VERSION 5.8 ;
BUSBITCHARS "[]" ;
DIVIDERCHAR "/" ;
UNITS
    DATABASE MICRONS 1000 ;
END UNITS

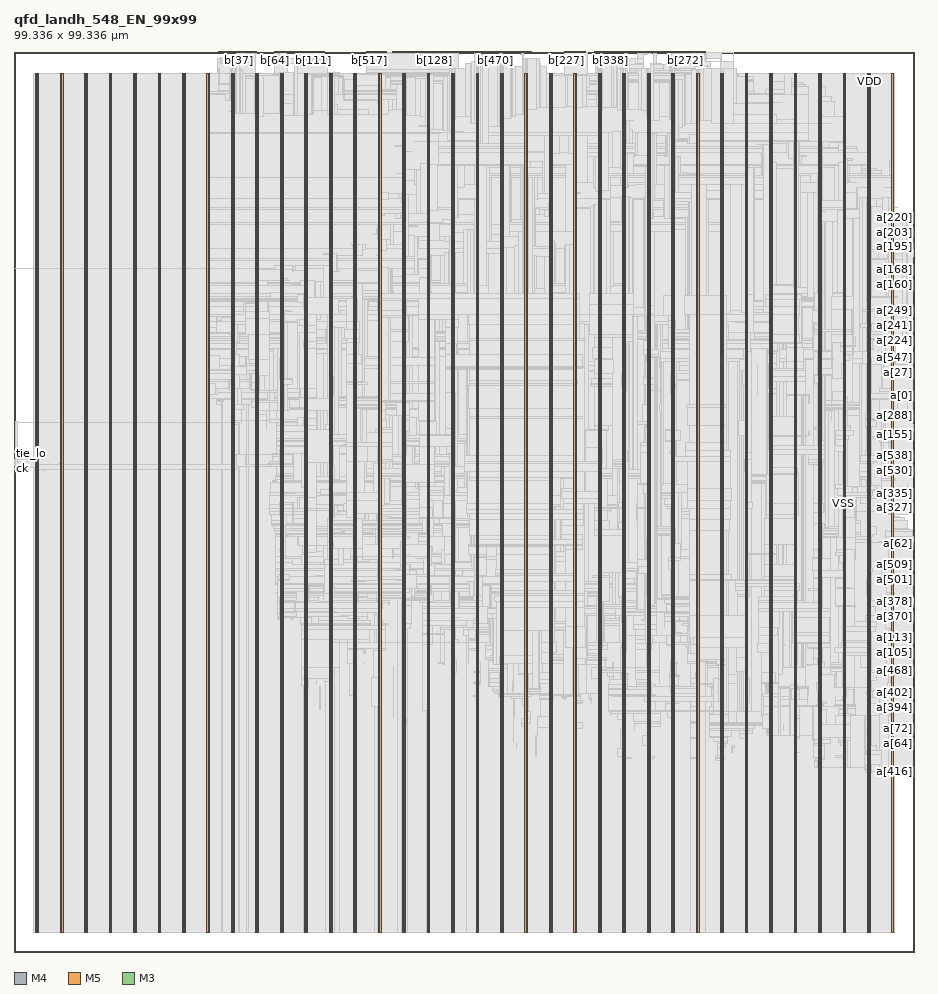
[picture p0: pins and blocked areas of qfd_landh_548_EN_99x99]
MACRO qfd_landh_548_EN_99x99
  FOREIGN qfd_landh_548_EN_99x99 0 0 ;
  CLASS BLOCK ;
  SIZE 99.336 BY 99.336 ;
  PIN a[0]
    DIRECTION INPUT ;
    USE SIGNAL ;
    PORT
      LAYER M4 ;
        RECT  99.252 61.392 99.336 61.416 ;
    END
  END a[0]
  PIN a[100]
    DIRECTION INPUT ;
    USE SIGNAL ;
    PORT
      LAYER M4 ;
        RECT  99.252 32.592 99.336 32.616 ;
    END
  END a[100]
  PIN a[101]
    DIRECTION INPUT ;
    USE SIGNAL ;
    PORT
      LAYER M4 ;
        RECT  99.252 32.688 99.336 32.712 ;
    END
  END a[101]
  PIN a[102]
    DIRECTION INPUT ;
    USE SIGNAL ;
    PORT
      LAYER M4 ;
        RECT  99.252 32.784 99.336 32.808 ;
    END
  END a[102]
  PIN a[103]
    DIRECTION INPUT ;
    USE SIGNAL ;
    PORT
      LAYER M4 ;
        RECT  99.252 32.88 99.336 32.904 ;
    END
  END a[103]
  PIN a[104]
    DIRECTION INPUT ;
    USE SIGNAL ;
    PORT
      LAYER M4 ;
        RECT  99.252 32.976 99.336 33 ;
    END
  END a[104]
  PIN a[105]
    DIRECTION INPUT ;
    USE SIGNAL ;
    PORT
      LAYER M4 ;
        RECT  99.252 33.072 99.336 33.096 ;
    END
  END a[105]
  PIN a[106]
    DIRECTION INPUT ;
    USE SIGNAL ;
    PORT
      LAYER M4 ;
        RECT  99.252 33.168 99.336 33.192 ;
    END
  END a[106]
  PIN a[107]
    DIRECTION INPUT ;
    USE SIGNAL ;
    PORT
      LAYER M4 ;
        RECT  99.252 33.264 99.336 33.288 ;
    END
  END a[107]
  PIN a[108]
    DIRECTION INPUT ;
    USE SIGNAL ;
    PORT
      LAYER M4 ;
        RECT  99.252 33.36 99.336 33.384 ;
    END
  END a[108]
  PIN a[109]
    DIRECTION INPUT ;
    USE SIGNAL ;
    PORT
      LAYER M4 ;
        RECT  99.252 33.456 99.336 33.48 ;
    END
  END a[109]
  PIN a[10]
    DIRECTION INPUT ;
    USE SIGNAL ;
    PORT
      LAYER M4 ;
        RECT  99.252 62.352 99.336 62.376 ;
    END
  END a[10]
  PIN a[110]
    DIRECTION INPUT ;
    USE SIGNAL ;
    PORT
      LAYER M4 ;
        RECT  99.252 33.552 99.336 33.576 ;
    END
  END a[110]
  PIN a[111]
    DIRECTION INPUT ;
    USE SIGNAL ;
    PORT
      LAYER M4 ;
        RECT  99.252 33.648 99.336 33.672 ;
    END
  END a[111]
  PIN a[112]
    DIRECTION INPUT ;
    USE SIGNAL ;
    PORT
      LAYER M4 ;
        RECT  99.252 33.744 99.336 33.768 ;
    END
  END a[112]
  PIN a[113]
    DIRECTION INPUT ;
    USE SIGNAL ;
    PORT
      LAYER M4 ;
        RECT  99.252 33.84 99.336 33.864 ;
    END
  END a[113]
  PIN a[114]
    DIRECTION INPUT ;
    USE SIGNAL ;
    PORT
      LAYER M4 ;
        RECT  99.252 33.936 99.336 33.96 ;
    END
  END a[114]
  PIN a[115]
    DIRECTION INPUT ;
    USE SIGNAL ;
    PORT
      LAYER M4 ;
        RECT  99.252 34.032 99.336 34.056 ;
    END
  END a[115]
  PIN a[116]
    DIRECTION INPUT ;
    USE SIGNAL ;
    PORT
      LAYER M4 ;
        RECT  99.252 34.128 99.336 34.152 ;
    END
  END a[116]
  PIN a[117]
    DIRECTION INPUT ;
    USE SIGNAL ;
    PORT
      LAYER M4 ;
        RECT  99.252 34.224 99.336 34.248 ;
    END
  END a[117]
  PIN a[118]
    DIRECTION INPUT ;
    USE SIGNAL ;
    PORT
      LAYER M4 ;
        RECT  99.252 34.32 99.336 34.344 ;
    END
  END a[118]
  PIN a[119]
    DIRECTION INPUT ;
    USE SIGNAL ;
    PORT
      LAYER M4 ;
        RECT  99.252 34.416 99.336 34.44 ;
    END
  END a[119]
  PIN a[11]
    DIRECTION INPUT ;
    USE SIGNAL ;
    PORT
      LAYER M4 ;
        RECT  99.252 62.448 99.336 62.472 ;
    END
  END a[11]
  PIN a[120]
    DIRECTION INPUT ;
    USE SIGNAL ;
    PORT
      LAYER M4 ;
        RECT  99.252 34.512 99.336 34.536 ;
    END
  END a[120]
  PIN a[121]
    DIRECTION INPUT ;
    USE SIGNAL ;
    PORT
      LAYER M4 ;
        RECT  99.252 34.608 99.336 34.632 ;
    END
  END a[121]
  PIN a[122]
    DIRECTION INPUT ;
    USE SIGNAL ;
    PORT
      LAYER M4 ;
        RECT  99.252 34.704 99.336 34.728 ;
    END
  END a[122]
  PIN a[123]
    DIRECTION INPUT ;
    USE SIGNAL ;
    PORT
      LAYER M4 ;
        RECT  99.252 34.8 99.336 34.824 ;
    END
  END a[123]
  PIN a[124]
    DIRECTION INPUT ;
    USE SIGNAL ;
    PORT
      LAYER M4 ;
        RECT  99.252 34.896 99.336 34.92 ;
    END
  END a[124]
  PIN a[125]
    DIRECTION INPUT ;
    USE SIGNAL ;
    PORT
      LAYER M4 ;
        RECT  99.252 34.992 99.336 35.016 ;
    END
  END a[125]
  PIN a[126]
    DIRECTION INPUT ;
    USE SIGNAL ;
    PORT
      LAYER M4 ;
        RECT  99.252 35.088 99.336 35.112 ;
    END
  END a[126]
  PIN a[127]
    DIRECTION INPUT ;
    USE SIGNAL ;
    PORT
      LAYER M4 ;
        RECT  99.252 35.184 99.336 35.208 ;
    END
  END a[127]
  PIN a[128]
    DIRECTION INPUT ;
    USE SIGNAL ;
    PORT
      LAYER M4 ;
        RECT  99.252 54.48 99.336 54.504 ;
    END
  END a[128]
  PIN a[129]
    DIRECTION INPUT ;
    USE SIGNAL ;
    PORT
      LAYER M4 ;
        RECT  99.252 54.576 99.336 54.6 ;
    END
  END a[129]
  PIN a[12]
    DIRECTION INPUT ;
    USE SIGNAL ;
    PORT
      LAYER M4 ;
        RECT  99.252 62.544 99.336 62.568 ;
    END
  END a[12]
  PIN a[130]
    DIRECTION INPUT ;
    USE SIGNAL ;
    PORT
      LAYER M4 ;
        RECT  99.252 54.672 99.336 54.696 ;
    END
  END a[130]
  PIN a[131]
    DIRECTION INPUT ;
    USE SIGNAL ;
    PORT
      LAYER M4 ;
        RECT  99.252 54.768 99.336 54.792 ;
    END
  END a[131]
  PIN a[132]
    DIRECTION INPUT ;
    USE SIGNAL ;
    PORT
      LAYER M4 ;
        RECT  99.252 54.864 99.336 54.888 ;
    END
  END a[132]
  PIN a[133]
    DIRECTION INPUT ;
    USE SIGNAL ;
    PORT
      LAYER M4 ;
        RECT  99.252 54.96 99.336 54.984 ;
    END
  END a[133]
  PIN a[134]
    DIRECTION INPUT ;
    USE SIGNAL ;
    PORT
      LAYER M4 ;
        RECT  99.252 55.056 99.336 55.08 ;
    END
  END a[134]
  PIN a[135]
    DIRECTION INPUT ;
    USE SIGNAL ;
    PORT
      LAYER M4 ;
        RECT  99.252 55.152 99.336 55.176 ;
    END
  END a[135]
  PIN a[136]
    DIRECTION INPUT ;
    USE SIGNAL ;
    PORT
      LAYER M4 ;
        RECT  99.252 55.248 99.336 55.272 ;
    END
  END a[136]
  PIN a[137]
    DIRECTION INPUT ;
    USE SIGNAL ;
    PORT
      LAYER M4 ;
        RECT  99.252 55.344 99.336 55.368 ;
    END
  END a[137]
  PIN a[138]
    DIRECTION INPUT ;
    USE SIGNAL ;
    PORT
      LAYER M4 ;
        RECT  99.252 55.44 99.336 55.464 ;
    END
  END a[138]
  PIN a[139]
    DIRECTION INPUT ;
    USE SIGNAL ;
    PORT
      LAYER M4 ;
        RECT  99.252 55.536 99.336 55.56 ;
    END
  END a[139]
  PIN a[13]
    DIRECTION INPUT ;
    USE SIGNAL ;
    PORT
      LAYER M4 ;
        RECT  99.252 62.64 99.336 62.664 ;
    END
  END a[13]
  PIN a[140]
    DIRECTION INPUT ;
    USE SIGNAL ;
    PORT
      LAYER M4 ;
        RECT  99.252 55.632 99.336 55.656 ;
    END
  END a[140]
  PIN a[141]
    DIRECTION INPUT ;
    USE SIGNAL ;
    PORT
      LAYER M4 ;
        RECT  99.252 55.728 99.336 55.752 ;
    END
  END a[141]
  PIN a[142]
    DIRECTION INPUT ;
    USE SIGNAL ;
    PORT
      LAYER M4 ;
        RECT  99.252 55.824 99.336 55.848 ;
    END
  END a[142]
  PIN a[143]
    DIRECTION INPUT ;
    USE SIGNAL ;
    PORT
      LAYER M4 ;
        RECT  99.252 55.92 99.336 55.944 ;
    END
  END a[143]
  PIN a[144]
    DIRECTION INPUT ;
    USE SIGNAL ;
    PORT
      LAYER M4 ;
        RECT  99.252 56.016 99.336 56.04 ;
    END
  END a[144]
  PIN a[145]
    DIRECTION INPUT ;
    USE SIGNAL ;
    PORT
      LAYER M4 ;
        RECT  99.252 56.112 99.336 56.136 ;
    END
  END a[145]
  PIN a[146]
    DIRECTION INPUT ;
    USE SIGNAL ;
    PORT
      LAYER M4 ;
        RECT  99.252 56.208 99.336 56.232 ;
    END
  END a[146]
  PIN a[147]
    DIRECTION INPUT ;
    USE SIGNAL ;
    PORT
      LAYER M4 ;
        RECT  99.252 56.304 99.336 56.328 ;
    END
  END a[147]
  PIN a[148]
    DIRECTION INPUT ;
    USE SIGNAL ;
    PORT
      LAYER M4 ;
        RECT  99.252 56.4 99.336 56.424 ;
    END
  END a[148]
  PIN a[149]
    DIRECTION INPUT ;
    USE SIGNAL ;
    PORT
      LAYER M4 ;
        RECT  99.252 56.496 99.336 56.52 ;
    END
  END a[149]
  PIN a[14]
    DIRECTION INPUT ;
    USE SIGNAL ;
    PORT
      LAYER M4 ;
        RECT  99.252 62.736 99.336 62.76 ;
    END
  END a[14]
  PIN a[150]
    DIRECTION INPUT ;
    USE SIGNAL ;
    PORT
      LAYER M4 ;
        RECT  99.252 56.592 99.336 56.616 ;
    END
  END a[150]
  PIN a[151]
    DIRECTION INPUT ;
    USE SIGNAL ;
    PORT
      LAYER M4 ;
        RECT  99.252 56.688 99.336 56.712 ;
    END
  END a[151]
  PIN a[152]
    DIRECTION INPUT ;
    USE SIGNAL ;
    PORT
      LAYER M4 ;
        RECT  99.252 56.784 99.336 56.808 ;
    END
  END a[152]
  PIN a[153]
    DIRECTION INPUT ;
    USE SIGNAL ;
    PORT
      LAYER M4 ;
        RECT  99.252 56.88 99.336 56.904 ;
    END
  END a[153]
  PIN a[154]
    DIRECTION INPUT ;
    USE SIGNAL ;
    PORT
      LAYER M4 ;
        RECT  99.252 56.976 99.336 57 ;
    END
  END a[154]
  PIN a[155]
    DIRECTION INPUT ;
    USE SIGNAL ;
    PORT
      LAYER M4 ;
        RECT  99.252 57.072 99.336 57.096 ;
    END
  END a[155]
  PIN a[156]
    DIRECTION INPUT ;
    USE SIGNAL ;
    PORT
      LAYER M4 ;
        RECT  99.252 57.168 99.336 57.192 ;
    END
  END a[156]
  PIN a[157]
    DIRECTION INPUT ;
    USE SIGNAL ;
    PORT
      LAYER M4 ;
        RECT  99.252 57.264 99.336 57.288 ;
    END
  END a[157]
  PIN a[158]
    DIRECTION INPUT ;
    USE SIGNAL ;
    PORT
      LAYER M4 ;
        RECT  99.252 57.36 99.336 57.384 ;
    END
  END a[158]
  PIN a[159]
    DIRECTION INPUT ;
    USE SIGNAL ;
    PORT
      LAYER M4 ;
        RECT  99.252 57.456 99.336 57.48 ;
    END
  END a[159]
  PIN a[15]
    DIRECTION INPUT ;
    USE SIGNAL ;
    PORT
      LAYER M4 ;
        RECT  99.252 62.832 99.336 62.856 ;
    END
  END a[15]
  PIN a[160]
    DIRECTION INPUT ;
    USE SIGNAL ;
    PORT
      LAYER M4 ;
        RECT  99.252 73.68 99.336 73.704 ;
    END
  END a[160]
  PIN a[161]
    DIRECTION INPUT ;
    USE SIGNAL ;
    PORT
      LAYER M4 ;
        RECT  99.252 73.776 99.336 73.8 ;
    END
  END a[161]
  PIN a[162]
    DIRECTION INPUT ;
    USE SIGNAL ;
    PORT
      LAYER M4 ;
        RECT  99.252 73.872 99.336 73.896 ;
    END
  END a[162]
  PIN a[163]
    DIRECTION INPUT ;
    USE SIGNAL ;
    PORT
      LAYER M4 ;
        RECT  99.252 73.968 99.336 73.992 ;
    END
  END a[163]
  PIN a[164]
    DIRECTION INPUT ;
    USE SIGNAL ;
    PORT
      LAYER M4 ;
        RECT  99.252 74.064 99.336 74.088 ;
    END
  END a[164]
  PIN a[165]
    DIRECTION INPUT ;
    USE SIGNAL ;
    PORT
      LAYER M4 ;
        RECT  99.252 74.16 99.336 74.184 ;
    END
  END a[165]
  PIN a[166]
    DIRECTION INPUT ;
    USE SIGNAL ;
    PORT
      LAYER M4 ;
        RECT  99.252 74.256 99.336 74.28 ;
    END
  END a[166]
  PIN a[167]
    DIRECTION INPUT ;
    USE SIGNAL ;
    PORT
      LAYER M4 ;
        RECT  99.252 74.352 99.336 74.376 ;
    END
  END a[167]
  PIN a[168]
    DIRECTION INPUT ;
    USE SIGNAL ;
    PORT
      LAYER M4 ;
        RECT  99.252 74.448 99.336 74.472 ;
    END
  END a[168]
  PIN a[169]
    DIRECTION INPUT ;
    USE SIGNAL ;
    PORT
      LAYER M4 ;
        RECT  99.252 74.544 99.336 74.568 ;
    END
  END a[169]
  PIN a[16]
    DIRECTION INPUT ;
    USE SIGNAL ;
    PORT
      LAYER M4 ;
        RECT  99.252 62.928 99.336 62.952 ;
    END
  END a[16]
  PIN a[170]
    DIRECTION INPUT ;
    USE SIGNAL ;
    PORT
      LAYER M4 ;
        RECT  99.252 74.64 99.336 74.664 ;
    END
  END a[170]
  PIN a[171]
    DIRECTION INPUT ;
    USE SIGNAL ;
    PORT
      LAYER M4 ;
        RECT  99.252 74.736 99.336 74.76 ;
    END
  END a[171]
  PIN a[172]
    DIRECTION INPUT ;
    USE SIGNAL ;
    PORT
      LAYER M4 ;
        RECT  99.252 74.832 99.336 74.856 ;
    END
  END a[172]
  PIN a[173]
    DIRECTION INPUT ;
    USE SIGNAL ;
    PORT
      LAYER M4 ;
        RECT  99.252 74.928 99.336 74.952 ;
    END
  END a[173]
  PIN a[174]
    DIRECTION INPUT ;
    USE SIGNAL ;
    PORT
      LAYER M4 ;
        RECT  99.252 75.024 99.336 75.048 ;
    END
  END a[174]
  PIN a[175]
    DIRECTION INPUT ;
    USE SIGNAL ;
    PORT
      LAYER M4 ;
        RECT  99.252 75.12 99.336 75.144 ;
    END
  END a[175]
  PIN a[176]
    DIRECTION INPUT ;
    USE SIGNAL ;
    PORT
      LAYER M4 ;
        RECT  99.252 75.216 99.336 75.24 ;
    END
  END a[176]
  PIN a[177]
    DIRECTION INPUT ;
    USE SIGNAL ;
    PORT
      LAYER M4 ;
        RECT  99.252 75.312 99.336 75.336 ;
    END
  END a[177]
  PIN a[178]
    DIRECTION INPUT ;
    USE SIGNAL ;
    PORT
      LAYER M4 ;
        RECT  99.252 75.408 99.336 75.432 ;
    END
  END a[178]
  PIN a[179]
    DIRECTION INPUT ;
    USE SIGNAL ;
    PORT
      LAYER M4 ;
        RECT  99.252 75.504 99.336 75.528 ;
    END
  END a[179]
  PIN a[17]
    DIRECTION INPUT ;
    USE SIGNAL ;
    PORT
      LAYER M4 ;
        RECT  99.252 63.024 99.336 63.048 ;
    END
  END a[17]
  PIN a[180]
    DIRECTION INPUT ;
    USE SIGNAL ;
    PORT
      LAYER M4 ;
        RECT  99.252 75.6 99.336 75.624 ;
    END
  END a[180]
  PIN a[181]
    DIRECTION INPUT ;
    USE SIGNAL ;
    PORT
      LAYER M4 ;
        RECT  99.252 75.696 99.336 75.72 ;
    END
  END a[181]
  PIN a[182]
    DIRECTION INPUT ;
    USE SIGNAL ;
    PORT
      LAYER M4 ;
        RECT  99.252 75.792 99.336 75.816 ;
    END
  END a[182]
  PIN a[183]
    DIRECTION INPUT ;
    USE SIGNAL ;
    PORT
      LAYER M4 ;
        RECT  99.252 75.888 99.336 75.912 ;
    END
  END a[183]
  PIN a[184]
    DIRECTION INPUT ;
    USE SIGNAL ;
    PORT
      LAYER M4 ;
        RECT  99.252 75.984 99.336 76.008 ;
    END
  END a[184]
  PIN a[185]
    DIRECTION INPUT ;
    USE SIGNAL ;
    PORT
      LAYER M4 ;
        RECT  99.252 76.08 99.336 76.104 ;
    END
  END a[185]
  PIN a[186]
    DIRECTION INPUT ;
    USE SIGNAL ;
    PORT
      LAYER M4 ;
        RECT  99.252 76.176 99.336 76.2 ;
    END
  END a[186]
  PIN a[187]
    DIRECTION INPUT ;
    USE SIGNAL ;
    PORT
      LAYER M4 ;
        RECT  99.252 76.272 99.336 76.296 ;
    END
  END a[187]
  PIN a[188]
    DIRECTION INPUT ;
    USE SIGNAL ;
    PORT
      LAYER M4 ;
        RECT  99.252 76.368 99.336 76.392 ;
    END
  END a[188]
  PIN a[189]
    DIRECTION INPUT ;
    USE SIGNAL ;
    PORT
      LAYER M4 ;
        RECT  99.252 76.464 99.336 76.488 ;
    END
  END a[189]
  PIN a[18]
    DIRECTION INPUT ;
    USE SIGNAL ;
    PORT
      LAYER M4 ;
        RECT  99.252 63.12 99.336 63.144 ;
    END
  END a[18]
  PIN a[190]
    DIRECTION INPUT ;
    USE SIGNAL ;
    PORT
      LAYER M4 ;
        RECT  99.252 76.56 99.336 76.584 ;
    END
  END a[190]
  PIN a[191]
    DIRECTION INPUT ;
    USE SIGNAL ;
    PORT
      LAYER M4 ;
        RECT  99.252 76.656 99.336 76.68 ;
    END
  END a[191]
  PIN a[192]
    DIRECTION INPUT ;
    USE SIGNAL ;
    PORT
      LAYER M4 ;
        RECT  99.252 77.52 99.336 77.544 ;
    END
  END a[192]
  PIN a[193]
    DIRECTION INPUT ;
    USE SIGNAL ;
    PORT
      LAYER M4 ;
        RECT  99.252 77.616 99.336 77.64 ;
    END
  END a[193]
  PIN a[194]
    DIRECTION INPUT ;
    USE SIGNAL ;
    PORT
      LAYER M4 ;
        RECT  99.252 77.712 99.336 77.736 ;
    END
  END a[194]
  PIN a[195]
    DIRECTION INPUT ;
    USE SIGNAL ;
    PORT
      LAYER M4 ;
        RECT  99.252 77.808 99.336 77.832 ;
    END
  END a[195]
  PIN a[196]
    DIRECTION INPUT ;
    USE SIGNAL ;
    PORT
      LAYER M4 ;
        RECT  99.252 77.904 99.336 77.928 ;
    END
  END a[196]
  PIN a[197]
    DIRECTION INPUT ;
    USE SIGNAL ;
    PORT
      LAYER M4 ;
        RECT  99.252 78 99.336 78.024 ;
    END
  END a[197]
  PIN a[198]
    DIRECTION INPUT ;
    USE SIGNAL ;
    PORT
      LAYER M4 ;
        RECT  99.252 78.096 99.336 78.12 ;
    END
  END a[198]
  PIN a[199]
    DIRECTION INPUT ;
    USE SIGNAL ;
    PORT
      LAYER M4 ;
        RECT  99.252 78.192 99.336 78.216 ;
    END
  END a[199]
  PIN a[19]
    DIRECTION INPUT ;
    USE SIGNAL ;
    PORT
      LAYER M4 ;
        RECT  99.252 63.216 99.336 63.24 ;
    END
  END a[19]
  PIN a[1]
    DIRECTION INPUT ;
    USE SIGNAL ;
    PORT
      LAYER M4 ;
        RECT  99.252 61.488 99.336 61.512 ;
    END
  END a[1]
  PIN a[200]
    DIRECTION INPUT ;
    USE SIGNAL ;
    PORT
      LAYER M4 ;
        RECT  99.252 78.288 99.336 78.312 ;
    END
  END a[200]
  PIN a[201]
    DIRECTION INPUT ;
    USE SIGNAL ;
    PORT
      LAYER M4 ;
        RECT  99.252 78.384 99.336 78.408 ;
    END
  END a[201]
  PIN a[202]
    DIRECTION INPUT ;
    USE SIGNAL ;
    PORT
      LAYER M4 ;
        RECT  99.252 78.48 99.336 78.504 ;
    END
  END a[202]
  PIN a[203]
    DIRECTION INPUT ;
    USE SIGNAL ;
    PORT
      LAYER M4 ;
        RECT  99.252 78.576 99.336 78.6 ;
    END
  END a[203]
  PIN a[204]
    DIRECTION INPUT ;
    USE SIGNAL ;
    PORT
      LAYER M4 ;
        RECT  99.252 78.672 99.336 78.696 ;
    END
  END a[204]
  PIN a[205]
    DIRECTION INPUT ;
    USE SIGNAL ;
    PORT
      LAYER M4 ;
        RECT  99.252 78.768 99.336 78.792 ;
    END
  END a[205]
  PIN a[206]
    DIRECTION INPUT ;
    USE SIGNAL ;
    PORT
      LAYER M4 ;
        RECT  99.252 78.864 99.336 78.888 ;
    END
  END a[206]
  PIN a[207]
    DIRECTION INPUT ;
    USE SIGNAL ;
    PORT
      LAYER M4 ;
        RECT  99.252 78.96 99.336 78.984 ;
    END
  END a[207]
  PIN a[208]
    DIRECTION INPUT ;
    USE SIGNAL ;
    PORT
      LAYER M4 ;
        RECT  99.252 79.056 99.336 79.08 ;
    END
  END a[208]
  PIN a[209]
    DIRECTION INPUT ;
    USE SIGNAL ;
    PORT
      LAYER M4 ;
        RECT  99.252 79.152 99.336 79.176 ;
    END
  END a[209]
  PIN a[20]
    DIRECTION INPUT ;
    USE SIGNAL ;
    PORT
      LAYER M4 ;
        RECT  99.252 63.312 99.336 63.336 ;
    END
  END a[20]
  PIN a[210]
    DIRECTION INPUT ;
    USE SIGNAL ;
    PORT
      LAYER M4 ;
        RECT  99.252 79.248 99.336 79.272 ;
    END
  END a[210]
  PIN a[211]
    DIRECTION INPUT ;
    USE SIGNAL ;
    PORT
      LAYER M4 ;
        RECT  99.252 79.344 99.336 79.368 ;
    END
  END a[211]
  PIN a[212]
    DIRECTION INPUT ;
    USE SIGNAL ;
    PORT
      LAYER M4 ;
        RECT  99.252 79.44 99.336 79.464 ;
    END
  END a[212]
  PIN a[213]
    DIRECTION INPUT ;
    USE SIGNAL ;
    PORT
      LAYER M4 ;
        RECT  99.252 79.536 99.336 79.56 ;
    END
  END a[213]
  PIN a[214]
    DIRECTION INPUT ;
    USE SIGNAL ;
    PORT
      LAYER M4 ;
        RECT  99.252 79.632 99.336 79.656 ;
    END
  END a[214]
  PIN a[215]
    DIRECTION INPUT ;
    USE SIGNAL ;
    PORT
      LAYER M4 ;
        RECT  99.252 79.728 99.336 79.752 ;
    END
  END a[215]
  PIN a[216]
    DIRECTION INPUT ;
    USE SIGNAL ;
    PORT
      LAYER M4 ;
        RECT  99.252 79.824 99.336 79.848 ;
    END
  END a[216]
  PIN a[217]
    DIRECTION INPUT ;
    USE SIGNAL ;
    PORT
      LAYER M4 ;
        RECT  99.252 79.92 99.336 79.944 ;
    END
  END a[217]
  PIN a[218]
    DIRECTION INPUT ;
    USE SIGNAL ;
    PORT
      LAYER M4 ;
        RECT  99.252 80.016 99.336 80.04 ;
    END
  END a[218]
  PIN a[219]
    DIRECTION INPUT ;
    USE SIGNAL ;
    PORT
      LAYER M4 ;
        RECT  99.252 80.112 99.336 80.136 ;
    END
  END a[219]
  PIN a[21]
    DIRECTION INPUT ;
    USE SIGNAL ;
    PORT
      LAYER M4 ;
        RECT  99.252 63.408 99.336 63.432 ;
    END
  END a[21]
  PIN a[220]
    DIRECTION INPUT ;
    USE SIGNAL ;
    PORT
      LAYER M4 ;
        RECT  99.252 80.208 99.336 80.232 ;
    END
  END a[220]
  PIN a[221]
    DIRECTION INPUT ;
    USE SIGNAL ;
    PORT
      LAYER M4 ;
        RECT  99.252 80.304 99.336 80.328 ;
    END
  END a[221]
  PIN a[222]
    DIRECTION INPUT ;
    USE SIGNAL ;
    PORT
      LAYER M4 ;
        RECT  99.252 80.4 99.336 80.424 ;
    END
  END a[222]
  PIN a[223]
    DIRECTION INPUT ;
    USE SIGNAL ;
    PORT
      LAYER M4 ;
        RECT  99.252 80.496 99.336 80.52 ;
    END
  END a[223]
  PIN a[224]
    DIRECTION INPUT ;
    USE SIGNAL ;
    PORT
      LAYER M4 ;
        RECT  99.252 67.536 99.336 67.56 ;
    END
  END a[224]
  PIN a[225]
    DIRECTION INPUT ;
    USE SIGNAL ;
    PORT
      LAYER M4 ;
        RECT  99.252 67.632 99.336 67.656 ;
    END
  END a[225]
  PIN a[226]
    DIRECTION INPUT ;
    USE SIGNAL ;
    PORT
      LAYER M4 ;
        RECT  99.252 67.728 99.336 67.752 ;
    END
  END a[226]
  PIN a[227]
    DIRECTION INPUT ;
    USE SIGNAL ;
    PORT
      LAYER M4 ;
        RECT  99.252 67.824 99.336 67.848 ;
    END
  END a[227]
  PIN a[228]
    DIRECTION INPUT ;
    USE SIGNAL ;
    PORT
      LAYER M4 ;
        RECT  99.252 67.92 99.336 67.944 ;
    END
  END a[228]
  PIN a[229]
    DIRECTION INPUT ;
    USE SIGNAL ;
    PORT
      LAYER M4 ;
        RECT  99.252 68.016 99.336 68.04 ;
    END
  END a[229]
  PIN a[22]
    DIRECTION INPUT ;
    USE SIGNAL ;
    PORT
      LAYER M4 ;
        RECT  99.252 63.504 99.336 63.528 ;
    END
  END a[22]
  PIN a[230]
    DIRECTION INPUT ;
    USE SIGNAL ;
    PORT
      LAYER M4 ;
        RECT  99.252 68.112 99.336 68.136 ;
    END
  END a[230]
  PIN a[231]
    DIRECTION INPUT ;
    USE SIGNAL ;
    PORT
      LAYER M4 ;
        RECT  99.252 68.208 99.336 68.232 ;
    END
  END a[231]
  PIN a[232]
    DIRECTION INPUT ;
    USE SIGNAL ;
    PORT
      LAYER M4 ;
        RECT  99.252 68.304 99.336 68.328 ;
    END
  END a[232]
  PIN a[233]
    DIRECTION INPUT ;
    USE SIGNAL ;
    PORT
      LAYER M4 ;
        RECT  99.252 68.4 99.336 68.424 ;
    END
  END a[233]
  PIN a[234]
    DIRECTION INPUT ;
    USE SIGNAL ;
    PORT
      LAYER M4 ;
        RECT  99.252 68.496 99.336 68.52 ;
    END
  END a[234]
  PIN a[235]
    DIRECTION INPUT ;
    USE SIGNAL ;
    PORT
      LAYER M4 ;
        RECT  99.252 68.592 99.336 68.616 ;
    END
  END a[235]
  PIN a[236]
    DIRECTION INPUT ;
    USE SIGNAL ;
    PORT
      LAYER M4 ;
        RECT  99.252 68.688 99.336 68.712 ;
    END
  END a[236]
  PIN a[237]
    DIRECTION INPUT ;
    USE SIGNAL ;
    PORT
      LAYER M4 ;
        RECT  99.252 68.784 99.336 68.808 ;
    END
  END a[237]
  PIN a[238]
    DIRECTION INPUT ;
    USE SIGNAL ;
    PORT
      LAYER M4 ;
        RECT  99.252 68.88 99.336 68.904 ;
    END
  END a[238]
  PIN a[239]
    DIRECTION INPUT ;
    USE SIGNAL ;
    PORT
      LAYER M4 ;
        RECT  99.252 68.976 99.336 69 ;
    END
  END a[239]
  PIN a[23]
    DIRECTION INPUT ;
    USE SIGNAL ;
    PORT
      LAYER M4 ;
        RECT  99.252 63.6 99.336 63.624 ;
    END
  END a[23]
  PIN a[240]
    DIRECTION INPUT ;
    USE SIGNAL ;
    PORT
      LAYER M4 ;
        RECT  99.252 69.072 99.336 69.096 ;
    END
  END a[240]
  PIN a[241]
    DIRECTION INPUT ;
    USE SIGNAL ;
    PORT
      LAYER M4 ;
        RECT  99.252 69.168 99.336 69.192 ;
    END
  END a[241]
  PIN a[242]
    DIRECTION INPUT ;
    USE SIGNAL ;
    PORT
      LAYER M4 ;
        RECT  99.252 69.264 99.336 69.288 ;
    END
  END a[242]
  PIN a[243]
    DIRECTION INPUT ;
    USE SIGNAL ;
    PORT
      LAYER M4 ;
        RECT  99.252 69.36 99.336 69.384 ;
    END
  END a[243]
  PIN a[244]
    DIRECTION INPUT ;
    USE SIGNAL ;
    PORT
      LAYER M4 ;
        RECT  99.252 69.456 99.336 69.48 ;
    END
  END a[244]
  PIN a[245]
    DIRECTION INPUT ;
    USE SIGNAL ;
    PORT
      LAYER M4 ;
        RECT  99.252 69.552 99.336 69.576 ;
    END
  END a[245]
  PIN a[246]
    DIRECTION INPUT ;
    USE SIGNAL ;
    PORT
      LAYER M4 ;
        RECT  99.252 69.648 99.336 69.672 ;
    END
  END a[246]
  PIN a[247]
    DIRECTION INPUT ;
    USE SIGNAL ;
    PORT
      LAYER M4 ;
        RECT  99.252 69.744 99.336 69.768 ;
    END
  END a[247]
  PIN a[248]
    DIRECTION INPUT ;
    USE SIGNAL ;
    PORT
      LAYER M4 ;
        RECT  99.252 69.84 99.336 69.864 ;
    END
  END a[248]
  PIN a[249]
    DIRECTION INPUT ;
    USE SIGNAL ;
    PORT
      LAYER M4 ;
        RECT  99.252 69.936 99.336 69.96 ;
    END
  END a[249]
  PIN a[24]
    DIRECTION INPUT ;
    USE SIGNAL ;
    PORT
      LAYER M4 ;
        RECT  99.252 63.696 99.336 63.72 ;
    END
  END a[24]
  PIN a[250]
    DIRECTION INPUT ;
    USE SIGNAL ;
    PORT
      LAYER M4 ;
        RECT  99.252 70.032 99.336 70.056 ;
    END
  END a[250]
  PIN a[251]
    DIRECTION INPUT ;
    USE SIGNAL ;
    PORT
      LAYER M4 ;
        RECT  99.252 70.128 99.336 70.152 ;
    END
  END a[251]
  PIN a[252]
    DIRECTION INPUT ;
    USE SIGNAL ;
    PORT
      LAYER M4 ;
        RECT  99.252 70.224 99.336 70.248 ;
    END
  END a[252]
  PIN a[253]
    DIRECTION INPUT ;
    USE SIGNAL ;
    PORT
      LAYER M4 ;
        RECT  99.252 70.32 99.336 70.344 ;
    END
  END a[253]
  PIN a[254]
    DIRECTION INPUT ;
    USE SIGNAL ;
    PORT
      LAYER M4 ;
        RECT  99.252 70.416 99.336 70.44 ;
    END
  END a[254]
  PIN a[255]
    DIRECTION INPUT ;
    USE SIGNAL ;
    PORT
      LAYER M4 ;
        RECT  99.252 70.512 99.336 70.536 ;
    END
  END a[255]
  PIN a[256]
    DIRECTION INPUT ;
    USE SIGNAL ;
    PORT
      LAYER M4 ;
        RECT  99.252 70.608 99.336 70.632 ;
    END
  END a[256]
  PIN a[257]
    DIRECTION INPUT ;
    USE SIGNAL ;
    PORT
      LAYER M4 ;
        RECT  99.252 70.704 99.336 70.728 ;
    END
  END a[257]
  PIN a[258]
    DIRECTION INPUT ;
    USE SIGNAL ;
    PORT
      LAYER M4 ;
        RECT  99.252 70.8 99.336 70.824 ;
    END
  END a[258]
  PIN a[259]
    DIRECTION INPUT ;
    USE SIGNAL ;
    PORT
      LAYER M4 ;
        RECT  99.252 70.896 99.336 70.92 ;
    END
  END a[259]
  PIN a[25]
    DIRECTION INPUT ;
    USE SIGNAL ;
    PORT
      LAYER M4 ;
        RECT  99.252 63.792 99.336 63.816 ;
    END
  END a[25]
  PIN a[260]
    DIRECTION INPUT ;
    USE SIGNAL ;
    PORT
      LAYER M4 ;
        RECT  99.252 70.992 99.336 71.016 ;
    END
  END a[260]
  PIN a[261]
    DIRECTION INPUT ;
    USE SIGNAL ;
    PORT
      LAYER M4 ;
        RECT  99.252 71.088 99.336 71.112 ;
    END
  END a[261]
  PIN a[262]
    DIRECTION INPUT ;
    USE SIGNAL ;
    PORT
      LAYER M4 ;
        RECT  99.252 71.184 99.336 71.208 ;
    END
  END a[262]
  PIN a[263]
    DIRECTION INPUT ;
    USE SIGNAL ;
    PORT
      LAYER M4 ;
        RECT  99.252 71.28 99.336 71.304 ;
    END
  END a[263]
  PIN a[264]
    DIRECTION INPUT ;
    USE SIGNAL ;
    PORT
      LAYER M4 ;
        RECT  99.252 71.376 99.336 71.4 ;
    END
  END a[264]
  PIN a[265]
    DIRECTION INPUT ;
    USE SIGNAL ;
    PORT
      LAYER M4 ;
        RECT  99.252 71.472 99.336 71.496 ;
    END
  END a[265]
  PIN a[266]
    DIRECTION INPUT ;
    USE SIGNAL ;
    PORT
      LAYER M4 ;
        RECT  99.252 71.568 99.336 71.592 ;
    END
  END a[266]
  PIN a[267]
    DIRECTION INPUT ;
    USE SIGNAL ;
    PORT
      LAYER M4 ;
        RECT  99.252 71.664 99.336 71.688 ;
    END
  END a[267]
  PIN a[268]
    DIRECTION INPUT ;
    USE SIGNAL ;
    PORT
      LAYER M4 ;
        RECT  99.252 71.76 99.336 71.784 ;
    END
  END a[268]
  PIN a[269]
    DIRECTION INPUT ;
    USE SIGNAL ;
    PORT
      LAYER M4 ;
        RECT  99.252 71.856 99.336 71.88 ;
    END
  END a[269]
  PIN a[26]
    DIRECTION INPUT ;
    USE SIGNAL ;
    PORT
      LAYER M4 ;
        RECT  99.252 63.888 99.336 63.912 ;
    END
  END a[26]
  PIN a[270]
    DIRECTION INPUT ;
    USE SIGNAL ;
    PORT
      LAYER M4 ;
        RECT  99.252 71.952 99.336 71.976 ;
    END
  END a[270]
  PIN a[271]
    DIRECTION INPUT ;
    USE SIGNAL ;
    PORT
      LAYER M4 ;
        RECT  99.252 72.048 99.336 72.072 ;
    END
  END a[271]
  PIN a[272]
    DIRECTION INPUT ;
    USE SIGNAL ;
    PORT
      LAYER M4 ;
        RECT  99.252 72.144 99.336 72.168 ;
    END
  END a[272]
  PIN a[273]
    DIRECTION INPUT ;
    USE SIGNAL ;
    PORT
      LAYER M4 ;
        RECT  99.252 72.24 99.336 72.264 ;
    END
  END a[273]
  PIN a[274]
    DIRECTION INPUT ;
    USE SIGNAL ;
    PORT
      LAYER M4 ;
        RECT  99.252 72.336 99.336 72.36 ;
    END
  END a[274]
  PIN a[275]
    DIRECTION INPUT ;
    USE SIGNAL ;
    PORT
      LAYER M4 ;
        RECT  99.252 72.432 99.336 72.456 ;
    END
  END a[275]
  PIN a[276]
    DIRECTION INPUT ;
    USE SIGNAL ;
    PORT
      LAYER M4 ;
        RECT  99.252 72.528 99.336 72.552 ;
    END
  END a[276]
  PIN a[277]
    DIRECTION INPUT ;
    USE SIGNAL ;
    PORT
      LAYER M4 ;
        RECT  99.252 72.624 99.336 72.648 ;
    END
  END a[277]
  PIN a[278]
    DIRECTION INPUT ;
    USE SIGNAL ;
    PORT
      LAYER M4 ;
        RECT  99.252 72.72 99.336 72.744 ;
    END
  END a[278]
  PIN a[279]
    DIRECTION INPUT ;
    USE SIGNAL ;
    PORT
      LAYER M4 ;
        RECT  99.252 72.816 99.336 72.84 ;
    END
  END a[279]
  PIN a[27]
    DIRECTION INPUT ;
    USE SIGNAL ;
    PORT
      LAYER M4 ;
        RECT  99.252 63.984 99.336 64.008 ;
    END
  END a[27]
  PIN a[280]
    DIRECTION INPUT ;
    USE SIGNAL ;
    PORT
      LAYER M4 ;
        RECT  99.252 72.912 99.336 72.936 ;
    END
  END a[280]
  PIN a[281]
    DIRECTION INPUT ;
    USE SIGNAL ;
    PORT
      LAYER M4 ;
        RECT  99.252 73.008 99.336 73.032 ;
    END
  END a[281]
  PIN a[282]
    DIRECTION INPUT ;
    USE SIGNAL ;
    PORT
      LAYER M4 ;
        RECT  99.252 73.104 99.336 73.128 ;
    END
  END a[282]
  PIN a[283]
    DIRECTION INPUT ;
    USE SIGNAL ;
    PORT
      LAYER M4 ;
        RECT  99.252 73.2 99.336 73.224 ;
    END
  END a[283]
  PIN a[284]
    DIRECTION INPUT ;
    USE SIGNAL ;
    PORT
      LAYER M4 ;
        RECT  99.252 73.296 99.336 73.32 ;
    END
  END a[284]
  PIN a[285]
    DIRECTION INPUT ;
    USE SIGNAL ;
    PORT
      LAYER M4 ;
        RECT  99.252 73.392 99.336 73.416 ;
    END
  END a[285]
  PIN a[286]
    DIRECTION INPUT ;
    USE SIGNAL ;
    PORT
      LAYER M4 ;
        RECT  99.252 73.488 99.336 73.512 ;
    END
  END a[286]
  PIN a[287]
    DIRECTION INPUT ;
    USE SIGNAL ;
    PORT
      LAYER M4 ;
        RECT  99.252 73.584 99.336 73.608 ;
    END
  END a[287]
  PIN a[288]
    DIRECTION INPUT ;
    USE SIGNAL ;
    PORT
      LAYER M4 ;
        RECT  99.252 58.32 99.336 58.344 ;
    END
  END a[288]
  PIN a[289]
    DIRECTION INPUT ;
    USE SIGNAL ;
    PORT
      LAYER M4 ;
        RECT  99.252 58.416 99.336 58.44 ;
    END
  END a[289]
  PIN a[28]
    DIRECTION INPUT ;
    USE SIGNAL ;
    PORT
      LAYER M4 ;
        RECT  99.252 64.08 99.336 64.104 ;
    END
  END a[28]
  PIN a[290]
    DIRECTION INPUT ;
    USE SIGNAL ;
    PORT
      LAYER M4 ;
        RECT  99.252 58.512 99.336 58.536 ;
    END
  END a[290]
  PIN a[291]
    DIRECTION INPUT ;
    USE SIGNAL ;
    PORT
      LAYER M4 ;
        RECT  99.252 58.608 99.336 58.632 ;
    END
  END a[291]
  PIN a[292]
    DIRECTION INPUT ;
    USE SIGNAL ;
    PORT
      LAYER M4 ;
        RECT  99.252 58.704 99.336 58.728 ;
    END
  END a[292]
  PIN a[293]
    DIRECTION INPUT ;
    USE SIGNAL ;
    PORT
      LAYER M4 ;
        RECT  99.252 58.8 99.336 58.824 ;
    END
  END a[293]
  PIN a[294]
    DIRECTION INPUT ;
    USE SIGNAL ;
    PORT
      LAYER M4 ;
        RECT  99.252 58.896 99.336 58.92 ;
    END
  END a[294]
  PIN a[295]
    DIRECTION INPUT ;
    USE SIGNAL ;
    PORT
      LAYER M4 ;
        RECT  99.252 58.992 99.336 59.016 ;
    END
  END a[295]
  PIN a[296]
    DIRECTION INPUT ;
    USE SIGNAL ;
    PORT
      LAYER M4 ;
        RECT  99.252 59.088 99.336 59.112 ;
    END
  END a[296]
  PIN a[297]
    DIRECTION INPUT ;
    USE SIGNAL ;
    PORT
      LAYER M4 ;
        RECT  99.252 59.184 99.336 59.208 ;
    END
  END a[297]
  PIN a[298]
    DIRECTION INPUT ;
    USE SIGNAL ;
    PORT
      LAYER M4 ;
        RECT  99.252 59.28 99.336 59.304 ;
    END
  END a[298]
  PIN a[299]
    DIRECTION INPUT ;
    USE SIGNAL ;
    PORT
      LAYER M4 ;
        RECT  99.252 59.376 99.336 59.4 ;
    END
  END a[299]
  PIN a[29]
    DIRECTION INPUT ;
    USE SIGNAL ;
    PORT
      LAYER M4 ;
        RECT  99.252 64.176 99.336 64.2 ;
    END
  END a[29]
  PIN a[2]
    DIRECTION INPUT ;
    USE SIGNAL ;
    PORT
      LAYER M4 ;
        RECT  99.252 61.584 99.336 61.608 ;
    END
  END a[2]
  PIN a[300]
    DIRECTION INPUT ;
    USE SIGNAL ;
    PORT
      LAYER M4 ;
        RECT  99.252 59.472 99.336 59.496 ;
    END
  END a[300]
  PIN a[301]
    DIRECTION INPUT ;
    USE SIGNAL ;
    PORT
      LAYER M4 ;
        RECT  99.252 59.568 99.336 59.592 ;
    END
  END a[301]
  PIN a[302]
    DIRECTION INPUT ;
    USE SIGNAL ;
    PORT
      LAYER M4 ;
        RECT  99.252 59.664 99.336 59.688 ;
    END
  END a[302]
  PIN a[303]
    DIRECTION INPUT ;
    USE SIGNAL ;
    PORT
      LAYER M4 ;
        RECT  99.252 59.76 99.336 59.784 ;
    END
  END a[303]
  PIN a[304]
    DIRECTION INPUT ;
    USE SIGNAL ;
    PORT
      LAYER M4 ;
        RECT  99.252 59.856 99.336 59.88 ;
    END
  END a[304]
  PIN a[305]
    DIRECTION INPUT ;
    USE SIGNAL ;
    PORT
      LAYER M4 ;
        RECT  99.252 59.952 99.336 59.976 ;
    END
  END a[305]
  PIN a[306]
    DIRECTION INPUT ;
    USE SIGNAL ;
    PORT
      LAYER M4 ;
        RECT  99.252 60.048 99.336 60.072 ;
    END
  END a[306]
  PIN a[307]
    DIRECTION INPUT ;
    USE SIGNAL ;
    PORT
      LAYER M4 ;
        RECT  99.252 60.144 99.336 60.168 ;
    END
  END a[307]
  PIN a[308]
    DIRECTION INPUT ;
    USE SIGNAL ;
    PORT
      LAYER M4 ;
        RECT  99.252 60.24 99.336 60.264 ;
    END
  END a[308]
  PIN a[309]
    DIRECTION INPUT ;
    USE SIGNAL ;
    PORT
      LAYER M4 ;
        RECT  99.252 60.336 99.336 60.36 ;
    END
  END a[309]
  PIN a[30]
    DIRECTION INPUT ;
    USE SIGNAL ;
    PORT
      LAYER M4 ;
        RECT  99.252 64.272 99.336 64.296 ;
    END
  END a[30]
  PIN a[310]
    DIRECTION INPUT ;
    USE SIGNAL ;
    PORT
      LAYER M4 ;
        RECT  99.252 60.432 99.336 60.456 ;
    END
  END a[310]
  PIN a[311]
    DIRECTION INPUT ;
    USE SIGNAL ;
    PORT
      LAYER M4 ;
        RECT  99.252 60.528 99.336 60.552 ;
    END
  END a[311]
  PIN a[312]
    DIRECTION INPUT ;
    USE SIGNAL ;
    PORT
      LAYER M4 ;
        RECT  99.252 60.624 99.336 60.648 ;
    END
  END a[312]
  PIN a[313]
    DIRECTION INPUT ;
    USE SIGNAL ;
    PORT
      LAYER M4 ;
        RECT  99.252 60.72 99.336 60.744 ;
    END
  END a[313]
  PIN a[314]
    DIRECTION INPUT ;
    USE SIGNAL ;
    PORT
      LAYER M4 ;
        RECT  99.252 60.816 99.336 60.84 ;
    END
  END a[314]
  PIN a[315]
    DIRECTION INPUT ;
    USE SIGNAL ;
    PORT
      LAYER M4 ;
        RECT  99.252 60.912 99.336 60.936 ;
    END
  END a[315]
  PIN a[316]
    DIRECTION INPUT ;
    USE SIGNAL ;
    PORT
      LAYER M4 ;
        RECT  99.252 61.008 99.336 61.032 ;
    END
  END a[316]
  PIN a[317]
    DIRECTION INPUT ;
    USE SIGNAL ;
    PORT
      LAYER M4 ;
        RECT  99.252 61.104 99.336 61.128 ;
    END
  END a[317]
  PIN a[318]
    DIRECTION INPUT ;
    USE SIGNAL ;
    PORT
      LAYER M4 ;
        RECT  99.252 61.2 99.336 61.224 ;
    END
  END a[318]
  PIN a[319]
    DIRECTION INPUT ;
    USE SIGNAL ;
    PORT
      LAYER M4 ;
        RECT  99.252 61.296 99.336 61.32 ;
    END
  END a[319]
  PIN a[31]
    DIRECTION INPUT ;
    USE SIGNAL ;
    PORT
      LAYER M4 ;
        RECT  99.252 64.368 99.336 64.392 ;
    END
  END a[31]
  PIN a[320]
    DIRECTION INPUT ;
    USE SIGNAL ;
    PORT
      LAYER M4 ;
        RECT  99.252 48.336 99.336 48.36 ;
    END
  END a[320]
  PIN a[321]
    DIRECTION INPUT ;
    USE SIGNAL ;
    PORT
      LAYER M4 ;
        RECT  99.252 48.432 99.336 48.456 ;
    END
  END a[321]
  PIN a[322]
    DIRECTION INPUT ;
    USE SIGNAL ;
    PORT
      LAYER M4 ;
        RECT  99.252 48.528 99.336 48.552 ;
    END
  END a[322]
  PIN a[323]
    DIRECTION INPUT ;
    USE SIGNAL ;
    PORT
      LAYER M4 ;
        RECT  99.252 48.624 99.336 48.648 ;
    END
  END a[323]
  PIN a[324]
    DIRECTION INPUT ;
    USE SIGNAL ;
    PORT
      LAYER M4 ;
        RECT  99.252 48.72 99.336 48.744 ;
    END
  END a[324]
  PIN a[325]
    DIRECTION INPUT ;
    USE SIGNAL ;
    PORT
      LAYER M4 ;
        RECT  99.252 48.816 99.336 48.84 ;
    END
  END a[325]
  PIN a[326]
    DIRECTION INPUT ;
    USE SIGNAL ;
    PORT
      LAYER M4 ;
        RECT  99.252 48.912 99.336 48.936 ;
    END
  END a[326]
  PIN a[327]
    DIRECTION INPUT ;
    USE SIGNAL ;
    PORT
      LAYER M4 ;
        RECT  99.252 49.008 99.336 49.032 ;
    END
  END a[327]
  PIN a[328]
    DIRECTION INPUT ;
    USE SIGNAL ;
    PORT
      LAYER M4 ;
        RECT  99.252 49.104 99.336 49.128 ;
    END
  END a[328]
  PIN a[329]
    DIRECTION INPUT ;
    USE SIGNAL ;
    PORT
      LAYER M4 ;
        RECT  99.252 49.2 99.336 49.224 ;
    END
  END a[329]
  PIN a[32]
    DIRECTION INPUT ;
    USE SIGNAL ;
    PORT
      LAYER M4 ;
        RECT  99.252 42.192 99.336 42.216 ;
    END
  END a[32]
  PIN a[330]
    DIRECTION INPUT ;
    USE SIGNAL ;
    PORT
      LAYER M4 ;
        RECT  99.252 49.296 99.336 49.32 ;
    END
  END a[330]
  PIN a[331]
    DIRECTION INPUT ;
    USE SIGNAL ;
    PORT
      LAYER M4 ;
        RECT  99.252 49.392 99.336 49.416 ;
    END
  END a[331]
  PIN a[332]
    DIRECTION INPUT ;
    USE SIGNAL ;
    PORT
      LAYER M4 ;
        RECT  99.252 49.488 99.336 49.512 ;
    END
  END a[332]
  PIN a[333]
    DIRECTION INPUT ;
    USE SIGNAL ;
    PORT
      LAYER M4 ;
        RECT  99.252 49.584 99.336 49.608 ;
    END
  END a[333]
  PIN a[334]
    DIRECTION INPUT ;
    USE SIGNAL ;
    PORT
      LAYER M4 ;
        RECT  99.252 49.68 99.336 49.704 ;
    END
  END a[334]
  PIN a[335]
    DIRECTION INPUT ;
    USE SIGNAL ;
    PORT
      LAYER M4 ;
        RECT  99.252 49.776 99.336 49.8 ;
    END
  END a[335]
  PIN a[336]
    DIRECTION INPUT ;
    USE SIGNAL ;
    PORT
      LAYER M4 ;
        RECT  99.252 49.872 99.336 49.896 ;
    END
  END a[336]
  PIN a[337]
    DIRECTION INPUT ;
    USE SIGNAL ;
    PORT
      LAYER M4 ;
        RECT  99.252 49.968 99.336 49.992 ;
    END
  END a[337]
  PIN a[338]
    DIRECTION INPUT ;
    USE SIGNAL ;
    PORT
      LAYER M4 ;
        RECT  99.252 50.064 99.336 50.088 ;
    END
  END a[338]
  PIN a[339]
    DIRECTION INPUT ;
    USE SIGNAL ;
    PORT
      LAYER M4 ;
        RECT  99.252 50.16 99.336 50.184 ;
    END
  END a[339]
  PIN a[33]
    DIRECTION INPUT ;
    USE SIGNAL ;
    PORT
      LAYER M4 ;
        RECT  99.252 42.288 99.336 42.312 ;
    END
  END a[33]
  PIN a[340]
    DIRECTION INPUT ;
    USE SIGNAL ;
    PORT
      LAYER M4 ;
        RECT  99.252 50.256 99.336 50.28 ;
    END
  END a[340]
  PIN a[341]
    DIRECTION INPUT ;
    USE SIGNAL ;
    PORT
      LAYER M4 ;
        RECT  99.252 50.352 99.336 50.376 ;
    END
  END a[341]
  PIN a[342]
    DIRECTION INPUT ;
    USE SIGNAL ;
    PORT
      LAYER M4 ;
        RECT  99.252 50.448 99.336 50.472 ;
    END
  END a[342]
  PIN a[343]
    DIRECTION INPUT ;
    USE SIGNAL ;
    PORT
      LAYER M4 ;
        RECT  99.252 50.544 99.336 50.568 ;
    END
  END a[343]
  PIN a[344]
    DIRECTION INPUT ;
    USE SIGNAL ;
    PORT
      LAYER M4 ;
        RECT  99.252 50.64 99.336 50.664 ;
    END
  END a[344]
  PIN a[345]
    DIRECTION INPUT ;
    USE SIGNAL ;
    PORT
      LAYER M4 ;
        RECT  99.252 50.736 99.336 50.76 ;
    END
  END a[345]
  PIN a[346]
    DIRECTION INPUT ;
    USE SIGNAL ;
    PORT
      LAYER M4 ;
        RECT  99.252 50.832 99.336 50.856 ;
    END
  END a[346]
  PIN a[347]
    DIRECTION INPUT ;
    USE SIGNAL ;
    PORT
      LAYER M4 ;
        RECT  99.252 50.928 99.336 50.952 ;
    END
  END a[347]
  PIN a[348]
    DIRECTION INPUT ;
    USE SIGNAL ;
    PORT
      LAYER M4 ;
        RECT  99.252 51.024 99.336 51.048 ;
    END
  END a[348]
  PIN a[349]
    DIRECTION INPUT ;
    USE SIGNAL ;
    PORT
      LAYER M4 ;
        RECT  99.252 51.12 99.336 51.144 ;
    END
  END a[349]
  PIN a[34]
    DIRECTION INPUT ;
    USE SIGNAL ;
    PORT
      LAYER M4 ;
        RECT  99.252 42.384 99.336 42.408 ;
    END
  END a[34]
  PIN a[350]
    DIRECTION INPUT ;
    USE SIGNAL ;
    PORT
      LAYER M4 ;
        RECT  99.252 51.216 99.336 51.24 ;
    END
  END a[350]
  PIN a[351]
    DIRECTION INPUT ;
    USE SIGNAL ;
    PORT
      LAYER M4 ;
        RECT  99.252 51.312 99.336 51.336 ;
    END
  END a[351]
  PIN a[352]
    DIRECTION INPUT ;
    USE SIGNAL ;
    PORT
      LAYER M4 ;
        RECT  99.252 35.28 99.336 35.304 ;
    END
  END a[352]
  PIN a[353]
    DIRECTION INPUT ;
    USE SIGNAL ;
    PORT
      LAYER M4 ;
        RECT  99.252 35.376 99.336 35.4 ;
    END
  END a[353]
  PIN a[354]
    DIRECTION INPUT ;
    USE SIGNAL ;
    PORT
      LAYER M4 ;
        RECT  99.252 35.472 99.336 35.496 ;
    END
  END a[354]
  PIN a[355]
    DIRECTION INPUT ;
    USE SIGNAL ;
    PORT
      LAYER M4 ;
        RECT  99.252 35.568 99.336 35.592 ;
    END
  END a[355]
  PIN a[356]
    DIRECTION INPUT ;
    USE SIGNAL ;
    PORT
      LAYER M4 ;
        RECT  99.252 35.664 99.336 35.688 ;
    END
  END a[356]
  PIN a[357]
    DIRECTION INPUT ;
    USE SIGNAL ;
    PORT
      LAYER M4 ;
        RECT  99.252 35.76 99.336 35.784 ;
    END
  END a[357]
  PIN a[358]
    DIRECTION INPUT ;
    USE SIGNAL ;
    PORT
      LAYER M4 ;
        RECT  99.252 35.856 99.336 35.88 ;
    END
  END a[358]
  PIN a[359]
    DIRECTION INPUT ;
    USE SIGNAL ;
    PORT
      LAYER M4 ;
        RECT  99.252 35.952 99.336 35.976 ;
    END
  END a[359]
  PIN a[35]
    DIRECTION INPUT ;
    USE SIGNAL ;
    PORT
      LAYER M4 ;
        RECT  99.252 42.48 99.336 42.504 ;
    END
  END a[35]
  PIN a[360]
    DIRECTION INPUT ;
    USE SIGNAL ;
    PORT
      LAYER M4 ;
        RECT  99.252 36.048 99.336 36.072 ;
    END
  END a[360]
  PIN a[361]
    DIRECTION INPUT ;
    USE SIGNAL ;
    PORT
      LAYER M4 ;
        RECT  99.252 36.144 99.336 36.168 ;
    END
  END a[361]
  PIN a[362]
    DIRECTION INPUT ;
    USE SIGNAL ;
    PORT
      LAYER M4 ;
        RECT  99.252 36.24 99.336 36.264 ;
    END
  END a[362]
  PIN a[363]
    DIRECTION INPUT ;
    USE SIGNAL ;
    PORT
      LAYER M4 ;
        RECT  99.252 36.336 99.336 36.36 ;
    END
  END a[363]
  PIN a[364]
    DIRECTION INPUT ;
    USE SIGNAL ;
    PORT
      LAYER M4 ;
        RECT  99.252 36.432 99.336 36.456 ;
    END
  END a[364]
  PIN a[365]
    DIRECTION INPUT ;
    USE SIGNAL ;
    PORT
      LAYER M4 ;
        RECT  99.252 36.528 99.336 36.552 ;
    END
  END a[365]
  PIN a[366]
    DIRECTION INPUT ;
    USE SIGNAL ;
    PORT
      LAYER M4 ;
        RECT  99.252 36.624 99.336 36.648 ;
    END
  END a[366]
  PIN a[367]
    DIRECTION INPUT ;
    USE SIGNAL ;
    PORT
      LAYER M4 ;
        RECT  99.252 36.72 99.336 36.744 ;
    END
  END a[367]
  PIN a[368]
    DIRECTION INPUT ;
    USE SIGNAL ;
    PORT
      LAYER M4 ;
        RECT  99.252 36.816 99.336 36.84 ;
    END
  END a[368]
  PIN a[369]
    DIRECTION INPUT ;
    USE SIGNAL ;
    PORT
      LAYER M4 ;
        RECT  99.252 36.912 99.336 36.936 ;
    END
  END a[369]
  PIN a[36]
    DIRECTION INPUT ;
    USE SIGNAL ;
    PORT
      LAYER M4 ;
        RECT  99.252 42.576 99.336 42.6 ;
    END
  END a[36]
  PIN a[370]
    DIRECTION INPUT ;
    USE SIGNAL ;
    PORT
      LAYER M4 ;
        RECT  99.252 37.008 99.336 37.032 ;
    END
  END a[370]
  PIN a[371]
    DIRECTION INPUT ;
    USE SIGNAL ;
    PORT
      LAYER M4 ;
        RECT  99.252 37.104 99.336 37.128 ;
    END
  END a[371]
  PIN a[372]
    DIRECTION INPUT ;
    USE SIGNAL ;
    PORT
      LAYER M4 ;
        RECT  99.252 37.2 99.336 37.224 ;
    END
  END a[372]
  PIN a[373]
    DIRECTION INPUT ;
    USE SIGNAL ;
    PORT
      LAYER M4 ;
        RECT  99.252 37.296 99.336 37.32 ;
    END
  END a[373]
  PIN a[374]
    DIRECTION INPUT ;
    USE SIGNAL ;
    PORT
      LAYER M4 ;
        RECT  99.252 37.392 99.336 37.416 ;
    END
  END a[374]
  PIN a[375]
    DIRECTION INPUT ;
    USE SIGNAL ;
    PORT
      LAYER M4 ;
        RECT  99.252 37.488 99.336 37.512 ;
    END
  END a[375]
  PIN a[376]
    DIRECTION INPUT ;
    USE SIGNAL ;
    PORT
      LAYER M4 ;
        RECT  99.252 37.584 99.336 37.608 ;
    END
  END a[376]
  PIN a[377]
    DIRECTION INPUT ;
    USE SIGNAL ;
    PORT
      LAYER M4 ;
        RECT  99.252 37.68 99.336 37.704 ;
    END
  END a[377]
  PIN a[378]
    DIRECTION INPUT ;
    USE SIGNAL ;
    PORT
      LAYER M4 ;
        RECT  99.252 37.776 99.336 37.8 ;
    END
  END a[378]
  PIN a[379]
    DIRECTION INPUT ;
    USE SIGNAL ;
    PORT
      LAYER M4 ;
        RECT  99.252 37.872 99.336 37.896 ;
    END
  END a[379]
  PIN a[37]
    DIRECTION INPUT ;
    USE SIGNAL ;
    PORT
      LAYER M4 ;
        RECT  99.252 42.672 99.336 42.696 ;
    END
  END a[37]
  PIN a[380]
    DIRECTION INPUT ;
    USE SIGNAL ;
    PORT
      LAYER M4 ;
        RECT  99.252 37.968 99.336 37.992 ;
    END
  END a[380]
  PIN a[381]
    DIRECTION INPUT ;
    USE SIGNAL ;
    PORT
      LAYER M4 ;
        RECT  99.252 38.064 99.336 38.088 ;
    END
  END a[381]
  PIN a[382]
    DIRECTION INPUT ;
    USE SIGNAL ;
    PORT
      LAYER M4 ;
        RECT  99.252 38.16 99.336 38.184 ;
    END
  END a[382]
  PIN a[383]
    DIRECTION INPUT ;
    USE SIGNAL ;
    PORT
      LAYER M4 ;
        RECT  99.252 38.256 99.336 38.28 ;
    END
  END a[383]
  PIN a[384]
    DIRECTION INPUT ;
    USE SIGNAL ;
    PORT
      LAYER M4 ;
        RECT  99.252 26.064 99.336 26.088 ;
    END
  END a[384]
  PIN a[385]
    DIRECTION INPUT ;
    USE SIGNAL ;
    PORT
      LAYER M4 ;
        RECT  99.252 26.16 99.336 26.184 ;
    END
  END a[385]
  PIN a[386]
    DIRECTION INPUT ;
    USE SIGNAL ;
    PORT
      LAYER M4 ;
        RECT  99.252 26.256 99.336 26.28 ;
    END
  END a[386]
  PIN a[387]
    DIRECTION INPUT ;
    USE SIGNAL ;
    PORT
      LAYER M4 ;
        RECT  99.252 26.352 99.336 26.376 ;
    END
  END a[387]
  PIN a[388]
    DIRECTION INPUT ;
    USE SIGNAL ;
    PORT
      LAYER M4 ;
        RECT  99.252 26.448 99.336 26.472 ;
    END
  END a[388]
  PIN a[389]
    DIRECTION INPUT ;
    USE SIGNAL ;
    PORT
      LAYER M4 ;
        RECT  99.252 26.544 99.336 26.568 ;
    END
  END a[389]
  PIN a[38]
    DIRECTION INPUT ;
    USE SIGNAL ;
    PORT
      LAYER M4 ;
        RECT  99.252 42.768 99.336 42.792 ;
    END
  END a[38]
  PIN a[390]
    DIRECTION INPUT ;
    USE SIGNAL ;
    PORT
      LAYER M4 ;
        RECT  99.252 26.64 99.336 26.664 ;
    END
  END a[390]
  PIN a[391]
    DIRECTION INPUT ;
    USE SIGNAL ;
    PORT
      LAYER M4 ;
        RECT  99.252 26.736 99.336 26.76 ;
    END
  END a[391]
  PIN a[392]
    DIRECTION INPUT ;
    USE SIGNAL ;
    PORT
      LAYER M4 ;
        RECT  99.252 26.832 99.336 26.856 ;
    END
  END a[392]
  PIN a[393]
    DIRECTION INPUT ;
    USE SIGNAL ;
    PORT
      LAYER M4 ;
        RECT  99.252 26.928 99.336 26.952 ;
    END
  END a[393]
  PIN a[394]
    DIRECTION INPUT ;
    USE SIGNAL ;
    PORT
      LAYER M4 ;
        RECT  99.252 27.024 99.336 27.048 ;
    END
  END a[394]
  PIN a[395]
    DIRECTION INPUT ;
    USE SIGNAL ;
    PORT
      LAYER M4 ;
        RECT  99.252 27.12 99.336 27.144 ;
    END
  END a[395]
  PIN a[396]
    DIRECTION INPUT ;
    USE SIGNAL ;
    PORT
      LAYER M4 ;
        RECT  99.252 27.216 99.336 27.24 ;
    END
  END a[396]
  PIN a[397]
    DIRECTION INPUT ;
    USE SIGNAL ;
    PORT
      LAYER M4 ;
        RECT  99.252 27.312 99.336 27.336 ;
    END
  END a[397]
  PIN a[398]
    DIRECTION INPUT ;
    USE SIGNAL ;
    PORT
      LAYER M4 ;
        RECT  99.252 27.408 99.336 27.432 ;
    END
  END a[398]
  PIN a[399]
    DIRECTION INPUT ;
    USE SIGNAL ;
    PORT
      LAYER M4 ;
        RECT  99.252 27.504 99.336 27.528 ;
    END
  END a[399]
  PIN a[39]
    DIRECTION INPUT ;
    USE SIGNAL ;
    PORT
      LAYER M4 ;
        RECT  99.252 42.864 99.336 42.888 ;
    END
  END a[39]
  PIN a[3]
    DIRECTION INPUT ;
    USE SIGNAL ;
    PORT
      LAYER M4 ;
        RECT  99.252 61.68 99.336 61.704 ;
    END
  END a[3]
  PIN a[400]
    DIRECTION INPUT ;
    USE SIGNAL ;
    PORT
      LAYER M4 ;
        RECT  99.252 27.6 99.336 27.624 ;
    END
  END a[400]
  PIN a[401]
    DIRECTION INPUT ;
    USE SIGNAL ;
    PORT
      LAYER M4 ;
        RECT  99.252 27.696 99.336 27.72 ;
    END
  END a[401]
  PIN a[402]
    DIRECTION INPUT ;
    USE SIGNAL ;
    PORT
      LAYER M4 ;
        RECT  99.252 27.792 99.336 27.816 ;
    END
  END a[402]
  PIN a[403]
    DIRECTION INPUT ;
    USE SIGNAL ;
    PORT
      LAYER M4 ;
        RECT  99.252 27.888 99.336 27.912 ;
    END
  END a[403]
  PIN a[404]
    DIRECTION INPUT ;
    USE SIGNAL ;
    PORT
      LAYER M4 ;
        RECT  99.252 27.984 99.336 28.008 ;
    END
  END a[404]
  PIN a[405]
    DIRECTION INPUT ;
    USE SIGNAL ;
    PORT
      LAYER M4 ;
        RECT  99.252 28.08 99.336 28.104 ;
    END
  END a[405]
  PIN a[406]
    DIRECTION INPUT ;
    USE SIGNAL ;
    PORT
      LAYER M4 ;
        RECT  99.252 28.176 99.336 28.2 ;
    END
  END a[406]
  PIN a[407]
    DIRECTION INPUT ;
    USE SIGNAL ;
    PORT
      LAYER M4 ;
        RECT  99.252 28.272 99.336 28.296 ;
    END
  END a[407]
  PIN a[408]
    DIRECTION INPUT ;
    USE SIGNAL ;
    PORT
      LAYER M4 ;
        RECT  99.252 28.368 99.336 28.392 ;
    END
  END a[408]
  PIN a[409]
    DIRECTION INPUT ;
    USE SIGNAL ;
    PORT
      LAYER M4 ;
        RECT  99.252 28.464 99.336 28.488 ;
    END
  END a[409]
  PIN a[40]
    DIRECTION INPUT ;
    USE SIGNAL ;
    PORT
      LAYER M4 ;
        RECT  99.252 42.96 99.336 42.984 ;
    END
  END a[40]
  PIN a[410]
    DIRECTION INPUT ;
    USE SIGNAL ;
    PORT
      LAYER M4 ;
        RECT  99.252 28.56 99.336 28.584 ;
    END
  END a[410]
  PIN a[411]
    DIRECTION INPUT ;
    USE SIGNAL ;
    PORT
      LAYER M4 ;
        RECT  99.252 28.656 99.336 28.68 ;
    END
  END a[411]
  PIN a[412]
    DIRECTION INPUT ;
    USE SIGNAL ;
    PORT
      LAYER M4 ;
        RECT  99.252 28.752 99.336 28.776 ;
    END
  END a[412]
  PIN a[413]
    DIRECTION INPUT ;
    USE SIGNAL ;
    PORT
      LAYER M4 ;
        RECT  99.252 28.848 99.336 28.872 ;
    END
  END a[413]
  PIN a[414]
    DIRECTION INPUT ;
    USE SIGNAL ;
    PORT
      LAYER M4 ;
        RECT  99.252 28.944 99.336 28.968 ;
    END
  END a[414]
  PIN a[415]
    DIRECTION INPUT ;
    USE SIGNAL ;
    PORT
      LAYER M4 ;
        RECT  99.252 29.04 99.336 29.064 ;
    END
  END a[415]
  PIN a[416]
    DIRECTION INPUT ;
    USE SIGNAL ;
    PORT
      LAYER M4 ;
        RECT  99.252 19.92 99.336 19.944 ;
    END
  END a[416]
  PIN a[417]
    DIRECTION INPUT ;
    USE SIGNAL ;
    PORT
      LAYER M4 ;
        RECT  99.252 20.016 99.336 20.04 ;
    END
  END a[417]
  PIN a[418]
    DIRECTION INPUT ;
    USE SIGNAL ;
    PORT
      LAYER M4 ;
        RECT  99.252 20.112 99.336 20.136 ;
    END
  END a[418]
  PIN a[419]
    DIRECTION INPUT ;
    USE SIGNAL ;
    PORT
      LAYER M4 ;
        RECT  99.252 20.208 99.336 20.232 ;
    END
  END a[419]
  PIN a[41]
    DIRECTION INPUT ;
    USE SIGNAL ;
    PORT
      LAYER M4 ;
        RECT  99.252 43.056 99.336 43.08 ;
    END
  END a[41]
  PIN a[420]
    DIRECTION INPUT ;
    USE SIGNAL ;
    PORT
      LAYER M4 ;
        RECT  99.252 20.304 99.336 20.328 ;
    END
  END a[420]
  PIN a[421]
    DIRECTION INPUT ;
    USE SIGNAL ;
    PORT
      LAYER M4 ;
        RECT  99.252 20.4 99.336 20.424 ;
    END
  END a[421]
  PIN a[422]
    DIRECTION INPUT ;
    USE SIGNAL ;
    PORT
      LAYER M4 ;
        RECT  99.252 20.496 99.336 20.52 ;
    END
  END a[422]
  PIN a[423]
    DIRECTION INPUT ;
    USE SIGNAL ;
    PORT
      LAYER M4 ;
        RECT  99.252 20.592 99.336 20.616 ;
    END
  END a[423]
  PIN a[424]
    DIRECTION INPUT ;
    USE SIGNAL ;
    PORT
      LAYER M4 ;
        RECT  99.252 20.688 99.336 20.712 ;
    END
  END a[424]
  PIN a[425]
    DIRECTION INPUT ;
    USE SIGNAL ;
    PORT
      LAYER M4 ;
        RECT  99.252 20.784 99.336 20.808 ;
    END
  END a[425]
  PIN a[426]
    DIRECTION INPUT ;
    USE SIGNAL ;
    PORT
      LAYER M4 ;
        RECT  99.252 20.88 99.336 20.904 ;
    END
  END a[426]
  PIN a[427]
    DIRECTION INPUT ;
    USE SIGNAL ;
    PORT
      LAYER M4 ;
        RECT  99.252 20.976 99.336 21 ;
    END
  END a[427]
  PIN a[428]
    DIRECTION INPUT ;
    USE SIGNAL ;
    PORT
      LAYER M4 ;
        RECT  99.252 21.072 99.336 21.096 ;
    END
  END a[428]
  PIN a[429]
    DIRECTION INPUT ;
    USE SIGNAL ;
    PORT
      LAYER M4 ;
        RECT  99.252 21.168 99.336 21.192 ;
    END
  END a[429]
  PIN a[42]
    DIRECTION INPUT ;
    USE SIGNAL ;
    PORT
      LAYER M4 ;
        RECT  99.252 43.152 99.336 43.176 ;
    END
  END a[42]
  PIN a[430]
    DIRECTION INPUT ;
    USE SIGNAL ;
    PORT
      LAYER M4 ;
        RECT  99.252 21.264 99.336 21.288 ;
    END
  END a[430]
  PIN a[431]
    DIRECTION INPUT ;
    USE SIGNAL ;
    PORT
      LAYER M4 ;
        RECT  99.252 21.36 99.336 21.384 ;
    END
  END a[431]
  PIN a[432]
    DIRECTION INPUT ;
    USE SIGNAL ;
    PORT
      LAYER M4 ;
        RECT  99.252 21.456 99.336 21.48 ;
    END
  END a[432]
  PIN a[433]
    DIRECTION INPUT ;
    USE SIGNAL ;
    PORT
      LAYER M4 ;
        RECT  99.252 21.552 99.336 21.576 ;
    END
  END a[433]
  PIN a[434]
    DIRECTION INPUT ;
    USE SIGNAL ;
    PORT
      LAYER M4 ;
        RECT  99.252 21.648 99.336 21.672 ;
    END
  END a[434]
  PIN a[435]
    DIRECTION INPUT ;
    USE SIGNAL ;
    PORT
      LAYER M4 ;
        RECT  99.252 21.744 99.336 21.768 ;
    END
  END a[435]
  PIN a[436]
    DIRECTION INPUT ;
    USE SIGNAL ;
    PORT
      LAYER M4 ;
        RECT  99.252 21.84 99.336 21.864 ;
    END
  END a[436]
  PIN a[437]
    DIRECTION INPUT ;
    USE SIGNAL ;
    PORT
      LAYER M4 ;
        RECT  99.252 21.936 99.336 21.96 ;
    END
  END a[437]
  PIN a[438]
    DIRECTION INPUT ;
    USE SIGNAL ;
    PORT
      LAYER M4 ;
        RECT  99.252 22.032 99.336 22.056 ;
    END
  END a[438]
  PIN a[439]
    DIRECTION INPUT ;
    USE SIGNAL ;
    PORT
      LAYER M4 ;
        RECT  99.252 22.128 99.336 22.152 ;
    END
  END a[439]
  PIN a[43]
    DIRECTION INPUT ;
    USE SIGNAL ;
    PORT
      LAYER M4 ;
        RECT  99.252 43.248 99.336 43.272 ;
    END
  END a[43]
  PIN a[440]
    DIRECTION INPUT ;
    USE SIGNAL ;
    PORT
      LAYER M4 ;
        RECT  99.252 22.224 99.336 22.248 ;
    END
  END a[440]
  PIN a[441]
    DIRECTION INPUT ;
    USE SIGNAL ;
    PORT
      LAYER M4 ;
        RECT  99.252 22.32 99.336 22.344 ;
    END
  END a[441]
  PIN a[442]
    DIRECTION INPUT ;
    USE SIGNAL ;
    PORT
      LAYER M4 ;
        RECT  99.252 22.416 99.336 22.44 ;
    END
  END a[442]
  PIN a[443]
    DIRECTION INPUT ;
    USE SIGNAL ;
    PORT
      LAYER M4 ;
        RECT  99.252 22.512 99.336 22.536 ;
    END
  END a[443]
  PIN a[444]
    DIRECTION INPUT ;
    USE SIGNAL ;
    PORT
      LAYER M4 ;
        RECT  99.252 22.608 99.336 22.632 ;
    END
  END a[444]
  PIN a[445]
    DIRECTION INPUT ;
    USE SIGNAL ;
    PORT
      LAYER M4 ;
        RECT  99.252 22.704 99.336 22.728 ;
    END
  END a[445]
  PIN a[446]
    DIRECTION INPUT ;
    USE SIGNAL ;
    PORT
      LAYER M4 ;
        RECT  99.252 22.8 99.336 22.824 ;
    END
  END a[446]
  PIN a[447]
    DIRECTION INPUT ;
    USE SIGNAL ;
    PORT
      LAYER M4 ;
        RECT  99.252 22.896 99.336 22.92 ;
    END
  END a[447]
  PIN a[448]
    DIRECTION INPUT ;
    USE SIGNAL ;
    PORT
      LAYER M4 ;
        RECT  99.252 29.136 99.336 29.16 ;
    END
  END a[448]
  PIN a[449]
    DIRECTION INPUT ;
    USE SIGNAL ;
    PORT
      LAYER M4 ;
        RECT  99.252 29.232 99.336 29.256 ;
    END
  END a[449]
  PIN a[44]
    DIRECTION INPUT ;
    USE SIGNAL ;
    PORT
      LAYER M4 ;
        RECT  99.252 43.344 99.336 43.368 ;
    END
  END a[44]
  PIN a[450]
    DIRECTION INPUT ;
    USE SIGNAL ;
    PORT
      LAYER M4 ;
        RECT  99.252 29.328 99.336 29.352 ;
    END
  END a[450]
  PIN a[451]
    DIRECTION INPUT ;
    USE SIGNAL ;
    PORT
      LAYER M4 ;
        RECT  99.252 29.424 99.336 29.448 ;
    END
  END a[451]
  PIN a[452]
    DIRECTION INPUT ;
    USE SIGNAL ;
    PORT
      LAYER M4 ;
        RECT  99.252 29.52 99.336 29.544 ;
    END
  END a[452]
  PIN a[453]
    DIRECTION INPUT ;
    USE SIGNAL ;
    PORT
      LAYER M4 ;
        RECT  99.252 29.616 99.336 29.64 ;
    END
  END a[453]
  PIN a[454]
    DIRECTION INPUT ;
    USE SIGNAL ;
    PORT
      LAYER M4 ;
        RECT  99.252 29.712 99.336 29.736 ;
    END
  END a[454]
  PIN a[455]
    DIRECTION INPUT ;
    USE SIGNAL ;
    PORT
      LAYER M4 ;
        RECT  99.252 29.808 99.336 29.832 ;
    END
  END a[455]
  PIN a[456]
    DIRECTION INPUT ;
    USE SIGNAL ;
    PORT
      LAYER M4 ;
        RECT  99.252 29.904 99.336 29.928 ;
    END
  END a[456]
  PIN a[457]
    DIRECTION INPUT ;
    USE SIGNAL ;
    PORT
      LAYER M4 ;
        RECT  99.252 30 99.336 30.024 ;
    END
  END a[457]
  PIN a[458]
    DIRECTION INPUT ;
    USE SIGNAL ;
    PORT
      LAYER M4 ;
        RECT  99.252 30.096 99.336 30.12 ;
    END
  END a[458]
  PIN a[459]
    DIRECTION INPUT ;
    USE SIGNAL ;
    PORT
      LAYER M4 ;
        RECT  99.252 30.192 99.336 30.216 ;
    END
  END a[459]
  PIN a[45]
    DIRECTION INPUT ;
    USE SIGNAL ;
    PORT
      LAYER M4 ;
        RECT  99.252 43.44 99.336 43.464 ;
    END
  END a[45]
  PIN a[460]
    DIRECTION INPUT ;
    USE SIGNAL ;
    PORT
      LAYER M4 ;
        RECT  99.252 30.288 99.336 30.312 ;
    END
  END a[460]
  PIN a[461]
    DIRECTION INPUT ;
    USE SIGNAL ;
    PORT
      LAYER M4 ;
        RECT  99.252 30.384 99.336 30.408 ;
    END
  END a[461]
  PIN a[462]
    DIRECTION INPUT ;
    USE SIGNAL ;
    PORT
      LAYER M4 ;
        RECT  99.252 30.48 99.336 30.504 ;
    END
  END a[462]
  PIN a[463]
    DIRECTION INPUT ;
    USE SIGNAL ;
    PORT
      LAYER M4 ;
        RECT  99.252 30.576 99.336 30.6 ;
    END
  END a[463]
  PIN a[464]
    DIRECTION INPUT ;
    USE SIGNAL ;
    PORT
      LAYER M4 ;
        RECT  99.252 30.672 99.336 30.696 ;
    END
  END a[464]
  PIN a[465]
    DIRECTION INPUT ;
    USE SIGNAL ;
    PORT
      LAYER M4 ;
        RECT  99.252 30.768 99.336 30.792 ;
    END
  END a[465]
  PIN a[466]
    DIRECTION INPUT ;
    USE SIGNAL ;
    PORT
      LAYER M4 ;
        RECT  99.252 30.864 99.336 30.888 ;
    END
  END a[466]
  PIN a[467]
    DIRECTION INPUT ;
    USE SIGNAL ;
    PORT
      LAYER M4 ;
        RECT  99.252 30.96 99.336 30.984 ;
    END
  END a[467]
  PIN a[468]
    DIRECTION INPUT ;
    USE SIGNAL ;
    PORT
      LAYER M4 ;
        RECT  99.252 31.056 99.336 31.08 ;
    END
  END a[468]
  PIN a[469]
    DIRECTION INPUT ;
    USE SIGNAL ;
    PORT
      LAYER M4 ;
        RECT  99.252 31.152 99.336 31.176 ;
    END
  END a[469]
  PIN a[46]
    DIRECTION INPUT ;
    USE SIGNAL ;
    PORT
      LAYER M4 ;
        RECT  99.252 43.536 99.336 43.56 ;
    END
  END a[46]
  PIN a[470]
    DIRECTION INPUT ;
    USE SIGNAL ;
    PORT
      LAYER M4 ;
        RECT  99.252 31.248 99.336 31.272 ;
    END
  END a[470]
  PIN a[471]
    DIRECTION INPUT ;
    USE SIGNAL ;
    PORT
      LAYER M4 ;
        RECT  99.252 31.344 99.336 31.368 ;
    END
  END a[471]
  PIN a[472]
    DIRECTION INPUT ;
    USE SIGNAL ;
    PORT
      LAYER M4 ;
        RECT  99.252 31.44 99.336 31.464 ;
    END
  END a[472]
  PIN a[473]
    DIRECTION INPUT ;
    USE SIGNAL ;
    PORT
      LAYER M4 ;
        RECT  99.252 31.536 99.336 31.56 ;
    END
  END a[473]
  PIN a[474]
    DIRECTION INPUT ;
    USE SIGNAL ;
    PORT
      LAYER M4 ;
        RECT  99.252 31.632 99.336 31.656 ;
    END
  END a[474]
  PIN a[475]
    DIRECTION INPUT ;
    USE SIGNAL ;
    PORT
      LAYER M4 ;
        RECT  99.252 31.728 99.336 31.752 ;
    END
  END a[475]
  PIN a[476]
    DIRECTION INPUT ;
    USE SIGNAL ;
    PORT
      LAYER M4 ;
        RECT  99.252 31.824 99.336 31.848 ;
    END
  END a[476]
  PIN a[477]
    DIRECTION INPUT ;
    USE SIGNAL ;
    PORT
      LAYER M4 ;
        RECT  99.252 31.92 99.336 31.944 ;
    END
  END a[477]
  PIN a[478]
    DIRECTION INPUT ;
    USE SIGNAL ;
    PORT
      LAYER M4 ;
        RECT  99.252 32.016 99.336 32.04 ;
    END
  END a[478]
  PIN a[479]
    DIRECTION INPUT ;
    USE SIGNAL ;
    PORT
      LAYER M4 ;
        RECT  99.252 32.112 99.336 32.136 ;
    END
  END a[479]
  PIN a[47]
    DIRECTION INPUT ;
    USE SIGNAL ;
    PORT
      LAYER M4 ;
        RECT  99.252 43.632 99.336 43.656 ;
    END
  END a[47]
  PIN a[480]
    DIRECTION INPUT ;
    USE SIGNAL ;
    PORT
      LAYER M4 ;
        RECT  99.252 39.12 99.336 39.144 ;
    END
  END a[480]
  PIN a[481]
    DIRECTION INPUT ;
    USE SIGNAL ;
    PORT
      LAYER M4 ;
        RECT  99.252 39.216 99.336 39.24 ;
    END
  END a[481]
  PIN a[482]
    DIRECTION INPUT ;
    USE SIGNAL ;
    PORT
      LAYER M4 ;
        RECT  99.252 39.312 99.336 39.336 ;
    END
  END a[482]
  PIN a[483]
    DIRECTION INPUT ;
    USE SIGNAL ;
    PORT
      LAYER M4 ;
        RECT  99.252 39.408 99.336 39.432 ;
    END
  END a[483]
  PIN a[484]
    DIRECTION INPUT ;
    USE SIGNAL ;
    PORT
      LAYER M4 ;
        RECT  99.252 39.504 99.336 39.528 ;
    END
  END a[484]
  PIN a[485]
    DIRECTION INPUT ;
    USE SIGNAL ;
    PORT
      LAYER M4 ;
        RECT  99.252 39.6 99.336 39.624 ;
    END
  END a[485]
  PIN a[486]
    DIRECTION INPUT ;
    USE SIGNAL ;
    PORT
      LAYER M4 ;
        RECT  99.252 39.696 99.336 39.72 ;
    END
  END a[486]
  PIN a[487]
    DIRECTION INPUT ;
    USE SIGNAL ;
    PORT
      LAYER M4 ;
        RECT  99.252 39.792 99.336 39.816 ;
    END
  END a[487]
  PIN a[488]
    DIRECTION INPUT ;
    USE SIGNAL ;
    PORT
      LAYER M4 ;
        RECT  99.252 39.888 99.336 39.912 ;
    END
  END a[488]
  PIN a[489]
    DIRECTION INPUT ;
    USE SIGNAL ;
    PORT
      LAYER M4 ;
        RECT  99.252 39.984 99.336 40.008 ;
    END
  END a[489]
  PIN a[48]
    DIRECTION INPUT ;
    USE SIGNAL ;
    PORT
      LAYER M4 ;
        RECT  99.252 43.728 99.336 43.752 ;
    END
  END a[48]
  PIN a[490]
    DIRECTION INPUT ;
    USE SIGNAL ;
    PORT
      LAYER M4 ;
        RECT  99.252 40.08 99.336 40.104 ;
    END
  END a[490]
  PIN a[491]
    DIRECTION INPUT ;
    USE SIGNAL ;
    PORT
      LAYER M4 ;
        RECT  99.252 40.176 99.336 40.2 ;
    END
  END a[491]
  PIN a[492]
    DIRECTION INPUT ;
    USE SIGNAL ;
    PORT
      LAYER M4 ;
        RECT  99.252 40.272 99.336 40.296 ;
    END
  END a[492]
  PIN a[493]
    DIRECTION INPUT ;
    USE SIGNAL ;
    PORT
      LAYER M4 ;
        RECT  99.252 40.368 99.336 40.392 ;
    END
  END a[493]
  PIN a[494]
    DIRECTION INPUT ;
    USE SIGNAL ;
    PORT
      LAYER M4 ;
        RECT  99.252 40.464 99.336 40.488 ;
    END
  END a[494]
  PIN a[495]
    DIRECTION INPUT ;
    USE SIGNAL ;
    PORT
      LAYER M4 ;
        RECT  99.252 40.56 99.336 40.584 ;
    END
  END a[495]
  PIN a[496]
    DIRECTION INPUT ;
    USE SIGNAL ;
    PORT
      LAYER M4 ;
        RECT  99.252 40.656 99.336 40.68 ;
    END
  END a[496]
  PIN a[497]
    DIRECTION INPUT ;
    USE SIGNAL ;
    PORT
      LAYER M4 ;
        RECT  99.252 40.752 99.336 40.776 ;
    END
  END a[497]
  PIN a[498]
    DIRECTION INPUT ;
    USE SIGNAL ;
    PORT
      LAYER M4 ;
        RECT  99.252 40.848 99.336 40.872 ;
    END
  END a[498]
  PIN a[499]
    DIRECTION INPUT ;
    USE SIGNAL ;
    PORT
      LAYER M4 ;
        RECT  99.252 40.944 99.336 40.968 ;
    END
  END a[499]
  PIN a[49]
    DIRECTION INPUT ;
    USE SIGNAL ;
    PORT
      LAYER M4 ;
        RECT  99.252 43.824 99.336 43.848 ;
    END
  END a[49]
  PIN a[4]
    DIRECTION INPUT ;
    USE SIGNAL ;
    PORT
      LAYER M4 ;
        RECT  99.252 61.776 99.336 61.8 ;
    END
  END a[4]
  PIN a[500]
    DIRECTION INPUT ;
    USE SIGNAL ;
    PORT
      LAYER M4 ;
        RECT  99.252 41.04 99.336 41.064 ;
    END
  END a[500]
  PIN a[501]
    DIRECTION INPUT ;
    USE SIGNAL ;
    PORT
      LAYER M4 ;
        RECT  99.252 41.136 99.336 41.16 ;
    END
  END a[501]
  PIN a[502]
    DIRECTION INPUT ;
    USE SIGNAL ;
    PORT
      LAYER M4 ;
        RECT  99.252 41.232 99.336 41.256 ;
    END
  END a[502]
  PIN a[503]
    DIRECTION INPUT ;
    USE SIGNAL ;
    PORT
      LAYER M4 ;
        RECT  99.252 41.328 99.336 41.352 ;
    END
  END a[503]
  PIN a[504]
    DIRECTION INPUT ;
    USE SIGNAL ;
    PORT
      LAYER M4 ;
        RECT  99.252 41.424 99.336 41.448 ;
    END
  END a[504]
  PIN a[505]
    DIRECTION INPUT ;
    USE SIGNAL ;
    PORT
      LAYER M4 ;
        RECT  99.252 41.52 99.336 41.544 ;
    END
  END a[505]
  PIN a[506]
    DIRECTION INPUT ;
    USE SIGNAL ;
    PORT
      LAYER M4 ;
        RECT  99.252 41.616 99.336 41.64 ;
    END
  END a[506]
  PIN a[507]
    DIRECTION INPUT ;
    USE SIGNAL ;
    PORT
      LAYER M4 ;
        RECT  99.252 41.712 99.336 41.736 ;
    END
  END a[507]
  PIN a[508]
    DIRECTION INPUT ;
    USE SIGNAL ;
    PORT
      LAYER M4 ;
        RECT  99.252 41.808 99.336 41.832 ;
    END
  END a[508]
  PIN a[509]
    DIRECTION INPUT ;
    USE SIGNAL ;
    PORT
      LAYER M4 ;
        RECT  99.252 41.904 99.336 41.928 ;
    END
  END a[509]
  PIN a[50]
    DIRECTION INPUT ;
    USE SIGNAL ;
    PORT
      LAYER M4 ;
        RECT  99.252 43.92 99.336 43.944 ;
    END
  END a[50]
  PIN a[510]
    DIRECTION INPUT ;
    USE SIGNAL ;
    PORT
      LAYER M4 ;
        RECT  99.252 42 99.336 42.024 ;
    END
  END a[510]
  PIN a[511]
    DIRECTION INPUT ;
    USE SIGNAL ;
    PORT
      LAYER M4 ;
        RECT  99.252 42.096 99.336 42.12 ;
    END
  END a[511]
  PIN a[512]
    DIRECTION INPUT ;
    USE SIGNAL ;
    PORT
      LAYER M4 ;
        RECT  99.252 51.408 99.336 51.432 ;
    END
  END a[512]
  PIN a[513]
    DIRECTION INPUT ;
    USE SIGNAL ;
    PORT
      LAYER M4 ;
        RECT  99.252 51.504 99.336 51.528 ;
    END
  END a[513]
  PIN a[514]
    DIRECTION INPUT ;
    USE SIGNAL ;
    PORT
      LAYER M4 ;
        RECT  99.252 51.6 99.336 51.624 ;
    END
  END a[514]
  PIN a[515]
    DIRECTION INPUT ;
    USE SIGNAL ;
    PORT
      LAYER M4 ;
        RECT  99.252 51.696 99.336 51.72 ;
    END
  END a[515]
  PIN a[516]
    DIRECTION INPUT ;
    USE SIGNAL ;
    PORT
      LAYER M4 ;
        RECT  99.252 51.792 99.336 51.816 ;
    END
  END a[516]
  PIN a[517]
    DIRECTION INPUT ;
    USE SIGNAL ;
    PORT
      LAYER M4 ;
        RECT  99.252 51.888 99.336 51.912 ;
    END
  END a[517]
  PIN a[518]
    DIRECTION INPUT ;
    USE SIGNAL ;
    PORT
      LAYER M4 ;
        RECT  99.252 51.984 99.336 52.008 ;
    END
  END a[518]
  PIN a[519]
    DIRECTION INPUT ;
    USE SIGNAL ;
    PORT
      LAYER M4 ;
        RECT  99.252 52.08 99.336 52.104 ;
    END
  END a[519]
  PIN a[51]
    DIRECTION INPUT ;
    USE SIGNAL ;
    PORT
      LAYER M4 ;
        RECT  99.252 44.016 99.336 44.04 ;
    END
  END a[51]
  PIN a[520]
    DIRECTION INPUT ;
    USE SIGNAL ;
    PORT
      LAYER M4 ;
        RECT  99.252 52.176 99.336 52.2 ;
    END
  END a[520]
  PIN a[521]
    DIRECTION INPUT ;
    USE SIGNAL ;
    PORT
      LAYER M4 ;
        RECT  99.252 52.272 99.336 52.296 ;
    END
  END a[521]
  PIN a[522]
    DIRECTION INPUT ;
    USE SIGNAL ;
    PORT
      LAYER M4 ;
        RECT  99.252 52.368 99.336 52.392 ;
    END
  END a[522]
  PIN a[523]
    DIRECTION INPUT ;
    USE SIGNAL ;
    PORT
      LAYER M4 ;
        RECT  99.252 52.464 99.336 52.488 ;
    END
  END a[523]
  PIN a[524]
    DIRECTION INPUT ;
    USE SIGNAL ;
    PORT
      LAYER M4 ;
        RECT  99.252 52.56 99.336 52.584 ;
    END
  END a[524]
  PIN a[525]
    DIRECTION INPUT ;
    USE SIGNAL ;
    PORT
      LAYER M4 ;
        RECT  99.252 52.656 99.336 52.68 ;
    END
  END a[525]
  PIN a[526]
    DIRECTION INPUT ;
    USE SIGNAL ;
    PORT
      LAYER M4 ;
        RECT  99.252 52.752 99.336 52.776 ;
    END
  END a[526]
  PIN a[527]
    DIRECTION INPUT ;
    USE SIGNAL ;
    PORT
      LAYER M4 ;
        RECT  99.252 52.848 99.336 52.872 ;
    END
  END a[527]
  PIN a[528]
    DIRECTION INPUT ;
    USE SIGNAL ;
    PORT
      LAYER M4 ;
        RECT  99.252 52.944 99.336 52.968 ;
    END
  END a[528]
  PIN a[529]
    DIRECTION INPUT ;
    USE SIGNAL ;
    PORT
      LAYER M4 ;
        RECT  99.252 53.04 99.336 53.064 ;
    END
  END a[529]
  PIN a[52]
    DIRECTION INPUT ;
    USE SIGNAL ;
    PORT
      LAYER M4 ;
        RECT  99.252 44.112 99.336 44.136 ;
    END
  END a[52]
  PIN a[530]
    DIRECTION INPUT ;
    USE SIGNAL ;
    PORT
      LAYER M4 ;
        RECT  99.252 53.136 99.336 53.16 ;
    END
  END a[530]
  PIN a[531]
    DIRECTION INPUT ;
    USE SIGNAL ;
    PORT
      LAYER M4 ;
        RECT  99.252 53.232 99.336 53.256 ;
    END
  END a[531]
  PIN a[532]
    DIRECTION INPUT ;
    USE SIGNAL ;
    PORT
      LAYER M4 ;
        RECT  99.252 53.328 99.336 53.352 ;
    END
  END a[532]
  PIN a[533]
    DIRECTION INPUT ;
    USE SIGNAL ;
    PORT
      LAYER M4 ;
        RECT  99.252 53.424 99.336 53.448 ;
    END
  END a[533]
  PIN a[534]
    DIRECTION INPUT ;
    USE SIGNAL ;
    PORT
      LAYER M4 ;
        RECT  99.252 53.52 99.336 53.544 ;
    END
  END a[534]
  PIN a[535]
    DIRECTION INPUT ;
    USE SIGNAL ;
    PORT
      LAYER M4 ;
        RECT  99.252 53.616 99.336 53.64 ;
    END
  END a[535]
  PIN a[536]
    DIRECTION INPUT ;
    USE SIGNAL ;
    PORT
      LAYER M4 ;
        RECT  99.252 53.712 99.336 53.736 ;
    END
  END a[536]
  PIN a[537]
    DIRECTION INPUT ;
    USE SIGNAL ;
    PORT
      LAYER M4 ;
        RECT  99.252 53.808 99.336 53.832 ;
    END
  END a[537]
  PIN a[538]
    DIRECTION INPUT ;
    USE SIGNAL ;
    PORT
      LAYER M4 ;
        RECT  99.252 53.904 99.336 53.928 ;
    END
  END a[538]
  PIN a[539]
    DIRECTION INPUT ;
    USE SIGNAL ;
    PORT
      LAYER M4 ;
        RECT  99.252 54 99.336 54.024 ;
    END
  END a[539]
  PIN a[53]
    DIRECTION INPUT ;
    USE SIGNAL ;
    PORT
      LAYER M4 ;
        RECT  99.252 44.208 99.336 44.232 ;
    END
  END a[53]
  PIN a[540]
    DIRECTION INPUT ;
    USE SIGNAL ;
    PORT
      LAYER M4 ;
        RECT  99.252 54.096 99.336 54.12 ;
    END
  END a[540]
  PIN a[541]
    DIRECTION INPUT ;
    USE SIGNAL ;
    PORT
      LAYER M4 ;
        RECT  99.252 54.192 99.336 54.216 ;
    END
  END a[541]
  PIN a[542]
    DIRECTION INPUT ;
    USE SIGNAL ;
    PORT
      LAYER M4 ;
        RECT  99.252 54.288 99.336 54.312 ;
    END
  END a[542]
  PIN a[543]
    DIRECTION INPUT ;
    USE SIGNAL ;
    PORT
      LAYER M4 ;
        RECT  99.252 54.384 99.336 54.408 ;
    END
  END a[543]
  PIN a[544]
    DIRECTION INPUT ;
    USE SIGNAL ;
    PORT
      LAYER M4 ;
        RECT  99.252 64.464 99.336 64.488 ;
    END
  END a[544]
  PIN a[545]
    DIRECTION INPUT ;
    USE SIGNAL ;
    PORT
      LAYER M4 ;
        RECT  99.252 64.56 99.336 64.584 ;
    END
  END a[545]
  PIN a[546]
    DIRECTION INPUT ;
    USE SIGNAL ;
    PORT
      LAYER M4 ;
        RECT  99.252 64.656 99.336 64.68 ;
    END
  END a[546]
  PIN a[547]
    DIRECTION INPUT ;
    USE SIGNAL ;
    PORT
      LAYER M4 ;
        RECT  99.252 64.752 99.336 64.776 ;
    END
  END a[547]
  PIN a[54]
    DIRECTION INPUT ;
    USE SIGNAL ;
    PORT
      LAYER M4 ;
        RECT  99.252 44.304 99.336 44.328 ;
    END
  END a[54]
  PIN a[55]
    DIRECTION INPUT ;
    USE SIGNAL ;
    PORT
      LAYER M4 ;
        RECT  99.252 44.4 99.336 44.424 ;
    END
  END a[55]
  PIN a[56]
    DIRECTION INPUT ;
    USE SIGNAL ;
    PORT
      LAYER M4 ;
        RECT  99.252 44.496 99.336 44.52 ;
    END
  END a[56]
  PIN a[57]
    DIRECTION INPUT ;
    USE SIGNAL ;
    PORT
      LAYER M4 ;
        RECT  99.252 44.592 99.336 44.616 ;
    END
  END a[57]
  PIN a[58]
    DIRECTION INPUT ;
    USE SIGNAL ;
    PORT
      LAYER M4 ;
        RECT  99.252 44.688 99.336 44.712 ;
    END
  END a[58]
  PIN a[59]
    DIRECTION INPUT ;
    USE SIGNAL ;
    PORT
      LAYER M4 ;
        RECT  99.252 44.784 99.336 44.808 ;
    END
  END a[59]
  PIN a[5]
    DIRECTION INPUT ;
    USE SIGNAL ;
    PORT
      LAYER M4 ;
        RECT  99.252 61.872 99.336 61.896 ;
    END
  END a[5]
  PIN a[60]
    DIRECTION INPUT ;
    USE SIGNAL ;
    PORT
      LAYER M4 ;
        RECT  99.252 44.88 99.336 44.904 ;
    END
  END a[60]
  PIN a[61]
    DIRECTION INPUT ;
    USE SIGNAL ;
    PORT
      LAYER M4 ;
        RECT  99.252 44.976 99.336 45 ;
    END
  END a[61]
  PIN a[62]
    DIRECTION INPUT ;
    USE SIGNAL ;
    PORT
      LAYER M4 ;
        RECT  99.252 45.072 99.336 45.096 ;
    END
  END a[62]
  PIN a[63]
    DIRECTION INPUT ;
    USE SIGNAL ;
    PORT
      LAYER M4 ;
        RECT  99.252 45.168 99.336 45.192 ;
    END
  END a[63]
  PIN a[64]
    DIRECTION INPUT ;
    USE SIGNAL ;
    PORT
      LAYER M4 ;
        RECT  99.252 22.992 99.336 23.016 ;
    END
  END a[64]
  PIN a[65]
    DIRECTION INPUT ;
    USE SIGNAL ;
    PORT
      LAYER M4 ;
        RECT  99.252 23.088 99.336 23.112 ;
    END
  END a[65]
  PIN a[66]
    DIRECTION INPUT ;
    USE SIGNAL ;
    PORT
      LAYER M4 ;
        RECT  99.252 23.184 99.336 23.208 ;
    END
  END a[66]
  PIN a[67]
    DIRECTION INPUT ;
    USE SIGNAL ;
    PORT
      LAYER M4 ;
        RECT  99.252 23.28 99.336 23.304 ;
    END
  END a[67]
  PIN a[68]
    DIRECTION INPUT ;
    USE SIGNAL ;
    PORT
      LAYER M4 ;
        RECT  99.252 23.376 99.336 23.4 ;
    END
  END a[68]
  PIN a[69]
    DIRECTION INPUT ;
    USE SIGNAL ;
    PORT
      LAYER M4 ;
        RECT  99.252 23.472 99.336 23.496 ;
    END
  END a[69]
  PIN a[6]
    DIRECTION INPUT ;
    USE SIGNAL ;
    PORT
      LAYER M4 ;
        RECT  99.252 61.968 99.336 61.992 ;
    END
  END a[6]
  PIN a[70]
    DIRECTION INPUT ;
    USE SIGNAL ;
    PORT
      LAYER M4 ;
        RECT  99.252 23.568 99.336 23.592 ;
    END
  END a[70]
  PIN a[71]
    DIRECTION INPUT ;
    USE SIGNAL ;
    PORT
      LAYER M4 ;
        RECT  99.252 23.664 99.336 23.688 ;
    END
  END a[71]
  PIN a[72]
    DIRECTION INPUT ;
    USE SIGNAL ;
    PORT
      LAYER M4 ;
        RECT  99.252 23.76 99.336 23.784 ;
    END
  END a[72]
  PIN a[73]
    DIRECTION INPUT ;
    USE SIGNAL ;
    PORT
      LAYER M4 ;
        RECT  99.252 23.856 99.336 23.88 ;
    END
  END a[73]
  PIN a[74]
    DIRECTION INPUT ;
    USE SIGNAL ;
    PORT
      LAYER M4 ;
        RECT  99.252 23.952 99.336 23.976 ;
    END
  END a[74]
  PIN a[75]
    DIRECTION INPUT ;
    USE SIGNAL ;
    PORT
      LAYER M4 ;
        RECT  99.252 24.048 99.336 24.072 ;
    END
  END a[75]
  PIN a[76]
    DIRECTION INPUT ;
    USE SIGNAL ;
    PORT
      LAYER M4 ;
        RECT  99.252 24.144 99.336 24.168 ;
    END
  END a[76]
  PIN a[77]
    DIRECTION INPUT ;
    USE SIGNAL ;
    PORT
      LAYER M4 ;
        RECT  99.252 24.24 99.336 24.264 ;
    END
  END a[77]
  PIN a[78]
    DIRECTION INPUT ;
    USE SIGNAL ;
    PORT
      LAYER M4 ;
        RECT  99.252 24.336 99.336 24.36 ;
    END
  END a[78]
  PIN a[79]
    DIRECTION INPUT ;
    USE SIGNAL ;
    PORT
      LAYER M4 ;
        RECT  99.252 24.432 99.336 24.456 ;
    END
  END a[79]
  PIN a[7]
    DIRECTION INPUT ;
    USE SIGNAL ;
    PORT
      LAYER M4 ;
        RECT  99.252 62.064 99.336 62.088 ;
    END
  END a[7]
  PIN a[80]
    DIRECTION INPUT ;
    USE SIGNAL ;
    PORT
      LAYER M4 ;
        RECT  99.252 24.528 99.336 24.552 ;
    END
  END a[80]
  PIN a[81]
    DIRECTION INPUT ;
    USE SIGNAL ;
    PORT
      LAYER M4 ;
        RECT  99.252 24.624 99.336 24.648 ;
    END
  END a[81]
  PIN a[82]
    DIRECTION INPUT ;
    USE SIGNAL ;
    PORT
      LAYER M4 ;
        RECT  99.252 24.72 99.336 24.744 ;
    END
  END a[82]
  PIN a[83]
    DIRECTION INPUT ;
    USE SIGNAL ;
    PORT
      LAYER M4 ;
        RECT  99.252 24.816 99.336 24.84 ;
    END
  END a[83]
  PIN a[84]
    DIRECTION INPUT ;
    USE SIGNAL ;
    PORT
      LAYER M4 ;
        RECT  99.252 24.912 99.336 24.936 ;
    END
  END a[84]
  PIN a[85]
    DIRECTION INPUT ;
    USE SIGNAL ;
    PORT
      LAYER M4 ;
        RECT  99.252 25.008 99.336 25.032 ;
    END
  END a[85]
  PIN a[86]
    DIRECTION INPUT ;
    USE SIGNAL ;
    PORT
      LAYER M4 ;
        RECT  99.252 25.104 99.336 25.128 ;
    END
  END a[86]
  PIN a[87]
    DIRECTION INPUT ;
    USE SIGNAL ;
    PORT
      LAYER M4 ;
        RECT  99.252 25.2 99.336 25.224 ;
    END
  END a[87]
  PIN a[88]
    DIRECTION INPUT ;
    USE SIGNAL ;
    PORT
      LAYER M4 ;
        RECT  99.252 25.296 99.336 25.32 ;
    END
  END a[88]
  PIN a[89]
    DIRECTION INPUT ;
    USE SIGNAL ;
    PORT
      LAYER M4 ;
        RECT  99.252 25.392 99.336 25.416 ;
    END
  END a[89]
  PIN a[8]
    DIRECTION INPUT ;
    USE SIGNAL ;
    PORT
      LAYER M4 ;
        RECT  99.252 62.16 99.336 62.184 ;
    END
  END a[8]
  PIN a[90]
    DIRECTION INPUT ;
    USE SIGNAL ;
    PORT
      LAYER M4 ;
        RECT  99.252 25.488 99.336 25.512 ;
    END
  END a[90]
  PIN a[91]
    DIRECTION INPUT ;
    USE SIGNAL ;
    PORT
      LAYER M4 ;
        RECT  99.252 25.584 99.336 25.608 ;
    END
  END a[91]
  PIN a[92]
    DIRECTION INPUT ;
    USE SIGNAL ;
    PORT
      LAYER M4 ;
        RECT  99.252 25.68 99.336 25.704 ;
    END
  END a[92]
  PIN a[93]
    DIRECTION INPUT ;
    USE SIGNAL ;
    PORT
      LAYER M4 ;
        RECT  99.252 25.776 99.336 25.8 ;
    END
  END a[93]
  PIN a[94]
    DIRECTION INPUT ;
    USE SIGNAL ;
    PORT
      LAYER M4 ;
        RECT  99.252 25.872 99.336 25.896 ;
    END
  END a[94]
  PIN a[95]
    DIRECTION INPUT ;
    USE SIGNAL ;
    PORT
      LAYER M4 ;
        RECT  99.252 25.968 99.336 25.992 ;
    END
  END a[95]
  PIN a[96]
    DIRECTION INPUT ;
    USE SIGNAL ;
    PORT
      LAYER M4 ;
        RECT  99.252 32.208 99.336 32.232 ;
    END
  END a[96]
  PIN a[97]
    DIRECTION INPUT ;
    USE SIGNAL ;
    PORT
      LAYER M4 ;
        RECT  99.252 32.304 99.336 32.328 ;
    END
  END a[97]
  PIN a[98]
    DIRECTION INPUT ;
    USE SIGNAL ;
    PORT
      LAYER M4 ;
        RECT  99.252 32.4 99.336 32.424 ;
    END
  END a[98]
  PIN a[99]
    DIRECTION INPUT ;
    USE SIGNAL ;
    PORT
      LAYER M4 ;
        RECT  99.252 32.496 99.336 32.52 ;
    END
  END a[99]
  PIN a[9]
    DIRECTION INPUT ;
    USE SIGNAL ;
    PORT
      LAYER M4 ;
        RECT  99.252 62.256 99.336 62.28 ;
    END
  END a[9]
  PIN b[0]
    DIRECTION OUTPUT ;
    USE SIGNAL ;
    PORT
      LAYER M5 ;
        RECT  22.608 99.252 22.632 99.336 ;
    END
  END b[0]
  PIN b[100]
    DIRECTION OUTPUT ;
    USE SIGNAL ;
    PORT
      LAYER M3 ;
        RECT  32.292 99.299 32.31 99.336 ;
    END
  END b[100]
  PIN b[101]
    DIRECTION OUTPUT ;
    USE SIGNAL ;
    PORT
      LAYER M3 ;
        RECT  32.364 99.299 32.382 99.336 ;
    END
  END b[101]
  PIN b[102]
    DIRECTION OUTPUT ;
    USE SIGNAL ;
    PORT
      LAYER M3 ;
        RECT  32.436 99.299 32.454 99.336 ;
    END
  END b[102]
  PIN b[103]
    DIRECTION OUTPUT ;
    USE SIGNAL ;
    PORT
      LAYER M3 ;
        RECT  32.508 99.299 32.526 99.336 ;
    END
  END b[103]
  PIN b[104]
    DIRECTION OUTPUT ;
    USE SIGNAL ;
    PORT
      LAYER M3 ;
        RECT  32.58 99.299 32.598 99.336 ;
    END
  END b[104]
  PIN b[105]
    DIRECTION OUTPUT ;
    USE SIGNAL ;
    PORT
      LAYER M3 ;
        RECT  32.652 99.299 32.67 99.336 ;
    END
  END b[105]
  PIN b[106]
    DIRECTION OUTPUT ;
    USE SIGNAL ;
    PORT
      LAYER M3 ;
        RECT  32.724 99.299 32.742 99.336 ;
    END
  END b[106]
  PIN b[107]
    DIRECTION OUTPUT ;
    USE SIGNAL ;
    PORT
      LAYER M3 ;
        RECT  32.796 99.299 32.814 99.336 ;
    END
  END b[107]
  PIN b[108]
    DIRECTION OUTPUT ;
    USE SIGNAL ;
    PORT
      LAYER M3 ;
        RECT  32.868 99.299 32.886 99.336 ;
    END
  END b[108]
  PIN b[109]
    DIRECTION OUTPUT ;
    USE SIGNAL ;
    PORT
      LAYER M3 ;
        RECT  32.94 99.299 32.958 99.336 ;
    END
  END b[109]
  PIN b[10]
    DIRECTION OUTPUT ;
    USE SIGNAL ;
    PORT
      LAYER M5 ;
        RECT  23.568 99.252 23.592 99.336 ;
    END
  END b[10]
  PIN b[110]
    DIRECTION OUTPUT ;
    USE SIGNAL ;
    PORT
      LAYER M3 ;
        RECT  33.012 99.299 33.03 99.336 ;
    END
  END b[110]
  PIN b[111]
    DIRECTION OUTPUT ;
    USE SIGNAL ;
    PORT
      LAYER M3 ;
        RECT  33.084 99.299 33.102 99.336 ;
    END
  END b[111]
  PIN b[112]
    DIRECTION OUTPUT ;
    USE SIGNAL ;
    PORT
      LAYER M3 ;
        RECT  33.156 99.299 33.174 99.336 ;
    END
  END b[112]
  PIN b[113]
    DIRECTION OUTPUT ;
    USE SIGNAL ;
    PORT
      LAYER M3 ;
        RECT  33.228 99.299 33.246 99.336 ;
    END
  END b[113]
  PIN b[114]
    DIRECTION OUTPUT ;
    USE SIGNAL ;
    PORT
      LAYER M3 ;
        RECT  33.3 99.299 33.318 99.336 ;
    END
  END b[114]
  PIN b[115]
    DIRECTION OUTPUT ;
    USE SIGNAL ;
    PORT
      LAYER M3 ;
        RECT  33.372 99.299 33.39 99.336 ;
    END
  END b[115]
  PIN b[116]
    DIRECTION OUTPUT ;
    USE SIGNAL ;
    PORT
      LAYER M3 ;
        RECT  33.444 99.299 33.462 99.336 ;
    END
  END b[116]
  PIN b[117]
    DIRECTION OUTPUT ;
    USE SIGNAL ;
    PORT
      LAYER M3 ;
        RECT  33.516 99.299 33.534 99.336 ;
    END
  END b[117]
  PIN b[118]
    DIRECTION OUTPUT ;
    USE SIGNAL ;
    PORT
      LAYER M3 ;
        RECT  33.588 99.299 33.606 99.336 ;
    END
  END b[118]
  PIN b[119]
    DIRECTION OUTPUT ;
    USE SIGNAL ;
    PORT
      LAYER M3 ;
        RECT  33.66 99.299 33.678 99.336 ;
    END
  END b[119]
  PIN b[11]
    DIRECTION OUTPUT ;
    USE SIGNAL ;
    PORT
      LAYER M5 ;
        RECT  23.664 99.252 23.688 99.336 ;
    END
  END b[11]
  PIN b[120]
    DIRECTION OUTPUT ;
    USE SIGNAL ;
    PORT
      LAYER M3 ;
        RECT  33.732 99.299 33.75 99.336 ;
    END
  END b[120]
  PIN b[121]
    DIRECTION OUTPUT ;
    USE SIGNAL ;
    PORT
      LAYER M3 ;
        RECT  33.804 99.299 33.822 99.336 ;
    END
  END b[121]
  PIN b[122]
    DIRECTION OUTPUT ;
    USE SIGNAL ;
    PORT
      LAYER M3 ;
        RECT  33.876 99.299 33.894 99.336 ;
    END
  END b[122]
  PIN b[123]
    DIRECTION OUTPUT ;
    USE SIGNAL ;
    PORT
      LAYER M3 ;
        RECT  33.948 99.299 33.966 99.336 ;
    END
  END b[123]
  PIN b[124]
    DIRECTION OUTPUT ;
    USE SIGNAL ;
    PORT
      LAYER M3 ;
        RECT  34.02 99.299 34.038 99.336 ;
    END
  END b[124]
  PIN b[125]
    DIRECTION OUTPUT ;
    USE SIGNAL ;
    PORT
      LAYER M3 ;
        RECT  34.092 99.299 34.11 99.336 ;
    END
  END b[125]
  PIN b[126]
    DIRECTION OUTPUT ;
    USE SIGNAL ;
    PORT
      LAYER M3 ;
        RECT  34.164 99.299 34.182 99.336 ;
    END
  END b[126]
  PIN b[127]
    DIRECTION OUTPUT ;
    USE SIGNAL ;
    PORT
      LAYER M3 ;
        RECT  34.236 99.299 34.254 99.336 ;
    END
  END b[127]
  PIN b[128]
    DIRECTION OUTPUT ;
    USE SIGNAL ;
    PORT
      LAYER M3 ;
        RECT  46.404 99.299 46.422 99.336 ;
    END
  END b[128]
  PIN b[129]
    DIRECTION OUTPUT ;
    USE SIGNAL ;
    PORT
      LAYER M3 ;
        RECT  46.476 99.299 46.494 99.336 ;
    END
  END b[129]
  PIN b[12]
    DIRECTION OUTPUT ;
    USE SIGNAL ;
    PORT
      LAYER M5 ;
        RECT  23.76 99.252 23.784 99.336 ;
    END
  END b[12]
  PIN b[130]
    DIRECTION OUTPUT ;
    USE SIGNAL ;
    PORT
      LAYER M3 ;
        RECT  46.548 99.299 46.566 99.336 ;
    END
  END b[130]
  PIN b[131]
    DIRECTION OUTPUT ;
    USE SIGNAL ;
    PORT
      LAYER M3 ;
        RECT  46.62 99.299 46.638 99.336 ;
    END
  END b[131]
  PIN b[132]
    DIRECTION OUTPUT ;
    USE SIGNAL ;
    PORT
      LAYER M3 ;
        RECT  46.692 99.299 46.71 99.336 ;
    END
  END b[132]
  PIN b[133]
    DIRECTION OUTPUT ;
    USE SIGNAL ;
    PORT
      LAYER M3 ;
        RECT  46.764 99.299 46.782 99.336 ;
    END
  END b[133]
  PIN b[134]
    DIRECTION OUTPUT ;
    USE SIGNAL ;
    PORT
      LAYER M3 ;
        RECT  46.836 99.299 46.854 99.336 ;
    END
  END b[134]
  PIN b[135]
    DIRECTION OUTPUT ;
    USE SIGNAL ;
    PORT
      LAYER M3 ;
        RECT  46.908 99.299 46.926 99.336 ;
    END
  END b[135]
  PIN b[136]
    DIRECTION OUTPUT ;
    USE SIGNAL ;
    PORT
      LAYER M3 ;
        RECT  46.98 99.299 46.998 99.336 ;
    END
  END b[136]
  PIN b[137]
    DIRECTION OUTPUT ;
    USE SIGNAL ;
    PORT
      LAYER M3 ;
        RECT  47.052 99.299 47.07 99.336 ;
    END
  END b[137]
  PIN b[138]
    DIRECTION OUTPUT ;
    USE SIGNAL ;
    PORT
      LAYER M3 ;
        RECT  47.124 99.299 47.142 99.336 ;
    END
  END b[138]
  PIN b[139]
    DIRECTION OUTPUT ;
    USE SIGNAL ;
    PORT
      LAYER M3 ;
        RECT  47.196 99.299 47.214 99.336 ;
    END
  END b[139]
  PIN b[13]
    DIRECTION OUTPUT ;
    USE SIGNAL ;
    PORT
      LAYER M5 ;
        RECT  23.856 99.252 23.88 99.336 ;
    END
  END b[13]
  PIN b[140]
    DIRECTION OUTPUT ;
    USE SIGNAL ;
    PORT
      LAYER M3 ;
        RECT  47.268 99.299 47.286 99.336 ;
    END
  END b[140]
  PIN b[141]
    DIRECTION OUTPUT ;
    USE SIGNAL ;
    PORT
      LAYER M3 ;
        RECT  47.34 99.299 47.358 99.336 ;
    END
  END b[141]
  PIN b[142]
    DIRECTION OUTPUT ;
    USE SIGNAL ;
    PORT
      LAYER M3 ;
        RECT  47.412 99.299 47.43 99.336 ;
    END
  END b[142]
  PIN b[143]
    DIRECTION OUTPUT ;
    USE SIGNAL ;
    PORT
      LAYER M3 ;
        RECT  47.484 99.299 47.502 99.336 ;
    END
  END b[143]
  PIN b[144]
    DIRECTION OUTPUT ;
    USE SIGNAL ;
    PORT
      LAYER M3 ;
        RECT  47.556 99.299 47.574 99.336 ;
    END
  END b[144]
  PIN b[145]
    DIRECTION OUTPUT ;
    USE SIGNAL ;
    PORT
      LAYER M3 ;
        RECT  47.628 99.299 47.646 99.336 ;
    END
  END b[145]
  PIN b[146]
    DIRECTION OUTPUT ;
    USE SIGNAL ;
    PORT
      LAYER M3 ;
        RECT  47.7 99.299 47.718 99.336 ;
    END
  END b[146]
  PIN b[147]
    DIRECTION OUTPUT ;
    USE SIGNAL ;
    PORT
      LAYER M3 ;
        RECT  47.772 99.299 47.79 99.336 ;
    END
  END b[147]
  PIN b[148]
    DIRECTION OUTPUT ;
    USE SIGNAL ;
    PORT
      LAYER M3 ;
        RECT  47.844 99.299 47.862 99.336 ;
    END
  END b[148]
  PIN b[149]
    DIRECTION OUTPUT ;
    USE SIGNAL ;
    PORT
      LAYER M3 ;
        RECT  47.916 99.299 47.934 99.336 ;
    END
  END b[149]
  PIN b[14]
    DIRECTION OUTPUT ;
    USE SIGNAL ;
    PORT
      LAYER M5 ;
        RECT  23.952 99.252 23.976 99.336 ;
    END
  END b[14]
  PIN b[150]
    DIRECTION OUTPUT ;
    USE SIGNAL ;
    PORT
      LAYER M3 ;
        RECT  47.988 99.299 48.006 99.336 ;
    END
  END b[150]
  PIN b[151]
    DIRECTION OUTPUT ;
    USE SIGNAL ;
    PORT
      LAYER M3 ;
        RECT  48.06 99.299 48.078 99.336 ;
    END
  END b[151]
  PIN b[152]
    DIRECTION OUTPUT ;
    USE SIGNAL ;
    PORT
      LAYER M3 ;
        RECT  48.132 99.299 48.15 99.336 ;
    END
  END b[152]
  PIN b[153]
    DIRECTION OUTPUT ;
    USE SIGNAL ;
    PORT
      LAYER M3 ;
        RECT  48.204 99.299 48.222 99.336 ;
    END
  END b[153]
  PIN b[154]
    DIRECTION OUTPUT ;
    USE SIGNAL ;
    PORT
      LAYER M3 ;
        RECT  48.276 99.299 48.294 99.336 ;
    END
  END b[154]
  PIN b[155]
    DIRECTION OUTPUT ;
    USE SIGNAL ;
    PORT
      LAYER M3 ;
        RECT  48.348 99.299 48.366 99.336 ;
    END
  END b[155]
  PIN b[156]
    DIRECTION OUTPUT ;
    USE SIGNAL ;
    PORT
      LAYER M3 ;
        RECT  48.42 99.299 48.438 99.336 ;
    END
  END b[156]
  PIN b[157]
    DIRECTION OUTPUT ;
    USE SIGNAL ;
    PORT
      LAYER M3 ;
        RECT  48.492 99.299 48.51 99.336 ;
    END
  END b[157]
  PIN b[158]
    DIRECTION OUTPUT ;
    USE SIGNAL ;
    PORT
      LAYER M3 ;
        RECT  48.564 99.299 48.582 99.336 ;
    END
  END b[158]
  PIN b[159]
    DIRECTION OUTPUT ;
    USE SIGNAL ;
    PORT
      LAYER M3 ;
        RECT  48.636 99.299 48.654 99.336 ;
    END
  END b[159]
  PIN b[15]
    DIRECTION OUTPUT ;
    USE SIGNAL ;
    PORT
      LAYER M5 ;
        RECT  24.048 99.252 24.072 99.336 ;
    END
  END b[15]
  PIN b[160]
    DIRECTION OUTPUT ;
    USE SIGNAL ;
    PORT
      LAYER M3 ;
        RECT  41.796 99.299 41.814 99.336 ;
    END
  END b[160]
  PIN b[161]
    DIRECTION OUTPUT ;
    USE SIGNAL ;
    PORT
      LAYER M3 ;
        RECT  41.868 99.299 41.886 99.336 ;
    END
  END b[161]
  PIN b[162]
    DIRECTION OUTPUT ;
    USE SIGNAL ;
    PORT
      LAYER M3 ;
        RECT  41.94 99.299 41.958 99.336 ;
    END
  END b[162]
  PIN b[163]
    DIRECTION OUTPUT ;
    USE SIGNAL ;
    PORT
      LAYER M3 ;
        RECT  42.012 99.299 42.03 99.336 ;
    END
  END b[163]
  PIN b[164]
    DIRECTION OUTPUT ;
    USE SIGNAL ;
    PORT
      LAYER M3 ;
        RECT  42.084 99.299 42.102 99.336 ;
    END
  END b[164]
  PIN b[165]
    DIRECTION OUTPUT ;
    USE SIGNAL ;
    PORT
      LAYER M3 ;
        RECT  42.156 99.299 42.174 99.336 ;
    END
  END b[165]
  PIN b[166]
    DIRECTION OUTPUT ;
    USE SIGNAL ;
    PORT
      LAYER M3 ;
        RECT  42.228 99.299 42.246 99.336 ;
    END
  END b[166]
  PIN b[167]
    DIRECTION OUTPUT ;
    USE SIGNAL ;
    PORT
      LAYER M3 ;
        RECT  42.3 99.299 42.318 99.336 ;
    END
  END b[167]
  PIN b[168]
    DIRECTION OUTPUT ;
    USE SIGNAL ;
    PORT
      LAYER M3 ;
        RECT  42.372 99.299 42.39 99.336 ;
    END
  END b[168]
  PIN b[169]
    DIRECTION OUTPUT ;
    USE SIGNAL ;
    PORT
      LAYER M3 ;
        RECT  42.444 99.299 42.462 99.336 ;
    END
  END b[169]
  PIN b[16]
    DIRECTION OUTPUT ;
    USE SIGNAL ;
    PORT
      LAYER M5 ;
        RECT  24.144 99.252 24.168 99.336 ;
    END
  END b[16]
  PIN b[170]
    DIRECTION OUTPUT ;
    USE SIGNAL ;
    PORT
      LAYER M3 ;
        RECT  42.516 99.299 42.534 99.336 ;
    END
  END b[170]
  PIN b[171]
    DIRECTION OUTPUT ;
    USE SIGNAL ;
    PORT
      LAYER M3 ;
        RECT  42.588 99.299 42.606 99.336 ;
    END
  END b[171]
  PIN b[172]
    DIRECTION OUTPUT ;
    USE SIGNAL ;
    PORT
      LAYER M3 ;
        RECT  42.66 99.299 42.678 99.336 ;
    END
  END b[172]
  PIN b[173]
    DIRECTION OUTPUT ;
    USE SIGNAL ;
    PORT
      LAYER M3 ;
        RECT  42.732 99.299 42.75 99.336 ;
    END
  END b[173]
  PIN b[174]
    DIRECTION OUTPUT ;
    USE SIGNAL ;
    PORT
      LAYER M3 ;
        RECT  42.804 99.299 42.822 99.336 ;
    END
  END b[174]
  PIN b[175]
    DIRECTION OUTPUT ;
    USE SIGNAL ;
    PORT
      LAYER M3 ;
        RECT  42.876 99.299 42.894 99.336 ;
    END
  END b[175]
  PIN b[176]
    DIRECTION OUTPUT ;
    USE SIGNAL ;
    PORT
      LAYER M3 ;
        RECT  42.948 99.299 42.966 99.336 ;
    END
  END b[176]
  PIN b[177]
    DIRECTION OUTPUT ;
    USE SIGNAL ;
    PORT
      LAYER M3 ;
        RECT  43.02 99.299 43.038 99.336 ;
    END
  END b[177]
  PIN b[178]
    DIRECTION OUTPUT ;
    USE SIGNAL ;
    PORT
      LAYER M3 ;
        RECT  43.092 99.299 43.11 99.336 ;
    END
  END b[178]
  PIN b[179]
    DIRECTION OUTPUT ;
    USE SIGNAL ;
    PORT
      LAYER M3 ;
        RECT  43.164 99.299 43.182 99.336 ;
    END
  END b[179]
  PIN b[17]
    DIRECTION OUTPUT ;
    USE SIGNAL ;
    PORT
      LAYER M5 ;
        RECT  24.24 99.252 24.264 99.336 ;
    END
  END b[17]
  PIN b[180]
    DIRECTION OUTPUT ;
    USE SIGNAL ;
    PORT
      LAYER M3 ;
        RECT  43.236 99.299 43.254 99.336 ;
    END
  END b[180]
  PIN b[181]
    DIRECTION OUTPUT ;
    USE SIGNAL ;
    PORT
      LAYER M3 ;
        RECT  43.308 99.299 43.326 99.336 ;
    END
  END b[181]
  PIN b[182]
    DIRECTION OUTPUT ;
    USE SIGNAL ;
    PORT
      LAYER M3 ;
        RECT  43.38 99.299 43.398 99.336 ;
    END
  END b[182]
  PIN b[183]
    DIRECTION OUTPUT ;
    USE SIGNAL ;
    PORT
      LAYER M3 ;
        RECT  43.452 99.299 43.47 99.336 ;
    END
  END b[183]
  PIN b[184]
    DIRECTION OUTPUT ;
    USE SIGNAL ;
    PORT
      LAYER M3 ;
        RECT  43.524 99.299 43.542 99.336 ;
    END
  END b[184]
  PIN b[185]
    DIRECTION OUTPUT ;
    USE SIGNAL ;
    PORT
      LAYER M3 ;
        RECT  43.596 99.299 43.614 99.336 ;
    END
  END b[185]
  PIN b[186]
    DIRECTION OUTPUT ;
    USE SIGNAL ;
    PORT
      LAYER M3 ;
        RECT  43.668 99.299 43.686 99.336 ;
    END
  END b[186]
  PIN b[187]
    DIRECTION OUTPUT ;
    USE SIGNAL ;
    PORT
      LAYER M3 ;
        RECT  43.74 99.299 43.758 99.336 ;
    END
  END b[187]
  PIN b[188]
    DIRECTION OUTPUT ;
    USE SIGNAL ;
    PORT
      LAYER M3 ;
        RECT  43.812 99.299 43.83 99.336 ;
    END
  END b[188]
  PIN b[189]
    DIRECTION OUTPUT ;
    USE SIGNAL ;
    PORT
      LAYER M3 ;
        RECT  43.884 99.299 43.902 99.336 ;
    END
  END b[189]
  PIN b[18]
    DIRECTION OUTPUT ;
    USE SIGNAL ;
    PORT
      LAYER M5 ;
        RECT  24.336 99.252 24.36 99.336 ;
    END
  END b[18]
  PIN b[190]
    DIRECTION OUTPUT ;
    USE SIGNAL ;
    PORT
      LAYER M3 ;
        RECT  43.956 99.299 43.974 99.336 ;
    END
  END b[190]
  PIN b[191]
    DIRECTION OUTPUT ;
    USE SIGNAL ;
    PORT
      LAYER M3 ;
        RECT  44.028 99.299 44.046 99.336 ;
    END
  END b[191]
  PIN b[192]
    DIRECTION OUTPUT ;
    USE SIGNAL ;
    PORT
      LAYER M5 ;
        RECT  47.952 99.252 47.976 99.336 ;
    END
  END b[192]
  PIN b[193]
    DIRECTION OUTPUT ;
    USE SIGNAL ;
    PORT
      LAYER M5 ;
        RECT  48.048 99.252 48.072 99.336 ;
    END
  END b[193]
  PIN b[194]
    DIRECTION OUTPUT ;
    USE SIGNAL ;
    PORT
      LAYER M5 ;
        RECT  48.144 99.252 48.168 99.336 ;
    END
  END b[194]
  PIN b[195]
    DIRECTION OUTPUT ;
    USE SIGNAL ;
    PORT
      LAYER M5 ;
        RECT  48.24 99.252 48.264 99.336 ;
    END
  END b[195]
  PIN b[196]
    DIRECTION OUTPUT ;
    USE SIGNAL ;
    PORT
      LAYER M5 ;
        RECT  48.336 99.252 48.36 99.336 ;
    END
  END b[196]
  PIN b[197]
    DIRECTION OUTPUT ;
    USE SIGNAL ;
    PORT
      LAYER M5 ;
        RECT  48.432 99.252 48.456 99.336 ;
    END
  END b[197]
  PIN b[198]
    DIRECTION OUTPUT ;
    USE SIGNAL ;
    PORT
      LAYER M5 ;
        RECT  48.528 99.252 48.552 99.336 ;
    END
  END b[198]
  PIN b[199]
    DIRECTION OUTPUT ;
    USE SIGNAL ;
    PORT
      LAYER M5 ;
        RECT  48.624 99.252 48.648 99.336 ;
    END
  END b[199]
  PIN b[19]
    DIRECTION OUTPUT ;
    USE SIGNAL ;
    PORT
      LAYER M5 ;
        RECT  24.432 99.252 24.456 99.336 ;
    END
  END b[19]
  PIN b[1]
    DIRECTION OUTPUT ;
    USE SIGNAL ;
    PORT
      LAYER M5 ;
        RECT  22.704 99.252 22.728 99.336 ;
    END
  END b[1]
  PIN b[200]
    DIRECTION OUTPUT ;
    USE SIGNAL ;
    PORT
      LAYER M5 ;
        RECT  48.72 99.252 48.744 99.336 ;
    END
  END b[200]
  PIN b[201]
    DIRECTION OUTPUT ;
    USE SIGNAL ;
    PORT
      LAYER M5 ;
        RECT  48.816 99.252 48.84 99.336 ;
    END
  END b[201]
  PIN b[202]
    DIRECTION OUTPUT ;
    USE SIGNAL ;
    PORT
      LAYER M5 ;
        RECT  48.912 99.252 48.936 99.336 ;
    END
  END b[202]
  PIN b[203]
    DIRECTION OUTPUT ;
    USE SIGNAL ;
    PORT
      LAYER M5 ;
        RECT  49.008 99.252 49.032 99.336 ;
    END
  END b[203]
  PIN b[204]
    DIRECTION OUTPUT ;
    USE SIGNAL ;
    PORT
      LAYER M5 ;
        RECT  49.104 99.252 49.128 99.336 ;
    END
  END b[204]
  PIN b[205]
    DIRECTION OUTPUT ;
    USE SIGNAL ;
    PORT
      LAYER M5 ;
        RECT  49.2 99.252 49.224 99.336 ;
    END
  END b[205]
  PIN b[206]
    DIRECTION OUTPUT ;
    USE SIGNAL ;
    PORT
      LAYER M5 ;
        RECT  49.296 99.252 49.32 99.336 ;
    END
  END b[206]
  PIN b[207]
    DIRECTION OUTPUT ;
    USE SIGNAL ;
    PORT
      LAYER M5 ;
        RECT  49.392 99.252 49.416 99.336 ;
    END
  END b[207]
  PIN b[208]
    DIRECTION OUTPUT ;
    USE SIGNAL ;
    PORT
      LAYER M5 ;
        RECT  49.488 99.252 49.512 99.336 ;
    END
  END b[208]
  PIN b[209]
    DIRECTION OUTPUT ;
    USE SIGNAL ;
    PORT
      LAYER M5 ;
        RECT  49.584 99.252 49.608 99.336 ;
    END
  END b[209]
  PIN b[20]
    DIRECTION OUTPUT ;
    USE SIGNAL ;
    PORT
      LAYER M5 ;
        RECT  24.528 99.252 24.552 99.336 ;
    END
  END b[20]
  PIN b[210]
    DIRECTION OUTPUT ;
    USE SIGNAL ;
    PORT
      LAYER M5 ;
        RECT  49.68 99.252 49.704 99.336 ;
    END
  END b[210]
  PIN b[211]
    DIRECTION OUTPUT ;
    USE SIGNAL ;
    PORT
      LAYER M5 ;
        RECT  49.776 99.252 49.8 99.336 ;
    END
  END b[211]
  PIN b[212]
    DIRECTION OUTPUT ;
    USE SIGNAL ;
    PORT
      LAYER M5 ;
        RECT  49.872 99.252 49.896 99.336 ;
    END
  END b[212]
  PIN b[213]
    DIRECTION OUTPUT ;
    USE SIGNAL ;
    PORT
      LAYER M5 ;
        RECT  49.968 99.252 49.992 99.336 ;
    END
  END b[213]
  PIN b[214]
    DIRECTION OUTPUT ;
    USE SIGNAL ;
    PORT
      LAYER M5 ;
        RECT  50.064 99.252 50.088 99.336 ;
    END
  END b[214]
  PIN b[215]
    DIRECTION OUTPUT ;
    USE SIGNAL ;
    PORT
      LAYER M5 ;
        RECT  50.16 99.252 50.184 99.336 ;
    END
  END b[215]
  PIN b[216]
    DIRECTION OUTPUT ;
    USE SIGNAL ;
    PORT
      LAYER M5 ;
        RECT  50.256 99.252 50.28 99.336 ;
    END
  END b[216]
  PIN b[217]
    DIRECTION OUTPUT ;
    USE SIGNAL ;
    PORT
      LAYER M5 ;
        RECT  50.352 99.252 50.376 99.336 ;
    END
  END b[217]
  PIN b[218]
    DIRECTION OUTPUT ;
    USE SIGNAL ;
    PORT
      LAYER M5 ;
        RECT  50.448 99.252 50.472 99.336 ;
    END
  END b[218]
  PIN b[219]
    DIRECTION OUTPUT ;
    USE SIGNAL ;
    PORT
      LAYER M5 ;
        RECT  50.544 99.252 50.568 99.336 ;
    END
  END b[219]
  PIN b[21]
    DIRECTION OUTPUT ;
    USE SIGNAL ;
    PORT
      LAYER M5 ;
        RECT  24.624 99.252 24.648 99.336 ;
    END
  END b[21]
  PIN b[220]
    DIRECTION OUTPUT ;
    USE SIGNAL ;
    PORT
      LAYER M5 ;
        RECT  50.64 99.252 50.664 99.336 ;
    END
  END b[220]
  PIN b[221]
    DIRECTION OUTPUT ;
    USE SIGNAL ;
    PORT
      LAYER M5 ;
        RECT  50.736 99.252 50.76 99.336 ;
    END
  END b[221]
  PIN b[222]
    DIRECTION OUTPUT ;
    USE SIGNAL ;
    PORT
      LAYER M5 ;
        RECT  50.832 99.252 50.856 99.336 ;
    END
  END b[222]
  PIN b[223]
    DIRECTION OUTPUT ;
    USE SIGNAL ;
    PORT
      LAYER M5 ;
        RECT  50.928 99.252 50.952 99.336 ;
    END
  END b[223]
  PIN b[224]
    DIRECTION OUTPUT ;
    USE SIGNAL ;
    PORT
      LAYER M3 ;
        RECT  60.804 99.299 60.822 99.336 ;
    END
  END b[224]
  PIN b[225]
    DIRECTION OUTPUT ;
    USE SIGNAL ;
    PORT
      LAYER M3 ;
        RECT  60.876 99.299 60.894 99.336 ;
    END
  END b[225]
  PIN b[226]
    DIRECTION OUTPUT ;
    USE SIGNAL ;
    PORT
      LAYER M3 ;
        RECT  60.948 99.299 60.966 99.336 ;
    END
  END b[226]
  PIN b[227]
    DIRECTION OUTPUT ;
    USE SIGNAL ;
    PORT
      LAYER M3 ;
        RECT  61.02 99.299 61.038 99.336 ;
    END
  END b[227]
  PIN b[228]
    DIRECTION OUTPUT ;
    USE SIGNAL ;
    PORT
      LAYER M3 ;
        RECT  61.092 99.299 61.11 99.336 ;
    END
  END b[228]
  PIN b[229]
    DIRECTION OUTPUT ;
    USE SIGNAL ;
    PORT
      LAYER M3 ;
        RECT  61.164 99.299 61.182 99.336 ;
    END
  END b[229]
  PIN b[22]
    DIRECTION OUTPUT ;
    USE SIGNAL ;
    PORT
      LAYER M5 ;
        RECT  24.72 99.252 24.744 99.336 ;
    END
  END b[22]
  PIN b[230]
    DIRECTION OUTPUT ;
    USE SIGNAL ;
    PORT
      LAYER M3 ;
        RECT  61.236 99.299 61.254 99.336 ;
    END
  END b[230]
  PIN b[231]
    DIRECTION OUTPUT ;
    USE SIGNAL ;
    PORT
      LAYER M3 ;
        RECT  61.308 99.299 61.326 99.336 ;
    END
  END b[231]
  PIN b[232]
    DIRECTION OUTPUT ;
    USE SIGNAL ;
    PORT
      LAYER M3 ;
        RECT  61.38 99.299 61.398 99.336 ;
    END
  END b[232]
  PIN b[233]
    DIRECTION OUTPUT ;
    USE SIGNAL ;
    PORT
      LAYER M3 ;
        RECT  61.452 99.299 61.47 99.336 ;
    END
  END b[233]
  PIN b[234]
    DIRECTION OUTPUT ;
    USE SIGNAL ;
    PORT
      LAYER M3 ;
        RECT  61.524 99.299 61.542 99.336 ;
    END
  END b[234]
  PIN b[235]
    DIRECTION OUTPUT ;
    USE SIGNAL ;
    PORT
      LAYER M3 ;
        RECT  61.596 99.299 61.614 99.336 ;
    END
  END b[235]
  PIN b[236]
    DIRECTION OUTPUT ;
    USE SIGNAL ;
    PORT
      LAYER M3 ;
        RECT  61.668 99.299 61.686 99.336 ;
    END
  END b[236]
  PIN b[237]
    DIRECTION OUTPUT ;
    USE SIGNAL ;
    PORT
      LAYER M3 ;
        RECT  61.74 99.299 61.758 99.336 ;
    END
  END b[237]
  PIN b[238]
    DIRECTION OUTPUT ;
    USE SIGNAL ;
    PORT
      LAYER M3 ;
        RECT  61.812 99.299 61.83 99.336 ;
    END
  END b[238]
  PIN b[239]
    DIRECTION OUTPUT ;
    USE SIGNAL ;
    PORT
      LAYER M3 ;
        RECT  61.884 99.299 61.902 99.336 ;
    END
  END b[239]
  PIN b[23]
    DIRECTION OUTPUT ;
    USE SIGNAL ;
    PORT
      LAYER M5 ;
        RECT  24.816 99.252 24.84 99.336 ;
    END
  END b[23]
  PIN b[240]
    DIRECTION OUTPUT ;
    USE SIGNAL ;
    PORT
      LAYER M3 ;
        RECT  61.956 99.299 61.974 99.336 ;
    END
  END b[240]
  PIN b[241]
    DIRECTION OUTPUT ;
    USE SIGNAL ;
    PORT
      LAYER M3 ;
        RECT  62.028 99.299 62.046 99.336 ;
    END
  END b[241]
  PIN b[242]
    DIRECTION OUTPUT ;
    USE SIGNAL ;
    PORT
      LAYER M3 ;
        RECT  62.1 99.299 62.118 99.336 ;
    END
  END b[242]
  PIN b[243]
    DIRECTION OUTPUT ;
    USE SIGNAL ;
    PORT
      LAYER M3 ;
        RECT  62.172 99.299 62.19 99.336 ;
    END
  END b[243]
  PIN b[244]
    DIRECTION OUTPUT ;
    USE SIGNAL ;
    PORT
      LAYER M3 ;
        RECT  62.244 99.299 62.262 99.336 ;
    END
  END b[244]
  PIN b[245]
    DIRECTION OUTPUT ;
    USE SIGNAL ;
    PORT
      LAYER M3 ;
        RECT  62.316 99.299 62.334 99.336 ;
    END
  END b[245]
  PIN b[246]
    DIRECTION OUTPUT ;
    USE SIGNAL ;
    PORT
      LAYER M3 ;
        RECT  62.388 99.299 62.406 99.336 ;
    END
  END b[246]
  PIN b[247]
    DIRECTION OUTPUT ;
    USE SIGNAL ;
    PORT
      LAYER M3 ;
        RECT  62.46 99.299 62.478 99.336 ;
    END
  END b[247]
  PIN b[248]
    DIRECTION OUTPUT ;
    USE SIGNAL ;
    PORT
      LAYER M3 ;
        RECT  62.532 99.299 62.55 99.336 ;
    END
  END b[248]
  PIN b[249]
    DIRECTION OUTPUT ;
    USE SIGNAL ;
    PORT
      LAYER M3 ;
        RECT  62.604 99.299 62.622 99.336 ;
    END
  END b[249]
  PIN b[24]
    DIRECTION OUTPUT ;
    USE SIGNAL ;
    PORT
      LAYER M5 ;
        RECT  24.912 99.252 24.936 99.336 ;
    END
  END b[24]
  PIN b[250]
    DIRECTION OUTPUT ;
    USE SIGNAL ;
    PORT
      LAYER M3 ;
        RECT  62.676 99.299 62.694 99.336 ;
    END
  END b[250]
  PIN b[251]
    DIRECTION OUTPUT ;
    USE SIGNAL ;
    PORT
      LAYER M3 ;
        RECT  62.748 99.299 62.766 99.336 ;
    END
  END b[251]
  PIN b[252]
    DIRECTION OUTPUT ;
    USE SIGNAL ;
    PORT
      LAYER M3 ;
        RECT  62.82 99.299 62.838 99.336 ;
    END
  END b[252]
  PIN b[253]
    DIRECTION OUTPUT ;
    USE SIGNAL ;
    PORT
      LAYER M3 ;
        RECT  62.892 99.299 62.91 99.336 ;
    END
  END b[253]
  PIN b[254]
    DIRECTION OUTPUT ;
    USE SIGNAL ;
    PORT
      LAYER M3 ;
        RECT  62.964 99.299 62.982 99.336 ;
    END
  END b[254]
  PIN b[255]
    DIRECTION OUTPUT ;
    USE SIGNAL ;
    PORT
      LAYER M3 ;
        RECT  63.036 99.299 63.054 99.336 ;
    END
  END b[255]
  PIN b[256]
    DIRECTION OUTPUT ;
    USE SIGNAL ;
    PORT
      LAYER M3 ;
        RECT  72.9 99.299 72.918 99.336 ;
    END
  END b[256]
  PIN b[257]
    DIRECTION OUTPUT ;
    USE SIGNAL ;
    PORT
      LAYER M3 ;
        RECT  72.972 99.299 72.99 99.336 ;
    END
  END b[257]
  PIN b[258]
    DIRECTION OUTPUT ;
    USE SIGNAL ;
    PORT
      LAYER M3 ;
        RECT  73.044 99.299 73.062 99.336 ;
    END
  END b[258]
  PIN b[259]
    DIRECTION OUTPUT ;
    USE SIGNAL ;
    PORT
      LAYER M3 ;
        RECT  73.116 99.299 73.134 99.336 ;
    END
  END b[259]
  PIN b[25]
    DIRECTION OUTPUT ;
    USE SIGNAL ;
    PORT
      LAYER M5 ;
        RECT  25.008 99.252 25.032 99.336 ;
    END
  END b[25]
  PIN b[260]
    DIRECTION OUTPUT ;
    USE SIGNAL ;
    PORT
      LAYER M3 ;
        RECT  73.188 99.299 73.206 99.336 ;
    END
  END b[260]
  PIN b[261]
    DIRECTION OUTPUT ;
    USE SIGNAL ;
    PORT
      LAYER M3 ;
        RECT  73.26 99.299 73.278 99.336 ;
    END
  END b[261]
  PIN b[262]
    DIRECTION OUTPUT ;
    USE SIGNAL ;
    PORT
      LAYER M3 ;
        RECT  73.332 99.299 73.35 99.336 ;
    END
  END b[262]
  PIN b[263]
    DIRECTION OUTPUT ;
    USE SIGNAL ;
    PORT
      LAYER M3 ;
        RECT  73.404 99.299 73.422 99.336 ;
    END
  END b[263]
  PIN b[264]
    DIRECTION OUTPUT ;
    USE SIGNAL ;
    PORT
      LAYER M3 ;
        RECT  73.476 99.299 73.494 99.336 ;
    END
  END b[264]
  PIN b[265]
    DIRECTION OUTPUT ;
    USE SIGNAL ;
    PORT
      LAYER M3 ;
        RECT  73.548 99.299 73.566 99.336 ;
    END
  END b[265]
  PIN b[266]
    DIRECTION OUTPUT ;
    USE SIGNAL ;
    PORT
      LAYER M3 ;
        RECT  73.62 99.299 73.638 99.336 ;
    END
  END b[266]
  PIN b[267]
    DIRECTION OUTPUT ;
    USE SIGNAL ;
    PORT
      LAYER M3 ;
        RECT  73.692 99.299 73.71 99.336 ;
    END
  END b[267]
  PIN b[268]
    DIRECTION OUTPUT ;
    USE SIGNAL ;
    PORT
      LAYER M3 ;
        RECT  73.764 99.299 73.782 99.336 ;
    END
  END b[268]
  PIN b[269]
    DIRECTION OUTPUT ;
    USE SIGNAL ;
    PORT
      LAYER M3 ;
        RECT  73.836 99.299 73.854 99.336 ;
    END
  END b[269]
  PIN b[26]
    DIRECTION OUTPUT ;
    USE SIGNAL ;
    PORT
      LAYER M5 ;
        RECT  25.104 99.252 25.128 99.336 ;
    END
  END b[26]
  PIN b[270]
    DIRECTION OUTPUT ;
    USE SIGNAL ;
    PORT
      LAYER M3 ;
        RECT  73.908 99.299 73.926 99.336 ;
    END
  END b[270]
  PIN b[271]
    DIRECTION OUTPUT ;
    USE SIGNAL ;
    PORT
      LAYER M3 ;
        RECT  73.98 99.299 73.998 99.336 ;
    END
  END b[271]
  PIN b[272]
    DIRECTION OUTPUT ;
    USE SIGNAL ;
    PORT
      LAYER M3 ;
        RECT  74.052 99.299 74.07 99.336 ;
    END
  END b[272]
  PIN b[273]
    DIRECTION OUTPUT ;
    USE SIGNAL ;
    PORT
      LAYER M3 ;
        RECT  74.124 99.299 74.142 99.336 ;
    END
  END b[273]
  PIN b[274]
    DIRECTION OUTPUT ;
    USE SIGNAL ;
    PORT
      LAYER M3 ;
        RECT  74.196 99.299 74.214 99.336 ;
    END
  END b[274]
  PIN b[275]
    DIRECTION OUTPUT ;
    USE SIGNAL ;
    PORT
      LAYER M3 ;
        RECT  74.268 99.299 74.286 99.336 ;
    END
  END b[275]
  PIN b[276]
    DIRECTION OUTPUT ;
    USE SIGNAL ;
    PORT
      LAYER M3 ;
        RECT  74.34 99.299 74.358 99.336 ;
    END
  END b[276]
  PIN b[277]
    DIRECTION OUTPUT ;
    USE SIGNAL ;
    PORT
      LAYER M3 ;
        RECT  74.412 99.299 74.43 99.336 ;
    END
  END b[277]
  PIN b[278]
    DIRECTION OUTPUT ;
    USE SIGNAL ;
    PORT
      LAYER M3 ;
        RECT  74.484 99.299 74.502 99.336 ;
    END
  END b[278]
  PIN b[279]
    DIRECTION OUTPUT ;
    USE SIGNAL ;
    PORT
      LAYER M3 ;
        RECT  74.556 99.299 74.574 99.336 ;
    END
  END b[279]
  PIN b[27]
    DIRECTION OUTPUT ;
    USE SIGNAL ;
    PORT
      LAYER M5 ;
        RECT  25.2 99.252 25.224 99.336 ;
    END
  END b[27]
  PIN b[280]
    DIRECTION OUTPUT ;
    USE SIGNAL ;
    PORT
      LAYER M3 ;
        RECT  74.628 99.299 74.646 99.336 ;
    END
  END b[280]
  PIN b[281]
    DIRECTION OUTPUT ;
    USE SIGNAL ;
    PORT
      LAYER M3 ;
        RECT  74.7 99.299 74.718 99.336 ;
    END
  END b[281]
  PIN b[282]
    DIRECTION OUTPUT ;
    USE SIGNAL ;
    PORT
      LAYER M3 ;
        RECT  74.772 99.299 74.79 99.336 ;
    END
  END b[282]
  PIN b[283]
    DIRECTION OUTPUT ;
    USE SIGNAL ;
    PORT
      LAYER M3 ;
        RECT  74.844 99.299 74.862 99.336 ;
    END
  END b[283]
  PIN b[284]
    DIRECTION OUTPUT ;
    USE SIGNAL ;
    PORT
      LAYER M3 ;
        RECT  74.916 99.299 74.934 99.336 ;
    END
  END b[284]
  PIN b[285]
    DIRECTION OUTPUT ;
    USE SIGNAL ;
    PORT
      LAYER M3 ;
        RECT  74.988 99.299 75.006 99.336 ;
    END
  END b[285]
  PIN b[286]
    DIRECTION OUTPUT ;
    USE SIGNAL ;
    PORT
      LAYER M3 ;
        RECT  75.06 99.299 75.078 99.336 ;
    END
  END b[286]
  PIN b[287]
    DIRECTION OUTPUT ;
    USE SIGNAL ;
    PORT
      LAYER M3 ;
        RECT  75.132 99.299 75.15 99.336 ;
    END
  END b[287]
  PIN b[288]
    DIRECTION OUTPUT ;
    USE SIGNAL ;
    PORT
      LAYER M5 ;
        RECT  70.224 99.252 70.248 99.336 ;
    END
  END b[288]
  PIN b[289]
    DIRECTION OUTPUT ;
    USE SIGNAL ;
    PORT
      LAYER M5 ;
        RECT  70.32 99.252 70.344 99.336 ;
    END
  END b[289]
  PIN b[28]
    DIRECTION OUTPUT ;
    USE SIGNAL ;
    PORT
      LAYER M5 ;
        RECT  25.296 99.252 25.32 99.336 ;
    END
  END b[28]
  PIN b[290]
    DIRECTION OUTPUT ;
    USE SIGNAL ;
    PORT
      LAYER M5 ;
        RECT  70.416 99.252 70.44 99.336 ;
    END
  END b[290]
  PIN b[291]
    DIRECTION OUTPUT ;
    USE SIGNAL ;
    PORT
      LAYER M5 ;
        RECT  70.512 99.252 70.536 99.336 ;
    END
  END b[291]
  PIN b[292]
    DIRECTION OUTPUT ;
    USE SIGNAL ;
    PORT
      LAYER M5 ;
        RECT  70.608 99.252 70.632 99.336 ;
    END
  END b[292]
  PIN b[293]
    DIRECTION OUTPUT ;
    USE SIGNAL ;
    PORT
      LAYER M5 ;
        RECT  70.704 99.252 70.728 99.336 ;
    END
  END b[293]
  PIN b[294]
    DIRECTION OUTPUT ;
    USE SIGNAL ;
    PORT
      LAYER M5 ;
        RECT  70.8 99.252 70.824 99.336 ;
    END
  END b[294]
  PIN b[295]
    DIRECTION OUTPUT ;
    USE SIGNAL ;
    PORT
      LAYER M5 ;
        RECT  70.896 99.252 70.92 99.336 ;
    END
  END b[295]
  PIN b[296]
    DIRECTION OUTPUT ;
    USE SIGNAL ;
    PORT
      LAYER M5 ;
        RECT  70.992 99.252 71.016 99.336 ;
    END
  END b[296]
  PIN b[297]
    DIRECTION OUTPUT ;
    USE SIGNAL ;
    PORT
      LAYER M5 ;
        RECT  71.088 99.252 71.112 99.336 ;
    END
  END b[297]
  PIN b[298]
    DIRECTION OUTPUT ;
    USE SIGNAL ;
    PORT
      LAYER M5 ;
        RECT  71.184 99.252 71.208 99.336 ;
    END
  END b[298]
  PIN b[299]
    DIRECTION OUTPUT ;
    USE SIGNAL ;
    PORT
      LAYER M5 ;
        RECT  71.28 99.252 71.304 99.336 ;
    END
  END b[299]
  PIN b[29]
    DIRECTION OUTPUT ;
    USE SIGNAL ;
    PORT
      LAYER M5 ;
        RECT  25.392 99.252 25.416 99.336 ;
    END
  END b[29]
  PIN b[2]
    DIRECTION OUTPUT ;
    USE SIGNAL ;
    PORT
      LAYER M5 ;
        RECT  22.8 99.252 22.824 99.336 ;
    END
  END b[2]
  PIN b[300]
    DIRECTION OUTPUT ;
    USE SIGNAL ;
    PORT
      LAYER M5 ;
        RECT  71.376 99.252 71.4 99.336 ;
    END
  END b[300]
  PIN b[301]
    DIRECTION OUTPUT ;
    USE SIGNAL ;
    PORT
      LAYER M5 ;
        RECT  71.472 99.252 71.496 99.336 ;
    END
  END b[301]
  PIN b[302]
    DIRECTION OUTPUT ;
    USE SIGNAL ;
    PORT
      LAYER M5 ;
        RECT  71.568 99.252 71.592 99.336 ;
    END
  END b[302]
  PIN b[303]
    DIRECTION OUTPUT ;
    USE SIGNAL ;
    PORT
      LAYER M5 ;
        RECT  71.664 99.252 71.688 99.336 ;
    END
  END b[303]
  PIN b[304]
    DIRECTION OUTPUT ;
    USE SIGNAL ;
    PORT
      LAYER M5 ;
        RECT  71.76 99.252 71.784 99.336 ;
    END
  END b[304]
  PIN b[305]
    DIRECTION OUTPUT ;
    USE SIGNAL ;
    PORT
      LAYER M5 ;
        RECT  71.856 99.252 71.88 99.336 ;
    END
  END b[305]
  PIN b[306]
    DIRECTION OUTPUT ;
    USE SIGNAL ;
    PORT
      LAYER M5 ;
        RECT  71.952 99.252 71.976 99.336 ;
    END
  END b[306]
  PIN b[307]
    DIRECTION OUTPUT ;
    USE SIGNAL ;
    PORT
      LAYER M5 ;
        RECT  72.048 99.252 72.072 99.336 ;
    END
  END b[307]
  PIN b[308]
    DIRECTION OUTPUT ;
    USE SIGNAL ;
    PORT
      LAYER M5 ;
        RECT  72.144 99.252 72.168 99.336 ;
    END
  END b[308]
  PIN b[309]
    DIRECTION OUTPUT ;
    USE SIGNAL ;
    PORT
      LAYER M5 ;
        RECT  72.24 99.252 72.264 99.336 ;
    END
  END b[309]
  PIN b[30]
    DIRECTION OUTPUT ;
    USE SIGNAL ;
    PORT
      LAYER M5 ;
        RECT  25.488 99.252 25.512 99.336 ;
    END
  END b[30]
  PIN b[310]
    DIRECTION OUTPUT ;
    USE SIGNAL ;
    PORT
      LAYER M5 ;
        RECT  72.336 99.252 72.36 99.336 ;
    END
  END b[310]
  PIN b[311]
    DIRECTION OUTPUT ;
    USE SIGNAL ;
    PORT
      LAYER M5 ;
        RECT  72.432 99.252 72.456 99.336 ;
    END
  END b[311]
  PIN b[312]
    DIRECTION OUTPUT ;
    USE SIGNAL ;
    PORT
      LAYER M5 ;
        RECT  72.528 99.252 72.552 99.336 ;
    END
  END b[312]
  PIN b[313]
    DIRECTION OUTPUT ;
    USE SIGNAL ;
    PORT
      LAYER M5 ;
        RECT  72.624 99.252 72.648 99.336 ;
    END
  END b[313]
  PIN b[314]
    DIRECTION OUTPUT ;
    USE SIGNAL ;
    PORT
      LAYER M5 ;
        RECT  72.72 99.252 72.744 99.336 ;
    END
  END b[314]
  PIN b[315]
    DIRECTION OUTPUT ;
    USE SIGNAL ;
    PORT
      LAYER M5 ;
        RECT  72.816 99.252 72.84 99.336 ;
    END
  END b[315]
  PIN b[316]
    DIRECTION OUTPUT ;
    USE SIGNAL ;
    PORT
      LAYER M5 ;
        RECT  72.912 99.252 72.936 99.336 ;
    END
  END b[316]
  PIN b[317]
    DIRECTION OUTPUT ;
    USE SIGNAL ;
    PORT
      LAYER M5 ;
        RECT  73.008 99.252 73.032 99.336 ;
    END
  END b[317]
  PIN b[318]
    DIRECTION OUTPUT ;
    USE SIGNAL ;
    PORT
      LAYER M5 ;
        RECT  73.104 99.252 73.128 99.336 ;
    END
  END b[318]
  PIN b[319]
    DIRECTION OUTPUT ;
    USE SIGNAL ;
    PORT
      LAYER M5 ;
        RECT  73.2 99.252 73.224 99.336 ;
    END
  END b[319]
  PIN b[31]
    DIRECTION OUTPUT ;
    USE SIGNAL ;
    PORT
      LAYER M5 ;
        RECT  25.584 99.252 25.608 99.336 ;
    END
  END b[31]
  PIN b[320]
    DIRECTION OUTPUT ;
    USE SIGNAL ;
    PORT
      LAYER M5 ;
        RECT  64.08 99.252 64.104 99.336 ;
    END
  END b[320]
  PIN b[321]
    DIRECTION OUTPUT ;
    USE SIGNAL ;
    PORT
      LAYER M5 ;
        RECT  64.176 99.252 64.2 99.336 ;
    END
  END b[321]
  PIN b[322]
    DIRECTION OUTPUT ;
    USE SIGNAL ;
    PORT
      LAYER M5 ;
        RECT  64.272 99.252 64.296 99.336 ;
    END
  END b[322]
  PIN b[323]
    DIRECTION OUTPUT ;
    USE SIGNAL ;
    PORT
      LAYER M5 ;
        RECT  64.368 99.252 64.392 99.336 ;
    END
  END b[323]
  PIN b[324]
    DIRECTION OUTPUT ;
    USE SIGNAL ;
    PORT
      LAYER M5 ;
        RECT  64.464 99.252 64.488 99.336 ;
    END
  END b[324]
  PIN b[325]
    DIRECTION OUTPUT ;
    USE SIGNAL ;
    PORT
      LAYER M5 ;
        RECT  64.56 99.252 64.584 99.336 ;
    END
  END b[325]
  PIN b[326]
    DIRECTION OUTPUT ;
    USE SIGNAL ;
    PORT
      LAYER M5 ;
        RECT  64.656 99.252 64.68 99.336 ;
    END
  END b[326]
  PIN b[327]
    DIRECTION OUTPUT ;
    USE SIGNAL ;
    PORT
      LAYER M5 ;
        RECT  64.752 99.252 64.776 99.336 ;
    END
  END b[327]
  PIN b[328]
    DIRECTION OUTPUT ;
    USE SIGNAL ;
    PORT
      LAYER M5 ;
        RECT  64.848 99.252 64.872 99.336 ;
    END
  END b[328]
  PIN b[329]
    DIRECTION OUTPUT ;
    USE SIGNAL ;
    PORT
      LAYER M5 ;
        RECT  64.944 99.252 64.968 99.336 ;
    END
  END b[329]
  PIN b[32]
    DIRECTION OUTPUT ;
    USE SIGNAL ;
    PORT
      LAYER M3 ;
        RECT  24.516 99.299 24.534 99.336 ;
    END
  END b[32]
  PIN b[330]
    DIRECTION OUTPUT ;
    USE SIGNAL ;
    PORT
      LAYER M5 ;
        RECT  65.04 99.252 65.064 99.336 ;
    END
  END b[330]
  PIN b[331]
    DIRECTION OUTPUT ;
    USE SIGNAL ;
    PORT
      LAYER M5 ;
        RECT  65.136 99.252 65.16 99.336 ;
    END
  END b[331]
  PIN b[332]
    DIRECTION OUTPUT ;
    USE SIGNAL ;
    PORT
      LAYER M5 ;
        RECT  65.232 99.252 65.256 99.336 ;
    END
  END b[332]
  PIN b[333]
    DIRECTION OUTPUT ;
    USE SIGNAL ;
    PORT
      LAYER M5 ;
        RECT  65.328 99.252 65.352 99.336 ;
    END
  END b[333]
  PIN b[334]
    DIRECTION OUTPUT ;
    USE SIGNAL ;
    PORT
      LAYER M5 ;
        RECT  65.424 99.252 65.448 99.336 ;
    END
  END b[334]
  PIN b[335]
    DIRECTION OUTPUT ;
    USE SIGNAL ;
    PORT
      LAYER M5 ;
        RECT  65.52 99.252 65.544 99.336 ;
    END
  END b[335]
  PIN b[336]
    DIRECTION OUTPUT ;
    USE SIGNAL ;
    PORT
      LAYER M5 ;
        RECT  65.616 99.252 65.64 99.336 ;
    END
  END b[336]
  PIN b[337]
    DIRECTION OUTPUT ;
    USE SIGNAL ;
    PORT
      LAYER M5 ;
        RECT  65.712 99.252 65.736 99.336 ;
    END
  END b[337]
  PIN b[338]
    DIRECTION OUTPUT ;
    USE SIGNAL ;
    PORT
      LAYER M5 ;
        RECT  65.808 99.252 65.832 99.336 ;
    END
  END b[338]
  PIN b[339]
    DIRECTION OUTPUT ;
    USE SIGNAL ;
    PORT
      LAYER M5 ;
        RECT  65.904 99.252 65.928 99.336 ;
    END
  END b[339]
  PIN b[33]
    DIRECTION OUTPUT ;
    USE SIGNAL ;
    PORT
      LAYER M3 ;
        RECT  24.588 99.299 24.606 99.336 ;
    END
  END b[33]
  PIN b[340]
    DIRECTION OUTPUT ;
    USE SIGNAL ;
    PORT
      LAYER M5 ;
        RECT  66 99.252 66.024 99.336 ;
    END
  END b[340]
  PIN b[341]
    DIRECTION OUTPUT ;
    USE SIGNAL ;
    PORT
      LAYER M5 ;
        RECT  66.096 99.252 66.12 99.336 ;
    END
  END b[341]
  PIN b[342]
    DIRECTION OUTPUT ;
    USE SIGNAL ;
    PORT
      LAYER M5 ;
        RECT  66.192 99.252 66.216 99.336 ;
    END
  END b[342]
  PIN b[343]
    DIRECTION OUTPUT ;
    USE SIGNAL ;
    PORT
      LAYER M5 ;
        RECT  66.288 99.252 66.312 99.336 ;
    END
  END b[343]
  PIN b[344]
    DIRECTION OUTPUT ;
    USE SIGNAL ;
    PORT
      LAYER M5 ;
        RECT  66.384 99.252 66.408 99.336 ;
    END
  END b[344]
  PIN b[345]
    DIRECTION OUTPUT ;
    USE SIGNAL ;
    PORT
      LAYER M5 ;
        RECT  66.48 99.252 66.504 99.336 ;
    END
  END b[345]
  PIN b[346]
    DIRECTION OUTPUT ;
    USE SIGNAL ;
    PORT
      LAYER M5 ;
        RECT  66.576 99.252 66.6 99.336 ;
    END
  END b[346]
  PIN b[347]
    DIRECTION OUTPUT ;
    USE SIGNAL ;
    PORT
      LAYER M5 ;
        RECT  66.672 99.252 66.696 99.336 ;
    END
  END b[347]
  PIN b[348]
    DIRECTION OUTPUT ;
    USE SIGNAL ;
    PORT
      LAYER M5 ;
        RECT  66.768 99.252 66.792 99.336 ;
    END
  END b[348]
  PIN b[349]
    DIRECTION OUTPUT ;
    USE SIGNAL ;
    PORT
      LAYER M5 ;
        RECT  66.864 99.252 66.888 99.336 ;
    END
  END b[349]
  PIN b[34]
    DIRECTION OUTPUT ;
    USE SIGNAL ;
    PORT
      LAYER M3 ;
        RECT  24.66 99.299 24.678 99.336 ;
    END
  END b[34]
  PIN b[350]
    DIRECTION OUTPUT ;
    USE SIGNAL ;
    PORT
      LAYER M5 ;
        RECT  66.96 99.252 66.984 99.336 ;
    END
  END b[350]
  PIN b[351]
    DIRECTION OUTPUT ;
    USE SIGNAL ;
    PORT
      LAYER M5 ;
        RECT  67.056 99.252 67.08 99.336 ;
    END
  END b[351]
  PIN b[352]
    DIRECTION OUTPUT ;
    USE SIGNAL ;
    PORT
      LAYER M5 ;
        RECT  67.152 99.252 67.176 99.336 ;
    END
  END b[352]
  PIN b[353]
    DIRECTION OUTPUT ;
    USE SIGNAL ;
    PORT
      LAYER M5 ;
        RECT  67.248 99.252 67.272 99.336 ;
    END
  END b[353]
  PIN b[354]
    DIRECTION OUTPUT ;
    USE SIGNAL ;
    PORT
      LAYER M5 ;
        RECT  67.344 99.252 67.368 99.336 ;
    END
  END b[354]
  PIN b[355]
    DIRECTION OUTPUT ;
    USE SIGNAL ;
    PORT
      LAYER M5 ;
        RECT  67.44 99.252 67.464 99.336 ;
    END
  END b[355]
  PIN b[356]
    DIRECTION OUTPUT ;
    USE SIGNAL ;
    PORT
      LAYER M5 ;
        RECT  67.536 99.252 67.56 99.336 ;
    END
  END b[356]
  PIN b[357]
    DIRECTION OUTPUT ;
    USE SIGNAL ;
    PORT
      LAYER M5 ;
        RECT  67.632 99.252 67.656 99.336 ;
    END
  END b[357]
  PIN b[358]
    DIRECTION OUTPUT ;
    USE SIGNAL ;
    PORT
      LAYER M5 ;
        RECT  67.728 99.252 67.752 99.336 ;
    END
  END b[358]
  PIN b[359]
    DIRECTION OUTPUT ;
    USE SIGNAL ;
    PORT
      LAYER M5 ;
        RECT  67.824 99.252 67.848 99.336 ;
    END
  END b[359]
  PIN b[35]
    DIRECTION OUTPUT ;
    USE SIGNAL ;
    PORT
      LAYER M3 ;
        RECT  24.732 99.299 24.75 99.336 ;
    END
  END b[35]
  PIN b[360]
    DIRECTION OUTPUT ;
    USE SIGNAL ;
    PORT
      LAYER M5 ;
        RECT  67.92 99.252 67.944 99.336 ;
    END
  END b[360]
  PIN b[361]
    DIRECTION OUTPUT ;
    USE SIGNAL ;
    PORT
      LAYER M5 ;
        RECT  68.016 99.252 68.04 99.336 ;
    END
  END b[361]
  PIN b[362]
    DIRECTION OUTPUT ;
    USE SIGNAL ;
    PORT
      LAYER M5 ;
        RECT  68.112 99.252 68.136 99.336 ;
    END
  END b[362]
  PIN b[363]
    DIRECTION OUTPUT ;
    USE SIGNAL ;
    PORT
      LAYER M5 ;
        RECT  68.208 99.252 68.232 99.336 ;
    END
  END b[363]
  PIN b[364]
    DIRECTION OUTPUT ;
    USE SIGNAL ;
    PORT
      LAYER M5 ;
        RECT  68.304 99.252 68.328 99.336 ;
    END
  END b[364]
  PIN b[365]
    DIRECTION OUTPUT ;
    USE SIGNAL ;
    PORT
      LAYER M5 ;
        RECT  68.4 99.252 68.424 99.336 ;
    END
  END b[365]
  PIN b[366]
    DIRECTION OUTPUT ;
    USE SIGNAL ;
    PORT
      LAYER M5 ;
        RECT  68.496 99.252 68.52 99.336 ;
    END
  END b[366]
  PIN b[367]
    DIRECTION OUTPUT ;
    USE SIGNAL ;
    PORT
      LAYER M5 ;
        RECT  68.592 99.252 68.616 99.336 ;
    END
  END b[367]
  PIN b[368]
    DIRECTION OUTPUT ;
    USE SIGNAL ;
    PORT
      LAYER M5 ;
        RECT  68.688 99.252 68.712 99.336 ;
    END
  END b[368]
  PIN b[369]
    DIRECTION OUTPUT ;
    USE SIGNAL ;
    PORT
      LAYER M5 ;
        RECT  68.784 99.252 68.808 99.336 ;
    END
  END b[369]
  PIN b[36]
    DIRECTION OUTPUT ;
    USE SIGNAL ;
    PORT
      LAYER M3 ;
        RECT  24.804 99.299 24.822 99.336 ;
    END
  END b[36]
  PIN b[370]
    DIRECTION OUTPUT ;
    USE SIGNAL ;
    PORT
      LAYER M5 ;
        RECT  68.88 99.252 68.904 99.336 ;
    END
  END b[370]
  PIN b[371]
    DIRECTION OUTPUT ;
    USE SIGNAL ;
    PORT
      LAYER M5 ;
        RECT  68.976 99.252 69 99.336 ;
    END
  END b[371]
  PIN b[372]
    DIRECTION OUTPUT ;
    USE SIGNAL ;
    PORT
      LAYER M5 ;
        RECT  69.072 99.252 69.096 99.336 ;
    END
  END b[372]
  PIN b[373]
    DIRECTION OUTPUT ;
    USE SIGNAL ;
    PORT
      LAYER M5 ;
        RECT  69.168 99.252 69.192 99.336 ;
    END
  END b[373]
  PIN b[374]
    DIRECTION OUTPUT ;
    USE SIGNAL ;
    PORT
      LAYER M5 ;
        RECT  69.264 99.252 69.288 99.336 ;
    END
  END b[374]
  PIN b[375]
    DIRECTION OUTPUT ;
    USE SIGNAL ;
    PORT
      LAYER M5 ;
        RECT  69.36 99.252 69.384 99.336 ;
    END
  END b[375]
  PIN b[376]
    DIRECTION OUTPUT ;
    USE SIGNAL ;
    PORT
      LAYER M5 ;
        RECT  69.456 99.252 69.48 99.336 ;
    END
  END b[376]
  PIN b[377]
    DIRECTION OUTPUT ;
    USE SIGNAL ;
    PORT
      LAYER M5 ;
        RECT  69.552 99.252 69.576 99.336 ;
    END
  END b[377]
  PIN b[378]
    DIRECTION OUTPUT ;
    USE SIGNAL ;
    PORT
      LAYER M5 ;
        RECT  69.648 99.252 69.672 99.336 ;
    END
  END b[378]
  PIN b[379]
    DIRECTION OUTPUT ;
    USE SIGNAL ;
    PORT
      LAYER M5 ;
        RECT  69.744 99.252 69.768 99.336 ;
    END
  END b[379]
  PIN b[37]
    DIRECTION OUTPUT ;
    USE SIGNAL ;
    PORT
      LAYER M3 ;
        RECT  24.876 99.299 24.894 99.336 ;
    END
  END b[37]
  PIN b[380]
    DIRECTION OUTPUT ;
    USE SIGNAL ;
    PORT
      LAYER M5 ;
        RECT  69.84 99.252 69.864 99.336 ;
    END
  END b[380]
  PIN b[381]
    DIRECTION OUTPUT ;
    USE SIGNAL ;
    PORT
      LAYER M5 ;
        RECT  69.936 99.252 69.96 99.336 ;
    END
  END b[381]
  PIN b[382]
    DIRECTION OUTPUT ;
    USE SIGNAL ;
    PORT
      LAYER M5 ;
        RECT  70.032 99.252 70.056 99.336 ;
    END
  END b[382]
  PIN b[383]
    DIRECTION OUTPUT ;
    USE SIGNAL ;
    PORT
      LAYER M5 ;
        RECT  70.128 99.252 70.152 99.336 ;
    END
  END b[383]
  PIN b[384]
    DIRECTION OUTPUT ;
    USE SIGNAL ;
    PORT
      LAYER M5 ;
        RECT  73.296 99.252 73.32 99.336 ;
    END
  END b[384]
  PIN b[385]
    DIRECTION OUTPUT ;
    USE SIGNAL ;
    PORT
      LAYER M5 ;
        RECT  73.392 99.252 73.416 99.336 ;
    END
  END b[385]
  PIN b[386]
    DIRECTION OUTPUT ;
    USE SIGNAL ;
    PORT
      LAYER M5 ;
        RECT  73.488 99.252 73.512 99.336 ;
    END
  END b[386]
  PIN b[387]
    DIRECTION OUTPUT ;
    USE SIGNAL ;
    PORT
      LAYER M5 ;
        RECT  73.584 99.252 73.608 99.336 ;
    END
  END b[387]
  PIN b[388]
    DIRECTION OUTPUT ;
    USE SIGNAL ;
    PORT
      LAYER M5 ;
        RECT  73.68 99.252 73.704 99.336 ;
    END
  END b[388]
  PIN b[389]
    DIRECTION OUTPUT ;
    USE SIGNAL ;
    PORT
      LAYER M5 ;
        RECT  73.776 99.252 73.8 99.336 ;
    END
  END b[389]
  PIN b[38]
    DIRECTION OUTPUT ;
    USE SIGNAL ;
    PORT
      LAYER M3 ;
        RECT  24.948 99.299 24.966 99.336 ;
    END
  END b[38]
  PIN b[390]
    DIRECTION OUTPUT ;
    USE SIGNAL ;
    PORT
      LAYER M5 ;
        RECT  73.872 99.252 73.896 99.336 ;
    END
  END b[390]
  PIN b[391]
    DIRECTION OUTPUT ;
    USE SIGNAL ;
    PORT
      LAYER M5 ;
        RECT  73.968 99.252 73.992 99.336 ;
    END
  END b[391]
  PIN b[392]
    DIRECTION OUTPUT ;
    USE SIGNAL ;
    PORT
      LAYER M5 ;
        RECT  74.064 99.252 74.088 99.336 ;
    END
  END b[392]
  PIN b[393]
    DIRECTION OUTPUT ;
    USE SIGNAL ;
    PORT
      LAYER M5 ;
        RECT  74.16 99.252 74.184 99.336 ;
    END
  END b[393]
  PIN b[394]
    DIRECTION OUTPUT ;
    USE SIGNAL ;
    PORT
      LAYER M5 ;
        RECT  74.256 99.252 74.28 99.336 ;
    END
  END b[394]
  PIN b[395]
    DIRECTION OUTPUT ;
    USE SIGNAL ;
    PORT
      LAYER M5 ;
        RECT  74.352 99.252 74.376 99.336 ;
    END
  END b[395]
  PIN b[396]
    DIRECTION OUTPUT ;
    USE SIGNAL ;
    PORT
      LAYER M5 ;
        RECT  74.448 99.252 74.472 99.336 ;
    END
  END b[396]
  PIN b[397]
    DIRECTION OUTPUT ;
    USE SIGNAL ;
    PORT
      LAYER M5 ;
        RECT  74.544 99.252 74.568 99.336 ;
    END
  END b[397]
  PIN b[398]
    DIRECTION OUTPUT ;
    USE SIGNAL ;
    PORT
      LAYER M5 ;
        RECT  74.64 99.252 74.664 99.336 ;
    END
  END b[398]
  PIN b[399]
    DIRECTION OUTPUT ;
    USE SIGNAL ;
    PORT
      LAYER M5 ;
        RECT  74.736 99.252 74.76 99.336 ;
    END
  END b[399]
  PIN b[39]
    DIRECTION OUTPUT ;
    USE SIGNAL ;
    PORT
      LAYER M3 ;
        RECT  25.02 99.299 25.038 99.336 ;
    END
  END b[39]
  PIN b[3]
    DIRECTION OUTPUT ;
    USE SIGNAL ;
    PORT
      LAYER M5 ;
        RECT  22.896 99.252 22.92 99.336 ;
    END
  END b[3]
  PIN b[400]
    DIRECTION OUTPUT ;
    USE SIGNAL ;
    PORT
      LAYER M5 ;
        RECT  74.832 99.252 74.856 99.336 ;
    END
  END b[400]
  PIN b[401]
    DIRECTION OUTPUT ;
    USE SIGNAL ;
    PORT
      LAYER M5 ;
        RECT  74.928 99.252 74.952 99.336 ;
    END
  END b[401]
  PIN b[402]
    DIRECTION OUTPUT ;
    USE SIGNAL ;
    PORT
      LAYER M5 ;
        RECT  75.024 99.252 75.048 99.336 ;
    END
  END b[402]
  PIN b[403]
    DIRECTION OUTPUT ;
    USE SIGNAL ;
    PORT
      LAYER M5 ;
        RECT  75.12 99.252 75.144 99.336 ;
    END
  END b[403]
  PIN b[404]
    DIRECTION OUTPUT ;
    USE SIGNAL ;
    PORT
      LAYER M5 ;
        RECT  75.216 99.252 75.24 99.336 ;
    END
  END b[404]
  PIN b[405]
    DIRECTION OUTPUT ;
    USE SIGNAL ;
    PORT
      LAYER M5 ;
        RECT  75.312 99.252 75.336 99.336 ;
    END
  END b[405]
  PIN b[406]
    DIRECTION OUTPUT ;
    USE SIGNAL ;
    PORT
      LAYER M5 ;
        RECT  75.408 99.252 75.432 99.336 ;
    END
  END b[406]
  PIN b[407]
    DIRECTION OUTPUT ;
    USE SIGNAL ;
    PORT
      LAYER M5 ;
        RECT  75.504 99.252 75.528 99.336 ;
    END
  END b[407]
  PIN b[408]
    DIRECTION OUTPUT ;
    USE SIGNAL ;
    PORT
      LAYER M5 ;
        RECT  75.6 99.252 75.624 99.336 ;
    END
  END b[408]
  PIN b[409]
    DIRECTION OUTPUT ;
    USE SIGNAL ;
    PORT
      LAYER M5 ;
        RECT  75.696 99.252 75.72 99.336 ;
    END
  END b[409]
  PIN b[40]
    DIRECTION OUTPUT ;
    USE SIGNAL ;
    PORT
      LAYER M3 ;
        RECT  25.092 99.299 25.11 99.336 ;
    END
  END b[40]
  PIN b[410]
    DIRECTION OUTPUT ;
    USE SIGNAL ;
    PORT
      LAYER M5 ;
        RECT  75.792 99.252 75.816 99.336 ;
    END
  END b[410]
  PIN b[411]
    DIRECTION OUTPUT ;
    USE SIGNAL ;
    PORT
      LAYER M5 ;
        RECT  75.888 99.252 75.912 99.336 ;
    END
  END b[411]
  PIN b[412]
    DIRECTION OUTPUT ;
    USE SIGNAL ;
    PORT
      LAYER M5 ;
        RECT  75.984 99.252 76.008 99.336 ;
    END
  END b[412]
  PIN b[413]
    DIRECTION OUTPUT ;
    USE SIGNAL ;
    PORT
      LAYER M5 ;
        RECT  76.08 99.252 76.104 99.336 ;
    END
  END b[413]
  PIN b[414]
    DIRECTION OUTPUT ;
    USE SIGNAL ;
    PORT
      LAYER M5 ;
        RECT  76.176 99.252 76.2 99.336 ;
    END
  END b[414]
  PIN b[415]
    DIRECTION OUTPUT ;
    USE SIGNAL ;
    PORT
      LAYER M5 ;
        RECT  76.272 99.252 76.296 99.336 ;
    END
  END b[415]
  PIN b[416]
    DIRECTION OUTPUT ;
    USE SIGNAL ;
    PORT
      LAYER M5 ;
        RECT  54.096 99.252 54.12 99.336 ;
    END
  END b[416]
  PIN b[417]
    DIRECTION OUTPUT ;
    USE SIGNAL ;
    PORT
      LAYER M5 ;
        RECT  54.192 99.252 54.216 99.336 ;
    END
  END b[417]
  PIN b[418]
    DIRECTION OUTPUT ;
    USE SIGNAL ;
    PORT
      LAYER M5 ;
        RECT  54.288 99.252 54.312 99.336 ;
    END
  END b[418]
  PIN b[419]
    DIRECTION OUTPUT ;
    USE SIGNAL ;
    PORT
      LAYER M5 ;
        RECT  54.384 99.252 54.408 99.336 ;
    END
  END b[419]
  PIN b[41]
    DIRECTION OUTPUT ;
    USE SIGNAL ;
    PORT
      LAYER M3 ;
        RECT  25.164 99.299 25.182 99.336 ;
    END
  END b[41]
  PIN b[420]
    DIRECTION OUTPUT ;
    USE SIGNAL ;
    PORT
      LAYER M5 ;
        RECT  54.48 99.252 54.504 99.336 ;
    END
  END b[420]
  PIN b[421]
    DIRECTION OUTPUT ;
    USE SIGNAL ;
    PORT
      LAYER M5 ;
        RECT  54.576 99.252 54.6 99.336 ;
    END
  END b[421]
  PIN b[422]
    DIRECTION OUTPUT ;
    USE SIGNAL ;
    PORT
      LAYER M5 ;
        RECT  54.672 99.252 54.696 99.336 ;
    END
  END b[422]
  PIN b[423]
    DIRECTION OUTPUT ;
    USE SIGNAL ;
    PORT
      LAYER M5 ;
        RECT  54.768 99.252 54.792 99.336 ;
    END
  END b[423]
  PIN b[424]
    DIRECTION OUTPUT ;
    USE SIGNAL ;
    PORT
      LAYER M5 ;
        RECT  54.864 99.252 54.888 99.336 ;
    END
  END b[424]
  PIN b[425]
    DIRECTION OUTPUT ;
    USE SIGNAL ;
    PORT
      LAYER M5 ;
        RECT  54.96 99.252 54.984 99.336 ;
    END
  END b[425]
  PIN b[426]
    DIRECTION OUTPUT ;
    USE SIGNAL ;
    PORT
      LAYER M5 ;
        RECT  55.056 99.252 55.08 99.336 ;
    END
  END b[426]
  PIN b[427]
    DIRECTION OUTPUT ;
    USE SIGNAL ;
    PORT
      LAYER M5 ;
        RECT  55.152 99.252 55.176 99.336 ;
    END
  END b[427]
  PIN b[428]
    DIRECTION OUTPUT ;
    USE SIGNAL ;
    PORT
      LAYER M5 ;
        RECT  55.248 99.252 55.272 99.336 ;
    END
  END b[428]
  PIN b[429]
    DIRECTION OUTPUT ;
    USE SIGNAL ;
    PORT
      LAYER M5 ;
        RECT  55.344 99.252 55.368 99.336 ;
    END
  END b[429]
  PIN b[42]
    DIRECTION OUTPUT ;
    USE SIGNAL ;
    PORT
      LAYER M3 ;
        RECT  25.236 99.299 25.254 99.336 ;
    END
  END b[42]
  PIN b[430]
    DIRECTION OUTPUT ;
    USE SIGNAL ;
    PORT
      LAYER M5 ;
        RECT  55.44 99.252 55.464 99.336 ;
    END
  END b[430]
  PIN b[431]
    DIRECTION OUTPUT ;
    USE SIGNAL ;
    PORT
      LAYER M5 ;
        RECT  55.536 99.252 55.56 99.336 ;
    END
  END b[431]
  PIN b[432]
    DIRECTION OUTPUT ;
    USE SIGNAL ;
    PORT
      LAYER M5 ;
        RECT  55.632 99.252 55.656 99.336 ;
    END
  END b[432]
  PIN b[433]
    DIRECTION OUTPUT ;
    USE SIGNAL ;
    PORT
      LAYER M5 ;
        RECT  55.728 99.252 55.752 99.336 ;
    END
  END b[433]
  PIN b[434]
    DIRECTION OUTPUT ;
    USE SIGNAL ;
    PORT
      LAYER M5 ;
        RECT  55.824 99.252 55.848 99.336 ;
    END
  END b[434]
  PIN b[435]
    DIRECTION OUTPUT ;
    USE SIGNAL ;
    PORT
      LAYER M5 ;
        RECT  55.92 99.252 55.944 99.336 ;
    END
  END b[435]
  PIN b[436]
    DIRECTION OUTPUT ;
    USE SIGNAL ;
    PORT
      LAYER M5 ;
        RECT  56.016 99.252 56.04 99.336 ;
    END
  END b[436]
  PIN b[437]
    DIRECTION OUTPUT ;
    USE SIGNAL ;
    PORT
      LAYER M5 ;
        RECT  56.112 99.252 56.136 99.336 ;
    END
  END b[437]
  PIN b[438]
    DIRECTION OUTPUT ;
    USE SIGNAL ;
    PORT
      LAYER M5 ;
        RECT  56.208 99.252 56.232 99.336 ;
    END
  END b[438]
  PIN b[439]
    DIRECTION OUTPUT ;
    USE SIGNAL ;
    PORT
      LAYER M5 ;
        RECT  56.304 99.252 56.328 99.336 ;
    END
  END b[439]
  PIN b[43]
    DIRECTION OUTPUT ;
    USE SIGNAL ;
    PORT
      LAYER M3 ;
        RECT  25.308 99.299 25.326 99.336 ;
    END
  END b[43]
  PIN b[440]
    DIRECTION OUTPUT ;
    USE SIGNAL ;
    PORT
      LAYER M5 ;
        RECT  56.4 99.252 56.424 99.336 ;
    END
  END b[440]
  PIN b[441]
    DIRECTION OUTPUT ;
    USE SIGNAL ;
    PORT
      LAYER M5 ;
        RECT  56.496 99.252 56.52 99.336 ;
    END
  END b[441]
  PIN b[442]
    DIRECTION OUTPUT ;
    USE SIGNAL ;
    PORT
      LAYER M5 ;
        RECT  56.592 99.252 56.616 99.336 ;
    END
  END b[442]
  PIN b[443]
    DIRECTION OUTPUT ;
    USE SIGNAL ;
    PORT
      LAYER M5 ;
        RECT  56.688 99.252 56.712 99.336 ;
    END
  END b[443]
  PIN b[444]
    DIRECTION OUTPUT ;
    USE SIGNAL ;
    PORT
      LAYER M5 ;
        RECT  56.784 99.252 56.808 99.336 ;
    END
  END b[444]
  PIN b[445]
    DIRECTION OUTPUT ;
    USE SIGNAL ;
    PORT
      LAYER M5 ;
        RECT  56.88 99.252 56.904 99.336 ;
    END
  END b[445]
  PIN b[446]
    DIRECTION OUTPUT ;
    USE SIGNAL ;
    PORT
      LAYER M5 ;
        RECT  56.976 99.252 57 99.336 ;
    END
  END b[446]
  PIN b[447]
    DIRECTION OUTPUT ;
    USE SIGNAL ;
    PORT
      LAYER M5 ;
        RECT  57.072 99.252 57.096 99.336 ;
    END
  END b[447]
  PIN b[448]
    DIRECTION OUTPUT ;
    USE SIGNAL ;
    PORT
      LAYER M5 ;
        RECT  51.024 99.252 51.048 99.336 ;
    END
  END b[448]
  PIN b[449]
    DIRECTION OUTPUT ;
    USE SIGNAL ;
    PORT
      LAYER M5 ;
        RECT  51.12 99.252 51.144 99.336 ;
    END
  END b[449]
  PIN b[44]
    DIRECTION OUTPUT ;
    USE SIGNAL ;
    PORT
      LAYER M3 ;
        RECT  25.38 99.299 25.398 99.336 ;
    END
  END b[44]
  PIN b[450]
    DIRECTION OUTPUT ;
    USE SIGNAL ;
    PORT
      LAYER M5 ;
        RECT  51.216 99.252 51.24 99.336 ;
    END
  END b[450]
  PIN b[451]
    DIRECTION OUTPUT ;
    USE SIGNAL ;
    PORT
      LAYER M5 ;
        RECT  51.312 99.252 51.336 99.336 ;
    END
  END b[451]
  PIN b[452]
    DIRECTION OUTPUT ;
    USE SIGNAL ;
    PORT
      LAYER M5 ;
        RECT  51.408 99.252 51.432 99.336 ;
    END
  END b[452]
  PIN b[453]
    DIRECTION OUTPUT ;
    USE SIGNAL ;
    PORT
      LAYER M5 ;
        RECT  51.504 99.252 51.528 99.336 ;
    END
  END b[453]
  PIN b[454]
    DIRECTION OUTPUT ;
    USE SIGNAL ;
    PORT
      LAYER M5 ;
        RECT  51.6 99.252 51.624 99.336 ;
    END
  END b[454]
  PIN b[455]
    DIRECTION OUTPUT ;
    USE SIGNAL ;
    PORT
      LAYER M5 ;
        RECT  51.696 99.252 51.72 99.336 ;
    END
  END b[455]
  PIN b[456]
    DIRECTION OUTPUT ;
    USE SIGNAL ;
    PORT
      LAYER M5 ;
        RECT  51.792 99.252 51.816 99.336 ;
    END
  END b[456]
  PIN b[457]
    DIRECTION OUTPUT ;
    USE SIGNAL ;
    PORT
      LAYER M5 ;
        RECT  51.888 99.252 51.912 99.336 ;
    END
  END b[457]
  PIN b[458]
    DIRECTION OUTPUT ;
    USE SIGNAL ;
    PORT
      LAYER M5 ;
        RECT  51.984 99.252 52.008 99.336 ;
    END
  END b[458]
  PIN b[459]
    DIRECTION OUTPUT ;
    USE SIGNAL ;
    PORT
      LAYER M5 ;
        RECT  52.08 99.252 52.104 99.336 ;
    END
  END b[459]
  PIN b[45]
    DIRECTION OUTPUT ;
    USE SIGNAL ;
    PORT
      LAYER M3 ;
        RECT  25.452 99.299 25.47 99.336 ;
    END
  END b[45]
  PIN b[460]
    DIRECTION OUTPUT ;
    USE SIGNAL ;
    PORT
      LAYER M5 ;
        RECT  52.176 99.252 52.2 99.336 ;
    END
  END b[460]
  PIN b[461]
    DIRECTION OUTPUT ;
    USE SIGNAL ;
    PORT
      LAYER M5 ;
        RECT  52.272 99.252 52.296 99.336 ;
    END
  END b[461]
  PIN b[462]
    DIRECTION OUTPUT ;
    USE SIGNAL ;
    PORT
      LAYER M5 ;
        RECT  52.368 99.252 52.392 99.336 ;
    END
  END b[462]
  PIN b[463]
    DIRECTION OUTPUT ;
    USE SIGNAL ;
    PORT
      LAYER M5 ;
        RECT  52.464 99.252 52.488 99.336 ;
    END
  END b[463]
  PIN b[464]
    DIRECTION OUTPUT ;
    USE SIGNAL ;
    PORT
      LAYER M5 ;
        RECT  52.56 99.252 52.584 99.336 ;
    END
  END b[464]
  PIN b[465]
    DIRECTION OUTPUT ;
    USE SIGNAL ;
    PORT
      LAYER M5 ;
        RECT  52.656 99.252 52.68 99.336 ;
    END
  END b[465]
  PIN b[466]
    DIRECTION OUTPUT ;
    USE SIGNAL ;
    PORT
      LAYER M5 ;
        RECT  52.752 99.252 52.776 99.336 ;
    END
  END b[466]
  PIN b[467]
    DIRECTION OUTPUT ;
    USE SIGNAL ;
    PORT
      LAYER M5 ;
        RECT  52.848 99.252 52.872 99.336 ;
    END
  END b[467]
  PIN b[468]
    DIRECTION OUTPUT ;
    USE SIGNAL ;
    PORT
      LAYER M5 ;
        RECT  52.944 99.252 52.968 99.336 ;
    END
  END b[468]
  PIN b[469]
    DIRECTION OUTPUT ;
    USE SIGNAL ;
    PORT
      LAYER M5 ;
        RECT  53.04 99.252 53.064 99.336 ;
    END
  END b[469]
  PIN b[46]
    DIRECTION OUTPUT ;
    USE SIGNAL ;
    PORT
      LAYER M3 ;
        RECT  25.524 99.299 25.542 99.336 ;
    END
  END b[46]
  PIN b[470]
    DIRECTION OUTPUT ;
    USE SIGNAL ;
    PORT
      LAYER M5 ;
        RECT  53.136 99.252 53.16 99.336 ;
    END
  END b[470]
  PIN b[471]
    DIRECTION OUTPUT ;
    USE SIGNAL ;
    PORT
      LAYER M5 ;
        RECT  53.232 99.252 53.256 99.336 ;
    END
  END b[471]
  PIN b[472]
    DIRECTION OUTPUT ;
    USE SIGNAL ;
    PORT
      LAYER M5 ;
        RECT  53.328 99.252 53.352 99.336 ;
    END
  END b[472]
  PIN b[473]
    DIRECTION OUTPUT ;
    USE SIGNAL ;
    PORT
      LAYER M5 ;
        RECT  53.424 99.252 53.448 99.336 ;
    END
  END b[473]
  PIN b[474]
    DIRECTION OUTPUT ;
    USE SIGNAL ;
    PORT
      LAYER M5 ;
        RECT  53.52 99.252 53.544 99.336 ;
    END
  END b[474]
  PIN b[475]
    DIRECTION OUTPUT ;
    USE SIGNAL ;
    PORT
      LAYER M5 ;
        RECT  53.616 99.252 53.64 99.336 ;
    END
  END b[475]
  PIN b[476]
    DIRECTION OUTPUT ;
    USE SIGNAL ;
    PORT
      LAYER M5 ;
        RECT  53.712 99.252 53.736 99.336 ;
    END
  END b[476]
  PIN b[477]
    DIRECTION OUTPUT ;
    USE SIGNAL ;
    PORT
      LAYER M5 ;
        RECT  53.808 99.252 53.832 99.336 ;
    END
  END b[477]
  PIN b[478]
    DIRECTION OUTPUT ;
    USE SIGNAL ;
    PORT
      LAYER M5 ;
        RECT  53.904 99.252 53.928 99.336 ;
    END
  END b[478]
  PIN b[479]
    DIRECTION OUTPUT ;
    USE SIGNAL ;
    PORT
      LAYER M5 ;
        RECT  54 99.252 54.024 99.336 ;
    END
  END b[479]
  PIN b[47]
    DIRECTION OUTPUT ;
    USE SIGNAL ;
    PORT
      LAYER M3 ;
        RECT  25.596 99.299 25.614 99.336 ;
    END
  END b[47]
  PIN b[480]
    DIRECTION OUTPUT ;
    USE SIGNAL ;
    PORT
      LAYER M3 ;
        RECT  44.1 99.299 44.118 99.336 ;
    END
  END b[480]
  PIN b[481]
    DIRECTION OUTPUT ;
    USE SIGNAL ;
    PORT
      LAYER M3 ;
        RECT  44.172 99.299 44.19 99.336 ;
    END
  END b[481]
  PIN b[482]
    DIRECTION OUTPUT ;
    USE SIGNAL ;
    PORT
      LAYER M3 ;
        RECT  44.244 99.299 44.262 99.336 ;
    END
  END b[482]
  PIN b[483]
    DIRECTION OUTPUT ;
    USE SIGNAL ;
    PORT
      LAYER M3 ;
        RECT  44.316 99.299 44.334 99.336 ;
    END
  END b[483]
  PIN b[484]
    DIRECTION OUTPUT ;
    USE SIGNAL ;
    PORT
      LAYER M3 ;
        RECT  44.388 99.299 44.406 99.336 ;
    END
  END b[484]
  PIN b[485]
    DIRECTION OUTPUT ;
    USE SIGNAL ;
    PORT
      LAYER M3 ;
        RECT  44.46 99.299 44.478 99.336 ;
    END
  END b[485]
  PIN b[486]
    DIRECTION OUTPUT ;
    USE SIGNAL ;
    PORT
      LAYER M3 ;
        RECT  44.532 99.299 44.55 99.336 ;
    END
  END b[486]
  PIN b[487]
    DIRECTION OUTPUT ;
    USE SIGNAL ;
    PORT
      LAYER M3 ;
        RECT  44.604 99.299 44.622 99.336 ;
    END
  END b[487]
  PIN b[488]
    DIRECTION OUTPUT ;
    USE SIGNAL ;
    PORT
      LAYER M3 ;
        RECT  44.676 99.299 44.694 99.336 ;
    END
  END b[488]
  PIN b[489]
    DIRECTION OUTPUT ;
    USE SIGNAL ;
    PORT
      LAYER M3 ;
        RECT  44.748 99.299 44.766 99.336 ;
    END
  END b[489]
  PIN b[48]
    DIRECTION OUTPUT ;
    USE SIGNAL ;
    PORT
      LAYER M3 ;
        RECT  25.668 99.299 25.686 99.336 ;
    END
  END b[48]
  PIN b[490]
    DIRECTION OUTPUT ;
    USE SIGNAL ;
    PORT
      LAYER M3 ;
        RECT  44.82 99.299 44.838 99.336 ;
    END
  END b[490]
  PIN b[491]
    DIRECTION OUTPUT ;
    USE SIGNAL ;
    PORT
      LAYER M3 ;
        RECT  44.892 99.299 44.91 99.336 ;
    END
  END b[491]
  PIN b[492]
    DIRECTION OUTPUT ;
    USE SIGNAL ;
    PORT
      LAYER M3 ;
        RECT  44.964 99.299 44.982 99.336 ;
    END
  END b[492]
  PIN b[493]
    DIRECTION OUTPUT ;
    USE SIGNAL ;
    PORT
      LAYER M3 ;
        RECT  45.036 99.299 45.054 99.336 ;
    END
  END b[493]
  PIN b[494]
    DIRECTION OUTPUT ;
    USE SIGNAL ;
    PORT
      LAYER M3 ;
        RECT  45.108 99.299 45.126 99.336 ;
    END
  END b[494]
  PIN b[495]
    DIRECTION OUTPUT ;
    USE SIGNAL ;
    PORT
      LAYER M3 ;
        RECT  45.18 99.299 45.198 99.336 ;
    END
  END b[495]
  PIN b[496]
    DIRECTION OUTPUT ;
    USE SIGNAL ;
    PORT
      LAYER M3 ;
        RECT  45.252 99.299 45.27 99.336 ;
    END
  END b[496]
  PIN b[497]
    DIRECTION OUTPUT ;
    USE SIGNAL ;
    PORT
      LAYER M3 ;
        RECT  45.324 99.299 45.342 99.336 ;
    END
  END b[497]
  PIN b[498]
    DIRECTION OUTPUT ;
    USE SIGNAL ;
    PORT
      LAYER M3 ;
        RECT  45.396 99.299 45.414 99.336 ;
    END
  END b[498]
  PIN b[499]
    DIRECTION OUTPUT ;
    USE SIGNAL ;
    PORT
      LAYER M3 ;
        RECT  45.468 99.299 45.486 99.336 ;
    END
  END b[499]
  PIN b[49]
    DIRECTION OUTPUT ;
    USE SIGNAL ;
    PORT
      LAYER M3 ;
        RECT  25.74 99.299 25.758 99.336 ;
    END
  END b[49]
  PIN b[4]
    DIRECTION OUTPUT ;
    USE SIGNAL ;
    PORT
      LAYER M5 ;
        RECT  22.992 99.252 23.016 99.336 ;
    END
  END b[4]
  PIN b[500]
    DIRECTION OUTPUT ;
    USE SIGNAL ;
    PORT
      LAYER M3 ;
        RECT  45.54 99.299 45.558 99.336 ;
    END
  END b[500]
  PIN b[501]
    DIRECTION OUTPUT ;
    USE SIGNAL ;
    PORT
      LAYER M3 ;
        RECT  45.612 99.299 45.63 99.336 ;
    END
  END b[501]
  PIN b[502]
    DIRECTION OUTPUT ;
    USE SIGNAL ;
    PORT
      LAYER M3 ;
        RECT  45.684 99.299 45.702 99.336 ;
    END
  END b[502]
  PIN b[503]
    DIRECTION OUTPUT ;
    USE SIGNAL ;
    PORT
      LAYER M3 ;
        RECT  45.756 99.299 45.774 99.336 ;
    END
  END b[503]
  PIN b[504]
    DIRECTION OUTPUT ;
    USE SIGNAL ;
    PORT
      LAYER M3 ;
        RECT  45.828 99.299 45.846 99.336 ;
    END
  END b[504]
  PIN b[505]
    DIRECTION OUTPUT ;
    USE SIGNAL ;
    PORT
      LAYER M3 ;
        RECT  45.9 99.299 45.918 99.336 ;
    END
  END b[505]
  PIN b[506]
    DIRECTION OUTPUT ;
    USE SIGNAL ;
    PORT
      LAYER M3 ;
        RECT  45.972 99.299 45.99 99.336 ;
    END
  END b[506]
  PIN b[507]
    DIRECTION OUTPUT ;
    USE SIGNAL ;
    PORT
      LAYER M3 ;
        RECT  46.044 99.299 46.062 99.336 ;
    END
  END b[507]
  PIN b[508]
    DIRECTION OUTPUT ;
    USE SIGNAL ;
    PORT
      LAYER M3 ;
        RECT  46.116 99.299 46.134 99.336 ;
    END
  END b[508]
  PIN b[509]
    DIRECTION OUTPUT ;
    USE SIGNAL ;
    PORT
      LAYER M3 ;
        RECT  46.188 99.299 46.206 99.336 ;
    END
  END b[509]
  PIN b[50]
    DIRECTION OUTPUT ;
    USE SIGNAL ;
    PORT
      LAYER M3 ;
        RECT  25.812 99.299 25.83 99.336 ;
    END
  END b[50]
  PIN b[510]
    DIRECTION OUTPUT ;
    USE SIGNAL ;
    PORT
      LAYER M3 ;
        RECT  46.26 99.299 46.278 99.336 ;
    END
  END b[510]
  PIN b[511]
    DIRECTION OUTPUT ;
    USE SIGNAL ;
    PORT
      LAYER M3 ;
        RECT  46.332 99.299 46.35 99.336 ;
    END
  END b[511]
  PIN b[512]
    DIRECTION OUTPUT ;
    USE SIGNAL ;
    PORT
      LAYER M3 ;
        RECT  38.916 99.299 38.934 99.336 ;
    END
  END b[512]
  PIN b[513]
    DIRECTION OUTPUT ;
    USE SIGNAL ;
    PORT
      LAYER M3 ;
        RECT  38.988 99.299 39.006 99.336 ;
    END
  END b[513]
  PIN b[514]
    DIRECTION OUTPUT ;
    USE SIGNAL ;
    PORT
      LAYER M3 ;
        RECT  39.06 99.299 39.078 99.336 ;
    END
  END b[514]
  PIN b[515]
    DIRECTION OUTPUT ;
    USE SIGNAL ;
    PORT
      LAYER M3 ;
        RECT  39.132 99.299 39.15 99.336 ;
    END
  END b[515]
  PIN b[516]
    DIRECTION OUTPUT ;
    USE SIGNAL ;
    PORT
      LAYER M3 ;
        RECT  39.204 99.299 39.222 99.336 ;
    END
  END b[516]
  PIN b[517]
    DIRECTION OUTPUT ;
    USE SIGNAL ;
    PORT
      LAYER M3 ;
        RECT  39.276 99.299 39.294 99.336 ;
    END
  END b[517]
  PIN b[518]
    DIRECTION OUTPUT ;
    USE SIGNAL ;
    PORT
      LAYER M3 ;
        RECT  39.348 99.299 39.366 99.336 ;
    END
  END b[518]
  PIN b[519]
    DIRECTION OUTPUT ;
    USE SIGNAL ;
    PORT
      LAYER M3 ;
        RECT  39.42 99.299 39.438 99.336 ;
    END
  END b[519]
  PIN b[51]
    DIRECTION OUTPUT ;
    USE SIGNAL ;
    PORT
      LAYER M3 ;
        RECT  25.884 99.299 25.902 99.336 ;
    END
  END b[51]
  PIN b[520]
    DIRECTION OUTPUT ;
    USE SIGNAL ;
    PORT
      LAYER M3 ;
        RECT  39.492 99.299 39.51 99.336 ;
    END
  END b[520]
  PIN b[521]
    DIRECTION OUTPUT ;
    USE SIGNAL ;
    PORT
      LAYER M3 ;
        RECT  39.564 99.299 39.582 99.336 ;
    END
  END b[521]
  PIN b[522]
    DIRECTION OUTPUT ;
    USE SIGNAL ;
    PORT
      LAYER M3 ;
        RECT  39.636 99.299 39.654 99.336 ;
    END
  END b[522]
  PIN b[523]
    DIRECTION OUTPUT ;
    USE SIGNAL ;
    PORT
      LAYER M3 ;
        RECT  39.708 99.299 39.726 99.336 ;
    END
  END b[523]
  PIN b[524]
    DIRECTION OUTPUT ;
    USE SIGNAL ;
    PORT
      LAYER M3 ;
        RECT  39.78 99.299 39.798 99.336 ;
    END
  END b[524]
  PIN b[525]
    DIRECTION OUTPUT ;
    USE SIGNAL ;
    PORT
      LAYER M3 ;
        RECT  39.852 99.299 39.87 99.336 ;
    END
  END b[525]
  PIN b[526]
    DIRECTION OUTPUT ;
    USE SIGNAL ;
    PORT
      LAYER M3 ;
        RECT  39.924 99.299 39.942 99.336 ;
    END
  END b[526]
  PIN b[527]
    DIRECTION OUTPUT ;
    USE SIGNAL ;
    PORT
      LAYER M3 ;
        RECT  39.996 99.299 40.014 99.336 ;
    END
  END b[527]
  PIN b[528]
    DIRECTION OUTPUT ;
    USE SIGNAL ;
    PORT
      LAYER M3 ;
        RECT  40.068 99.299 40.086 99.336 ;
    END
  END b[528]
  PIN b[529]
    DIRECTION OUTPUT ;
    USE SIGNAL ;
    PORT
      LAYER M3 ;
        RECT  40.14 99.299 40.158 99.336 ;
    END
  END b[529]
  PIN b[52]
    DIRECTION OUTPUT ;
    USE SIGNAL ;
    PORT
      LAYER M3 ;
        RECT  25.956 99.299 25.974 99.336 ;
    END
  END b[52]
  PIN b[530]
    DIRECTION OUTPUT ;
    USE SIGNAL ;
    PORT
      LAYER M3 ;
        RECT  40.212 99.299 40.23 99.336 ;
    END
  END b[530]
  PIN b[531]
    DIRECTION OUTPUT ;
    USE SIGNAL ;
    PORT
      LAYER M3 ;
        RECT  40.284 99.299 40.302 99.336 ;
    END
  END b[531]
  PIN b[532]
    DIRECTION OUTPUT ;
    USE SIGNAL ;
    PORT
      LAYER M3 ;
        RECT  40.356 99.299 40.374 99.336 ;
    END
  END b[532]
  PIN b[533]
    DIRECTION OUTPUT ;
    USE SIGNAL ;
    PORT
      LAYER M3 ;
        RECT  40.428 99.299 40.446 99.336 ;
    END
  END b[533]
  PIN b[534]
    DIRECTION OUTPUT ;
    USE SIGNAL ;
    PORT
      LAYER M3 ;
        RECT  40.5 99.299 40.518 99.336 ;
    END
  END b[534]
  PIN b[535]
    DIRECTION OUTPUT ;
    USE SIGNAL ;
    PORT
      LAYER M3 ;
        RECT  40.572 99.299 40.59 99.336 ;
    END
  END b[535]
  PIN b[536]
    DIRECTION OUTPUT ;
    USE SIGNAL ;
    PORT
      LAYER M3 ;
        RECT  40.644 99.299 40.662 99.336 ;
    END
  END b[536]
  PIN b[537]
    DIRECTION OUTPUT ;
    USE SIGNAL ;
    PORT
      LAYER M3 ;
        RECT  40.716 99.299 40.734 99.336 ;
    END
  END b[537]
  PIN b[538]
    DIRECTION OUTPUT ;
    USE SIGNAL ;
    PORT
      LAYER M3 ;
        RECT  40.788 99.299 40.806 99.336 ;
    END
  END b[538]
  PIN b[539]
    DIRECTION OUTPUT ;
    USE SIGNAL ;
    PORT
      LAYER M3 ;
        RECT  40.86 99.299 40.878 99.336 ;
    END
  END b[539]
  PIN b[53]
    DIRECTION OUTPUT ;
    USE SIGNAL ;
    PORT
      LAYER M3 ;
        RECT  26.028 99.299 26.046 99.336 ;
    END
  END b[53]
  PIN b[540]
    DIRECTION OUTPUT ;
    USE SIGNAL ;
    PORT
      LAYER M3 ;
        RECT  40.932 99.299 40.95 99.336 ;
    END
  END b[540]
  PIN b[541]
    DIRECTION OUTPUT ;
    USE SIGNAL ;
    PORT
      LAYER M3 ;
        RECT  41.004 99.299 41.022 99.336 ;
    END
  END b[541]
  PIN b[542]
    DIRECTION OUTPUT ;
    USE SIGNAL ;
    PORT
      LAYER M3 ;
        RECT  41.076 99.299 41.094 99.336 ;
    END
  END b[542]
  PIN b[543]
    DIRECTION OUTPUT ;
    USE SIGNAL ;
    PORT
      LAYER M3 ;
        RECT  41.148 99.299 41.166 99.336 ;
    END
  END b[543]
  PIN b[544]
    DIRECTION OUTPUT ;
    USE SIGNAL ;
    PORT
      LAYER M3 ;
        RECT  31.716 99.299 31.734 99.336 ;
    END
  END b[544]
  PIN b[545]
    DIRECTION OUTPUT ;
    USE SIGNAL ;
    PORT
      LAYER M3 ;
        RECT  31.788 99.299 31.806 99.336 ;
    END
  END b[545]
  PIN b[546]
    DIRECTION OUTPUT ;
    USE SIGNAL ;
    PORT
      LAYER M3 ;
        RECT  31.86 99.299 31.878 99.336 ;
    END
  END b[546]
  PIN b[547]
    DIRECTION OUTPUT ;
    USE SIGNAL ;
    PORT
      LAYER M3 ;
        RECT  31.932 99.299 31.95 99.336 ;
    END
  END b[547]
  PIN b[54]
    DIRECTION OUTPUT ;
    USE SIGNAL ;
    PORT
      LAYER M3 ;
        RECT  26.1 99.299 26.118 99.336 ;
    END
  END b[54]
  PIN b[55]
    DIRECTION OUTPUT ;
    USE SIGNAL ;
    PORT
      LAYER M3 ;
        RECT  26.172 99.299 26.19 99.336 ;
    END
  END b[55]
  PIN b[56]
    DIRECTION OUTPUT ;
    USE SIGNAL ;
    PORT
      LAYER M3 ;
        RECT  26.244 99.299 26.262 99.336 ;
    END
  END b[56]
  PIN b[57]
    DIRECTION OUTPUT ;
    USE SIGNAL ;
    PORT
      LAYER M3 ;
        RECT  26.316 99.299 26.334 99.336 ;
    END
  END b[57]
  PIN b[58]
    DIRECTION OUTPUT ;
    USE SIGNAL ;
    PORT
      LAYER M3 ;
        RECT  26.388 99.299 26.406 99.336 ;
    END
  END b[58]
  PIN b[59]
    DIRECTION OUTPUT ;
    USE SIGNAL ;
    PORT
      LAYER M3 ;
        RECT  26.46 99.299 26.478 99.336 ;
    END
  END b[59]
  PIN b[5]
    DIRECTION OUTPUT ;
    USE SIGNAL ;
    PORT
      LAYER M5 ;
        RECT  23.088 99.252 23.112 99.336 ;
    END
  END b[5]
  PIN b[60]
    DIRECTION OUTPUT ;
    USE SIGNAL ;
    PORT
      LAYER M3 ;
        RECT  26.532 99.299 26.55 99.336 ;
    END
  END b[60]
  PIN b[61]
    DIRECTION OUTPUT ;
    USE SIGNAL ;
    PORT
      LAYER M3 ;
        RECT  26.604 99.299 26.622 99.336 ;
    END
  END b[61]
  PIN b[62]
    DIRECTION OUTPUT ;
    USE SIGNAL ;
    PORT
      LAYER M3 ;
        RECT  26.676 99.299 26.694 99.336 ;
    END
  END b[62]
  PIN b[63]
    DIRECTION OUTPUT ;
    USE SIGNAL ;
    PORT
      LAYER M3 ;
        RECT  26.748 99.299 26.766 99.336 ;
    END
  END b[63]
  PIN b[64]
    DIRECTION OUTPUT ;
    USE SIGNAL ;
    PORT
      LAYER M5 ;
        RECT  28.752 99.252 28.776 99.336 ;
    END
  END b[64]
  PIN b[65]
    DIRECTION OUTPUT ;
    USE SIGNAL ;
    PORT
      LAYER M5 ;
        RECT  28.848 99.252 28.872 99.336 ;
    END
  END b[65]
  PIN b[66]
    DIRECTION OUTPUT ;
    USE SIGNAL ;
    PORT
      LAYER M5 ;
        RECT  28.944 99.252 28.968 99.336 ;
    END
  END b[66]
  PIN b[67]
    DIRECTION OUTPUT ;
    USE SIGNAL ;
    PORT
      LAYER M5 ;
        RECT  29.04 99.252 29.064 99.336 ;
    END
  END b[67]
  PIN b[68]
    DIRECTION OUTPUT ;
    USE SIGNAL ;
    PORT
      LAYER M5 ;
        RECT  29.136 99.252 29.16 99.336 ;
    END
  END b[68]
  PIN b[69]
    DIRECTION OUTPUT ;
    USE SIGNAL ;
    PORT
      LAYER M5 ;
        RECT  29.232 99.252 29.256 99.336 ;
    END
  END b[69]
  PIN b[6]
    DIRECTION OUTPUT ;
    USE SIGNAL ;
    PORT
      LAYER M5 ;
        RECT  23.184 99.252 23.208 99.336 ;
    END
  END b[6]
  PIN b[70]
    DIRECTION OUTPUT ;
    USE SIGNAL ;
    PORT
      LAYER M5 ;
        RECT  29.328 99.252 29.352 99.336 ;
    END
  END b[70]
  PIN b[71]
    DIRECTION OUTPUT ;
    USE SIGNAL ;
    PORT
      LAYER M5 ;
        RECT  29.424 99.252 29.448 99.336 ;
    END
  END b[71]
  PIN b[72]
    DIRECTION OUTPUT ;
    USE SIGNAL ;
    PORT
      LAYER M5 ;
        RECT  29.52 99.252 29.544 99.336 ;
    END
  END b[72]
  PIN b[73]
    DIRECTION OUTPUT ;
    USE SIGNAL ;
    PORT
      LAYER M5 ;
        RECT  29.616 99.252 29.64 99.336 ;
    END
  END b[73]
  PIN b[74]
    DIRECTION OUTPUT ;
    USE SIGNAL ;
    PORT
      LAYER M5 ;
        RECT  29.712 99.252 29.736 99.336 ;
    END
  END b[74]
  PIN b[75]
    DIRECTION OUTPUT ;
    USE SIGNAL ;
    PORT
      LAYER M5 ;
        RECT  29.808 99.252 29.832 99.336 ;
    END
  END b[75]
  PIN b[76]
    DIRECTION OUTPUT ;
    USE SIGNAL ;
    PORT
      LAYER M5 ;
        RECT  29.904 99.252 29.928 99.336 ;
    END
  END b[76]
  PIN b[77]
    DIRECTION OUTPUT ;
    USE SIGNAL ;
    PORT
      LAYER M5 ;
        RECT  30 99.252 30.024 99.336 ;
    END
  END b[77]
  PIN b[78]
    DIRECTION OUTPUT ;
    USE SIGNAL ;
    PORT
      LAYER M5 ;
        RECT  30.096 99.252 30.12 99.336 ;
    END
  END b[78]
  PIN b[79]
    DIRECTION OUTPUT ;
    USE SIGNAL ;
    PORT
      LAYER M5 ;
        RECT  30.192 99.252 30.216 99.336 ;
    END
  END b[79]
  PIN b[7]
    DIRECTION OUTPUT ;
    USE SIGNAL ;
    PORT
      LAYER M5 ;
        RECT  23.28 99.252 23.304 99.336 ;
    END
  END b[7]
  PIN b[80]
    DIRECTION OUTPUT ;
    USE SIGNAL ;
    PORT
      LAYER M5 ;
        RECT  30.288 99.252 30.312 99.336 ;
    END
  END b[80]
  PIN b[81]
    DIRECTION OUTPUT ;
    USE SIGNAL ;
    PORT
      LAYER M5 ;
        RECT  30.384 99.252 30.408 99.336 ;
    END
  END b[81]
  PIN b[82]
    DIRECTION OUTPUT ;
    USE SIGNAL ;
    PORT
      LAYER M5 ;
        RECT  30.48 99.252 30.504 99.336 ;
    END
  END b[82]
  PIN b[83]
    DIRECTION OUTPUT ;
    USE SIGNAL ;
    PORT
      LAYER M5 ;
        RECT  30.576 99.252 30.6 99.336 ;
    END
  END b[83]
  PIN b[84]
    DIRECTION OUTPUT ;
    USE SIGNAL ;
    PORT
      LAYER M5 ;
        RECT  30.672 99.252 30.696 99.336 ;
    END
  END b[84]
  PIN b[85]
    DIRECTION OUTPUT ;
    USE SIGNAL ;
    PORT
      LAYER M5 ;
        RECT  30.768 99.252 30.792 99.336 ;
    END
  END b[85]
  PIN b[86]
    DIRECTION OUTPUT ;
    USE SIGNAL ;
    PORT
      LAYER M5 ;
        RECT  30.864 99.252 30.888 99.336 ;
    END
  END b[86]
  PIN b[87]
    DIRECTION OUTPUT ;
    USE SIGNAL ;
    PORT
      LAYER M5 ;
        RECT  30.96 99.252 30.984 99.336 ;
    END
  END b[87]
  PIN b[88]
    DIRECTION OUTPUT ;
    USE SIGNAL ;
    PORT
      LAYER M5 ;
        RECT  31.056 99.252 31.08 99.336 ;
    END
  END b[88]
  PIN b[89]
    DIRECTION OUTPUT ;
    USE SIGNAL ;
    PORT
      LAYER M5 ;
        RECT  31.152 99.252 31.176 99.336 ;
    END
  END b[89]
  PIN b[8]
    DIRECTION OUTPUT ;
    USE SIGNAL ;
    PORT
      LAYER M5 ;
        RECT  23.376 99.252 23.4 99.336 ;
    END
  END b[8]
  PIN b[90]
    DIRECTION OUTPUT ;
    USE SIGNAL ;
    PORT
      LAYER M5 ;
        RECT  31.248 99.252 31.272 99.336 ;
    END
  END b[90]
  PIN b[91]
    DIRECTION OUTPUT ;
    USE SIGNAL ;
    PORT
      LAYER M5 ;
        RECT  31.344 99.252 31.368 99.336 ;
    END
  END b[91]
  PIN b[92]
    DIRECTION OUTPUT ;
    USE SIGNAL ;
    PORT
      LAYER M5 ;
        RECT  31.44 99.252 31.464 99.336 ;
    END
  END b[92]
  PIN b[93]
    DIRECTION OUTPUT ;
    USE SIGNAL ;
    PORT
      LAYER M5 ;
        RECT  31.536 99.252 31.56 99.336 ;
    END
  END b[93]
  PIN b[94]
    DIRECTION OUTPUT ;
    USE SIGNAL ;
    PORT
      LAYER M5 ;
        RECT  31.632 99.252 31.656 99.336 ;
    END
  END b[94]
  PIN b[95]
    DIRECTION OUTPUT ;
    USE SIGNAL ;
    PORT
      LAYER M5 ;
        RECT  31.728 99.252 31.752 99.336 ;
    END
  END b[95]
  PIN b[96]
    DIRECTION OUTPUT ;
    USE SIGNAL ;
    PORT
      LAYER M3 ;
        RECT  32.004 99.299 32.022 99.336 ;
    END
  END b[96]
  PIN b[97]
    DIRECTION OUTPUT ;
    USE SIGNAL ;
    PORT
      LAYER M3 ;
        RECT  32.076 99.299 32.094 99.336 ;
    END
  END b[97]
  PIN b[98]
    DIRECTION OUTPUT ;
    USE SIGNAL ;
    PORT
      LAYER M3 ;
        RECT  32.148 99.299 32.166 99.336 ;
    END
  END b[98]
  PIN b[99]
    DIRECTION OUTPUT ;
    USE SIGNAL ;
    PORT
      LAYER M3 ;
        RECT  32.22 99.299 32.238 99.336 ;
    END
  END b[99]
  PIN b[9]
    DIRECTION OUTPUT ;
    USE SIGNAL ;
    PORT
      LAYER M5 ;
        RECT  23.472 99.252 23.496 99.336 ;
    END
  END b[9]
  PIN ck
    DIRECTION INPUT ;
    USE SIGNAL ;
    PORT
      LAYER M4 ;
        RECT  0 53.328 0.084 53.352 ;
    END
  END ck
  PIN ckf
    DIRECTION INPUT ;
    USE SIGNAL ;
    PORT
      LAYER M4 ;
        RECT  0 53.424 0.084 53.448 ;
    END
  END ckf
  PIN ea
    DIRECTION INPUT ;
    USE SIGNAL ;
    PORT
      LAYER M4 ;
        RECT  99.252 64.848 99.336 64.872 ;
    END
  END ea
  PIN fault
    DIRECTION OUTPUT ;
    USE SIGNAL ;
    PORT
      LAYER M4 ;
        RECT  0 53.52 0.084 53.544 ;
    END
  END fault
  PIN k0
    DIRECTION INPUT ;
    USE SIGNAL ;
    PORT
      LAYER M4 ;
        RECT  0 53.616 0.084 53.64 ;
    END
  END k0
  PIN k1
    DIRECTION INPUT ;
    USE SIGNAL ;
    PORT
      LAYER M4 ;
        RECT  0 53.712 0.084 53.736 ;
    END
  END k1
  PIN k2
    DIRECTION INPUT ;
    USE SIGNAL ;
    PORT
      LAYER M4 ;
        RECT  0 53.808 0.084 53.832 ;
    END
  END k2
  PIN rs
    DIRECTION INPUT ;
    USE SIGNAL ;
    PORT
      LAYER M4 ;
        RECT  0 53.904 0.084 53.928 ;
    END
  END rs
  PIN tie_hi
    DIRECTION OUTPUT ;
    USE SIGNAL ;
    PORT
      LAYER M4 ;
        RECT  0 54 0.084 54.024 ;
    END
  END tie_hi
  PIN tie_lo
    DIRECTION OUTPUT ;
    USE SIGNAL ;
    PORT
      LAYER M4 ;
        RECT  0 54.096 0.084 54.12 ;
    END
  END tie_lo
  PIN VDD
    DIRECTION INOUT ;
    USE POWER ;
    PORT
      LAYER M5 ;
        RECT  94.392 2.151 94.512 96.953 ;
        RECT  91.692 2.151 91.812 96.953 ;
        RECT  88.992 2.151 89.112 96.953 ;
        RECT  86.292 2.151 86.412 96.953 ;
        RECT  83.592 2.151 83.712 96.953 ;
        RECT  80.892 2.151 81.012 96.953 ;
        RECT  78.192 2.151 78.312 96.953 ;
        RECT  75.492 2.151 75.612 96.953 ;
        RECT  72.792 2.151 72.912 96.953 ;
        RECT  70.092 2.151 70.212 96.953 ;
        RECT  67.392 2.151 67.512 96.953 ;
        RECT  64.692 2.151 64.812 96.953 ;
        RECT  61.992 2.151 62.112 96.953 ;
        RECT  59.292 2.151 59.412 96.953 ;
        RECT  56.592 2.151 56.712 96.953 ;
        RECT  53.892 2.151 54.012 96.953 ;
        RECT  51.192 2.151 51.312 96.953 ;
        RECT  48.492 2.151 48.612 96.953 ;
        RECT  45.792 2.151 45.912 96.953 ;
        RECT  43.092 2.151 43.212 96.953 ;
        RECT  40.392 2.151 40.512 96.953 ;
        RECT  37.692 2.151 37.812 96.953 ;
        RECT  34.992 2.151 35.112 96.953 ;
        RECT  32.292 2.151 32.412 96.953 ;
        RECT  29.592 2.151 29.712 96.953 ;
        RECT  26.892 2.151 27.012 96.953 ;
        RECT  24.192 2.151 24.312 96.953 ;
        RECT  21.492 2.151 21.612 96.953 ;
        RECT  18.792 2.151 18.912 96.953 ;
        RECT  16.092 2.151 16.212 96.953 ;
        RECT  13.392 2.151 13.512 96.953 ;
        RECT  10.692 2.151 10.812 96.953 ;
        RECT  7.992 2.151 8.112 96.953 ;
        RECT  5.292 2.151 5.412 96.953 ;
        RECT  2.592 2.151 2.712 96.953 ;
    END
  END VDD
  PIN VSS
    DIRECTION INOUT ;
    USE GROUND ;
    PORT
      LAYER M5 ;
        RECT  96.9 2.137 97.02 96.939 ;
        RECT  94.2 2.137 94.32 96.939 ;
        RECT  91.5 2.137 91.62 96.939 ;
        RECT  88.8 2.137 88.92 96.939 ;
        RECT  86.1 2.137 86.22 96.939 ;
        RECT  83.4 2.137 83.52 96.939 ;
        RECT  80.7 2.137 80.82 96.939 ;
        RECT  78 2.137 78.12 96.939 ;
        RECT  75.3 2.137 75.42 96.939 ;
        RECT  72.6 2.137 72.72 96.939 ;
        RECT  69.9 2.137 70.02 96.939 ;
        RECT  67.2 2.137 67.32 96.939 ;
        RECT  64.5 2.137 64.62 96.939 ;
        RECT  61.8 2.137 61.92 96.939 ;
        RECT  59.1 2.137 59.22 96.939 ;
        RECT  56.4 2.137 56.52 96.939 ;
        RECT  53.7 2.137 53.82 96.939 ;
        RECT  51 2.137 51.12 96.939 ;
        RECT  48.3 2.137 48.42 96.939 ;
        RECT  45.6 2.137 45.72 96.939 ;
        RECT  42.9 2.137 43.02 96.939 ;
        RECT  40.2 2.137 40.32 96.939 ;
        RECT  37.5 2.137 37.62 96.939 ;
        RECT  34.8 2.137 34.92 96.939 ;
        RECT  32.1 2.137 32.22 96.939 ;
        RECT  29.4 2.137 29.52 96.939 ;
        RECT  26.7 2.137 26.82 96.939 ;
        RECT  24 2.137 24.12 96.939 ;
        RECT  21.3 2.137 21.42 96.939 ;
        RECT  18.6 2.137 18.72 96.939 ;
        RECT  15.9 2.137 16.02 96.939 ;
        RECT  13.2 2.137 13.32 96.939 ;
        RECT  10.5 2.137 10.62 96.939 ;
        RECT  7.8 2.137 7.92 96.939 ;
        RECT  5.1 2.137 5.22 96.939 ;
        RECT  2.4 2.137 2.52 96.939 ;
    END
  END VSS
  OBS
    LAYER RVTN ;
     RECT  2.16 2.16 97.146 2.295 ;
     RECT  2.16 2.565 97.146 2.835 ;
     RECT  2.16 3.105 97.146 3.375 ;
     RECT  2.16 3.645 97.146 3.915 ;
     RECT  2.16 4.185 97.146 4.455 ;
     RECT  2.16 4.725 97.146 4.995 ;
     RECT  2.16 5.265 97.146 5.535 ;
     RECT  2.16 5.805 97.146 6.075 ;
     RECT  2.16 6.345 97.146 6.615 ;
     RECT  2.16 6.885 97.146 7.155 ;
     RECT  2.16 7.425 97.146 7.695 ;
     RECT  2.16 7.965 97.146 8.235 ;
     RECT  2.16 8.505 97.146 8.775 ;
     RECT  2.16 9.045 97.146 9.315 ;
     RECT  2.16 9.585 97.146 9.855 ;
     RECT  2.16 10.125 97.146 10.395 ;
     RECT  2.16 10.665 97.146 10.935 ;
     RECT  2.16 11.205 97.146 11.475 ;
     RECT  2.16 11.745 97.146 12.015 ;
     RECT  2.16 12.285 97.146 12.555 ;
     RECT  2.16 12.825 97.146 13.095 ;
     RECT  2.16 13.365 97.146 13.635 ;
     RECT  2.16 13.905 97.146 14.175 ;
     RECT  2.16 14.445 97.146 14.715 ;
     RECT  2.16 14.985 97.146 15.255 ;
     RECT  2.16 15.525 97.146 15.795 ;
     RECT  2.16 16.065 97.146 16.335 ;
     RECT  2.16 16.605 97.146 16.875 ;
     RECT  2.16 17.145 97.146 17.415 ;
     RECT  2.16 17.685 97.146 17.955 ;
     RECT  2.16 18.225 97.146 18.495 ;
     RECT  2.16 18.765 97.146 19.035 ;
     RECT  2.16 19.305 97.146 19.575 ;
     RECT  2.16 19.845 97.146 20.115 ;
     RECT  2.16 20.385 97.146 20.655 ;
     RECT  2.16 20.925 97.146 21.195 ;
     RECT  2.16 21.465 97.146 21.735 ;
     RECT  2.16 22.005 97.146 22.275 ;
     RECT  2.16 22.545 97.146 22.815 ;
     RECT  2.16 23.085 97.146 23.355 ;
     RECT  2.16 23.625 97.146 23.895 ;
     RECT  2.16 24.165 97.146 24.435 ;
     RECT  2.16 24.705 97.146 24.975 ;
     RECT  2.16 25.245 97.146 25.515 ;
     RECT  2.16 25.785 97.146 26.055 ;
     RECT  2.16 26.325 97.146 26.595 ;
     RECT  2.16 26.865 97.146 27.135 ;
     RECT  2.16 27.405 97.146 27.675 ;
     RECT  2.16 27.945 97.146 28.215 ;
     RECT  2.16 28.485 97.146 28.755 ;
     RECT  2.16 29.025 97.146 29.295 ;
     RECT  2.16 29.565 97.146 29.835 ;
     RECT  2.16 30.105 97.146 30.375 ;
     RECT  2.16 30.645 97.146 30.915 ;
     RECT  2.16 31.185 97.146 31.455 ;
     RECT  2.16 31.725 97.146 31.995 ;
     RECT  2.16 32.265 97.146 32.535 ;
     RECT  2.16 32.805 97.146 33.075 ;
     RECT  2.16 33.345 97.146 33.615 ;
     RECT  2.16 33.885 97.146 34.155 ;
     RECT  2.16 34.425 97.146 34.695 ;
     RECT  2.16 34.965 97.146 35.235 ;
     RECT  2.16 35.505 97.146 35.775 ;
     RECT  2.16 36.045 97.146 36.315 ;
     RECT  2.16 36.585 97.146 36.855 ;
     RECT  2.16 37.125 97.146 37.395 ;
     RECT  2.16 37.665 97.146 37.935 ;
     RECT  2.16 38.205 97.146 38.475 ;
     RECT  2.16 38.745 97.146 39.015 ;
     RECT  2.16 39.285 97.146 39.555 ;
     RECT  2.16 39.825 97.146 40.095 ;
     RECT  2.16 40.365 97.146 40.635 ;
     RECT  2.16 40.905 97.146 41.175 ;
     RECT  2.16 41.445 97.146 41.715 ;
     RECT  2.16 41.985 97.146 42.255 ;
     RECT  2.16 42.525 97.146 42.795 ;
     RECT  2.16 43.065 97.146 43.335 ;
     RECT  2.16 43.605 97.146 43.875 ;
     RECT  2.16 44.145 97.146 44.415 ;
     RECT  2.16 44.685 97.146 44.955 ;
     RECT  2.16 45.225 97.146 45.495 ;
     RECT  2.16 45.765 97.146 46.035 ;
     RECT  2.16 46.305 97.146 46.575 ;
     RECT  2.16 46.845 97.146 47.115 ;
     RECT  2.16 47.385 97.146 47.655 ;
     RECT  2.16 47.925 97.146 48.195 ;
     RECT  2.16 48.465 97.146 48.735 ;
     RECT  2.16 49.005 97.146 49.275 ;
     RECT  2.16 49.545 97.146 49.815 ;
     RECT  2.16 50.085 97.146 50.355 ;
     RECT  2.16 50.625 97.146 50.895 ;
     RECT  2.16 51.165 97.146 51.435 ;
     RECT  2.16 51.705 97.146 51.975 ;
     RECT  2.16 52.245 97.146 52.515 ;
     RECT  2.16 52.785 97.146 53.055 ;
     RECT  2.16 53.325 97.146 53.595 ;
     RECT  2.16 53.865 97.146 54.135 ;
     RECT  2.16 54.405 97.146 54.675 ;
     RECT  2.16 54.945 97.146 55.215 ;
     RECT  2.16 55.485 97.146 55.755 ;
     RECT  2.16 56.025 97.146 56.295 ;
     RECT  2.16 56.565 97.146 56.835 ;
     RECT  2.16 57.105 97.146 57.375 ;
     RECT  2.16 57.645 97.146 57.915 ;
     RECT  2.16 58.185 97.146 58.455 ;
     RECT  2.16 58.725 97.146 58.995 ;
     RECT  2.16 59.265 97.146 59.535 ;
     RECT  2.16 59.805 97.146 60.075 ;
     RECT  2.16 60.345 97.146 60.615 ;
     RECT  2.16 60.885 97.146 61.155 ;
     RECT  2.16 61.425 97.146 61.695 ;
     RECT  2.16 61.965 97.146 62.235 ;
     RECT  2.16 62.505 97.146 62.775 ;
     RECT  2.16 63.045 97.146 63.315 ;
     RECT  2.16 63.585 97.146 63.855 ;
     RECT  2.16 64.125 97.146 64.395 ;
     RECT  2.16 64.665 97.146 64.935 ;
     RECT  2.16 65.205 97.146 65.475 ;
     RECT  2.16 65.745 97.146 66.015 ;
     RECT  2.16 66.285 97.146 66.555 ;
     RECT  2.16 66.825 97.146 67.095 ;
     RECT  2.16 67.365 97.146 67.635 ;
     RECT  2.16 67.905 97.146 68.175 ;
     RECT  2.16 68.445 97.146 68.715 ;
     RECT  2.16 68.985 97.146 69.255 ;
     RECT  2.16 69.525 97.146 69.795 ;
     RECT  2.16 70.065 97.146 70.335 ;
     RECT  2.16 70.605 97.146 70.875 ;
     RECT  2.16 71.145 97.146 71.415 ;
     RECT  2.16 71.685 97.146 71.955 ;
     RECT  2.16 72.225 97.146 72.495 ;
     RECT  2.16 72.765 97.146 73.035 ;
     RECT  2.16 73.305 97.146 73.575 ;
     RECT  2.16 73.845 97.146 74.115 ;
     RECT  2.16 74.385 97.146 74.655 ;
     RECT  2.16 74.925 97.146 75.195 ;
     RECT  2.16 75.465 97.146 75.735 ;
     RECT  2.16 76.005 97.146 76.275 ;
     RECT  2.16 76.545 97.146 76.815 ;
     RECT  2.16 77.085 97.146 77.355 ;
     RECT  2.16 77.625 97.146 77.895 ;
     RECT  2.16 78.165 97.146 78.435 ;
     RECT  2.16 78.705 97.146 78.975 ;
     RECT  2.16 79.245 97.146 79.515 ;
     RECT  2.16 79.785 97.146 80.055 ;
     RECT  2.16 80.325 97.146 80.595 ;
     RECT  2.16 80.865 97.146 81.135 ;
     RECT  2.16 81.405 97.146 81.675 ;
     RECT  2.16 81.945 97.146 82.215 ;
     RECT  2.16 82.485 97.146 82.755 ;
     RECT  2.16 83.025 97.146 83.295 ;
     RECT  2.16 83.565 97.146 83.835 ;
     RECT  2.16 84.105 97.146 84.375 ;
     RECT  2.16 84.645 97.146 84.915 ;
     RECT  2.16 85.185 97.146 85.455 ;
     RECT  2.16 85.725 97.146 85.995 ;
     RECT  2.16 86.265 97.146 86.535 ;
     RECT  2.16 86.805 97.146 87.075 ;
     RECT  2.16 87.345 97.146 87.615 ;
     RECT  2.16 87.885 97.146 88.155 ;
     RECT  2.16 88.425 97.146 88.695 ;
     RECT  2.16 88.965 97.146 89.235 ;
     RECT  2.16 89.505 97.146 89.775 ;
     RECT  2.16 90.045 97.146 90.315 ;
     RECT  2.16 90.585 97.146 90.855 ;
     RECT  2.16 91.125 97.146 91.395 ;
     RECT  2.16 91.665 97.146 91.935 ;
     RECT  2.16 92.205 97.146 92.475 ;
     RECT  2.16 92.745 97.146 93.015 ;
     RECT  2.16 93.285 97.146 93.555 ;
     RECT  2.16 93.825 97.146 94.095 ;
     RECT  2.16 94.365 97.146 94.635 ;
     RECT  2.16 94.905 97.146 95.175 ;
     RECT  2.16 95.445 97.146 95.715 ;
     RECT  2.16 95.985 97.146 96.255 ;
     RECT  2.16 96.525 97.146 96.795 ;
    LAYER RVTP ;
     RECT  2.16 2.295 97.146 2.565 ;
     RECT  2.16 2.835 97.146 3.105 ;
     RECT  2.16 3.375 97.146 3.645 ;
     RECT  2.16 3.915 97.146 4.185 ;
     RECT  2.16 4.455 97.146 4.725 ;
     RECT  2.16 4.995 97.146 5.265 ;
     RECT  2.16 5.535 97.146 5.805 ;
     RECT  2.16 6.075 97.146 6.345 ;
     RECT  2.16 6.615 97.146 6.885 ;
     RECT  2.16 7.155 97.146 7.425 ;
     RECT  2.16 7.695 97.146 7.965 ;
     RECT  2.16 8.235 97.146 8.505 ;
     RECT  2.16 8.775 97.146 9.045 ;
     RECT  2.16 9.315 97.146 9.585 ;
     RECT  2.16 9.855 97.146 10.125 ;
     RECT  2.16 10.395 97.146 10.665 ;
     RECT  2.16 10.935 97.146 11.205 ;
     RECT  2.16 11.475 97.146 11.745 ;
     RECT  2.16 12.015 97.146 12.285 ;
     RECT  2.16 12.555 97.146 12.825 ;
     RECT  2.16 13.095 97.146 13.365 ;
     RECT  2.16 13.635 97.146 13.905 ;
     RECT  2.16 14.175 97.146 14.445 ;
     RECT  2.16 14.715 97.146 14.985 ;
     RECT  2.16 15.255 97.146 15.525 ;
     RECT  2.16 15.795 97.146 16.065 ;
     RECT  2.16 16.335 97.146 16.605 ;
     RECT  2.16 16.875 97.146 17.145 ;
     RECT  2.16 17.415 97.146 17.685 ;
     RECT  2.16 17.955 97.146 18.225 ;
     RECT  2.16 18.495 97.146 18.765 ;
     RECT  2.16 19.035 97.146 19.305 ;
     RECT  2.16 19.575 97.146 19.845 ;
     RECT  2.16 20.115 97.146 20.385 ;
     RECT  2.16 20.655 97.146 20.925 ;
     RECT  2.16 21.195 97.146 21.465 ;
     RECT  2.16 21.735 97.146 22.005 ;
     RECT  2.16 22.275 97.146 22.545 ;
     RECT  2.16 22.815 97.146 23.085 ;
     RECT  2.16 23.355 97.146 23.625 ;
     RECT  2.16 23.895 97.146 24.165 ;
     RECT  2.16 24.435 97.146 24.705 ;
     RECT  2.16 24.975 97.146 25.245 ;
     RECT  2.16 25.515 97.146 25.785 ;
     RECT  2.16 26.055 97.146 26.325 ;
     RECT  2.16 26.595 97.146 26.865 ;
     RECT  2.16 27.135 97.146 27.405 ;
     RECT  2.16 27.675 97.146 27.945 ;
     RECT  2.16 28.215 97.146 28.485 ;
     RECT  2.16 28.755 97.146 29.025 ;
     RECT  2.16 29.295 97.146 29.565 ;
     RECT  2.16 29.835 97.146 30.105 ;
     RECT  2.16 30.375 97.146 30.645 ;
     RECT  2.16 30.915 97.146 31.185 ;
     RECT  2.16 31.455 97.146 31.725 ;
     RECT  2.16 31.995 97.146 32.265 ;
     RECT  2.16 32.535 97.146 32.805 ;
     RECT  2.16 33.075 97.146 33.345 ;
     RECT  2.16 33.615 97.146 33.885 ;
     RECT  2.16 34.155 97.146 34.425 ;
     RECT  2.16 34.695 97.146 34.965 ;
     RECT  2.16 35.235 97.146 35.505 ;
     RECT  2.16 35.775 97.146 36.045 ;
     RECT  2.16 36.315 97.146 36.585 ;
     RECT  2.16 36.855 97.146 37.125 ;
     RECT  2.16 37.395 97.146 37.665 ;
     RECT  2.16 37.935 97.146 38.205 ;
     RECT  2.16 38.475 97.146 38.745 ;
     RECT  2.16 39.015 97.146 39.285 ;
     RECT  2.16 39.555 97.146 39.825 ;
     RECT  2.16 40.095 97.146 40.365 ;
     RECT  2.16 40.635 97.146 40.905 ;
     RECT  2.16 41.175 97.146 41.445 ;
     RECT  2.16 41.715 97.146 41.985 ;
     RECT  2.16 42.255 97.146 42.525 ;
     RECT  2.16 42.795 97.146 43.065 ;
     RECT  2.16 43.335 97.146 43.605 ;
     RECT  2.16 43.875 97.146 44.145 ;
     RECT  2.16 44.415 97.146 44.685 ;
     RECT  2.16 44.955 97.146 45.225 ;
     RECT  2.16 45.495 97.146 45.765 ;
     RECT  2.16 46.035 97.146 46.305 ;
     RECT  2.16 46.575 97.146 46.845 ;
     RECT  2.16 47.115 97.146 47.385 ;
     RECT  2.16 47.655 97.146 47.925 ;
     RECT  2.16 48.195 97.146 48.465 ;
     RECT  2.16 48.735 97.146 49.005 ;
     RECT  2.16 49.275 97.146 49.545 ;
     RECT  2.16 49.815 97.146 50.085 ;
     RECT  2.16 50.355 97.146 50.625 ;
     RECT  2.16 50.895 97.146 51.165 ;
     RECT  2.16 51.435 97.146 51.705 ;
     RECT  2.16 51.975 97.146 52.245 ;
     RECT  2.16 52.515 97.146 52.785 ;
     RECT  2.16 53.055 97.146 53.325 ;
     RECT  2.16 53.595 97.146 53.865 ;
     RECT  2.16 54.135 97.146 54.405 ;
     RECT  2.16 54.675 97.146 54.945 ;
     RECT  2.16 55.215 97.146 55.485 ;
     RECT  2.16 55.755 97.146 56.025 ;
     RECT  2.16 56.295 97.146 56.565 ;
     RECT  2.16 56.835 97.146 57.105 ;
     RECT  2.16 57.375 97.146 57.645 ;
     RECT  2.16 57.915 97.146 58.185 ;
     RECT  2.16 58.455 97.146 58.725 ;
     RECT  2.16 58.995 97.146 59.265 ;
     RECT  2.16 59.535 97.146 59.805 ;
     RECT  2.16 60.075 97.146 60.345 ;
     RECT  2.16 60.615 97.146 60.885 ;
     RECT  2.16 61.155 97.146 61.425 ;
     RECT  2.16 61.695 97.146 61.965 ;
     RECT  2.16 62.235 97.146 62.505 ;
     RECT  2.16 62.775 97.146 63.045 ;
     RECT  2.16 63.315 97.146 63.585 ;
     RECT  2.16 63.855 97.146 64.125 ;
     RECT  2.16 64.395 97.146 64.665 ;
     RECT  2.16 64.935 97.146 65.205 ;
     RECT  2.16 65.475 97.146 65.745 ;
     RECT  2.16 66.015 97.146 66.285 ;
     RECT  2.16 66.555 97.146 66.825 ;
     RECT  2.16 67.095 97.146 67.365 ;
     RECT  2.16 67.635 97.146 67.905 ;
     RECT  2.16 68.175 97.146 68.445 ;
     RECT  2.16 68.715 97.146 68.985 ;
     RECT  2.16 69.255 97.146 69.525 ;
     RECT  2.16 69.795 97.146 70.065 ;
     RECT  2.16 70.335 97.146 70.605 ;
     RECT  2.16 70.875 97.146 71.145 ;
     RECT  2.16 71.415 97.146 71.685 ;
     RECT  2.16 71.955 97.146 72.225 ;
     RECT  2.16 72.495 97.146 72.765 ;
     RECT  2.16 73.035 97.146 73.305 ;
     RECT  2.16 73.575 97.146 73.845 ;
     RECT  2.16 74.115 97.146 74.385 ;
     RECT  2.16 74.655 97.146 74.925 ;
     RECT  2.16 75.195 97.146 75.465 ;
     RECT  2.16 75.735 97.146 76.005 ;
     RECT  2.16 76.275 97.146 76.545 ;
     RECT  2.16 76.815 97.146 77.085 ;
     RECT  2.16 77.355 97.146 77.625 ;
     RECT  2.16 77.895 97.146 78.165 ;
     RECT  2.16 78.435 97.146 78.705 ;
     RECT  2.16 78.975 97.146 79.245 ;
     RECT  2.16 79.515 97.146 79.785 ;
     RECT  2.16 80.055 97.146 80.325 ;
     RECT  2.16 80.595 97.146 80.865 ;
     RECT  2.16 81.135 97.146 81.405 ;
     RECT  2.16 81.675 97.146 81.945 ;
     RECT  2.16 82.215 97.146 82.485 ;
     RECT  2.16 82.755 97.146 83.025 ;
     RECT  2.16 83.295 97.146 83.565 ;
     RECT  2.16 83.835 97.146 84.105 ;
     RECT  2.16 84.375 97.146 84.645 ;
     RECT  2.16 84.915 97.146 85.185 ;
     RECT  2.16 85.455 97.146 85.725 ;
     RECT  2.16 85.995 97.146 86.265 ;
     RECT  2.16 86.535 97.146 86.805 ;
     RECT  2.16 87.075 97.146 87.345 ;
     RECT  2.16 87.615 97.146 87.885 ;
     RECT  2.16 88.155 97.146 88.425 ;
     RECT  2.16 88.695 97.146 88.965 ;
     RECT  2.16 89.235 97.146 89.505 ;
     RECT  2.16 89.775 97.146 90.045 ;
     RECT  2.16 90.315 97.146 90.585 ;
     RECT  2.16 90.855 97.146 91.125 ;
     RECT  2.16 91.395 97.146 91.665 ;
     RECT  2.16 91.935 97.146 92.205 ;
     RECT  2.16 92.475 97.146 92.745 ;
     RECT  2.16 93.015 97.146 93.285 ;
     RECT  2.16 93.555 97.146 93.825 ;
     RECT  2.16 94.095 97.146 94.365 ;
     RECT  2.16 94.635 97.146 94.905 ;
     RECT  2.16 95.175 97.146 95.445 ;
     RECT  2.16 95.715 97.146 95.985 ;
     RECT  2.16 96.255 97.146 96.525 ;
     RECT  2.16 96.795 97.146 96.93 ;
    LAYER M1 ;
     RECT  2.16 2.151 97.146 96.939 ;
    LAYER M2 ;
     RECT  0.103 54.306 2.16 54.324 ;
     RECT  2.16 2.151 22.855 96.939 ;
     RECT  22.855 2.151 22.991 96.984 ;
     RECT  22.991 2.151 24.115 96.939 ;
     RECT  24.511 98.154 24.611 98.172 ;
     RECT  24.583 99.081 24.691 99.099 ;
     RECT  24.115 2.151 24.763 96.984 ;
     RECT  24.763 2.151 24.899 97.596 ;
     RECT  24.691 99.081 24.907 99.216 ;
     RECT  24.907 99.081 24.943 99.288 ;
     RECT  24.943 98.586 25.447 99.288 ;
     RECT  25.447 98.424 25.547 99.288 ;
     RECT  24.899 2.151 25.699 97.02 ;
     RECT  25.699 2.151 25.871 97.128 ;
     RECT  25.547 98.46 26.563 99.288 ;
     RECT  26.563 98.424 26.663 99.288 ;
     RECT  26.663 98.424 26.699 99.216 ;
     RECT  26.699 99.126 26.771 99.144 ;
     RECT  31.531 98.496 31.567 98.514 ;
     RECT  31.567 98.424 31.639 99.216 ;
     RECT  31.639 98.424 31.739 99.288 ;
     RECT  31.739 98.424 31.883 99.216 ;
     RECT  25.871 2.151 31.963 96.939 ;
     RECT  31.963 2.151 32.359 96.984 ;
     RECT  31.883 98.496 32.575 99.216 ;
     RECT  32.575 98.496 32.675 99.288 ;
     RECT  32.675 98.541 33.871 99.288 ;
     RECT  33.871 98.496 34.043 99.288 ;
     RECT  34.043 98.496 34.079 99.18 ;
     RECT  32.359 2.151 34.403 97.479 ;
     RECT  34.079 98.586 34.619 98.604 ;
     RECT  34.403 2.151 35.375 97.128 ;
     RECT  35.375 2.151 35.879 97.056 ;
     RECT  38.947 99.27 39.343 99.288 ;
     RECT  39.343 99.126 39.703 99.288 ;
     RECT  35.879 2.151 39.739 96.939 ;
     RECT  39.703 99.081 39.775 99.288 ;
     RECT  39.739 2.151 40.127 96.984 ;
     RECT  39.775 98.586 40.171 99.288 ;
     RECT  40.171 98.496 40.379 99.288 ;
     RECT  40.379 98.541 41.495 99.288 ;
     RECT  41.495 98.586 41.531 99.288 ;
     RECT  40.127 2.151 42.367 96.939 ;
     RECT  41.531 99.081 42.511 99.288 ;
     RECT  42.511 98.586 42.719 99.288 ;
     RECT  42.367 2.151 42.799 97.434 ;
     RECT  42.799 2.151 43.439 97.479 ;
     RECT  42.719 99.081 43.483 99.288 ;
     RECT  43.483 98.496 43.619 99.288 ;
     RECT  43.619 98.541 44.411 99.288 ;
     RECT  44.411 98.586 44.771 99.288 ;
     RECT  44.771 98.964 45.499 99.288 ;
     RECT  43.439 2.151 45.571 96.939 ;
     RECT  45.499 98.586 45.635 99.288 ;
     RECT  45.635 99.081 47.083 99.288 ;
     RECT  47.083 99.036 47.371 99.288 ;
     RECT  47.371 98.964 47.723 99.288 ;
     RECT  47.723 98.964 48.227 99.252 ;
     RECT  48.227 99.036 48.443 99.252 ;
     RECT  48.443 99.198 48.487 99.252 ;
     RECT  48.487 99.198 48.911 99.288 ;
     RECT  48.911 99.198 49.019 99.216 ;
     RECT  45.571 2.151 49.991 96.984 ;
     RECT  60.835 99.27 60.979 99.288 ;
     RECT  60.979 98.541 61.439 99.288 ;
     RECT  49.991 2.151 61.699 96.939 ;
     RECT  61.699 2.151 61.835 96.984 ;
     RECT  61.439 99.081 62.275 99.288 ;
     RECT  62.275 99 62.411 99.288 ;
     RECT  62.411 99.126 62.483 99.288 ;
     RECT  62.483 99.27 63.275 99.288 ;
     RECT  72.535 99.27 73.039 99.288 ;
     RECT  73.039 99.126 73.399 99.288 ;
     RECT  73.399 99.036 73.499 99.288 ;
     RECT  73.499 99.081 73.895 99.288 ;
     RECT  73.895 99.081 74.039 99.216 ;
     RECT  74.191 97.776 74.407 97.794 ;
     RECT  74.407 97.731 74.479 97.794 ;
     RECT  74.335 98.586 74.479 98.604 ;
     RECT  61.835 2.151 74.623 96.939 ;
     RECT  74.479 97.731 74.767 98.604 ;
     RECT  74.767 97.731 75.119 99.288 ;
     RECT  75.119 97.731 75.191 98.604 ;
     RECT  75.191 97.731 75.227 98.559 ;
     RECT  74.623 2.151 76.271 96.984 ;
     RECT  75.227 97.731 76.919 98.334 ;
     RECT  76.919 98.316 78.791 98.334 ;
     RECT  76.271 2.151 97.146 96.939 ;
     RECT  97.146 34.506 97.151 41.13 ;
     RECT  97.146 41.994 97.151 44.406 ;
     RECT  97.146 72.846 97.151 73.944 ;
     RECT  97.146 74.97 97.151 77.994 ;
     RECT  97.146 79.758 97.151 80.28 ;
     RECT  97.146 23.526 97.187 23.994 ;
     RECT  97.146 24.786 97.187 28.314 ;
     RECT  97.146 33.516 97.187 33.534 ;
     RECT  97.151 39.366 97.187 40.968 ;
     RECT  97.146 57.996 97.187 61.182 ;
     RECT  97.146 62.55 97.187 66.924 ;
     RECT  97.146 67.914 97.187 71.442 ;
     RECT  97.151 74.97 97.187 77.724 ;
     RECT  97.151 79.992 97.187 80.28 ;
     RECT  97.187 24.786 97.223 24.804 ;
     RECT  97.151 34.506 97.223 38.502 ;
     RECT  97.187 40.446 97.223 40.968 ;
     RECT  97.187 64.71 97.223 66.924 ;
     RECT  97.187 80.136 97.223 80.28 ;
     RECT  97.223 34.506 97.259 35.064 ;
     RECT  97.223 64.71 97.259 66.114 ;
     RECT  97.187 67.914 97.259 70.632 ;
     RECT  97.259 34.506 97.295 34.758 ;
     RECT  97.187 71.424 97.403 71.442 ;
     RECT  97.223 35.82 97.475 38.502 ;
     RECT  97.223 40.446 97.475 40.698 ;
     RECT  97.146 52.56 97.475 52.578 ;
     RECT  97.146 55.494 97.475 57.024 ;
     RECT  97.151 73.044 97.475 73.098 ;
     RECT  97.187 23.526 97.511 23.58 ;
     RECT  97.146 29.106 97.511 30.438 ;
     RECT  97.146 49.32 97.511 50.922 ;
     RECT  97.187 59.814 97.511 61.182 ;
     RECT  97.511 60.39 97.583 61.182 ;
     RECT  97.511 29.106 97.763 30.132 ;
     RECT  97.295 34.74 97.763 34.758 ;
     RECT  97.475 35.82 97.763 37.764 ;
     RECT  97.475 40.68 97.763 40.698 ;
     RECT  97.146 45.306 97.763 48.024 ;
     RECT  97.475 73.044 97.799 73.062 ;
     RECT  97.259 68.49 98.015 70.632 ;
     RECT  97.187 25.83 98.051 28.314 ;
     RECT  97.763 35.82 98.051 36.144 ;
     RECT  97.763 37.368 98.051 37.764 ;
     RECT  97.151 41.994 98.051 43.128 ;
     RECT  97.187 58.5 98.051 58.716 ;
     RECT  98.015 69.876 98.051 70.632 ;
     RECT  98.051 25.83 98.087 28.278 ;
     RECT  97.763 45.306 98.087 47.988 ;
     RECT  98.051 70.614 98.087 70.632 ;
     RECT  97.146 78.75 98.087 78.804 ;
     RECT  97.146 31.194 98.123 32.634 ;
     RECT  98.087 78.75 98.159 78.768 ;
     RECT  98.123 31.536 98.339 32.634 ;
     RECT  98.087 47.628 98.339 47.988 ;
     RECT  97.583 60.39 98.339 60.678 ;
     RECT  97.151 73.926 98.339 73.944 ;
     RECT  98.339 31.536 98.411 32.562 ;
     RECT  97.511 50.364 98.519 50.922 ;
     RECT  98.519 50.4 98.555 50.922 ;
     RECT  98.555 50.436 98.563 50.922 ;
     RECT  98.087 25.83 98.591 28.044 ;
     RECT  97.511 49.32 98.591 49.374 ;
     RECT  97.146 53.406 98.591 53.928 ;
     RECT  97.259 64.71 98.591 65.844 ;
     RECT  97.187 76.05 98.591 77.148 ;
     RECT  97.223 80.136 98.591 80.154 ;
     RECT  97.511 23.562 98.627 23.58 ;
     RECT  98.591 26.676 98.627 28.044 ;
     RECT  97.763 29.106 98.627 29.394 ;
     RECT  98.411 31.536 98.627 32.094 ;
     RECT  98.051 37.746 98.627 37.764 ;
     RECT  97.187 39.366 98.627 39.384 ;
     RECT  98.051 42.534 98.627 43.128 ;
     RECT  98.087 45.306 98.627 46.719 ;
     RECT  98.339 47.628 98.627 47.646 ;
     RECT  98.563 50.436 98.627 50.958 ;
     RECT  98.591 53.91 98.627 53.928 ;
     RECT  97.475 55.494 98.627 56.862 ;
     RECT  98.051 58.5 98.627 58.518 ;
     RECT  97.187 62.55 98.627 63.954 ;
     RECT  98.591 65.484 98.627 65.844 ;
     RECT  98.015 68.49 98.627 69.084 ;
     RECT  97.187 74.97 98.627 74.988 ;
     RECT  98.591 76.05 98.627 76.068 ;
     RECT  98.591 76.86 98.627 77.148 ;
     RECT  98.627 28.026 98.663 28.044 ;
     RECT  98.627 29.106 98.663 29.124 ;
     RECT  98.627 32.004 98.663 32.022 ;
     RECT  98.627 43.11 98.663 43.128 ;
     RECT  98.591 49.356 98.663 49.374 ;
     RECT  98.627 50.796 98.663 50.814 ;
     RECT  98.627 55.494 98.663 55.512 ;
     RECT  98.627 65.484 98.663 65.538 ;
     RECT  98.627 77.13 98.663 77.148 ;
     RECT  98.627 45.54 98.699 46.719 ;
     RECT  98.627 62.55 98.699 63.108 ;
     RECT  98.699 45.846 98.735 46.719 ;
     RECT  98.663 65.52 98.735 65.538 ;
     RECT  98.699 62.631 98.771 62.802 ;
     RECT  98.051 36.126 99.167 36.144 ;
     RECT  98.591 25.83 99.203 25.848 ;
     RECT  98.735 45.846 99.203 46.602 ;
     RECT  98.627 26.676 99.239 27.198 ;
     RECT  99.139 36.936 99.239 36.954 ;
     RECT  99.203 45.846 99.239 45.864 ;
     RECT  98.627 56.304 99.239 56.322 ;
     RECT  98.339 60.426 99.239 60.678 ;
     RECT  98.591 64.71 99.239 64.728 ;
     RECT  99.175 42.3 99.275 42.318 ;
     RECT  97.151 44.388 99.275 44.406 ;
     RECT  99.211 20.826 99.311 20.844 ;
     RECT  99.239 26.676 99.311 26.856 ;
     RECT  99.211 30.042 99.311 30.06 ;
     RECT  99.175 34.434 99.311 34.452 ;
     RECT  99.211 41.346 99.311 41.364 ;
     RECT  99.211 53.1 99.311 53.118 ;
     RECT  99.175 54.756 99.311 54.774 ;
     RECT  99.239 60.426 99.311 60.444 ;
     RECT  99.211 61.434 99.311 61.452 ;
    LAYER M3 ;
     RECT  2.415 2.143 2.505 2.413 ;
     RECT  5.115 2.143 5.205 2.413 ;
     RECT  7.815 2.143 7.905 2.413 ;
     RECT  10.515 2.143 10.605 2.413 ;
     RECT  13.215 2.143 13.305 2.413 ;
     RECT  15.915 2.143 16.005 2.413 ;
     RECT  18.615 2.143 18.705 2.413 ;
     RECT  21.315 2.143 21.405 2.413 ;
     RECT  24.015 2.143 24.105 2.413 ;
     RECT  26.715 2.143 26.805 2.413 ;
     RECT  29.415 2.143 29.505 2.413 ;
     RECT  32.115 2.143 32.205 2.413 ;
     RECT  34.815 2.143 34.905 2.413 ;
     RECT  37.515 2.143 37.605 2.413 ;
     RECT  40.215 2.143 40.305 2.413 ;
     RECT  42.915 2.143 43.005 2.413 ;
     RECT  45.615 2.143 45.705 2.413 ;
     RECT  48.315 2.143 48.405 2.413 ;
     RECT  51.015 2.143 51.105 2.413 ;
     RECT  53.715 2.143 53.805 2.413 ;
     RECT  56.415 2.143 56.505 2.413 ;
     RECT  59.115 2.143 59.205 2.413 ;
     RECT  61.815 2.143 61.905 2.413 ;
     RECT  64.515 2.143 64.605 2.413 ;
     RECT  67.215 2.143 67.305 2.413 ;
     RECT  69.915 2.143 70.005 2.413 ;
     RECT  72.615 2.143 72.705 2.413 ;
     RECT  75.315 2.143 75.405 2.413 ;
     RECT  78.015 2.143 78.105 2.413 ;
     RECT  80.715 2.143 80.805 2.413 ;
     RECT  83.415 2.143 83.505 2.413 ;
     RECT  86.115 2.143 86.205 2.413 ;
     RECT  88.815 2.143 88.905 2.413 ;
     RECT  91.515 2.143 91.605 2.413 ;
     RECT  94.215 2.143 94.305 2.413 ;
     RECT  94.215 2.413 94.497 19.819 ;
     RECT  96.915 2.143 97.005 19.912 ;
     RECT  96.804 19.912 97.005 19.915 ;
     RECT  96.804 19.915 97.11 19.949 ;
     RECT  96.915 19.949 97.11 20.107 ;
     RECT  94.215 19.819 94.626 20.203 ;
     RECT  96.915 20.107 97.218 20.285 ;
     RECT  88.815 2.413 89.097 20.347 ;
     RECT  94.215 20.203 94.734 20.381 ;
     RECT  98.568 20.347 98.586 20.525 ;
     RECT  99.216 20.779 99.234 20.821 ;
     RECT  99.216 20.821 99.306 20.849 ;
     RECT  99.288 20.849 99.306 20.861 ;
     RECT  88.38 20.347 89.097 20.971 ;
     RECT  78.015 2.413 78.297 21.091 ;
     RECT  94.215 20.381 94.662 21.115 ;
     RECT  88.38 20.971 89.478 21.155 ;
     RECT  90.648 20.635 90.666 21.163 ;
     RECT  90.36 21.163 90.666 21.259 ;
     RECT  88.488 21.155 89.478 21.355 ;
     RECT  90.324 21.259 90.666 21.355 ;
     RECT  67.215 2.413 67.497 21.361 ;
     RECT  77.4 21.091 78.297 21.361 ;
     RECT  69.915 2.413 70.197 21.397 ;
     RECT  75.315 2.413 75.597 21.397 ;
     RECT  93.816 21.115 94.662 21.451 ;
     RECT  67.215 21.361 68.202 21.461 ;
     RECT  77.4 21.361 78.39 21.461 ;
     RECT  74.664 21.397 75.597 21.497 ;
     RECT  69.915 21.397 70.722 21.533 ;
     RECT  96.915 20.285 97.11 21.547 ;
     RECT  90.324 21.355 90.738 21.595 ;
     RECT  91.515 2.413 91.797 21.595 ;
     RECT  67.215 21.461 67.497 21.631 ;
     RECT  93.816 21.451 94.698 21.631 ;
     RECT  93.492 21.631 94.698 21.677 ;
     RECT  90.324 21.595 91.797 21.691 ;
     RECT  77.4 21.461 78.297 21.695 ;
     RECT  93.672 21.677 94.698 21.739 ;
     RECT  88.488 21.355 89.586 21.931 ;
     RECT  90.324 21.691 91.89 21.931 ;
     RECT  88.488 21.931 91.89 21.965 ;
     RECT  93.672 21.739 94.734 21.965 ;
     RECT  86.115 2.413 86.397 21.973 ;
     RECT  86.115 21.973 86.67 22.073 ;
     RECT  96.915 21.547 97.506 22.171 ;
     RECT  96.804 22.171 97.506 22.208 ;
     RECT  94.215 21.965 94.734 22.219 ;
     RECT  94.215 22.219 95.85 22.315 ;
     RECT  88.632 21.965 91.89 22.349 ;
     RECT  98.604 21.739 98.622 22.411 ;
     RECT  66.564 21.631 67.497 22.505 ;
     RECT  91.44 22.349 91.89 22.555 ;
     RECT  98.604 22.411 99.198 22.603 ;
     RECT  77.616 21.695 78.297 22.621 ;
     RECT  79.236 21.973 79.254 22.621 ;
     RECT  79.236 22.621 79.542 22.739 ;
     RECT  79.236 22.739 79.254 22.775 ;
     RECT  94.215 22.315 96.03 22.781 ;
     RECT  69.915 21.533 70.197 22.783 ;
     RECT  88.632 22.349 90.558 22.795 ;
     RECT  98.316 22.603 99.198 22.795 ;
     RECT  77.616 22.621 78.498 22.981 ;
     RECT  55.476 22.441 55.494 23.045 ;
     RECT  94.215 22.781 94.77 23.069 ;
     RECT  94.215 23.069 94.626 23.165 ;
     RECT  77.616 22.981 78.714 23.251 ;
     RECT  88.272 22.795 90.558 23.323 ;
     RECT  88.2 23.323 90.558 23.371 ;
     RECT  96.915 22.208 97.506 23.549 ;
     RECT  75.315 21.497 75.597 23.557 ;
     RECT  88.092 23.371 90.558 23.585 ;
     RECT  80.715 2.413 80.997 23.593 ;
     RECT  86.115 22.073 86.397 23.593 ;
     RECT  77.184 23.251 78.714 23.629 ;
     RECT  74.664 23.557 75.597 23.729 ;
     RECT  76.752 23.629 78.714 23.791 ;
     RECT  96.915 23.549 97.218 23.791 ;
     RECT  57.6 21.541 57.618 23.855 ;
     RECT  69.372 22.783 70.197 23.855 ;
     RECT  83.415 2.413 83.697 23.899 ;
     RECT  91.44 22.555 92.214 23.947 ;
     RECT  88.815 23.585 90.558 23.971 ;
     RECT  91.332 23.947 92.214 23.971 ;
     RECT  94.215 23.165 94.554 24.043 ;
     RECT  88.815 23.971 92.214 24.091 ;
     RECT  83.196 23.899 83.697 24.133 ;
     RECT  80.1 23.593 80.997 24.169 ;
     RECT  96.012 22.781 96.03 24.269 ;
     RECT  96.804 23.791 97.218 24.368 ;
     RECT  76.752 23.791 79.218 24.403 ;
     RECT  80.1 24.169 81.486 24.403 ;
     RECT  88.815 24.091 92.322 24.439 ;
     RECT  86.115 23.593 86.706 24.619 ;
     RECT  66.924 22.505 67.497 24.665 ;
     RECT  61.815 2.413 62.097 24.673 ;
     RECT  76.752 24.403 81.486 24.673 ;
     RECT  94.215 24.043 94.662 24.701 ;
     RECT  88.344 24.439 92.322 24.715 ;
     RECT  86.115 24.619 86.85 24.737 ;
     RECT  83.088 24.133 83.697 24.745 ;
     RECT  86.115 24.737 86.814 24.749 ;
     RECT  57.744 23.899 57.762 24.781 ;
     RECT  59.115 2.413 59.397 24.781 ;
     RECT  96.915 24.368 97.218 24.809 ;
     RECT  56.415 2.413 56.697 24.871 ;
     RECT  88.344 24.715 92.466 24.899 ;
     RECT  69.915 23.855 70.197 24.907 ;
     RECT  71.136 24.871 71.154 24.907 ;
     RECT  88.344 24.899 92.322 24.935 ;
     RECT  69.915 24.907 71.154 24.943 ;
     RECT  85.248 24.907 85.266 24.944 ;
     RECT  76.752 24.673 81.702 24.979 ;
     RECT  82.728 24.745 83.697 24.979 ;
     RECT  84.492 24.619 84.51 25.003 ;
     RECT  88.344 24.935 92.214 25.079 ;
     RECT  88.344 25.079 89.19 25.085 ;
     RECT  89.928 25.079 92.214 25.085 ;
     RECT  42.915 2.413 43.197 25.141 ;
     RECT  76.752 24.979 83.697 25.141 ;
     RECT  84.492 25.003 84.906 25.141 ;
     RECT  96.915 24.809 97.182 25.169 ;
     RECT  86.115 24.749 86.778 25.195 ;
     RECT  76.752 25.141 84.906 25.205 ;
     RECT  55.98 24.871 56.697 25.213 ;
     RECT  75.315 23.729 75.597 25.213 ;
     RECT  68.508 24.601 68.526 25.249 ;
     RECT  69.915 24.943 71.37 25.249 ;
     RECT  74.736 25.213 75.597 25.285 ;
     RECT  61.815 24.673 62.73 25.349 ;
     RECT  76.752 25.205 84.618 25.349 ;
     RECT  74.664 25.285 75.597 25.439 ;
     RECT  68.508 25.249 71.37 25.447 ;
     RECT  89.928 25.085 90.198 25.475 ;
     RECT  67.215 24.665 67.497 25.519 ;
     RECT  85.716 25.195 86.778 25.579 ;
     RECT  94.215 24.701 94.626 25.675 ;
     RECT  67.14 25.519 67.497 25.681 ;
     RECT  42.915 25.141 43.326 25.745 ;
     RECT  55.98 25.213 57.006 25.745 ;
     RECT  93.78 25.675 94.698 25.745 ;
     RECT  90.972 25.085 92.214 25.825 ;
     RECT  55.08 23.161 55.098 25.861 ;
     RECT  72.615 2.413 72.897 25.861 ;
     RECT  96.915 25.169 97.11 25.861 ;
     RECT  93.888 25.745 94.698 25.889 ;
     RECT  88.344 25.085 89.097 25.915 ;
     RECT  90.972 25.825 92.538 25.963 ;
     RECT  57.744 24.781 59.397 26.015 ;
     RECT  98.316 22.795 99.234 26.051 ;
     RECT  88.344 25.915 89.514 26.059 ;
     RECT  96.804 25.861 97.11 26.059 ;
     RECT  88.2 26.059 89.514 26.093 ;
     RECT  90.648 25.963 92.538 26.131 ;
     RECT  94.215 25.889 94.698 26.141 ;
     RECT  76.752 25.349 78.894 26.159 ;
     RECT  90.648 26.131 92.826 26.159 ;
     RECT  34.815 2.413 35.097 26.221 ;
     RECT  96.804 26.059 97.758 26.251 ;
     RECT  76.752 26.159 77.202 26.285 ;
     RECT  66.564 25.681 67.497 26.293 ;
     RECT  68.364 25.447 71.37 26.293 ;
     RECT  65.808 26.095 65.826 26.329 ;
     RECT  66.564 26.293 71.37 26.329 ;
     RECT  96.66 26.251 97.758 26.347 ;
     RECT  65.808 26.329 71.37 26.491 ;
     RECT  72.108 25.861 72.897 26.491 ;
     RECT  56.415 25.745 57.006 26.555 ;
     RECT  45.615 2.413 45.897 26.671 ;
     RECT  79.74 25.349 84.618 26.671 ;
     RECT  85.716 25.579 86.994 26.671 ;
     RECT  98.568 26.051 99.234 26.671 ;
     RECT  65.628 26.491 72.954 26.699 ;
     RECT  95.616 26.761 95.634 26.779 ;
     RECT  96.552 26.347 97.758 26.797 ;
     RECT  98.568 26.671 99.306 26.861 ;
     RECT  90.684 26.159 92.826 26.905 ;
     RECT  88.2 26.093 89.097 26.941 ;
     RECT  95.508 26.779 95.634 26.941 ;
     RECT  96.372 26.797 97.758 26.941 ;
     RECT  90.684 26.905 92.898 27.059 ;
     RECT  79.74 26.671 86.994 27.067 ;
     RECT  76.752 26.285 77.166 27.095 ;
     RECT  75.315 25.439 75.597 27.103 ;
     RECT  87.984 26.941 89.097 27.103 ;
     RECT  40.215 2.413 40.497 27.139 ;
     RECT  79.74 27.067 87.102 27.139 ;
     RECT  78.015 26.159 78.894 27.175 ;
     RECT  79.704 27.139 87.102 27.175 ;
     RECT  87.912 27.103 89.334 27.175 ;
     RECT  98.568 26.861 99.234 27.203 ;
     RECT  56.415 26.555 56.79 27.211 ;
     RECT  78.015 27.175 87.102 27.211 ;
     RECT  87.912 27.175 89.37 27.211 ;
     RECT  90.684 27.059 92.826 27.211 ;
     RECT  78.015 27.211 89.37 27.239 ;
     RECT  95.508 26.941 97.758 27.239 ;
     RECT  90.576 27.211 92.826 27.341 ;
     RECT  88.524 27.239 89.37 27.365 ;
     RECT  90.576 27.341 92.718 27.365 ;
     RECT  96.516 27.239 97.758 27.403 ;
     RECT  98.568 27.203 98.622 27.403 ;
     RECT  61.815 25.349 62.097 27.409 ;
     RECT  71.928 26.699 72.897 27.445 ;
     RECT  88.668 27.365 89.37 27.481 ;
     RECT  94.215 26.141 94.497 27.481 ;
     RECT  95.508 27.239 95.526 27.481 ;
     RECT  61.815 27.409 62.694 27.571 ;
     RECT  88.668 27.481 89.694 27.599 ;
     RECT  74.664 27.103 75.597 27.643 ;
     RECT  61.815 27.571 62.766 27.707 ;
     RECT  90.648 27.365 91.797 27.707 ;
     RECT  63.72 27.481 63.738 27.751 ;
     RECT  71.928 27.445 73.386 27.779 ;
     RECT  90.648 27.707 90.702 27.779 ;
     RECT  78.015 27.239 87.57 27.905 ;
     RECT  58.068 26.015 59.397 27.913 ;
     RECT  72.576 27.779 73.386 27.913 ;
     RECT  74.664 27.643 75.654 27.913 ;
     RECT  63.648 27.751 63.738 27.941 ;
     RECT  72.576 27.913 75.654 27.941 ;
     RECT  96.516 27.403 98.622 27.979 ;
     RECT  76.968 27.095 77.166 27.985 ;
     RECT  55.08 25.861 55.278 28.021 ;
     RECT  56.088 27.211 56.79 28.021 ;
     RECT  57.996 27.913 59.397 28.021 ;
     RECT  60.732 27.751 60.75 28.021 ;
     RECT  63.648 27.941 63.666 28.021 ;
     RECT  94.215 27.481 95.526 28.049 ;
     RECT  60.516 28.021 60.966 28.111 ;
     RECT  91.44 27.707 91.797 28.111 ;
     RECT  95.508 28.049 95.526 28.111 ;
     RECT  51.015 2.413 51.297 28.147 ;
     RECT  53.715 2.413 53.997 28.147 ;
     RECT  54.9 28.021 56.79 28.147 ;
     RECT  60.444 28.111 60.966 28.147 ;
     RECT  61.815 27.707 62.514 28.147 ;
     RECT  91.44 28.111 91.926 28.175 ;
     RECT  53.715 28.147 56.898 28.219 ;
     RECT  87.552 27.905 87.57 28.219 ;
     RECT  53.715 28.219 57.078 28.255 ;
     RECT  90.684 27.779 90.702 28.283 ;
     RECT  37.515 2.413 37.797 28.291 ;
     RECT  57.996 28.021 59.598 28.291 ;
     RECT  60.444 28.147 62.514 28.291 ;
     RECT  65.628 26.699 70.758 28.291 ;
     RECT  50.724 28.147 51.297 28.319 ;
     RECT  53.496 28.255 57.078 28.381 ;
     RECT  57.996 28.291 62.514 28.381 ;
     RECT  87.552 28.219 87.606 28.381 ;
     RECT  94.215 28.049 94.77 28.381 ;
     RECT  76.968 27.985 77.274 28.417 ;
     RECT  78.015 27.905 86.742 28.417 ;
     RECT  34.815 26.221 35.154 28.445 ;
     RECT  65.628 28.291 70.794 28.445 ;
     RECT  53.496 28.381 62.514 28.489 ;
     RECT  63.36 28.021 63.666 28.489 ;
     RECT  53.496 28.489 63.666 28.525 ;
     RECT  72.576 27.941 75.597 28.561 ;
     RECT  95.508 28.111 95.634 28.561 ;
     RECT  96.516 27.979 98.658 28.561 ;
     RECT  94.068 28.381 94.77 28.715 ;
     RECT  64.515 2.413 64.797 28.723 ;
     RECT  95.508 28.561 98.658 28.747 ;
     RECT  88.668 27.599 89.097 28.75 ;
     RECT  53.064 28.525 63.666 28.759 ;
     RECT  88.632 28.75 89.097 28.831 ;
     RECT  94.215 28.715 94.77 28.891 ;
     RECT  95.508 28.747 98.766 28.891 ;
     RECT  91.515 28.175 91.926 28.921 ;
     RECT  92.7 27.365 92.718 28.921 ;
     RECT  94.215 28.891 98.766 28.925 ;
     RECT  65.628 28.445 70.326 28.985 ;
     RECT  52.848 28.759 63.666 28.993 ;
     RECT  64.44 28.723 64.797 28.993 ;
     RECT  32.115 2.413 32.397 29.029 ;
     RECT  72.432 28.561 75.597 29.029 ;
     RECT  76.968 28.417 86.742 29.029 ;
     RECT  87.552 28.381 87.714 29.029 ;
     RECT  65.628 28.985 67.77 29.057 ;
     RECT  94.215 28.925 98.658 29.129 ;
     RECT  76.968 29.029 87.714 29.191 ;
     RECT  33.768 26.761 33.786 29.255 ;
     RECT  72.432 29.029 75.654 29.255 ;
     RECT  76.86 29.191 87.714 29.255 ;
     RECT  76.86 29.255 87.318 29.263 ;
     RECT  68.76 28.985 70.326 29.299 ;
     RECT  52.848 28.993 64.797 29.335 ;
     RECT  32.115 29.029 32.49 29.371 ;
     RECT  72.432 29.255 73.386 29.371 ;
     RECT  91.515 28.921 92.718 29.461 ;
     RECT  68.76 29.299 70.794 29.489 ;
     RECT  65.628 29.057 67.662 29.525 ;
     RECT  90.576 29.227 90.594 29.563 ;
     RECT  51.015 28.319 51.297 29.569 ;
     RECT  94.215 29.129 98.622 29.569 ;
     RECT  94.176 29.569 98.622 29.597 ;
     RECT  90.576 29.563 90.774 29.611 ;
     RECT  91.515 29.461 92.934 29.611 ;
     RECT  51.015 29.569 51.498 29.641 ;
     RECT  50.724 29.641 51.498 29.759 ;
     RECT  68.76 29.489 70.326 29.795 ;
     RECT  88.56 28.831 89.097 29.795 ;
     RECT  96.3 29.597 98.622 29.795 ;
     RECT  34.815 28.445 35.097 29.875 ;
     RECT  50.796 29.759 51.498 29.903 ;
     RECT  96.48 29.795 98.622 29.995 ;
     RECT  96.48 29.995 99.234 30.037 ;
     RECT  65.7 29.525 67.662 30.065 ;
     RECT  96.48 30.037 99.306 30.077 ;
     RECT  52.416 29.335 64.797 30.091 ;
     RECT  90.576 29.611 92.934 30.091 ;
     RECT  68.76 29.795 70.197 30.109 ;
     RECT  74.664 29.255 75.654 30.137 ;
     RECT  31.68 29.371 32.49 30.145 ;
     RECT  33.336 29.641 33.354 30.145 ;
     RECT  31.68 30.145 33.354 30.181 ;
     RECT  34.272 29.875 35.097 30.181 ;
     RECT  39.492 27.139 40.497 30.335 ;
     RECT  66.96 30.065 67.662 30.379 ;
     RECT  72.396 29.371 73.386 30.415 ;
     RECT  65.7 30.065 66.15 30.451 ;
     RECT  94.176 29.597 95.022 30.451 ;
     RECT  72.396 30.415 73.494 30.569 ;
     RECT  72.396 30.569 73.386 30.605 ;
     RECT  94.176 30.451 95.346 30.605 ;
     RECT  66.96 30.379 67.734 30.613 ;
     RECT  90.576 30.091 93.33 30.649 ;
     RECT  94.176 30.605 95.202 30.649 ;
     RECT  90.576 30.649 95.202 30.677 ;
     RECT  66.96 30.613 67.806 30.713 ;
     RECT  51.015 29.903 51.498 30.811 ;
     RECT  52.38 30.091 64.797 30.811 ;
     RECT  65.52 30.451 66.15 30.811 ;
     RECT  68.544 30.109 70.197 30.811 ;
     RECT  71.208 29.605 71.226 30.811 ;
     RECT  96.48 30.077 98.622 30.811 ;
     RECT  75.204 30.137 75.654 30.875 ;
     RECT  48.315 2.413 48.597 30.883 ;
     RECT  52.38 30.811 66.15 30.883 ;
     RECT  66.96 30.713 67.497 30.883 ;
     RECT  50.724 30.811 51.498 30.911 ;
     RECT  96.444 30.811 98.622 30.955 ;
     RECT  72.396 30.605 73.17 30.983 ;
     RECT  90.576 30.677 95.13 30.991 ;
     RECT  96.408 30.955 98.622 30.991 ;
     RECT  52.38 30.883 67.497 31.019 ;
     RECT  68.544 30.811 71.226 31.019 ;
     RECT  52.38 31.019 66.222 31.253 ;
     RECT  52.38 31.253 65.322 31.289 ;
     RECT  88.815 29.795 89.097 31.339 ;
     RECT  90.072 30.991 95.13 31.339 ;
     RECT  31.68 30.181 35.097 31.351 ;
     RECT  35.928 28.795 35.946 31.351 ;
     RECT  76.5 29.263 87.318 31.381 ;
     RECT  66.96 31.019 67.497 31.415 ;
     RECT  88.815 31.339 95.13 31.435 ;
     RECT  41.868 25.861 41.886 31.523 ;
     RECT  88.815 31.435 95.166 31.531 ;
     RECT  76.5 31.381 87.354 31.621 ;
     RECT  49.968 30.721 49.986 31.685 ;
     RECT  88.815 31.531 95.202 31.721 ;
     RECT  37.008 28.291 37.797 31.801 ;
     RECT  47.448 31.729 47.466 31.801 ;
     RECT  72.432 30.983 73.17 31.801 ;
     RECT  75.315 30.875 75.654 31.801 ;
     RECT  96.156 30.991 98.622 31.819 ;
     RECT  76.5 31.621 87.858 31.891 ;
     RECT  38.664 31.801 38.682 31.919 ;
     RECT  46.8 31.801 47.466 31.919 ;
     RECT  66.06 31.253 66.222 31.919 ;
     RECT  72.432 31.801 73.278 31.919 ;
     RECT  51.015 30.911 51.498 31.955 ;
     RECT  66.06 31.919 66.078 31.955 ;
     RECT  72.432 31.919 73.17 31.955 ;
     RECT  76.392 31.891 87.858 31.999 ;
     RECT  88.815 31.721 93.474 31.999 ;
     RECT  96.156 31.819 98.658 32.027 ;
     RECT  74.376 31.801 75.654 32.035 ;
     RECT  76.392 31.999 93.474 32.035 ;
     RECT  94.215 31.721 95.202 32.071 ;
     RECT  74.376 32.035 93.474 32.099 ;
     RECT  96.156 32.027 98.622 32.099 ;
     RECT  52.38 31.289 65.25 32.161 ;
     RECT  94.215 32.071 95.31 32.161 ;
     RECT  48.315 30.883 48.798 32.225 ;
     RECT  72.432 31.955 72.897 32.225 ;
     RECT  52.38 32.161 65.43 32.269 ;
     RECT  52.092 32.269 65.43 32.459 ;
     RECT  94.215 32.161 95.418 32.491 ;
     RECT  96.156 32.099 98.406 32.491 ;
     RECT  94.215 32.491 98.406 32.567 ;
     RECT  76.5 32.099 93.474 32.765 ;
     RECT  94.215 32.567 98.37 32.765 ;
     RECT  76.788 32.765 93.474 32.779 ;
     RECT  94.215 32.765 95.418 32.779 ;
     RECT  74.376 32.099 75.762 32.909 ;
     RECT  66.996 31.415 67.497 32.971 ;
     RECT  38.736 32.971 38.754 33.007 ;
     RECT  76.788 32.779 95.418 33.053 ;
     RECT  99.216 32.971 99.234 33.067 ;
     RECT  39.708 30.335 40.497 33.241 ;
     RECT  50.184 31.801 50.202 33.277 ;
     RECT  51.015 31.955 51.297 33.277 ;
     RECT  68.544 31.019 70.197 33.385 ;
     RECT  36.828 31.801 37.797 33.421 ;
     RECT  38.628 33.007 38.754 33.421 ;
     RECT  52.092 32.459 64.797 33.421 ;
     RECT  36.828 33.421 38.754 33.511 ;
     RECT  39.708 33.241 41.022 33.511 ;
     RECT  75.315 32.909 75.762 33.511 ;
     RECT  76.788 33.053 80.997 33.511 ;
     RECT  81.792 33.053 95.418 33.511 ;
     RECT  96.156 32.765 98.37 33.511 ;
     RECT  50.184 33.277 51.297 33.539 ;
     RECT  66.996 32.971 67.554 33.575 ;
     RECT  74.376 32.909 74.394 33.691 ;
     RECT  52.092 33.421 65.538 33.881 ;
     RECT  72.576 32.225 72.897 33.883 ;
     RECT  45.108 26.671 45.897 33.961 ;
     RECT  72 33.883 72.897 33.961 ;
     RECT  74.16 33.691 74.394 33.961 ;
     RECT  75.315 33.511 80.997 33.961 ;
     RECT  81.792 33.511 98.37 33.961 ;
     RECT  68.544 33.385 70.362 34.051 ;
     RECT  67.068 33.575 67.554 34.115 ;
     RECT  72 33.961 80.997 34.115 ;
     RECT  36.828 33.511 41.022 34.151 ;
     RECT  48.315 32.225 48.597 34.195 ;
     RECT  72 34.115 73.53 34.205 ;
     RECT  58.5 33.881 65.538 34.231 ;
     RECT  74.376 34.115 80.997 34.231 ;
     RECT  81.72 33.961 98.37 34.231 ;
     RECT  71.208 31.019 71.226 34.393 ;
     RECT  50.184 33.539 50.202 34.429 ;
     RECT  51.015 33.539 51.297 34.429 ;
     RECT  99.108 33.067 99.234 34.429 ;
     RECT  48.315 34.195 49.086 34.457 ;
     RECT  99.108 34.429 99.306 34.493 ;
     RECT  31.68 31.351 35.946 34.501 ;
     RECT  36.828 34.151 39.258 34.501 ;
     RECT  50.184 34.429 51.297 34.501 ;
     RECT  52.092 33.881 57.726 34.501 ;
     RECT  68.544 34.051 70.47 34.501 ;
     RECT  71.208 34.393 71.298 34.501 ;
     RECT  58.5 34.231 65.646 34.529 ;
     RECT  68.544 34.501 71.298 34.529 ;
     RECT  50.184 34.501 57.726 34.619 ;
     RECT  74.376 34.231 98.37 34.763 ;
     RECT  50.976 34.619 57.726 34.861 ;
     RECT  58.5 34.529 65.322 34.861 ;
     RECT  67.215 34.115 67.554 34.861 ;
     RECT  66.744 34.861 67.554 34.933 ;
     RECT  50.184 34.619 50.202 34.969 ;
     RECT  66.672 34.933 67.554 34.969 ;
     RECT  45.108 33.961 46.17 35.041 ;
     RECT  47.052 31.919 47.466 35.041 ;
     RECT  45.108 35.041 47.466 35.159 ;
     RECT  72.576 34.205 73.53 35.167 ;
     RECT  74.376 34.763 97.29 35.195 ;
     RECT  72.576 35.167 73.638 35.213 ;
     RECT  50.976 34.861 65.322 35.275 ;
     RECT  72.576 35.213 73.098 35.339 ;
     RECT  50.976 35.275 65.538 35.419 ;
     RECT  74.376 35.195 95.238 35.473 ;
     RECT  49.608 34.969 50.202 35.545 ;
     RECT  50.976 35.419 65.754 35.545 ;
     RECT  74.34 35.473 95.238 35.573 ;
     RECT  31.68 34.501 39.258 35.581 ;
     RECT  39.996 34.151 41.022 35.581 ;
     RECT  47.052 35.159 47.466 35.581 ;
     RECT  48.315 34.457 48.762 35.581 ;
     RECT  49.608 35.545 65.754 35.581 ;
     RECT  66.6 34.969 67.554 35.581 ;
     RECT  68.544 34.529 70.938 35.581 ;
     RECT  72.576 35.339 73.026 35.609 ;
     RECT  98.028 34.763 98.37 35.659 ;
     RECT  99.108 34.493 99.234 35.659 ;
     RECT  42.915 25.745 43.197 35.671 ;
     RECT  74.34 35.573 74.466 35.735 ;
     RECT  49.608 35.581 67.554 35.807 ;
     RECT  75.315 35.573 95.238 35.837 ;
     RECT  98.028 35.659 99.234 35.837 ;
     RECT  47.052 35.581 48.762 35.851 ;
     RECT  49.608 35.807 49.95 35.851 ;
     RECT  96.084 35.195 97.29 35.947 ;
     RECT  98.028 35.837 98.37 35.947 ;
     RECT  31.68 35.581 41.022 36.005 ;
     RECT  74.34 35.735 74.394 36.013 ;
     RECT  45.108 35.159 46.17 36.085 ;
     RECT  47.052 35.851 49.95 36.085 ;
     RECT  31.68 36.005 39.366 36.121 ;
     RECT  40.104 36.005 41.022 36.121 ;
     RECT  68.4 35.581 70.938 36.121 ;
     RECT  42.915 35.671 43.794 36.211 ;
     RECT  73.836 36.013 74.394 36.239 ;
     RECT  31.608 36.121 39.366 36.275 ;
     RECT  40.104 36.121 41.31 36.275 ;
     RECT  50.688 35.807 67.554 36.275 ;
     RECT  95.328 36.121 95.346 36.355 ;
     RECT  96.084 35.947 98.37 36.355 ;
     RECT  71.82 35.851 71.838 36.391 ;
     RECT  71.784 36.391 71.838 36.481 ;
     RECT  72.576 35.609 72.99 36.481 ;
     RECT  71.784 36.481 72.99 36.523 ;
     RECT  45.108 36.085 49.95 36.553 ;
     RECT  50.688 36.275 52.11 36.553 ;
     RECT  52.848 36.275 67.554 36.553 ;
     RECT  75.315 35.837 94.59 36.571 ;
     RECT  95.328 36.355 98.37 36.571 ;
     RECT  33.624 36.275 39.366 36.581 ;
     RECT  40.104 36.275 40.626 36.581 ;
     RECT  74.376 36.239 74.394 36.625 ;
     RECT  75.315 36.571 98.37 36.625 ;
     RECT  29.415 2.413 29.697 36.661 ;
     RECT  74.376 36.625 98.37 36.667 ;
     RECT  99.108 35.837 99.234 36.667 ;
     RECT  30.6 36.625 30.618 36.751 ;
     RECT  52.848 36.553 67.59 36.815 ;
     RECT  29.124 36.661 29.697 36.823 ;
     RECT  30.6 36.751 30.798 36.895 ;
     RECT  31.608 36.275 32.886 36.895 ;
     RECT  29.124 36.823 29.754 36.931 ;
     RECT  30.6 36.895 32.886 36.931 ;
     RECT  74.376 36.667 99.234 36.959 ;
     RECT  74.376 36.959 99.162 36.989 ;
     RECT  29.124 36.931 32.886 37.021 ;
     RECT  33.624 36.581 39.006 37.021 ;
     RECT  71.784 36.523 73.494 37.021 ;
     RECT  74.376 36.989 98.766 37.021 ;
     RECT  67.176 36.815 67.59 37.129 ;
     RECT  68.364 36.121 70.938 37.129 ;
     RECT  40.104 36.581 40.497 37.201 ;
     RECT  45.108 36.553 52.11 37.363 ;
     RECT  52.848 36.815 66.438 37.363 ;
     RECT  71.784 37.021 98.766 37.391 ;
     RECT  29.124 37.021 39.006 37.471 ;
     RECT  39.744 37.201 40.497 37.471 ;
     RECT  67.176 37.129 70.938 37.471 ;
     RECT  71.784 37.391 97.758 37.471 ;
     RECT  67.176 37.471 97.758 37.625 ;
     RECT  98.604 37.391 98.766 37.769 ;
     RECT  98.64 37.769 98.766 37.901 ;
     RECT  29.124 37.471 40.497 37.903 ;
     RECT  45.108 37.363 66.438 37.903 ;
     RECT  67.176 37.625 70.938 37.903 ;
     RECT  98.748 37.901 98.766 37.963 ;
     RECT  98.748 37.963 98.874 37.997 ;
     RECT  98.856 37.997 98.874 38.141 ;
     RECT  45.108 37.903 70.938 38.165 ;
     RECT  42.915 36.211 43.83 38.281 ;
     RECT  72.072 37.625 97.758 38.399 ;
     RECT  41.364 38.371 41.382 38.407 ;
     RECT  72.072 38.399 79.758 38.515 ;
     RECT  29.124 37.903 40.626 38.551 ;
     RECT  41.364 38.407 41.418 38.551 ;
     RECT  45.108 38.165 70.866 38.551 ;
     RECT  29.124 38.551 41.418 38.821 ;
     RECT  42.732 38.281 43.83 38.821 ;
     RECT  44.712 38.551 70.866 38.821 ;
     RECT  42.732 38.821 70.866 38.947 ;
     RECT  71.784 38.515 79.758 38.947 ;
     RECT  42.732 38.947 79.758 39.019 ;
     RECT  29.088 38.821 41.418 39.091 ;
     RECT  42.696 39.019 79.758 39.091 ;
     RECT  29.088 39.091 79.758 39.325 ;
     RECT  80.496 38.399 97.758 39.325 ;
     RECT  29.088 39.325 97.758 39.595 ;
     RECT  98.604 39.211 98.622 39.595 ;
     RECT  29.088 39.595 98.622 39.631 ;
     RECT  28.836 39.631 98.622 39.677 ;
     RECT  29.088 39.677 98.622 39.785 ;
     RECT  29.304 39.785 98.622 40.163 ;
     RECT  29.304 40.163 92.034 40.603 ;
     RECT  92.844 40.163 98.622 40.651 ;
     RECT  28.908 40.603 92.034 40.703 ;
     RECT  92.844 40.651 99.198 40.703 ;
     RECT  92.844 40.703 95.022 40.739 ;
     RECT  92.844 40.739 93.294 40.865 ;
     RECT  96.048 40.703 97.218 40.973 ;
     RECT  96.048 40.973 97.146 41.135 ;
     RECT  94.032 40.739 94.77 41.207 ;
     RECT  98.028 40.703 99.198 41.323 ;
     RECT  98.028 41.323 99.234 41.341 ;
     RECT  92.916 40.865 93.294 41.405 ;
     RECT  98.028 41.341 99.306 41.405 ;
     RECT  28.908 40.703 67.497 41.485 ;
     RECT  68.436 40.703 92.034 41.485 ;
     RECT  94.068 41.207 94.77 41.521 ;
     RECT  94.068 41.521 95.274 41.791 ;
     RECT  96.048 41.135 97.11 41.791 ;
     RECT  98.028 41.405 99.198 42.017 ;
     RECT  28.908 41.485 92.034 42.061 ;
     RECT  92.916 41.405 93.186 42.061 ;
     RECT  98.316 42.017 99.198 42.187 ;
     RECT  98.316 42.187 99.234 42.295 ;
     RECT  28.908 42.061 93.186 42.331 ;
     RECT  94.068 41.791 97.11 42.331 ;
     RECT  28.908 42.331 97.11 43.025 ;
     RECT  92.592 43.025 97.11 43.051 ;
     RECT  98.316 42.295 99.27 43.051 ;
     RECT  28.908 43.025 91.854 43.637 ;
     RECT  92.592 43.051 99.27 44.411 ;
     RECT  92.592 44.411 99.234 44.447 ;
     RECT  93.708 44.447 99.234 44.753 ;
     RECT  92.592 44.447 92.898 45.019 ;
     RECT  95.472 44.753 99.234 45.293 ;
     RECT  96.084 45.293 99.234 45.491 ;
     RECT  92.52 45.019 92.898 45.499 ;
     RECT  94.176 44.753 94.662 45.499 ;
     RECT  28.908 43.637 91.797 45.805 ;
     RECT  92.52 45.499 94.662 45.805 ;
     RECT  28.908 45.805 94.662 45.833 ;
     RECT  94.215 45.833 94.662 45.841 ;
     RECT  96.156 45.491 99.234 45.869 ;
     RECT  28.908 45.833 93.474 46.103 ;
     RECT  94.215 45.841 94.734 46.111 ;
     RECT  28.908 46.103 91.854 46.139 ;
     RECT  92.664 46.103 93.474 46.265 ;
     RECT  96.156 45.869 99.198 46.373 ;
     RECT  28.908 46.139 91.797 46.471 ;
     RECT  96.156 46.373 96.174 46.535 ;
     RECT  96.915 46.373 99.198 46.607 ;
     RECT  96.915 46.607 98.73 46.724 ;
     RECT  28.764 46.471 91.797 46.741 ;
     RECT  94.215 46.111 95.202 46.913 ;
     RECT  28.692 46.741 91.797 47.047 ;
     RECT  28.512 47.047 91.797 47.119 ;
     RECT  28.44 47.119 91.797 47.191 ;
     RECT  28.44 47.191 91.926 47.323 ;
     RECT  92.772 46.265 93.474 47.323 ;
     RECT  28.44 47.323 93.474 47.587 ;
     RECT  28.404 47.587 93.474 47.615 ;
     RECT  96.915 46.724 98.622 47.651 ;
     RECT  96.915 47.651 98.334 47.993 ;
     RECT  96.915 47.993 97.758 48.029 ;
     RECT  96.915 48.029 97.074 48.155 ;
     RECT  28.404 47.615 93.006 48.235 ;
     RECT  96.915 48.155 97.005 48.271 ;
     RECT  96.876 48.271 97.005 48.331 ;
     RECT  98.604 48.523 98.622 48.619 ;
     RECT  28.224 48.235 93.006 48.667 ;
     RECT  94.215 46.913 94.497 48.667 ;
     RECT  96.48 48.331 97.005 48.667 ;
     RECT  98.604 48.619 98.694 48.715 ;
     RECT  96.048 48.667 97.005 48.811 ;
     RECT  98.604 48.715 98.802 48.893 ;
     RECT  28.224 48.667 94.497 48.901 ;
     RECT  28.08 48.901 94.497 48.941 ;
     RECT  98.604 48.893 98.73 49.003 ;
     RECT  95.868 48.811 97.005 49.171 ;
     RECT  95.868 49.171 97.11 49.277 ;
     RECT  28.224 48.941 94.497 49.339 ;
     RECT  98.568 49.003 98.73 49.867 ;
     RECT  98.532 49.867 98.73 49.963 ;
     RECT  95.868 49.277 97.005 50.045 ;
     RECT  96.804 50.045 97.005 50.089 ;
     RECT  96.804 50.089 97.506 50.141 ;
     RECT  98.496 49.963 98.73 50.141 ;
     RECT  95.616 50.053 95.634 50.153 ;
     RECT  28.224 49.339 94.662 50.431 ;
     RECT  28.224 50.431 94.77 50.693 ;
     RECT  28.296 50.693 94.77 50.729 ;
     RECT  98.496 50.141 98.658 50.791 ;
     RECT  98.46 50.791 98.658 50.819 ;
     RECT  96.804 50.141 97.434 50.923 ;
     RECT  98.46 50.819 98.622 50.927 ;
     RECT  98.496 50.927 98.622 50.963 ;
     RECT  94.068 50.729 94.77 50.971 ;
     RECT  94.068 50.971 95.202 50.999 ;
     RECT  92.592 50.729 93.114 51.233 ;
     RECT  96.804 50.923 97.47 51.241 ;
     RECT  98.496 50.963 98.586 51.437 ;
     RECT  92.592 51.233 92.898 51.539 ;
     RECT  96.444 51.241 97.47 51.665 ;
     RECT  28.296 50.729 91.797 51.869 ;
     RECT  92.592 51.539 92.682 51.899 ;
     RECT  28.584 51.869 91.797 51.979 ;
     RECT  92.592 51.899 92.61 51.979 ;
     RECT  28.584 51.979 92.61 52.043 ;
     RECT  94.215 50.999 95.202 52.249 ;
     RECT  94.215 52.249 95.274 52.411 ;
     RECT  96.516 51.665 97.47 52.411 ;
     RECT  94.176 52.411 95.274 52.447 ;
     RECT  96.336 52.411 97.47 52.447 ;
     RECT  28.872 52.043 92.61 52.475 ;
     RECT  28.872 52.475 90.054 52.511 ;
     RECT  28.872 52.511 89.802 52.583 ;
     RECT  91.116 52.475 92.61 52.583 ;
     RECT  94.176 52.447 97.47 52.583 ;
     RECT  91.515 52.583 92.61 52.709 ;
     RECT  28.944 52.583 89.802 52.817 ;
     RECT  94.176 52.583 97.11 53.035 ;
     RECT  98.532 51.437 98.586 53.083 ;
     RECT  98.532 53.083 99.306 53.123 ;
     RECT  98.532 53.123 99.234 53.165 ;
     RECT  2.415 2.413 2.697 53.257 ;
     RECT  3.42 53.131 3.438 53.257 ;
     RECT  2.415 53.257 4.086 53.309 ;
     RECT  93.24 53.035 97.11 53.323 ;
     RECT  5.115 2.413 5.397 53.329 ;
     RECT  4.968 53.329 5.397 53.365 ;
     RECT  3.888 53.309 4.086 53.401 ;
     RECT  4.896 53.365 5.397 53.401 ;
     RECT  98.532 53.165 98.622 53.429 ;
     RECT  2.415 53.309 2.826 53.549 ;
     RECT  21.315 2.413 21.597 53.563 ;
     RECT  28.944 52.817 89.097 53.563 ;
     RECT  3.888 53.401 5.397 53.591 ;
     RECT  4.788 53.591 5.397 53.659 ;
     RECT  3.888 53.591 4.014 53.663 ;
     RECT  14.832 53.563 14.85 53.693 ;
     RECT  21.315 53.563 21.69 53.693 ;
     RECT  22.824 53.563 22.842 53.693 ;
     RECT  2.415 53.549 2.79 53.699 ;
     RECT  4.788 53.659 5.49 53.699 ;
     RECT  28.26 53.563 89.154 53.761 ;
     RECT  28.188 53.761 89.154 53.797 ;
     RECT  4.788 53.699 5.397 53.825 ;
     RECT  98.568 53.429 98.622 53.825 ;
     RECT  28.008 53.797 89.154 53.833 ;
     RECT  27.936 53.833 89.154 53.869 ;
     RECT  93.24 53.323 97.218 53.869 ;
     RECT  2.415 53.699 2.718 53.896 ;
     RECT  27.936 53.869 90.09 53.933 ;
     RECT  98.604 53.825 98.622 53.933 ;
     RECT  25.164 53.869 25.182 53.941 ;
     RECT  3.888 53.663 3.906 53.969 ;
     RECT  4.86 53.825 5.397 53.969 ;
     RECT  25.092 53.941 25.182 54.059 ;
     RECT  2.304 53.896 2.718 54.095 ;
     RECT  93.132 53.869 97.218 54.095 ;
     RECT  2.415 54.095 2.718 54.125 ;
     RECT  96.516 54.095 97.218 54.125 ;
     RECT  28.188 53.933 90.09 54.131 ;
     RECT  0.108 53.611 0.126 54.329 ;
     RECT  91.515 52.709 92.322 54.437 ;
     RECT  93.24 54.095 95.742 54.509 ;
     RECT  28.548 54.131 90.09 54.679 ;
     RECT  91.515 54.437 91.962 54.679 ;
     RECT  28.548 54.679 91.962 54.707 ;
     RECT  99.216 54.571 99.234 54.715 ;
     RECT  99.216 54.715 99.306 54.751 ;
     RECT  99.18 54.751 99.306 54.779 ;
     RECT  24.015 2.413 24.297 54.841 ;
     RECT  28.548 54.707 91.89 54.877 ;
     RECT  24.012 54.841 24.297 54.893 ;
     RECT  25.56 54.571 25.578 54.941 ;
     RECT  28.008 54.877 91.89 54.941 ;
     RECT  28.584 54.941 91.89 55.049 ;
     RECT  96.516 54.125 97.11 55.085 ;
     RECT  99.18 54.779 99.234 55.147 ;
     RECT  96.516 55.085 97.005 55.175 ;
     RECT  93.24 54.509 95.706 55.181 ;
     RECT  93.996 55.181 95.706 55.255 ;
     RECT  93.996 55.255 95.778 55.319 ;
     RECT  92.88 55.381 92.898 55.481 ;
     RECT  95.688 55.319 95.778 55.589 ;
     RECT  28.944 55.049 91.89 55.759 ;
     RECT  28.944 55.759 92.106 55.921 ;
     RECT  96.915 55.175 97.005 56.011 ;
     RECT  93.996 55.319 94.842 56.065 ;
     RECT  98.532 55.147 99.234 56.203 ;
     RECT  93.564 56.065 94.842 56.263 ;
     RECT  28.944 55.921 92.358 56.299 ;
     RECT  98.316 56.203 99.234 56.327 ;
     RECT  93.384 56.263 94.842 56.335 ;
     RECT  28.944 56.299 92.394 56.347 ;
     RECT  93.276 56.335 94.842 56.347 ;
     RECT  28.944 56.347 94.842 56.443 ;
     RECT  96.3 56.011 97.005 56.587 ;
     RECT  28.944 56.443 95.562 56.641 ;
     RECT  96.3 56.587 97.074 56.641 ;
     RECT  28.944 56.641 97.074 56.683 ;
     RECT  98.316 56.327 98.622 57.163 ;
     RECT  28.944 56.683 97.47 57.499 ;
     RECT  98.316 57.163 99.234 57.547 ;
     RECT  24.015 54.893 24.297 58.225 ;
     RECT  24.015 58.225 24.75 58.459 ;
     RECT  28.944 57.499 97.506 58.507 ;
     RECT  98.316 57.547 99.306 58.507 ;
     RECT  28.944 58.507 99.306 58.523 ;
     RECT  24.015 58.459 25.11 58.685 ;
     RECT  28.944 58.523 98.334 58.721 ;
     RECT  26.715 2.413 26.997 59.341 ;
     RECT  27.864 57.721 27.882 59.341 ;
     RECT  98.316 58.721 98.334 59.467 ;
     RECT  99.216 58.523 99.306 59.467 ;
     RECT  26.715 59.341 27.882 59.755 ;
     RECT  28.944 58.721 97.506 59.837 ;
     RECT  24.015 58.685 25.074 59.881 ;
     RECT  28.944 59.837 97.182 59.909 ;
     RECT  28.944 59.909 97.146 60.007 ;
     RECT  28.908 60.007 97.146 60.151 ;
     RECT  26.715 59.755 27.99 60.277 ;
     RECT  28.728 60.151 97.146 60.277 ;
     RECT  24.015 59.881 25.326 60.379 ;
     RECT  26.715 60.277 97.146 60.379 ;
     RECT  98.316 59.467 99.306 60.413 ;
     RECT  98.424 60.413 99.306 60.449 ;
     RECT  22.356 60.421 22.914 60.781 ;
     RECT  22.356 60.781 23.094 60.853 ;
     RECT  24.015 60.379 97.146 60.881 ;
     RECT  98.424 60.449 99.234 60.941 ;
     RECT  22.356 60.853 23.166 60.961 ;
     RECT  24.015 60.881 27.99 60.961 ;
     RECT  21.315 53.693 21.597 61.051 ;
     RECT  22.356 60.961 27.99 61.051 ;
     RECT  28.728 60.881 97.146 61.099 ;
     RECT  98.604 60.941 99.234 61.181 ;
     RECT  28.728 61.099 97.578 61.187 ;
     RECT  98.64 61.181 99.234 61.429 ;
     RECT  98.64 61.429 99.306 61.469 ;
     RECT  21.315 61.051 27.99 61.735 ;
     RECT  28.728 61.187 97.11 61.735 ;
     RECT  98.64 61.469 98.766 62.251 ;
     RECT  98.604 62.251 98.766 62.635 ;
     RECT  21.315 61.735 97.11 62.941 ;
     RECT  21.315 62.941 97.146 63.211 ;
     RECT  98.604 62.635 99.234 63.307 ;
     RECT  98.064 63.307 99.234 63.787 ;
     RECT  21.315 63.211 97.218 63.815 ;
     RECT  21.315 63.815 95.094 63.821 ;
     RECT  21.315 63.821 94.878 64.157 ;
     RECT  95.94 63.815 97.218 64.157 ;
     RECT  21.315 64.157 94.626 64.165 ;
     RECT  95.976 64.157 97.218 64.355 ;
     RECT  21.204 64.165 94.626 64.733 ;
     RECT  98.028 63.787 99.234 64.733 ;
     RECT  96.048 64.355 97.218 64.895 ;
     RECT  98.028 64.733 98.73 65.165 ;
     RECT  21.315 64.733 94.626 65.543 ;
     RECT  98.064 65.165 98.73 65.543 ;
     RECT  98.064 65.543 98.622 65.813 ;
     RECT  98.604 65.813 98.622 65.849 ;
     RECT  96.192 64.895 97.218 66.091 ;
     RECT  95.724 66.091 97.254 66.317 ;
     RECT  95.364 66.361 95.382 66.515 ;
     RECT  21.315 65.543 94.497 66.523 ;
     RECT  21.315 66.523 94.878 66.659 ;
     RECT  21.315 66.659 94.734 67.147 ;
     RECT  21.276 67.147 94.734 67.441 ;
     RECT  21.276 67.441 95.238 67.675 ;
     RECT  96.192 66.317 97.254 67.675 ;
     RECT  98.568 67.531 98.586 67.709 ;
     RECT  21.276 67.675 97.254 67.937 ;
     RECT  21.276 67.937 97.218 68.279 ;
     RECT  98.496 68.011 98.514 68.395 ;
     RECT  21.276 68.279 97.182 68.405 ;
     RECT  98.028 68.395 98.514 68.443 ;
     RECT  98.028 68.443 98.55 68.485 ;
     RECT  98.028 68.485 98.622 68.683 ;
     RECT  97.992 68.683 98.622 69.355 ;
     RECT  97.992 69.355 98.73 69.533 ;
     RECT  21.315 68.405 97.182 69.547 ;
     RECT  97.992 69.533 98.082 69.547 ;
     RECT  21.315 69.547 98.082 70.411 ;
     RECT  21.315 70.411 98.334 71.275 ;
     RECT  21.315 71.275 98.514 71.851 ;
     RECT  21.315 71.851 98.622 71.947 ;
     RECT  21.315 71.947 98.73 72.043 ;
     RECT  21.315 72.043 98.838 72.139 ;
     RECT  21.315 72.139 98.946 72.317 ;
     RECT  21.315 72.317 98.73 72.653 ;
     RECT  21.315 72.653 98.694 73.517 ;
     RECT  21.315 73.517 98.622 73.757 ;
     RECT  21.315 73.757 98.334 73.949 ;
     RECT  98.604 74.731 98.622 74.993 ;
     RECT  98.496 75.691 98.514 75.821 ;
     RECT  21.315 73.949 97.758 76.343 ;
     RECT  21.315 76.343 97.218 76.505 ;
     RECT  96.408 76.505 97.218 76.541 ;
     RECT  98.568 75.883 98.622 76.555 ;
     RECT  98.028 76.555 98.622 76.651 ;
     RECT  98.028 76.651 98.658 76.919 ;
     RECT  98.64 76.919 98.658 77.153 ;
     RECT  96.444 76.541 97.218 77.431 ;
     RECT  21.315 76.505 95.418 77.611 ;
     RECT  96.372 77.431 97.218 77.611 ;
     RECT  98.568 77.803 98.586 78.571 ;
     RECT  98.064 78.571 98.586 78.763 ;
     RECT  98.064 78.763 98.622 78.809 ;
     RECT  98.136 78.809 98.622 78.811 ;
     RECT  98.136 78.811 98.802 78.845 ;
     RECT  98.496 78.845 98.802 78.989 ;
     RECT  98.496 78.989 98.514 79.469 ;
     RECT  98.568 79.915 98.586 80.159 ;
     RECT  21.315 77.611 97.218 80.285 ;
     RECT  21.315 80.285 97.11 80.525 ;
     RECT  98.604 80.395 98.622 80.573 ;
     RECT  21.315 80.525 97.005 81.905 ;
     RECT  21.315 81.905 95.274 82.211 ;
     RECT  96.264 81.905 97.005 82.831 ;
     RECT  21.315 82.211 95.166 83.191 ;
     RECT  96.228 82.831 97.005 83.191 ;
     RECT  21.315 83.191 97.005 85.517 ;
     RECT  46.872 85.517 97.005 85.757 ;
     RECT  46.872 85.757 95.706 85.955 ;
     RECT  93.492 85.955 95.706 86.225 ;
     RECT  93.492 86.225 95.202 86.495 ;
     RECT  46.872 85.955 92.25 86.773 ;
     RECT  46.872 86.773 92.718 86.779 ;
     RECT  46.764 86.779 92.718 86.809 ;
     RECT  93.492 86.495 94.497 86.809 ;
     RECT  46.764 86.809 94.497 86.909 ;
     RECT  96.588 85.757 97.005 87.341 ;
     RECT  46.872 86.909 94.497 88.223 ;
     RECT  46.872 88.223 93.15 88.727 ;
     RECT  46.872 88.727 92.97 88.889 ;
     RECT  92.736 88.889 92.97 88.925 ;
     RECT  46.872 88.889 91.797 89.465 ;
     RECT  46.872 89.465 87.894 89.501 ;
     RECT  47.808 89.501 87.75 89.537 ;
     RECT  46.872 89.501 46.89 90.355 ;
     RECT  21.315 85.517 45.897 90.391 ;
     RECT  46.62 90.355 47.07 90.391 ;
     RECT  21.315 90.391 47.07 90.481 ;
     RECT  47.808 89.537 87.714 90.481 ;
     RECT  88.815 89.465 91.797 92.237 ;
     RECT  88.815 92.237 90.522 93.857 ;
     RECT  88.815 93.857 90.234 94.397 ;
     RECT  21.315 90.481 87.714 94.631 ;
     RECT  21.315 94.631 85.014 94.703 ;
     RECT  21.315 94.703 82.134 94.739 ;
     RECT  21.315 94.739 81.738 94.937 ;
     RECT  21.315 94.937 81.666 95.009 ;
     RECT  21.315 95.009 79.794 95.099 ;
     RECT  21.315 95.099 21.654 95.135 ;
     RECT  82.908 94.703 85.014 95.171 ;
     RECT  85.824 94.631 87.714 95.477 ;
     RECT  88.815 94.397 89.586 95.513 ;
     RECT  85.824 95.477 87.39 95.711 ;
     RECT  22.428 95.099 79.794 95.791 ;
     RECT  21.315 95.135 21.597 95.881 ;
     RECT  22.428 95.791 79.974 95.881 ;
     RECT  85.824 95.711 86.994 96.017 ;
     RECT  21.315 95.881 79.974 96.053 ;
     RECT  83.415 95.171 85.014 96.053 ;
     RECT  37.515 96.053 79.974 96.061 ;
     RECT  80.715 95.009 81.666 96.061 ;
     RECT  37.515 96.061 81.666 96.179 ;
     RECT  60.3 96.179 81.666 96.215 ;
     RECT  21.315 96.053 36.666 96.251 ;
     RECT  60.408 96.215 81.666 96.323 ;
     RECT  85.824 96.017 86.397 96.359 ;
     RECT  21.315 96.251 36.486 96.449 ;
     RECT  37.515 96.179 59.397 96.593 ;
     RECT  80.715 96.323 81.666 96.629 ;
     RECT  2.415 54.125 2.697 96.677 ;
     RECT  5.115 53.969 5.397 96.677 ;
     RECT  7.815 2.413 8.097 96.677 ;
     RECT  10.515 2.413 10.797 96.677 ;
     RECT  13.215 2.413 13.497 96.677 ;
     RECT  15.915 2.413 16.197 96.677 ;
     RECT  18.615 2.413 18.897 96.677 ;
     RECT  21.315 96.449 36.342 96.677 ;
     RECT  37.515 96.593 37.797 96.677 ;
     RECT  80.715 96.629 80.997 96.677 ;
     RECT  83.415 96.053 83.697 96.677 ;
     RECT  86.115 96.359 86.397 96.677 ;
     RECT  88.815 95.513 89.097 96.677 ;
     RECT  91.515 92.237 91.797 96.677 ;
     RECT  94.215 88.223 94.497 96.677 ;
     RECT  96.915 87.341 97.005 96.677 ;
     RECT  21.507 96.677 36.342 96.719 ;
     RECT  60.444 96.323 79.938 96.719 ;
     RECT  21.507 96.719 27.342 96.749 ;
     RECT  21.507 96.749 26.997 96.755 ;
     RECT  28.368 96.719 35.874 96.755 ;
     RECT  38.556 96.593 59.397 96.755 ;
     RECT  60.444 96.719 63.27 96.791 ;
     RECT  64.008 96.719 76.914 96.791 ;
     RECT  84.996 96.053 85.014 96.791 ;
     RECT  38.736 96.755 59.397 96.863 ;
     RECT  38.736 96.863 55.854 96.893 ;
     RECT  28.656 96.755 35.874 96.899 ;
     RECT  60.696 96.791 63.27 96.899 ;
     RECT  77.688 96.719 79.938 96.899 ;
     RECT  22.356 96.755 26.997 96.941 ;
     RECT  28.728 96.899 35.874 96.941 ;
     RECT  38.916 96.893 55.854 96.941 ;
     RECT  2.607 96.677 2.697 96.947 ;
     RECT  5.307 96.677 5.397 96.947 ;
     RECT  8.007 96.677 8.097 96.947 ;
     RECT  10.707 96.677 10.797 96.947 ;
     RECT  13.407 96.677 13.497 96.947 ;
     RECT  16.107 96.677 16.197 96.947 ;
     RECT  18.807 96.677 18.897 96.947 ;
     RECT  21.507 96.755 21.597 96.947 ;
     RECT  22.5 96.941 26.997 96.947 ;
     RECT  37.707 96.677 37.797 96.947 ;
     RECT  56.607 96.863 59.397 96.947 ;
     RECT  80.907 96.677 80.997 96.947 ;
     RECT  83.607 96.677 83.697 96.947 ;
     RECT  86.307 96.677 86.397 96.947 ;
     RECT  89.007 96.677 89.097 96.947 ;
     RECT  91.707 96.677 91.797 96.947 ;
     RECT  94.407 96.677 94.497 96.947 ;
     RECT  28.728 96.941 30.222 96.989 ;
     RECT  31.032 96.941 35.874 96.989 ;
     RECT  64.188 96.791 76.914 96.989 ;
     RECT  35.352 96.989 35.874 97.061 ;
     RECT  38.916 96.941 55.566 97.085 ;
     RECT  64.188 96.989 75.726 97.085 ;
     RECT  35.352 97.061 35.37 97.133 ;
     RECT  77.976 96.899 79.758 97.181 ;
     RECT  67.968 97.085 75.726 97.277 ;
     RECT  38.916 97.085 53.19 97.373 ;
     RECT  56.844 96.947 58.806 97.373 ;
     RECT  49.86 97.373 53.19 97.421 ;
     RECT  54.288 97.085 55.566 97.421 ;
     RECT  56.988 97.373 58.806 97.421 ;
     RECT  50.148 97.421 53.19 97.469 ;
     RECT  57.528 97.421 58.806 97.469 ;
     RECT  64.188 97.085 67.194 97.469 ;
     RECT  67.968 97.277 75.222 97.469 ;
     RECT  77.976 97.181 79.686 97.469 ;
     RECT  51.696 97.469 52.794 97.517 ;
     RECT  64.188 97.469 67.158 97.517 ;
     RECT  76.5 96.989 76.914 97.754 ;
     RECT  57.924 97.469 58.806 97.757 ;
     RECT  76.5 97.754 76.518 97.799 ;
     RECT  67.968 97.469 69.426 97.949 ;
     RECT  65.772 97.517 67.158 97.997 ;
     RECT  70.272 97.469 75.222 97.997 ;
     RECT  50.148 97.469 50.166 98.045 ;
     RECT  51.696 97.517 52.758 98.045 ;
     RECT  64.188 97.517 64.926 98.045 ;
     RECT  65.88 97.997 67.158 98.045 ;
     RECT  68.004 97.949 69.426 98.045 ;
     RECT  70.272 97.997 71.406 98.045 ;
     RECT  28.728 96.989 30.186 98.093 ;
     RECT  31.032 96.989 34.614 98.093 ;
     RECT  54.288 97.421 55.026 98.093 ;
     RECT  57.924 97.757 58.086 98.093 ;
     RECT  64.332 98.045 64.854 98.093 ;
     RECT  72.432 97.997 75.222 98.093 ;
     RECT  22.5 96.947 26.658 98.141 ;
     RECT  51.696 98.045 52.398 98.333 ;
     RECT  77.976 97.469 79.398 98.339 ;
     RECT  24.48 98.141 26.658 98.419 ;
     RECT  31.176 98.093 34.614 98.525 ;
     RECT  68.004 98.045 68.094 98.573 ;
     RECT  31.536 98.525 34.614 98.609 ;
     RECT  24.48 98.419 26.694 98.621 ;
     RECT  55.008 98.093 55.026 98.621 ;
     RECT  57.924 98.093 57.942 98.621 ;
     RECT  64.332 98.093 64.35 98.621 ;
     RECT  66.096 98.045 66.114 98.621 ;
     RECT  67.14 98.045 67.158 98.621 ;
     RECT  68.004 98.573 68.022 98.621 ;
     RECT  68.832 98.045 69.426 98.621 ;
     RECT  77.976 98.339 78.066 98.621 ;
     RECT  22.5 98.141 23.166 98.669 ;
     RECT  22.86 98.669 22.878 98.717 ;
     RECT  64.872 98.875 64.89 99.053 ;
     RECT  51.696 98.333 51.714 99.101 ;
     RECT  24.516 98.621 26.694 99.121 ;
     RECT  72.54 98.093 75.222 99.163 ;
     RECT  38.916 97.373 49.014 99.221 ;
     RECT  28.764 98.093 30.078 99.245 ;
     RECT  31.536 98.609 34.254 99.245 ;
     RECT  38.916 99.221 48.978 99.245 ;
     RECT  68.832 98.621 68.85 99.245 ;
     RECT  70.632 98.045 70.938 99.245 ;
     RECT  77.976 98.621 77.994 99.245 ;
     RECT  31.644 99.245 34.254 99.293 ;
     RECT  38.916 99.245 48.906 99.293 ;
     RECT  60.804 96.899 63.27 99.293 ;
     RECT  72.54 99.163 75.33 99.293 ;
     RECT  79.38 98.339 79.398 99.293 ;
     RECT  24.516 99.121 26.766 99.324 ;
     RECT  31.716 99.293 34.254 99.324 ;
     RECT  38.916 99.293 48.654 99.324 ;
     RECT  60.804 99.293 63.054 99.324 ;
     RECT  72.9 99.293 75.15 99.324 ;
    LAYER M4 ;
     RECT  0.06 53.328 0.227 54.12 ;
     RECT  0.227 53.424 0.371 54.12 ;
     RECT  0.371 53.52 2.408 54.12 ;
     RECT  0.325 58.464 2.408 58.488 ;
     RECT  0.181 75.456 2.408 75.48 ;
     RECT  2.408 2.148 2.512 96.672 ;
     RECT  2.512 2.418 2.6 96.672 ;
     RECT  2.6 2.418 2.704 96.942 ;
     RECT  2.704 53.28 2.729 54.12 ;
     RECT  2.729 53.28 5.108 53.832 ;
     RECT  2.704 58.464 5.108 58.488 ;
     RECT  2.704 75.456 5.108 75.48 ;
     RECT  5.108 2.148 5.212 96.672 ;
     RECT  5.212 2.418 5.3 96.672 ;
     RECT  5.3 2.418 5.404 96.942 ;
     RECT  5.404 53.28 7.808 53.832 ;
     RECT  5.404 58.464 7.808 58.488 ;
     RECT  5.404 75.456 7.808 75.48 ;
     RECT  7.808 2.148 7.912 96.672 ;
     RECT  7.912 2.418 8 96.672 ;
     RECT  8 2.418 8.104 96.942 ;
     RECT  8.104 53.28 10.508 53.832 ;
     RECT  8.104 58.464 10.508 58.488 ;
     RECT  8.104 75.456 10.508 75.48 ;
     RECT  10.508 2.148 10.612 96.672 ;
     RECT  10.612 2.418 10.7 96.672 ;
     RECT  10.7 2.418 10.804 96.942 ;
     RECT  10.804 53.28 13.208 53.832 ;
     RECT  10.804 58.464 13.208 58.488 ;
     RECT  10.804 75.456 13.208 75.48 ;
     RECT  13.208 2.148 13.312 96.672 ;
     RECT  13.312 2.418 13.4 96.672 ;
     RECT  13.4 2.418 13.504 96.942 ;
     RECT  13.504 53.28 15.908 53.832 ;
     RECT  13.504 58.464 15.908 58.488 ;
     RECT  13.504 75.456 15.908 75.48 ;
     RECT  15.908 2.148 16.012 96.672 ;
     RECT  16.012 2.418 16.1 96.672 ;
     RECT  16.1 2.418 16.204 96.942 ;
     RECT  16.204 53.28 18.608 53.832 ;
     RECT  16.204 58.464 18.608 58.488 ;
     RECT  16.204 75.456 18.608 75.48 ;
     RECT  18.608 2.148 18.712 96.672 ;
     RECT  18.712 2.418 18.8 96.672 ;
     RECT  18.8 2.418 18.904 96.942 ;
     RECT  18.904 53.28 21.308 53.832 ;
     RECT  18.904 58.464 21.308 58.488 ;
     RECT  21.265 67.152 21.308 67.176 ;
     RECT  18.904 75.456 21.308 75.48 ;
     RECT  21.308 2.148 21.412 96.672 ;
     RECT  21.412 2.418 21.5 96.672 ;
     RECT  21.5 2.418 21.604 96.942 ;
     RECT  21.604 61.536 22.277 62.712 ;
     RECT  21.604 67.152 22.313 67.176 ;
     RECT  21.604 68.352 22.348 70.104 ;
     RECT  22.348 69.504 22.421 70.104 ;
     RECT  22.277 61.536 22.493 62.184 ;
     RECT  21.604 94.992 22.565 96.936 ;
     RECT  22.565 95.856 22.597 96.936 ;
     RECT  21.604 64.32 22.673 65.832 ;
     RECT  22.597 95.856 22.681 97.464 ;
     RECT  22.673 64.32 22.709 65.064 ;
     RECT  22.489 98.64 22.741 98.664 ;
     RECT  22.741 98.016 22.834 98.664 ;
     RECT  22.421 69.744 22.925 70.104 ;
     RECT  22.834 98.016 22.931 98.712 ;
     RECT  22.931 98.016 23.219 98.664 ;
     RECT  22.669 94.608 23.317 94.728 ;
     RECT  22.493 62.16 23.641 62.184 ;
     RECT  22.348 68.352 23.785 68.376 ;
     RECT  23.317 94.032 23.785 94.728 ;
     RECT  22.681 95.856 23.785 96.984 ;
     RECT  23.641 62.16 23.821 63.096 ;
     RECT  23.785 94.032 23.893 96.984 ;
     RECT  23.219 98.016 23.893 98.136 ;
     RECT  22.709 64.32 23.929 64.344 ;
     RECT  21.604 53.28 24.008 53.832 ;
     RECT  24.001 54.864 24.008 54.888 ;
     RECT  21.604 58.464 24.008 58.488 ;
     RECT  23.821 62.016 24.008 63.096 ;
     RECT  23.929 64.32 24.008 64.728 ;
     RECT  23.929 65.952 24.008 65.976 ;
     RECT  23.785 68.208 24.008 68.376 ;
     RECT  22.925 70.08 24.008 70.104 ;
     RECT  21.604 75.456 24.008 75.48 ;
     RECT  23.749 92.784 24.008 92.808 ;
     RECT  23.893 94.032 24.008 98.136 ;
     RECT  24.008 2.148 24.112 98.136 ;
     RECT  24.112 2.418 24.304 98.136 ;
     RECT  24.304 92.496 24.421 98.136 ;
     RECT  24.421 92.496 24.541 98.616 ;
     RECT  24.304 53.28 24.563 54.888 ;
     RECT  24.304 67.248 24.617 69.24 ;
     RECT  24.304 60.384 24.689 63.096 ;
     RECT  24.304 64.704 24.851 65.976 ;
     RECT  24.541 92.496 24.877 99.288 ;
     RECT  24.617 67.248 24.905 68.232 ;
     RECT  24.877 92.496 24.947 97.512 ;
     RECT  24.947 92.496 25.049 97.464 ;
     RECT  24.304 58.464 25.121 58.68 ;
     RECT  24.689 60.384 25.121 62.184 ;
     RECT  25.049 92.496 25.265 97.416 ;
     RECT  24.304 70.704 25.369 70.728 ;
     RECT  25.265 92.496 25.517 96.936 ;
     RECT  24.617 69.216 25.525 69.24 ;
     RECT  25.369 70.704 25.525 71.64 ;
     RECT  24.563 53.568 25.549 54.888 ;
     RECT  24.877 98.592 25.553 99.288 ;
     RECT  25.525 69.216 25.571 71.64 ;
     RECT  24.851 64.704 25.58 65.688 ;
     RECT  25.549 53.568 25.589 54.936 ;
     RECT  25.585 63.216 25.621 63.24 ;
     RECT  25.58 64.56 25.621 65.688 ;
     RECT  25.571 69.216 25.625 70.008 ;
     RECT  24.905 68.208 25.657 68.232 ;
     RECT  25.625 69.216 25.657 69.432 ;
     RECT  25.657 68.208 25.66 69.432 ;
     RECT  25.553 98.592 25.661 99.192 ;
     RECT  25.621 63.216 25.667 65.688 ;
     RECT  25.66 68.208 25.697 69.24 ;
     RECT  25.801 67.008 25.837 67.032 ;
     RECT  25.837 66.672 25.873 67.032 ;
     RECT  25.121 62.16 25.981 62.184 ;
     RECT  25.667 63.216 25.981 63.816 ;
     RECT  25.667 64.944 26.017 65.688 ;
     RECT  25.873 66.672 26.017 67.848 ;
     RECT  25.981 62.16 26.156 63.816 ;
     RECT  25.121 60.384 26.197 60.936 ;
     RECT  26.156 62.064 26.197 63.816 ;
     RECT  25.661 98.592 26.525 98.616 ;
     RECT  25.517 92.496 26.593 96.456 ;
     RECT  25.589 53.568 26.708 53.832 ;
     RECT  25.589 54.864 26.708 54.936 ;
     RECT  25.121 58.656 26.708 58.68 ;
     RECT  26.197 60.096 26.708 60.936 ;
     RECT  26.197 61.968 26.708 63.816 ;
     RECT  26.017 64.944 26.708 67.848 ;
     RECT  25.697 68.928 26.708 69.24 ;
     RECT  25.571 71.616 26.708 71.64 ;
     RECT  24.304 75.456 26.708 75.48 ;
     RECT  26.593 92.496 26.708 96.6 ;
     RECT  26.708 2.148 26.812 96.672 ;
     RECT  26.812 2.418 26.9 96.672 ;
     RECT  26.9 2.418 27.004 96.942 ;
     RECT  27.004 61.968 27.101 67.848 ;
     RECT  27.004 92.256 27.587 96.744 ;
     RECT  27.101 61.968 27.605 66.744 ;
     RECT  27.004 73.584 28.001 74.136 ;
     RECT  27.101 67.776 28.028 67.848 ;
     RECT  27.004 68.928 28.028 71.832 ;
     RECT  27.004 53.568 28.037 53.832 ;
     RECT  28.028 67.776 28.145 71.832 ;
     RECT  27.004 58.656 28.165 58.68 ;
     RECT  28.145 67.776 28.181 70.776 ;
     RECT  28.145 71.808 28.217 71.832 ;
     RECT  28.037 53.568 28.289 53.592 ;
     RECT  28.177 72.816 28.357 72.84 ;
     RECT  27.004 54.864 28.537 54.936 ;
     RECT  27.605 61.968 28.609 66.312 ;
     RECT  27.004 75.36 28.753 75.48 ;
     RECT  28.285 51.84 28.969 51.864 ;
     RECT  28.165 58.464 28.997 58.68 ;
     RECT  28.997 58.464 29.029 58.776 ;
     RECT  27.004 59.76 29.041 60.6 ;
     RECT  28.609 61.968 29.041 66.6 ;
     RECT  28.825 39.648 29.077 39.672 ;
     RECT  28.717 98.064 29.125 98.088 ;
     RECT  28.709 99.216 29.173 99.24 ;
     RECT  29.077 41.04 29.185 41.064 ;
     RECT  29.125 98.016 29.225 98.088 ;
     RECT  29.077 39.12 29.269 39.672 ;
     RECT  28.069 48.912 29.269 48.936 ;
     RECT  28.537 54.672 29.269 54.936 ;
     RECT  29.225 98.064 29.269 98.088 ;
     RECT  29.173 99.072 29.269 99.24 ;
     RECT  27.587 92.544 29.293 96.744 ;
     RECT  29.249 37.2 29.408 37.224 ;
     RECT  29.269 38.688 29.408 39.672 ;
     RECT  29.185 41.04 29.408 41.688 ;
     RECT  29.329 44.352 29.408 44.376 ;
     RECT  28.825 47.04 29.408 47.064 ;
     RECT  29.269 48.24 29.408 49.608 ;
     RECT  28.969 51.84 29.408 52.2 ;
     RECT  29.269 53.568 29.408 53.592 ;
     RECT  29.269 54.672 29.408 55.416 ;
     RECT  29.029 58.128 29.408 58.776 ;
     RECT  29.041 59.76 29.408 66.6 ;
     RECT  28.181 67.776 29.408 68.184 ;
     RECT  28.181 69.84 29.408 69.864 ;
     RECT  28.357 72.144 29.408 72.84 ;
     RECT  28.001 74.064 29.408 74.136 ;
     RECT  28.753 75.36 29.408 75.72 ;
     RECT  29.293 92.544 29.408 97.08 ;
     RECT  29.408 2.148 29.512 97.08 ;
     RECT  29.512 2.418 29.596 97.08 ;
     RECT  29.596 2.418 29.704 97.032 ;
     RECT  29.704 59.76 29.843 70.824 ;
     RECT  29.704 43.392 29.987 44.376 ;
     RECT  29.704 47.04 30.028 48.264 ;
     RECT  29.269 98.064 30.089 99.24 ;
     RECT  29.843 59.76 30.233 69.528 ;
     RECT  29.704 74.064 30.233 74.328 ;
     RECT  29.704 45.936 30.305 45.96 ;
     RECT  29.704 40.992 30.412 41.688 ;
     RECT  29.843 70.704 30.413 70.824 ;
     RECT  30.233 74.064 30.413 74.088 ;
     RECT  30.412 41.664 30.432 41.688 ;
     RECT  30.233 59.76 30.449 60.984 ;
     RECT  30.413 70.704 30.701 70.728 ;
     RECT  30.028 47.328 30.705 48.264 ;
     RECT  29.704 49.44 30.705 49.56 ;
     RECT  29.987 43.392 30.769 43.416 ;
     RECT  29.704 53.952 30.769 54.888 ;
     RECT  29.704 75.36 30.769 75.768 ;
     RECT  30.705 47.328 30.803 49.56 ;
     RECT  29.704 52.032 30.805 52.248 ;
     RECT  30.769 53.952 30.805 54.984 ;
     RECT  30.769 75.12 30.853 75.768 ;
     RECT  29.704 92.304 30.877 93.624 ;
     RECT  29.704 94.608 30.877 97.032 ;
     RECT  30.877 92.304 30.949 97.032 ;
     RECT  30.089 98.064 30.949 98.616 ;
     RECT  29.704 50.592 30.953 50.616 ;
     RECT  29.704 37.584 31.004 37.608 ;
     RECT  29.704 38.688 31.004 38.712 ;
     RECT  31.004 37.584 31.045 38.712 ;
     RECT  31.045 37.584 31.091 38.808 ;
     RECT  30.853 75.168 31.097 75.768 ;
     RECT  31.091 37.584 31.189 37.608 ;
     RECT  29.704 72.144 31.189 72.168 ;
     RECT  31.091 38.688 31.201 38.808 ;
     RECT  31.189 72.144 31.237 72.312 ;
     RECT  30.985 45.888 31.273 45.912 ;
     RECT  30.233 62.16 31.273 69.528 ;
     RECT  31.237 71.808 31.273 72.312 ;
     RECT  30.949 92.304 31.277 98.616 ;
     RECT  30.803 48.912 31.309 49.56 ;
     RECT  29.704 58.128 31.309 58.488 ;
     RECT  31.277 98.016 31.333 98.616 ;
     RECT  31.273 71.808 31.345 72.552 ;
     RECT  31.273 45.024 31.453 45.912 ;
     RECT  30.449 60.048 31.532 60.984 ;
     RECT  31.273 62.16 31.532 69.864 ;
     RECT  30.769 73.536 31.597 73.656 ;
     RECT  30.805 52.032 31.741 54.984 ;
     RECT  30.769 42.768 31.772 43.416 ;
     RECT  31.333 98.016 31.925 99.24 ;
     RECT  31.345 71.712 31.993 72.552 ;
     RECT  30.803 47.328 32.029 47.88 ;
     RECT  31.309 48.912 32.029 50.184 ;
     RECT  31.532 60.048 32.029 69.864 ;
     RECT  31.993 70.896 32.029 72.552 ;
     RECT  32.029 47.328 32.101 50.184 ;
     RECT  31.741 51.216 32.101 54.984 ;
     RECT  31.189 36.912 32.108 37.608 ;
     RECT  31.201 38.688 32.108 39.768 ;
     RECT  31.772 42.768 32.108 43.896 ;
     RECT  31.453 44.88 32.108 45.912 ;
     RECT  32.101 47.328 32.108 54.984 ;
     RECT  31.309 58.128 32.108 58.968 ;
     RECT  32.029 60.048 32.108 72.552 ;
     RECT  31.597 73.536 32.108 74.088 ;
     RECT  31.097 75.168 32.108 75.72 ;
     RECT  31.277 92.304 32.108 96.936 ;
     RECT  31.925 98.592 32.209 99.24 ;
     RECT  32.108 2.148 32.212 96.936 ;
     RECT  32.212 2.418 32.3 96.936 ;
     RECT  32.3 2.418 32.404 96.942 ;
     RECT  32.404 38.688 32.501 40.44 ;
     RECT  32.404 46.56 32.501 48.504 ;
     RECT  32.209 98.592 32.501 99.288 ;
     RECT  32.501 39.36 32.573 40.44 ;
     RECT  32.404 50.304 32.573 50.856 ;
     RECT  32.404 52.464 32.573 58.968 ;
     RECT  32.404 60.048 32.681 60.888 ;
     RECT  32.501 98.592 32.753 98.616 ;
     RECT  32.573 52.464 32.819 56.52 ;
     RECT  32.404 92.4 32.825 96.888 ;
     RECT  32.825 92.4 32.933 96.744 ;
     RECT  32.933 92.4 33.041 96.552 ;
     RECT  32.404 62.016 33.149 74.088 ;
     RECT  33.149 67.776 33.257 74.04 ;
     RECT  32.501 46.944 33.397 48.504 ;
     RECT  33.149 62.016 33.397 66.072 ;
     RECT  32.573 57.648 33.505 58.968 ;
     RECT  32.681 60.048 33.505 60.072 ;
     RECT  32.573 39.36 33.589 39.384 ;
     RECT  32.573 50.304 33.617 50.328 ;
     RECT  32.404 42.72 33.685 42.744 ;
     RECT  33.685 42.72 33.829 42.792 ;
     RECT  32.819 52.464 33.829 55.848 ;
     RECT  33.257 69.84 33.833 74.04 ;
     RECT  33.829 52.464 33.865 56.664 ;
     RECT  33.505 57.648 33.865 60.072 ;
     RECT  33.041 92.88 33.901 96.552 ;
     RECT  33.793 98.592 34.085 98.616 ;
     RECT  33.865 52.464 34.165 60.072 ;
     RECT  33.397 61.056 34.165 66.072 ;
     RECT  33.833 70.368 34.172 74.04 ;
     RECT  32.404 75.456 34.172 75.72 ;
     RECT  33.829 42.72 34.175 43.032 ;
     RECT  32.404 44.16 34.175 44.904 ;
     RECT  33.589 38.688 34.189 39.384 ;
     RECT  32.573 40.368 34.189 40.44 ;
     RECT  33.257 67.776 34.333 68.76 ;
     RECT  34.333 67.2 34.477 68.76 ;
     RECT  34.165 52.464 34.549 66.072 ;
     RECT  34.477 67.2 34.549 69 ;
     RECT  33.901 92.88 34.657 96.6 ;
     RECT  32.404 37.584 34.808 37.608 ;
     RECT  34.189 38.688 34.808 40.44 ;
     RECT  33.397 41.568 34.808 41.592 ;
     RECT  34.175 42.72 34.808 44.904 ;
     RECT  33.397 46.944 34.808 48.744 ;
     RECT  33.865 50.544 34.808 51 ;
     RECT  34.549 52.464 34.808 69 ;
     RECT  34.172 70.368 34.808 75.72 ;
     RECT  34.213 77.04 34.808 77.064 ;
     RECT  34.657 92.4 34.808 96.6 ;
     RECT  34.808 2.148 34.912 96.672 ;
     RECT  34.912 2.418 35 96.672 ;
     RECT  35 2.418 35.104 96.942 ;
     RECT  35.104 42.768 35.219 45.288 ;
     RECT  35.104 51.744 35.309 55.896 ;
     RECT  35.104 47.952 35.315 50.664 ;
     RECT  35.104 39.312 35.345 40.392 ;
     RECT  35.104 57.12 35.381 69 ;
     RECT  35.315 47.952 35.417 49.32 ;
     RECT  35.315 50.352 35.417 50.664 ;
     RECT  35.104 92.4 35.417 96.6 ;
     RECT  35.417 50.544 35.561 50.664 ;
     RECT  35.104 37.584 35.597 37.608 ;
     RECT  35.104 75.12 35.633 77.064 ;
     RECT  35.633 75.12 35.651 76.872 ;
     RECT  35.417 48.24 35.669 49.32 ;
     RECT  35.417 92.4 35.741 93.528 ;
     RECT  35.417 94.608 35.777 96.6 ;
     RECT  35.104 70.32 35.813 72.168 ;
     RECT  35.381 57.12 35.849 68.952 ;
     RECT  35.309 52.176 35.921 55.896 ;
     RECT  35.651 75.12 35.939 75.48 ;
     RECT  35.921 52.464 35.957 55.896 ;
     RECT  35.813 70.32 36.029 70.824 ;
     RECT  35.849 61.344 36.137 68.952 ;
     RECT  35.104 46.272 36.173 46.632 ;
     RECT  35.777 94.608 36.209 96.552 ;
     RECT  35.219 42.768 36.317 44.568 ;
     RECT  35.669 48.72 36.349 49.32 ;
     RECT  35.957 55.872 36.421 55.896 ;
     RECT  36.209 94.608 36.421 96.408 ;
     RECT  36.173 46.272 36.425 46.44 ;
     RECT  36.137 67.68 36.461 68.952 ;
     RECT  36.421 94.032 36.467 96.408 ;
     RECT  36.425 46.416 36.497 46.44 ;
     RECT  36.467 95.136 36.497 96.408 ;
     RECT  36.421 55.872 36.529 55.992 ;
     RECT  36.349 48.72 36.709 49.512 ;
     RECT  35.561 50.544 36.709 50.616 ;
     RECT  36.709 48.72 36.745 50.616 ;
     RECT  35.849 57.12 36.781 60.072 ;
     RECT  36.097 37.104 36.853 37.128 ;
     RECT  35.957 52.464 37.069 54.888 ;
     RECT  36.529 55.872 37.069 56.04 ;
     RECT  36.137 61.344 37.177 66.552 ;
     RECT  36.461 67.68 37.177 68.76 ;
     RECT  35.813 71.952 37.249 72.168 ;
     RECT  37.177 78.096 37.357 78.12 ;
     RECT  35.104 34.176 37.508 34.2 ;
     RECT  36.853 36.816 37.508 37.128 ;
     RECT  35.345 39.312 37.508 39.576 ;
     RECT  37.249 40.944 37.508 40.968 ;
     RECT  36.317 43.344 37.508 44.568 ;
     RECT  36.745 47.904 37.508 50.616 ;
     RECT  37.069 52.464 37.508 56.04 ;
     RECT  36.781 57.024 37.508 60.072 ;
     RECT  37.177 61.344 37.508 68.76 ;
     RECT  36.029 70.368 37.508 70.824 ;
     RECT  37.249 71.952 37.508 72.216 ;
     RECT  35.104 74.064 37.508 74.088 ;
     RECT  35.939 75.456 37.508 75.48 ;
     RECT  35.651 76.848 37.508 76.872 ;
     RECT  37.357 77.904 37.508 78.12 ;
     RECT  35.741 92.4 37.508 93 ;
     RECT  36.467 94.032 37.508 94.056 ;
     RECT  36.497 95.136 37.508 96.312 ;
     RECT  37.508 2.148 37.612 96.672 ;
     RECT  37.612 2.418 37.7 96.672 ;
     RECT  37.7 2.418 37.804 96.942 ;
     RECT  37.804 43.104 37.901 44.184 ;
     RECT  37.804 38.736 37.981 39.576 ;
     RECT  37.804 36.816 38.117 36.84 ;
     RECT  37.804 46.224 38.261 49.848 ;
     RECT  37.804 52.272 38.297 60.024 ;
     RECT  38.261 46.224 38.441 46.296 ;
     RECT  37.804 76.848 38.441 78.072 ;
     RECT  37.901 43.104 38.483 43.656 ;
     RECT  38.297 52.272 38.513 59.832 ;
     RECT  37.804 61.344 38.513 73.8 ;
     RECT  38.513 61.344 38.693 72.072 ;
     RECT  38.261 47.616 38.773 49.848 ;
     RECT  37.804 40.944 38.801 40.968 ;
     RECT  38.441 77.568 38.801 78.072 ;
     RECT  38.513 52.416 38.909 59.832 ;
     RECT  38.801 78.048 38.945 78.072 ;
     RECT  37.981 39.216 38.977 39.576 ;
     RECT  38.693 65.76 39.017 72.072 ;
     RECT  39.017 70.8 39.052 72.072 ;
     RECT  38.773 47.616 39.089 50.76 ;
     RECT  37.804 92.4 39.089 93 ;
     RECT  39.052 70.8 39.161 71.88 ;
     RECT  38.483 43.104 39.193 43.368 ;
     RECT  38.441 46.224 39.589 46.248 ;
     RECT  39.637 51.36 39.836 51.384 ;
     RECT  39.836 51.36 39.877 51.816 ;
     RECT  38.797 44.976 39.913 45 ;
     RECT  39.589 46.224 39.913 46.632 ;
     RECT  38.977 39.024 40.028 39.576 ;
     RECT  39.697 79.152 40.028 79.176 ;
     RECT  39.089 47.616 40.057 49.848 ;
     RECT  39.193 42.96 40.069 43.368 ;
     RECT  39.161 71.856 40.069 71.88 ;
     RECT  40.028 79.152 40.069 79.704 ;
     RECT  39.913 44.976 40.093 46.632 ;
     RECT  40.057 47.616 40.093 50.376 ;
     RECT  37.804 94.032 40.093 94.056 ;
     RECT  37.804 34.176 40.208 34.2 ;
     RECT  40.028 38.592 40.208 39.576 ;
     RECT  38.905 40.992 40.208 41.016 ;
     RECT  40.069 42.72 40.208 43.368 ;
     RECT  40.093 44.976 40.208 50.376 ;
     RECT  39.877 51.36 40.208 52.296 ;
     RECT  38.909 53.328 40.208 59.832 ;
     RECT  38.693 61.344 40.208 64.44 ;
     RECT  39.017 65.76 40.208 69.72 ;
     RECT  39.161 70.8 40.208 70.824 ;
     RECT  40.069 71.856 40.208 71.928 ;
     RECT  38.513 73.056 40.208 73.8 ;
     RECT  37.804 75.264 40.208 75.48 ;
     RECT  40.028 76.896 40.208 76.92 ;
     RECT  40.069 78.624 40.208 80.28 ;
     RECT  39.089 92.4 40.208 92.424 ;
     RECT  40.093 93.6 40.208 94.056 ;
     RECT  37.804 95.616 40.208 96.888 ;
     RECT  40.208 2.148 40.312 96.888 ;
     RECT  40.312 2.418 40.4 96.888 ;
     RECT  40.4 2.418 40.504 96.942 ;
     RECT  40.504 46.368 40.565 48.024 ;
     RECT  40.504 49.248 40.889 52.296 ;
     RECT  40.504 81.312 40.924 81.528 ;
     RECT  40.504 53.376 40.979 59.832 ;
     RECT  40.504 95.184 40.997 96.84 ;
     RECT  40.504 77.424 41.075 78.648 ;
     RECT  40.504 83.088 41.315 83.832 ;
     RECT  40.504 60.816 41.357 75.576 ;
     RECT  41.315 83.088 41.357 83.736 ;
     RECT  40.504 92.4 41.357 94.056 ;
     RECT  40.565 47.808 41.393 48.024 ;
     RECT  40.889 49.536 41.393 52.296 ;
     RECT  40.979 53.376 41.393 59.352 ;
     RECT  41.357 60.816 41.509 75.48 ;
     RECT  41.075 78.144 41.533 78.648 ;
     RECT  40.504 80.256 41.533 80.28 ;
     RECT  41.393 47.856 41.537 48.024 ;
     RECT  41.393 49.824 41.537 52.296 ;
     RECT  40.997 95.184 41.555 96.504 ;
     RECT  41.509 60.624 41.651 75.48 ;
     RECT  41.357 92.832 41.753 94.056 ;
     RECT  41.393 53.376 41.789 59.256 ;
     RECT  41.651 67.344 41.795 75.48 ;
     RECT  40.504 43.68 41.821 44.568 ;
     RECT  41.795 67.344 41.843 72.936 ;
     RECT  41.843 67.344 41.897 70.104 ;
     RECT  41.533 78.144 41.897 80.28 ;
     RECT  41.821 43.44 41.933 44.568 ;
     RECT  41.843 71.184 41.933 72.936 ;
     RECT  40.504 41.088 42.073 41.112 ;
     RECT  40.924 81.504 42.145 81.528 ;
     RECT  41.753 93.024 42.181 94.056 ;
     RECT  41.555 95.184 42.181 95.736 ;
     RECT  41.651 60.624 42.188 66.36 ;
     RECT  41.357 83.712 42.397 83.736 ;
     RECT  41.789 54.864 42.421 59.256 ;
     RECT  42.188 60.48 42.421 66.36 ;
     RECT  40.565 46.368 42.577 46.632 ;
     RECT  42.145 80.928 42.649 81.528 ;
     RECT  41.933 43.824 42.661 44.568 ;
     RECT  42.421 54.864 42.716 66.36 ;
     RECT  41.897 67.344 42.716 67.368 ;
     RECT  41.537 49.824 42.757 51.384 ;
     RECT  42.397 83.232 42.757 83.736 ;
     RECT  41.965 99.264 42.761 99.288 ;
     RECT  42.181 93.024 42.865 95.736 ;
     RECT  42.829 96.816 42.865 96.84 ;
     RECT  42.865 93.024 42.901 96.84 ;
     RECT  40.504 34.176 42.908 34.2 ;
     RECT  40.504 39.024 42.908 39.048 ;
     RECT  42.073 40.992 42.908 41.112 ;
     RECT  42.145 42.192 42.908 42.216 ;
     RECT  42.661 43.824 42.908 45.288 ;
     RECT  42.577 46.368 42.908 46.728 ;
     RECT  41.537 47.856 42.908 47.928 ;
     RECT  42.757 49.296 42.908 51.384 ;
     RECT  41.789 53.376 42.908 53.832 ;
     RECT  42.716 54.864 42.908 67.368 ;
     RECT  41.897 68.4 42.908 70.104 ;
     RECT  41.933 71.184 42.908 72.456 ;
     RECT  41.795 74.592 42.908 75.48 ;
     RECT  41.897 78.144 42.908 79.512 ;
     RECT  42.649 80.928 42.908 81.624 ;
     RECT  42.757 82.752 42.908 83.736 ;
     RECT  42.181 85.92 42.908 85.944 ;
     RECT  41.965 88.944 42.908 88.968 ;
     RECT  42.901 93.024 42.908 96.984 ;
     RECT  42.908 2.148 43.012 96.984 ;
     RECT  43.012 2.418 43.049 96.984 ;
     RECT  43.049 2.418 43.204 96.942 ;
     RECT  43.204 92.352 43.265 96.84 ;
     RECT  43.204 90.912 43.331 90.936 ;
     RECT  43.204 48.912 43.337 51.864 ;
     RECT  43.265 92.352 43.337 96.744 ;
     RECT  43.204 76.8 43.571 83.592 ;
     RECT  43.204 57.024 43.619 70.248 ;
     RECT  43.204 43.824 43.697 43.848 ;
     RECT  43.204 42.192 43.741 42.792 ;
     RECT  43.204 39.024 43.913 40.2 ;
     RECT  43.204 88.32 43.949 88.344 ;
     RECT  43.619 60 43.985 70.248 ;
     RECT  43.204 52.896 44.003 55.8 ;
     RECT  43.913 39.264 44.165 40.2 ;
     RECT  43.571 76.8 44.165 79.128 ;
     RECT  43.204 85.2 44.197 86.328 ;
     RECT  44.003 53.376 44.201 55.8 ;
     RECT  43.204 74.784 44.233 75.48 ;
     RECT  44.165 76.8 44.233 78.984 ;
     RECT  43.337 92.352 44.291 96.504 ;
     RECT  43.337 51.36 44.341 51.864 ;
     RECT  44.201 54.912 44.345 55.8 ;
     RECT  43.741 42.192 44.385 42.216 ;
     RECT  43.571 81.456 44.389 83.592 ;
     RECT  44.197 84.672 44.389 86.328 ;
     RECT  43.619 57.024 44.453 59.016 ;
     RECT  44.165 39.744 44.483 40.2 ;
     RECT  44.341 51.168 44.557 51.864 ;
     RECT  43.571 80.112 44.561 80.136 ;
     RECT  44.233 74.784 44.579 78.984 ;
     RECT  43.204 45.024 44.597 46.296 ;
     RECT  44.579 77.664 44.62 78.984 ;
     RECT  44.579 74.784 44.633 76.392 ;
     RECT  44.557 51.168 44.665 52.296 ;
     RECT  43.204 71.952 44.737 73.608 ;
     RECT  43.204 47.328 44.765 47.88 ;
     RECT  43.337 48.912 44.773 49.896 ;
     RECT  44.665 50.928 44.773 52.296 ;
     RECT  44.453 57.12 44.821 59.016 ;
     RECT  43.985 60 44.821 65.736 ;
     RECT  44.291 92.352 44.869 96.36 ;
     RECT  44.389 81.456 44.917 86.328 ;
     RECT  44.597 46.272 45.133 46.296 ;
     RECT  44.765 47.328 45.133 47.928 ;
     RECT  44.385 41.664 45.205 42.216 ;
     RECT  44.413 43.392 45.205 43.416 ;
     RECT  44.201 53.376 45.385 53.832 ;
     RECT  44.345 54.96 45.385 55.8 ;
     RECT  44.701 91.152 45.457 91.176 ;
     RECT  44.869 92.208 45.457 96.36 ;
     RECT  45.133 46.272 45.493 47.928 ;
     RECT  44.773 48.912 45.493 52.296 ;
     RECT  45.385 53.376 45.565 55.8 ;
     RECT  43.204 34.176 45.608 34.2 ;
     RECT  44.483 39.744 45.608 39.864 ;
     RECT  45.205 41.664 45.608 43.416 ;
     RECT  44.597 45.024 45.608 45.288 ;
     RECT  45.493 46.272 45.608 52.296 ;
     RECT  45.565 53.328 45.608 55.8 ;
     RECT  44.821 57.12 45.608 65.736 ;
     RECT  43.985 66.72 45.608 70.248 ;
     RECT  44.737 71.952 45.608 74.424 ;
     RECT  44.633 75.456 45.608 76.392 ;
     RECT  44.62 78.48 45.608 78.984 ;
     RECT  44.917 81.456 45.608 87.048 ;
     RECT  44.245 89.472 45.608 89.496 ;
     RECT  45.457 91.152 45.608 96.36 ;
     RECT  45.608 2.148 45.709 96.672 ;
     RECT  45.709 2.148 45.712 96.744 ;
     RECT  45.712 2.418 45.8 96.744 ;
     RECT  45.8 2.418 45.904 96.942 ;
     RECT  45.904 54.72 46.019 76.968 ;
     RECT  46.019 54.72 46.037 72.936 ;
     RECT  46.019 74.064 46.06 76.968 ;
     RECT  46.037 54.96 46.067 72.936 ;
     RECT  45.904 38.736 46.109 40.488 ;
     RECT  45.904 43.824 46.181 44.712 ;
     RECT  45.904 90.768 46.253 96.84 ;
     RECT  46.109 38.736 46.259 39.768 ;
     RECT  45.904 45.888 46.325 49.848 ;
     RECT  45.904 41.568 46.433 42.84 ;
     RECT  46.067 54.96 46.505 72.696 ;
     RECT  46.253 96.816 46.577 96.84 ;
     RECT  45.061 99.264 46.685 99.288 ;
     RECT  45.904 81.888 46.739 86.904 ;
     RECT  46.739 82.176 46.793 86.904 ;
     RECT  46.433 42.72 46.829 42.84 ;
     RECT  46.505 54.96 46.937 67.368 ;
     RECT  45.904 78.48 46.937 80.376 ;
     RECT  46.505 68.496 46.972 72.696 ;
     RECT  46.06 74.064 47.125 76.92 ;
     RECT  46.259 38.784 47.149 39.768 ;
     RECT  46.829 42.816 47.149 42.84 ;
     RECT  46.181 43.824 47.149 43.992 ;
     RECT  45.904 52.992 47.185 53.544 ;
     RECT  47.149 42.816 47.221 43.992 ;
     RECT  47.005 99.216 47.225 99.24 ;
     RECT  46.972 68.496 47.297 72.552 ;
     RECT  46.325 45.888 47.317 46.296 ;
     RECT  46.325 47.28 47.317 49.848 ;
     RECT  46.253 90.768 47.317 95.832 ;
     RECT  46.937 80.352 47.329 80.376 ;
     RECT  47.317 45.888 47.365 49.848 ;
     RECT  45.904 50.928 47.365 51.432 ;
     RECT  47.317 90.624 47.401 95.832 ;
     RECT  47.221 42.816 47.468 44.472 ;
     RECT  47.125 73.776 47.468 76.92 ;
     RECT  46.937 78.48 47.481 78.984 ;
     RECT  47.365 45.888 47.509 51.432 ;
     RECT  47.185 52.56 47.509 53.544 ;
     RECT  47.401 90.624 47.869 96.6 ;
     RECT  46.937 66.72 47.941 67.368 ;
     RECT  47.468 73.776 47.989 77.16 ;
     RECT  47.149 38.784 48.037 39.816 ;
     RECT  46.433 41.568 48.037 41.592 ;
     RECT  47.869 90.624 48.037 96.888 ;
     RECT  47.509 45.888 48.049 53.544 ;
     RECT  46.937 54.96 48.049 65.736 ;
     RECT  47.941 66.72 48.085 67.416 ;
     RECT  47.297 68.496 48.085 72.168 ;
     RECT  47.989 73.776 48.085 77.448 ;
     RECT  47.481 78.432 48.085 78.984 ;
     RECT  47.989 99.168 48.085 99.192 ;
     RECT  48.037 38.784 48.181 41.592 ;
     RECT  48.085 99.12 48.181 99.192 ;
     RECT  48.049 45.888 48.265 65.736 ;
     RECT  48.085 66.72 48.265 72.168 ;
     RECT  48.085 73.776 48.265 78.984 ;
     RECT  47.329 80.352 48.265 80.808 ;
     RECT  45.904 34.176 48.308 34.2 ;
     RECT  48.157 36.912 48.308 36.936 ;
     RECT  48.181 38.16 48.308 41.592 ;
     RECT  47.468 42.816 48.308 44.808 ;
     RECT  48.265 45.888 48.308 78.984 ;
     RECT  48.265 80.352 48.308 81.144 ;
     RECT  46.793 82.176 48.308 86.808 ;
     RECT  45.904 89.472 48.308 89.496 ;
     RECT  48.037 90.624 48.308 97.464 ;
     RECT  48.181 99.072 48.371 99.192 ;
     RECT  48.308 2.148 48.412 97.464 ;
     RECT  48.412 2.418 48.604 97.464 ;
     RECT  48.604 43.056 48.737 49.848 ;
     RECT  48.604 53.616 48.755 77.16 ;
     RECT  48.604 41.472 48.773 42.072 ;
     RECT  48.604 91.872 48.773 97.464 ;
     RECT  48.371 99.12 48.899 99.192 ;
     RECT  48.755 53.616 48.917 72.744 ;
     RECT  48.917 57.072 48.947 72.744 ;
     RECT  48.604 50.928 48.989 52.296 ;
     RECT  48.604 81.024 48.989 86.808 ;
     RECT  48.604 37.92 49.025 39.816 ;
     RECT  48.947 57.072 49.025 66.312 ;
     RECT  48.949 99.216 49.043 99.24 ;
     RECT  48.737 43.056 49.061 46.872 ;
     RECT  48.989 81.024 49.069 83.064 ;
     RECT  49.025 57.072 49.097 66.072 ;
     RECT  49.025 37.92 49.133 39.768 ;
     RECT  49.133 37.92 49.205 37.944 ;
     RECT  48.604 36.912 49.241 36.936 ;
     RECT  48.773 41.568 49.529 42.072 ;
     RECT  48.604 90.576 49.529 90.6 ;
     RECT  48.755 73.776 49.633 77.16 ;
     RECT  48.604 78.432 49.633 79.464 ;
     RECT  48.989 51.216 49.669 52.296 ;
     RECT  48.917 53.616 49.669 56.088 ;
     RECT  49.529 42.048 49.673 42.072 ;
     RECT  48.989 84.336 49.763 86.808 ;
     RECT  48.773 92.256 49.861 97.464 ;
     RECT  49.669 51.216 49.993 56.088 ;
     RECT  49.097 57.072 49.993 65.976 ;
     RECT  48.737 47.856 50.005 49.848 ;
     RECT  49.993 51.216 50.005 65.976 ;
     RECT  48.947 67.392 50.029 72.744 ;
     RECT  49.633 73.776 50.029 79.752 ;
     RECT  49.133 39.264 50.245 39.768 ;
     RECT  49.921 40.848 50.245 40.872 ;
     RECT  49.061 43.104 50.353 46.872 ;
     RECT  50.005 47.856 50.353 65.976 ;
     RECT  50.029 67.392 50.389 79.752 ;
     RECT  49.861 92.256 50.437 98.04 ;
     RECT  50.353 43.104 50.461 65.976 ;
     RECT  50.437 91.392 50.533 98.04 ;
     RECT  50.245 39.264 50.677 40.872 ;
     RECT  50.461 42.528 50.677 65.976 ;
     RECT  50.677 42.528 50.749 66.072 ;
     RECT  50.389 67.152 50.749 79.752 ;
     RECT  50.533 91.392 50.773 98.328 ;
     RECT  50.677 38.784 50.828 40.872 ;
     RECT  50.828 38.784 50.857 41.544 ;
     RECT  50.749 42.528 50.857 79.752 ;
     RECT  50.857 38.784 50.869 79.752 ;
     RECT  49.069 81.36 50.869 83.064 ;
     RECT  49.763 84.672 50.869 86.808 ;
     RECT  48.604 34.176 51.008 34.2 ;
     RECT  50.713 36.816 51.008 36.84 ;
     RECT  50.869 38.784 51.008 83.064 ;
     RECT  50.869 84.672 51.008 86.856 ;
     RECT  50.773 91.392 51.008 99.192 ;
     RECT  51.008 2.148 51.112 99.192 ;
     RECT  51.112 2.418 51.304 99.192 ;
     RECT  51.304 89.28 51.491 99.192 ;
     RECT  51.304 41.472 51.545 43.368 ;
     RECT  51.304 44.736 51.581 56.088 ;
     RECT  51.581 44.736 51.587 51.144 ;
     RECT  51.491 89.28 51.725 99.096 ;
     RECT  51.304 36.24 51.731 40.488 ;
     RECT  51.587 48.768 51.869 51.144 ;
     RECT  51.587 44.736 51.923 47.736 ;
     RECT  51.869 48.768 52.013 48.792 ;
     RECT  51.304 73.536 52.163 86.856 ;
     RECT  51.304 69.024 52.265 71.208 ;
     RECT  52.364 29.376 52.369 29.4 ;
     RECT  51.731 36.24 52.369 36.84 ;
     RECT  51.304 57.072 52.369 67.416 ;
     RECT  52.265 69.024 52.369 71.112 ;
     RECT  51.725 89.28 52.373 98.328 ;
     RECT  51.304 72.192 52.405 72.504 ;
     RECT  52.163 73.536 52.405 77.064 ;
     RECT  51.304 34.176 52.433 35.016 ;
     RECT  52.369 36.048 52.433 36.84 ;
     RECT  52.163 78.384 52.445 86.856 ;
     RECT  52.369 29.376 52.451 30.84 ;
     RECT  52.451 29.76 52.453 30.84 ;
     RECT  51.731 38.064 52.481 40.488 ;
     RECT  52.433 34.176 52.549 36.84 ;
     RECT  52.481 38.064 52.589 40.44 ;
     RECT  51.581 52.992 52.621 56.088 ;
     RECT  52.369 57.072 52.621 71.112 ;
     RECT  52.621 52.992 52.657 71.112 ;
     RECT  52.589 38.064 52.661 40.2 ;
     RECT  52.445 78.384 52.739 85.464 ;
     RECT  51.923 44.928 52.789 47.736 ;
     RECT  52.621 32.736 52.801 32.76 ;
     RECT  52.549 33.936 52.801 36.84 ;
     RECT  52.801 32.736 52.837 36.84 ;
     RECT  52.837 31.968 52.945 36.84 ;
     RECT  51.869 50.16 52.945 51.144 ;
     RECT  52.945 50.16 52.981 51.192 ;
     RECT  52.789 44.928 53.029 47.88 ;
     RECT  52.981 49.632 53.029 51.192 ;
     RECT  52.657 52.224 53.029 71.112 ;
     RECT  52.945 31.728 53.233 36.84 ;
     RECT  52.661 38.064 53.233 39.624 ;
     RECT  51.545 41.472 53.269 43.32 ;
     RECT  53.029 44.784 53.269 47.88 ;
     RECT  52.373 91.152 53.317 98.328 ;
     RECT  52.453 29.76 53.557 30.216 ;
     RECT  53.317 91.152 53.557 98.616 ;
     RECT  53.557 29.52 53.593 30.216 ;
     RECT  53.485 28.272 53.708 28.296 ;
     RECT  53.593 29.52 53.708 30.696 ;
     RECT  53.233 31.728 53.708 39.624 ;
     RECT  53.269 41.472 53.708 47.88 ;
     RECT  53.029 49.632 53.708 71.112 ;
     RECT  52.405 72.192 53.708 77.064 ;
     RECT  52.739 78.384 53.708 79.224 ;
     RECT  52.739 80.256 53.708 85.464 ;
     RECT  52.445 86.544 53.708 86.856 ;
     RECT  52.373 89.28 53.708 90.072 ;
     RECT  53.557 91.152 53.708 99.192 ;
     RECT  53.708 2.148 53.812 99.192 ;
     RECT  53.812 2.418 53.939 99.192 ;
     RECT  53.939 2.418 54.004 98.616 ;
     RECT  54.004 50.592 54.065 86.856 ;
     RECT  54.065 50.592 54.353 77.736 ;
     RECT  54.004 28.56 54.461 49.464 ;
     RECT  54.461 43.056 54.569 49.464 ;
     RECT  54.065 79.008 54.707 86.856 ;
     RECT  54.569 46.848 54.713 49.464 ;
     RECT  54.707 80.64 54.749 86.856 ;
     RECT  54.004 91.968 54.785 98.616 ;
     RECT  54.713 46.848 54.857 48.936 ;
     RECT  54.785 92.112 54.857 98.616 ;
     RECT  54.749 80.64 54.965 85.512 ;
     RECT  54.857 92.256 55.037 98.616 ;
     RECT  54.569 43.056 55.073 45.768 ;
     RECT  54.461 28.56 55.145 41.784 ;
     RECT  55.145 28.56 55.181 39.912 ;
     RECT  54.353 72.192 55.285 77.736 ;
     RECT  54.353 50.592 55.289 71.208 ;
     RECT  55.037 92.256 55.372 97.752 ;
     RECT  55.289 50.592 55.397 60.936 ;
     RECT  55.145 40.944 55.433 41.784 ;
     RECT  55.285 72.192 55.681 77.928 ;
     RECT  54.707 79.008 55.681 79.56 ;
     RECT  55.397 50.592 55.717 60.792 ;
     RECT  54.857 47.04 55.861 48.936 ;
     RECT  55.717 49.968 55.861 60.792 ;
     RECT  54.965 80.88 55.861 85.512 ;
     RECT  54.749 86.544 55.861 86.856 ;
     RECT  55.909 99.024 56.005 99.048 ;
     RECT  55.681 72.192 56.113 79.56 ;
     RECT  55.861 80.88 56.113 86.856 ;
     RECT  55.372 92.448 56.149 97.752 ;
     RECT  56.005 99.024 56.149 99.144 ;
     RECT  55.289 61.92 56.185 71.208 ;
     RECT  56.113 72.192 56.185 86.856 ;
     RECT  56.149 92.448 56.195 99.144 ;
     RECT  55.073 43.056 56.257 44.712 ;
     RECT  55.073 45.744 56.257 45.768 ;
     RECT  55.181 28.56 56.293 37.608 ;
     RECT  55.181 38.64 56.293 39.912 ;
     RECT  56.257 43.056 56.293 45.768 ;
     RECT  55.861 47.04 56.293 60.792 ;
     RECT  56.185 61.92 56.365 86.856 ;
     RECT  56.293 28.56 56.408 39.912 ;
     RECT  55.433 41.136 56.408 41.784 ;
     RECT  56.293 43.056 56.408 45.816 ;
     RECT  56.293 46.896 56.408 60.792 ;
     RECT  56.365 61.92 56.408 87.288 ;
     RECT  54.004 89.28 56.408 90.072 ;
     RECT  56.195 92.448 56.408 98.616 ;
     RECT  56.408 2.148 56.512 98.616 ;
     RECT  56.512 2.418 56.704 98.616 ;
     RECT  56.704 45.264 56.765 57.432 ;
     RECT  56.704 28.464 56.819 39.864 ;
     RECT  56.765 48.96 56.819 57.432 ;
     RECT  56.704 66.288 56.837 85.512 ;
     RECT  56.765 45.264 56.873 47.688 ;
     RECT  56.704 86.544 56.963 87.288 ;
     RECT  56.873 45.264 57.053 45.864 ;
     RECT  56.837 66.288 57.125 67.32 ;
     RECT  56.837 68.688 57.197 85.512 ;
     RECT  56.819 29.088 57.269 39.864 ;
     RECT  56.704 61.584 57.269 65.016 ;
     RECT  57.197 68.688 57.443 76.824 ;
     RECT  57.197 77.904 57.449 85.512 ;
     RECT  57.449 77.904 57.521 82.104 ;
     RECT  57.521 81.216 57.539 82.104 ;
     RECT  56.704 92.976 57.635 98.616 ;
     RECT  57.443 73.248 57.665 76.824 ;
     RECT  57.449 83.088 57.773 85.512 ;
     RECT  56.819 51.168 57.805 57.432 ;
     RECT  56.704 58.464 57.805 60.072 ;
     RECT  57.805 51.168 57.809 60.072 ;
     RECT  57.809 51.168 57.845 54.12 ;
     RECT  57.269 29.088 57.877 35.832 ;
     RECT  57.269 36.816 57.881 39.864 ;
     RECT  57.845 51.168 57.881 51.864 ;
     RECT  57.877 29.04 57.953 35.832 ;
     RECT  57.635 93.264 57.953 98.616 ;
     RECT  57.539 81.36 57.989 82.104 ;
     RECT  56.819 48.96 58.021 50.184 ;
     RECT  57.881 51.168 58.021 51.384 ;
     RECT  57.953 29.04 58.057 29.64 ;
     RECT  57.125 66.768 58.057 67.32 ;
     RECT  57.443 68.688 58.057 72.264 ;
     RECT  57.269 61.92 58.093 65.016 ;
     RECT  57.953 93.264 58.097 98.088 ;
     RECT  56.704 41.088 58.133 44.184 ;
     RECT  58.057 66.768 58.237 72.264 ;
     RECT  57.953 30.864 58.309 35.832 ;
     RECT  57.881 36.816 58.309 38.184 ;
     RECT  58.133 41.472 58.309 44.184 ;
     RECT  57.053 45.84 58.309 45.864 ;
     RECT  57.773 83.712 58.309 85.512 ;
     RECT  56.963 86.544 58.309 87.24 ;
     RECT  57.809 55.2 58.501 60.072 ;
     RECT  58.237 66.528 58.525 72.264 ;
     RECT  57.665 73.248 58.525 76.728 ;
     RECT  57.881 39.312 58.561 39.864 ;
     RECT  57.989 81.36 58.561 81.96 ;
     RECT  58.309 83.712 58.561 87.24 ;
     RECT  56.704 88.368 58.561 90.072 ;
     RECT  58.309 41.472 58.597 45.864 ;
     RECT  56.873 47.04 58.597 47.688 ;
     RECT  58.597 41.472 58.705 47.688 ;
     RECT  58.021 48.96 58.705 51.384 ;
     RECT  58.501 55.2 58.705 60.696 ;
     RECT  58.093 61.92 58.705 65.448 ;
     RECT  58.097 93.264 58.817 97.752 ;
     RECT  57.845 52.992 58.949 54.12 ;
     RECT  58.561 81.168 58.981 81.96 ;
     RECT  58.705 41.472 59.101 51.384 ;
     RECT  58.949 52.368 59.101 54.12 ;
     RECT  58.057 28.512 59.108 29.64 ;
     RECT  58.309 30.864 59.108 38.184 ;
     RECT  58.561 39.312 59.108 40.44 ;
     RECT  59.101 41.472 59.108 54.12 ;
     RECT  58.705 55.2 59.108 65.448 ;
     RECT  58.525 66.528 59.108 76.728 ;
     RECT  57.521 77.904 59.108 79.56 ;
     RECT  58.981 81.168 59.108 82.728 ;
     RECT  58.561 83.712 59.108 90.072 ;
     RECT  58.817 93.264 59.108 96.942 ;
     RECT  59.108 2.148 59.212 96.942 ;
     RECT  59.212 2.418 59.404 96.942 ;
     RECT  59.404 73.824 59.651 78.504 ;
     RECT  59.404 32.832 59.681 49.224 ;
     RECT  59.651 73.824 59.747 78.216 ;
     RECT  59.681 36.528 59.753 49.224 ;
     RECT  59.404 68.928 59.825 72.792 ;
     RECT  59.404 88.08 60.185 90.072 ;
     RECT  59.753 44.16 60.373 49.224 ;
     RECT  59.404 50.352 60.373 67.704 ;
     RECT  59.404 28.416 60.613 31.8 ;
     RECT  59.681 32.832 60.613 35.496 ;
     RECT  60.373 44.16 60.617 67.704 ;
     RECT  59.747 73.824 60.757 77.688 ;
     RECT  59.825 72.192 60.829 72.792 ;
     RECT  60.757 73.824 60.829 77.928 ;
     RECT  59.404 93.264 60.833 96.744 ;
     RECT  59.404 86.544 60.853 86.856 ;
     RECT  59.404 79.536 60.865 85.464 ;
     RECT  60.853 86.544 60.865 86.904 ;
     RECT  60.829 72.192 60.901 77.928 ;
     RECT  60.617 53.328 60.949 67.704 ;
     RECT  59.825 68.928 60.949 71.16 ;
     RECT  60.833 93.312 61.117 96.744 ;
     RECT  60.185 88.224 61.225 90.072 ;
     RECT  60.901 72.192 61.333 78.072 ;
     RECT  59.753 36.528 61.381 43.08 ;
     RECT  60.617 44.16 61.381 52.296 ;
     RECT  61.381 36.528 61.621 52.296 ;
     RECT  60.949 53.328 61.621 71.16 ;
     RECT  60.613 28.416 61.669 35.496 ;
     RECT  61.669 28.416 61.693 35.544 ;
     RECT  61.621 36.528 61.693 71.16 ;
     RECT  61.693 28.416 61.808 71.16 ;
     RECT  61.333 72.192 61.808 78.12 ;
     RECT  60.865 79.536 61.808 86.904 ;
     RECT  61.225 88.128 61.808 90.072 ;
     RECT  61.117 93.312 61.808 96.792 ;
     RECT  61.808 2.148 61.912 96.792 ;
     RECT  61.912 2.418 62 96.792 ;
     RECT  62 2.418 62.104 96.942 ;
     RECT  62.104 28.416 62.273 37.176 ;
     RECT  62.104 83.76 62.531 83.784 ;
     RECT  62.104 93.264 62.741 96.744 ;
     RECT  62.104 38.208 62.921 69.336 ;
     RECT  62.921 38.208 62.957 69.288 ;
     RECT  62.741 93.312 63.137 96.744 ;
     RECT  62.273 28.512 63.155 37.176 ;
     RECT  63.155 32.736 63.245 37.176 ;
     RECT  62.957 38.208 63.353 39.768 ;
     RECT  62.104 84.912 63.353 90.072 ;
     RECT  62.957 40.848 63.389 69.288 ;
     RECT  63.245 32.736 63.461 33.048 ;
     RECT  63.389 40.848 63.461 64.2 ;
     RECT  63.137 95.472 63.539 96.744 ;
     RECT  62.104 70.32 63.637 82.104 ;
     RECT  63.637 70.272 63.961 82.296 ;
     RECT  63.353 84.912 63.997 87.816 ;
     RECT  63.389 65.184 64.069 69.288 ;
     RECT  63.961 70.272 64.069 82.536 ;
     RECT  64.069 98.592 64.133 98.616 ;
     RECT  63.997 84.336 64.213 87.816 ;
     RECT  63.245 34.176 64.285 37.176 ;
     RECT  63.353 38.208 64.285 39.24 ;
     RECT  63.137 93.312 64.285 94.056 ;
     RECT  63.539 96.144 64.429 96.744 ;
     RECT  64.133 98.016 64.429 98.616 ;
     RECT  64.213 83.904 64.465 87.816 ;
     RECT  63.155 28.512 64.508 31.752 ;
     RECT  63.461 32.736 64.508 32.952 ;
     RECT  64.285 34.176 64.508 39.24 ;
     RECT  63.461 40.848 64.508 52.296 ;
     RECT  63.461 53.328 64.508 64.104 ;
     RECT  64.069 65.184 64.508 82.536 ;
     RECT  64.465 83.904 64.508 88.152 ;
     RECT  63.353 89.28 64.508 90.072 ;
     RECT  64.285 93.312 64.508 94.632 ;
     RECT  64.429 96.144 64.508 98.616 ;
     RECT  64.508 2.148 64.549 98.616 ;
     RECT  64.549 2.148 64.612 99 ;
     RECT  64.612 2.418 64.789 99 ;
     RECT  64.789 2.418 64.804 99.144 ;
     RECT  64.804 33.6 64.931 40.248 ;
     RECT  64.804 92.832 64.973 99.144 ;
     RECT  64.973 93.216 64.979 99.144 ;
     RECT  64.931 34.176 65.045 40.248 ;
     RECT  64.804 41.376 65.045 45 ;
     RECT  65.045 34.176 65.153 37.176 ;
     RECT  64.804 31.152 65.405 31.416 ;
     RECT  64.804 53.328 65.441 83.016 ;
     RECT  64.804 45.984 65.513 52.296 ;
     RECT  64.804 84 65.585 90.504 ;
     RECT  65.441 72.192 65.797 83.016 ;
     RECT  65.585 84 65.797 85.464 ;
     RECT  65.797 72.192 65.843 85.464 ;
     RECT  65.843 72.192 65.873 83.304 ;
     RECT  65.873 73.488 65.891 83.304 ;
     RECT  64.979 93.216 65.989 98.088 ;
     RECT  65.441 53.328 66.017 71.112 ;
     RECT  65.513 50.352 66.049 52.296 ;
     RECT  66.017 53.328 66.049 53.4 ;
     RECT  65.045 38.4 66.085 40.248 ;
     RECT  65.045 41.376 66.085 44.904 ;
     RECT  65.585 86.544 66.085 90.504 ;
     RECT  65.989 93.216 66.125 98.616 ;
     RECT  65.891 73.488 66.179 79.56 ;
     RECT  66.013 26.64 66.337 26.664 ;
     RECT  66.085 38.4 66.409 44.904 ;
     RECT  66.125 93.216 66.485 98.04 ;
     RECT  66.485 93.216 66.62 97.512 ;
     RECT  65.513 45.984 66.625 49.32 ;
     RECT  66.049 50.352 66.625 53.4 ;
     RECT  66.409 38.4 66.805 45 ;
     RECT  66.625 45.984 66.805 53.4 ;
     RECT  65.153 34.176 66.877 36.024 ;
     RECT  65.153 37.152 66.877 37.176 ;
     RECT  65.873 72.192 66.877 72.36 ;
     RECT  66.62 92.928 66.899 97.512 ;
     RECT  65.843 84.576 66.949 85.464 ;
     RECT  66.085 86.544 66.949 90.6 ;
     RECT  65.891 80.64 67.057 83.304 ;
     RECT  66.337 26.592 67.208 26.664 ;
     RECT  66.049 28.224 67.208 28.248 ;
     RECT  67.165 29.28 67.208 29.304 ;
     RECT  65.405 31.392 67.208 31.416 ;
     RECT  66.877 34.176 67.208 37.176 ;
     RECT  66.805 38.4 67.208 53.4 ;
     RECT  66.017 54.384 67.208 71.112 ;
     RECT  66.877 72.192 67.208 72.456 ;
     RECT  66.179 73.824 67.208 79.56 ;
     RECT  67.057 80.64 67.208 83.352 ;
     RECT  66.949 84.576 67.208 85.512 ;
     RECT  66.949 86.496 67.208 90.6 ;
     RECT  66.899 92.928 67.208 97.464 ;
     RECT  67.208 2.148 67.312 97.464 ;
     RECT  67.129 98.592 67.333 98.616 ;
     RECT  67.312 2.418 67.504 97.464 ;
     RECT  67.504 89.184 67.619 91.752 ;
     RECT  67.333 98.592 67.619 99.192 ;
     RECT  67.504 93.024 67.709 97.464 ;
     RECT  67.619 98.592 67.715 99.144 ;
     RECT  67.504 84.384 67.745 88.104 ;
     RECT  67.745 84.384 67.817 84.888 ;
     RECT  67.504 43.008 67.853 83.352 ;
     RECT  67.709 93.024 67.853 96.936 ;
     RECT  67.853 53.28 67.889 83.352 ;
     RECT  67.715 98.592 67.909 98.616 ;
     RECT  67.619 89.232 67.948 91.752 ;
     RECT  67.909 98.544 67.957 98.616 ;
     RECT  67.948 89.232 68.285 90.744 ;
     RECT  67.889 53.28 68.321 83.304 ;
     RECT  68.321 53.28 68.387 83.064 ;
     RECT  67.948 91.728 68.393 91.752 ;
     RECT  67.745 85.92 68.429 88.104 ;
     RECT  67.817 84.576 68.537 84.888 ;
     RECT  68.429 87.792 68.537 88.104 ;
     RECT  68.537 87.936 68.605 88.104 ;
     RECT  68.285 89.232 68.605 90.456 ;
     RECT  67.957 97.92 68.645 98.616 ;
     RECT  67.504 38.784 68.677 39.768 ;
     RECT  68.677 37.824 68.713 39.768 ;
     RECT  67.504 41.184 68.713 41.976 ;
     RECT  67.853 96.912 68.749 96.936 ;
     RECT  68.645 98.592 68.773 98.616 ;
     RECT  68.713 37.824 68.78 41.976 ;
     RECT  67.853 43.008 68.78 52.296 ;
     RECT  68.387 53.28 68.825 70.104 ;
     RECT  68.605 87.936 68.825 90.456 ;
     RECT  68.773 98.592 68.861 99.24 ;
     RECT  68.749 96.912 68.915 97.512 ;
     RECT  67.853 93.024 68.965 95.928 ;
     RECT  68.915 96.912 68.965 97.464 ;
     RECT  68.965 93.024 69.253 97.464 ;
     RECT  68.861 98.592 69.437 99.192 ;
     RECT  68.387 71.184 69.469 83.064 ;
     RECT  69.253 36.624 69.541 36.648 ;
     RECT  68.78 37.824 69.541 52.296 ;
     RECT  68.825 68.64 69.577 70.104 ;
     RECT  69.469 71.184 69.577 83.304 ;
     RECT  67.504 28.224 69.613 28.248 ;
     RECT  69.541 36.624 69.613 52.296 ;
     RECT  68.825 53.28 69.613 67.608 ;
     RECT  67.504 34.896 69.685 34.968 ;
     RECT  69.577 68.64 69.685 83.304 ;
     RECT  68.537 84.672 69.685 84.888 ;
     RECT  69.685 68.64 69.721 84.888 ;
     RECT  68.429 85.92 69.721 86.664 ;
     RECT  69.613 36.624 69.74 67.608 ;
     RECT  69.253 92.928 69.781 97.464 ;
     RECT  67.504 26.592 69.908 26.664 ;
     RECT  69.613 27.648 69.908 28.248 ;
     RECT  67.504 29.28 69.908 29.304 ;
     RECT  67.504 31.392 69.908 31.416 ;
     RECT  69.685 34.08 69.908 34.968 ;
     RECT  69.74 36.48 69.908 67.608 ;
     RECT  69.721 68.64 69.908 86.664 ;
     RECT  68.825 87.936 69.908 90.408 ;
     RECT  69.781 92.256 69.908 97.464 ;
     RECT  69.437 99.072 69.971 99.192 ;
     RECT  69.908 2.148 70.012 97.464 ;
     RECT  69.971 99.12 70.067 99.192 ;
     RECT  70.012 2.418 70.204 97.464 ;
     RECT  70.204 91.776 70.213 97.464 ;
     RECT  70.213 91.776 70.301 98.04 ;
     RECT  70.067 99.168 70.403 99.192 ;
     RECT  70.204 80.976 70.445 90.312 ;
     RECT  70.204 34.08 70.481 34.968 ;
     RECT  70.445 80.976 70.553 81.96 ;
     RECT  70.301 91.776 70.553 97.992 ;
     RECT  70.553 91.776 70.589 96.936 ;
     RECT  70.204 38.256 70.697 79.56 ;
     RECT  70.204 26.496 70.733 26.664 ;
     RECT  70.445 82.992 70.739 90.312 ;
     RECT  70.697 38.448 70.769 69.288 ;
     RECT  70.769 38.496 70.841 69.288 ;
     RECT  70.739 84.672 70.876 90.312 ;
     RECT  70.841 38.784 70.877 69.288 ;
     RECT  70.876 87.936 70.877 90.312 ;
     RECT  70.577 99.216 70.949 99.24 ;
     RECT  70.877 39.024 70.985 69.288 ;
     RECT  70.589 96.912 71.219 96.936 ;
     RECT  70.589 91.776 71.237 95.928 ;
     RECT  70.985 46.992 71.315 69.288 ;
     RECT  70.553 97.968 71.333 97.992 ;
     RECT  71.333 97.968 71.417 98.04 ;
     RECT  70.985 39.024 71.453 46.008 ;
     RECT  71.315 46.992 71.459 65.208 ;
     RECT  71.315 66.288 71.561 69.288 ;
     RECT  71.459 51.648 71.633 65.208 ;
     RECT  70.553 81.216 71.701 81.96 ;
     RECT  70.739 82.992 71.701 83.208 ;
     RECT  71.417 97.968 71.729 97.992 ;
     RECT  71.701 81.216 71.804 83.208 ;
     RECT  70.876 84.672 71.804 86.76 ;
     RECT  71.804 81.216 71.809 86.76 ;
     RECT  70.877 87.936 71.845 88.152 ;
     RECT  71.845 87.792 71.941 88.152 ;
     RECT  70.877 89.184 71.941 90.072 ;
     RECT  70.481 34.176 71.989 34.968 ;
     RECT  71.941 87.792 72.061 90.072 ;
     RECT  72.061 87.792 72.097 90.12 ;
     RECT  72.097 87.792 72.169 90.312 ;
     RECT  71.809 80.976 72.313 86.76 ;
     RECT  72.169 87.792 72.313 90.36 ;
     RECT  71.237 92.208 72.313 95.928 ;
     RECT  72.313 92.208 72.373 96.024 ;
     RECT  71.729 97.344 72.385 97.992 ;
     RECT  72.373 91.872 72.413 96.024 ;
     RECT  72.385 97.056 72.413 97.992 ;
     RECT  72.413 91.872 72.421 97.992 ;
     RECT  71.453 39.504 72.457 46.008 ;
     RECT  72.373 99.12 72.469 99.144 ;
     RECT  72.457 39.216 72.493 46.008 ;
     RECT  71.459 46.992 72.493 50.568 ;
     RECT  72.421 91.872 72.563 98.088 ;
     RECT  70.697 70.272 72.565 79.56 ;
     RECT  70.733 26.592 72.608 26.664 ;
     RECT  70.204 27.648 72.608 28.248 ;
     RECT  70.204 29.28 72.608 29.304 ;
     RECT  71.989 33.888 72.608 34.968 ;
     RECT  72.493 39.216 72.608 50.568 ;
     RECT  71.633 51.696 72.608 65.208 ;
     RECT  71.561 66.288 72.608 66.6 ;
     RECT  71.561 67.584 72.608 69.288 ;
     RECT  72.565 70.272 72.608 79.752 ;
     RECT  72.313 80.976 72.608 90.36 ;
     RECT  72.563 91.872 72.608 97.464 ;
     RECT  72.608 2.148 72.712 97.464 ;
     RECT  72.712 2.418 72.904 97.464 ;
     RECT  72.904 39.216 72.929 50.664 ;
     RECT  72.469 99.12 72.947 99.192 ;
     RECT  72.904 83.808 72.965 96.264 ;
     RECT  72.904 51.648 73.073 65.208 ;
     RECT  72.947 99.168 73.105 99.192 ;
     RECT  73.073 64.08 73.109 65.208 ;
     RECT  73.105 99.168 73.109 99.288 ;
     RECT  72.929 39.264 73.397 50.664 ;
     RECT  72.965 83.808 73.397 87.816 ;
     RECT  72.965 89.712 73.397 96.264 ;
     RECT  73.109 64.176 73.469 65.208 ;
     RECT  73.397 85.776 73.571 87.816 ;
     RECT  73.571 85.776 73.612 86.952 ;
     RECT  72.904 97.44 73.613 97.464 ;
     RECT  73.397 44.4 73.685 50.664 ;
     RECT  73.397 91.056 73.793 96.264 ;
     RECT  73.109 99.264 73.973 99.288 ;
     RECT  73.793 91.2 74.041 96.264 ;
     RECT  74.041 91.2 74.081 96.888 ;
     RECT  72.904 68.736 74.101 79.752 ;
     RECT  72.904 80.928 74.101 81.096 ;
     RECT  73.612 85.776 74.189 86.04 ;
     RECT  73.397 89.712 74.293 89.736 ;
     RECT  74.101 68.736 74.329 81.096 ;
     RECT  74.329 68.736 74.485 81.192 ;
     RECT  72.904 82.464 74.485 82.824 ;
     RECT  73.397 39.264 74.509 43.416 ;
     RECT  73.685 44.4 74.509 47.88 ;
     RECT  74.341 99.216 74.509 99.24 ;
     RECT  74.293 89.28 74.545 89.736 ;
     RECT  72.904 33.888 74.581 33.912 ;
     RECT  72.904 34.896 74.581 35.208 ;
     RECT  72.904 67.584 74.581 67.608 ;
     RECT  74.485 68.736 74.581 82.824 ;
     RECT  72.904 38.16 74.617 38.184 ;
     RECT  74.509 39.264 74.617 47.88 ;
     RECT  72.904 29.28 74.653 29.304 ;
     RECT  74.509 98.592 74.657 99.24 ;
     RECT  74.581 33.888 74.689 35.208 ;
     RECT  74.081 91.488 74.725 96.888 ;
     RECT  74.581 67.584 74.773 82.824 ;
     RECT  73.397 83.808 74.773 84.696 ;
     RECT  74.617 38.16 74.833 47.88 ;
     RECT  73.685 48.912 74.833 50.664 ;
     RECT  74.689 33.888 75.013 35.304 ;
     RECT  74.833 38.16 75.013 50.664 ;
     RECT  73.073 51.648 75.013 63.048 ;
     RECT  74.657 98.736 75.301 99.24 ;
     RECT  72.904 26.592 75.308 26.664 ;
     RECT  72.904 27.648 75.308 28.248 ;
     RECT  74.653 29.28 75.308 29.592 ;
     RECT  75.013 33.888 75.308 35.544 ;
     RECT  72.904 36.528 75.308 36.552 ;
     RECT  75.013 38.16 75.308 63.048 ;
     RECT  73.469 64.176 75.308 64.2 ;
     RECT  73.469 65.184 75.308 65.208 ;
     RECT  72.904 66.528 75.308 66.6 ;
     RECT  74.773 67.584 75.308 84.696 ;
     RECT  74.189 85.776 75.308 85.8 ;
     RECT  74.545 89.28 75.308 90.216 ;
     RECT  74.725 91.488 75.308 97.416 ;
     RECT  75.308 2.148 75.412 97.416 ;
     RECT  75.412 2.418 75.604 97.416 ;
     RECT  75.604 33.696 75.701 63.144 ;
     RECT  75.604 85.776 75.731 85.8 ;
     RECT  75.604 91.776 75.817 97.416 ;
     RECT  75.301 98.736 75.973 99.288 ;
     RECT  75.817 91.824 76.069 97.416 ;
     RECT  75.973 98.592 76.165 99.288 ;
     RECT  76.165 98.448 76.307 99.288 ;
     RECT  76.307 98.544 76.403 99.288 ;
     RECT  75.604 67.584 76.457 84.696 ;
     RECT  75.604 66.528 76.565 66.6 ;
     RECT  75.701 51.696 76.633 63.144 ;
     RECT  75.604 64.368 76.633 65.208 ;
     RECT  76.457 67.584 76.637 83.016 ;
     RECT  75.701 33.696 76.705 50.664 ;
     RECT  76.633 51.696 76.705 65.208 ;
     RECT  75.604 32.256 76.741 32.328 ;
     RECT  76.705 33.696 76.741 65.208 ;
     RECT  76.069 91.824 77.029 97.464 ;
     RECT  75.604 27.648 77.173 28.248 ;
     RECT  75.604 29.568 77.173 29.592 ;
     RECT  77.173 27.648 77.209 29.592 ;
     RECT  76.741 32.256 77.509 65.208 ;
     RECT  77.209 27.648 77.749 30.216 ;
     RECT  77.509 31.776 77.749 65.208 ;
     RECT  75.604 26.592 78.008 26.664 ;
     RECT  77.749 27.648 78.008 65.208 ;
     RECT  76.565 66.576 78.008 66.6 ;
     RECT  76.637 67.584 78.008 79.56 ;
     RECT  76.637 80.544 78.008 83.016 ;
     RECT  76.457 84.048 78.008 84.696 ;
     RECT  77.029 91.44 78.008 97.464 ;
     RECT  76.403 98.592 78.077 99.288 ;
     RECT  78.008 2.148 78.112 97.464 ;
     RECT  78.112 2.418 78.304 97.464 ;
     RECT  78.304 26.496 78.689 65.208 ;
     RECT  78.689 26.592 78.833 65.208 ;
     RECT  78.304 67.584 78.905 69.288 ;
     RECT  78.304 70.512 79.121 84.696 ;
     RECT  78.304 91.44 79.373 97.464 ;
     RECT  78.077 99.264 79.409 99.288 ;
     RECT  79.373 93.6 79.697 97.464 ;
     RECT  79.697 93.6 79.769 97.176 ;
     RECT  78.833 26.592 79.801 29.592 ;
     RECT  78.833 30.672 79.801 65.208 ;
     RECT  79.801 26.592 80.101 65.208 ;
     RECT  80.101 26.592 80.305 65.352 ;
     RECT  79.121 70.848 80.305 84.696 ;
     RECT  80.305 26.592 80.557 65.448 ;
     RECT  78.304 66.576 80.557 66.6 ;
     RECT  80.557 26.592 80.708 66.6 ;
     RECT  78.905 67.584 80.708 68.424 ;
     RECT  79.621 69.456 80.708 69.48 ;
     RECT  80.305 70.608 80.708 84.696 ;
     RECT  79.373 91.44 80.708 92.472 ;
     RECT  79.769 93.6 80.708 96.672 ;
     RECT  80.708 2.148 80.812 96.672 ;
     RECT  80.812 2.418 80.9 96.672 ;
     RECT  80.9 2.418 81.004 96.942 ;
     RECT  81.004 69.408 81.251 69.48 ;
     RECT  81.004 26.592 81.425 66.6 ;
     RECT  81.004 70.56 81.569 86.616 ;
     RECT  81.004 67.584 81.683 68.424 ;
     RECT  81.569 71.856 81.731 86.616 ;
     RECT  81.425 26.592 82.465 51.72 ;
     RECT  82.465 26.208 82.537 51.72 ;
     RECT  81.731 85.728 82.537 86.616 ;
     RECT  82.393 88.032 82.537 88.056 ;
     RECT  82.537 85.728 82.645 88.056 ;
     RECT  82.069 89.088 82.645 89.112 ;
     RECT  81.569 70.56 82.717 70.872 ;
     RECT  81.731 71.856 82.717 83.016 ;
     RECT  81.731 84.096 82.717 84.696 ;
     RECT  82.717 70.56 82.761 84.696 ;
     RECT  82.645 85.728 82.761 89.112 ;
     RECT  82.537 26.016 82.897 51.72 ;
     RECT  82.897 25.728 83.029 51.72 ;
     RECT  81.425 52.704 83.029 66.6 ;
     RECT  82.597 24.672 83.173 24.696 ;
     RECT  83.029 25.728 83.173 66.6 ;
     RECT  83.173 24.672 83.185 66.6 ;
     RECT  83.185 23.904 83.408 66.6 ;
     RECT  81.683 67.584 83.408 67.608 ;
     RECT  81.251 69.456 83.408 69.48 ;
     RECT  82.761 70.56 83.408 89.112 ;
     RECT  81.004 91.44 83.408 92.472 ;
     RECT  81.004 93.6 83.408 93.816 ;
     RECT  83.408 2.148 83.512 96.672 ;
     RECT  83.512 2.418 83.6 96.672 ;
     RECT  83.6 2.418 83.704 96.942 ;
     RECT  83.704 73.632 84.125 87.144 ;
     RECT  83.704 91.44 84.131 92.472 ;
     RECT  83.704 93.744 84.179 93.816 ;
     RECT  84.125 73.632 84.197 87.096 ;
     RECT  83.704 23.904 84.385 47.448 ;
     RECT  83.704 48.672 84.449 67.32 ;
     RECT  84.385 23.904 84.629 29.112 ;
     RECT  83.704 72.144 84.659 72.36 ;
     RECT  84.385 30.624 84.809 47.448 ;
     RECT  84.179 93.792 84.809 93.816 ;
     RECT  84.659 72.336 84.851 72.36 ;
     RECT  84.449 66.528 84.877 67.32 ;
     RECT  84.877 66.528 84.913 67.8 ;
     RECT  84.809 31.392 84.949 47.448 ;
     RECT  84.449 48.672 84.949 65.208 ;
     RECT  84.913 66.528 85.201 68.424 ;
     RECT  83.704 69.456 85.201 69.48 ;
     RECT  83.704 88.224 85.237 89.208 ;
     RECT  85.237 88.224 85.453 89.448 ;
     RECT  84.949 31.392 85.597 65.208 ;
     RECT  85.201 66.528 85.597 69.48 ;
     RECT  84.629 23.904 85.633 27.096 ;
     RECT  84.629 28.176 85.633 29.112 ;
     RECT  85.633 23.904 85.741 29.112 ;
     RECT  85.597 31.392 85.813 69.48 ;
     RECT  83.704 70.56 85.813 70.872 ;
     RECT  84.197 73.632 85.993 86.472 ;
     RECT  85.453 87.6 85.993 89.448 ;
     RECT  85.741 23.904 86.108 29.544 ;
     RECT  85.813 31.392 86.108 70.872 ;
     RECT  85.993 73.296 86.108 89.448 ;
     RECT  84.131 91.44 86.108 91.896 ;
     RECT  86.108 2.148 86.212 96.672 ;
     RECT  86.212 2.418 86.3 96.672 ;
     RECT  86.3 2.418 86.404 96.942 ;
     RECT  86.404 28.992 86.465 29.544 ;
     RECT  86.404 73.296 86.579 89.448 ;
     RECT  86.465 28.992 86.609 29.016 ;
     RECT  86.579 87.024 86.668 89.448 ;
     RECT  86.404 23.808 86.681 27.096 ;
     RECT  86.579 73.296 86.861 85.752 ;
     RECT  86.404 31.392 86.915 72.264 ;
     RECT  86.668 87.024 86.969 87.864 ;
     RECT  86.915 31.392 87.059 71.16 ;
     RECT  87.059 31.392 87.113 66.696 ;
     RECT  87.113 31.392 87.365 65.4 ;
     RECT  86.969 87.84 87.437 87.864 ;
     RECT  86.915 72.24 87.613 72.264 ;
     RECT  86.861 73.296 87.613 83.832 ;
     RECT  86.861 84.96 87.901 85.752 ;
     RECT  86.681 23.904 88.081 27.096 ;
     RECT  87.113 66.528 88.117 66.696 ;
     RECT  87.059 67.728 88.117 71.16 ;
     RECT  87.613 72.24 88.225 83.832 ;
     RECT  88.081 23.376 88.261 27.096 ;
     RECT  87.365 31.68 88.261 65.4 ;
     RECT  88.117 66.528 88.261 71.16 ;
     RECT  88.261 31.68 88.268 71.16 ;
     RECT  88.225 72.24 88.268 83.88 ;
     RECT  88.261 21.504 88.309 21.528 ;
     RECT  88.369 20.352 88.621 20.376 ;
     RECT  88.621 20.352 88.693 20.424 ;
     RECT  88.309 21.504 88.693 21.816 ;
     RECT  88.268 31.68 88.693 83.88 ;
     RECT  87.901 84.96 88.693 85.944 ;
     RECT  88.693 20.352 88.808 21.816 ;
     RECT  88.261 22.8 88.808 27.096 ;
     RECT  88.693 31.68 88.808 85.944 ;
     RECT  86.668 88.896 88.808 89.448 ;
     RECT  86.404 91.44 88.808 91.464 ;
     RECT  88.808 2.148 88.912 96.672 ;
     RECT  88.912 2.418 89 96.672 ;
     RECT  89 2.418 89.104 96.942 ;
     RECT  89.104 81.648 89.129 81.72 ;
     RECT  89.104 30.624 89.219 80.664 ;
     RECT  89.104 82.992 89.219 89.448 ;
     RECT  89.219 46.752 89.417 80.664 ;
     RECT  89.129 81.696 89.525 81.72 ;
     RECT  89.417 46.896 89.561 80.664 ;
     RECT  89.561 46.896 89.849 59.784 ;
     RECT  89.219 88.848 89.954 89.448 ;
     RECT  89.219 30.624 90.083 45.72 ;
     RECT  89.104 91.44 90.227 91.464 ;
     RECT  89.561 60.864 90.353 80.664 ;
     RECT  89.219 82.992 90.565 86.616 ;
     RECT  89.849 46.944 90.601 59.784 ;
     RECT  90.083 30.624 90.637 30.936 ;
     RECT  90.565 29.232 90.745 29.256 ;
     RECT  90.637 30.432 90.745 30.936 ;
     RECT  90.353 72.816 90.925 80.664 ;
     RECT  90.86 81.792 90.925 81.816 ;
     RECT  90.565 82.992 90.949 86.76 ;
     RECT  89.954 88.848 90.949 89.4 ;
     RECT  90.083 31.92 90.961 45.72 ;
     RECT  90.601 46.944 90.961 59.88 ;
     RECT  90.745 29.232 91.465 30.936 ;
     RECT  90.961 31.92 91.465 59.88 ;
     RECT  89.104 20.352 91.508 27.096 ;
     RECT  91.465 29.232 91.508 59.88 ;
     RECT  90.353 60.864 91.508 71.832 ;
     RECT  90.925 72.816 91.508 81.816 ;
     RECT  90.949 82.992 91.508 87.144 ;
     RECT  90.949 88.512 91.508 89.4 ;
     RECT  91.508 2.148 91.612 96.672 ;
     RECT  91.612 2.418 91.7 96.672 ;
     RECT  91.7 2.418 91.804 96.942 ;
     RECT  91.804 20.352 91.955 27.336 ;
     RECT  91.804 51.408 91.981 59.64 ;
     RECT  91.804 84.96 92.045 87.528 ;
     RECT  92.045 84.96 92.117 85.512 ;
     RECT  91.955 20.352 92.339 26.28 ;
     RECT  92.117 84.96 92.369 85.128 ;
     RECT  91.804 60.624 92.513 80.904 ;
     RECT  92.045 87.408 92.513 87.528 ;
     RECT  92.513 87.408 92.549 87.432 ;
     RECT  92.513 66 92.613 80.904 ;
     RECT  91.804 47.328 92.723 49.704 ;
     RECT  91.804 29.232 92.765 45.288 ;
     RECT  92.723 47.904 92.797 49.704 ;
     RECT  91.955 27.312 92.837 27.336 ;
     RECT  92.797 47.904 92.873 49.8 ;
     RECT  92.873 48.24 92.941 49.8 ;
     RECT  92.369 84.96 92.945 84.984 ;
     RECT  91.804 82.08 92.977 83.88 ;
     RECT  92.941 48.24 93.017 50.184 ;
     RECT  92.977 82.08 93.089 84.36 ;
     RECT  91.981 51.408 93.337 59.256 ;
     RECT  92.513 60.624 93.337 64.92 ;
     RECT  92.613 66.24 93.373 80.904 ;
     RECT  93.089 82.08 93.373 83.304 ;
     RECT  93.337 51.408 93.596 64.92 ;
     RECT  93.373 66.24 93.637 83.304 ;
     RECT  92.339 20.352 93.925 26.136 ;
     RECT  93.925 20.112 94.021 26.136 ;
     RECT  93.596 51.408 94.069 64.968 ;
     RECT  93.637 66.192 94.069 83.304 ;
     RECT  94.021 19.824 94.208 26.136 ;
     RECT  92.765 29.232 94.208 45.24 ;
     RECT  93.017 48.672 94.208 50.184 ;
     RECT  94.069 51.408 94.208 83.304 ;
     RECT  93.089 84.336 94.208 84.36 ;
     RECT  94.208 2.148 94.312 96.672 ;
     RECT  94.312 2.418 94.4 96.672 ;
     RECT  94.4 2.418 94.504 96.942 ;
     RECT  94.504 19.824 94.637 26.136 ;
     RECT  94.504 28.896 94.673 45.24 ;
     RECT  94.504 51.408 94.673 64.872 ;
     RECT  94.504 67.632 94.691 82.296 ;
     RECT  94.504 66.576 94.889 66.6 ;
     RECT  94.637 19.92 95.497 26.136 ;
     RECT  94.673 51.456 95.701 64.872 ;
     RECT  94.691 77.52 95.821 82.296 ;
     RECT  95.701 51.024 95.989 64.872 ;
     RECT  94.504 48.672 96.277 50.04 ;
     RECT  94.691 67.632 96.353 76.488 ;
     RECT  96.277 48.432 96.469 50.04 ;
     RECT  95.497 19.92 96.505 26.808 ;
     RECT  94.673 28.896 96.505 45.192 ;
     RECT  95.989 51.024 96.505 65.016 ;
     RECT  96.353 67.632 96.517 76.536 ;
     RECT  95.821 77.52 96.517 83.256 ;
     RECT  96.469 48.336 96.709 50.04 ;
     RECT  96.505 51.024 96.709 65.592 ;
     RECT  96.505 19.92 96.908 45.192 ;
     RECT  96.709 48.336 96.908 65.592 ;
     RECT  96.517 67.632 96.908 83.256 ;
     RECT  95.965 84.384 96.908 84.408 ;
     RECT  96.908 2.148 97.012 96.672 ;
     RECT  97.012 81.6 97.139 82.2 ;
     RECT  97.139 82.176 97.475 82.2 ;
     RECT  97.012 67.632 98.017 76.392 ;
     RECT  97.012 77.52 98.017 80.568 ;
     RECT  98.017 67.632 98.557 80.568 ;
     RECT  98.557 67.536 98.633 80.568 ;
     RECT  97.012 19.92 99.276 45.192 ;
     RECT  97.012 48.336 99.276 64.872 ;
     RECT  98.633 67.536 99.276 80.52 ;
     RECT  99.276 20.832 99.317 20.856 ;
     RECT  99.276 30.048 99.317 30.072 ;
     RECT  99.276 34.464 99.317 34.488 ;
     RECT  99.276 41.376 99.317 41.4 ;
     RECT  99.276 53.088 99.317 53.112 ;
     RECT  99.276 54.72 99.317 54.744 ;
     RECT  99.276 57.552 99.317 57.576 ;
     RECT  99.276 61.44 99.317 61.464 ;
    LAYER M5 ;
     RECT  2.4 2.137 2.52 2.151 ;
     RECT  5.1 2.137 5.22 2.151 ;
     RECT  7.8 2.137 7.92 2.151 ;
     RECT  10.5 2.137 10.62 2.151 ;
     RECT  13.2 2.137 13.32 2.151 ;
     RECT  15.9 2.137 16.02 2.151 ;
     RECT  18.6 2.137 18.72 2.151 ;
     RECT  21.3 2.137 21.42 2.151 ;
     RECT  24 2.137 24.12 2.151 ;
     RECT  26.7 2.137 26.82 2.151 ;
     RECT  29.4 2.137 29.52 2.151 ;
     RECT  32.1 2.137 32.22 2.151 ;
     RECT  34.8 2.137 34.92 2.151 ;
     RECT  37.5 2.137 37.62 2.151 ;
     RECT  40.2 2.137 40.32 2.151 ;
     RECT  42.9 2.137 43.02 2.151 ;
     RECT  45.6 2.137 45.72 2.151 ;
     RECT  48.3 2.137 48.42 2.151 ;
     RECT  51 2.137 51.12 2.151 ;
     RECT  53.7 2.137 53.82 2.151 ;
     RECT  56.4 2.137 56.52 2.151 ;
     RECT  59.1 2.137 59.22 2.151 ;
     RECT  61.8 2.137 61.92 2.151 ;
     RECT  64.5 2.137 64.62 2.151 ;
     RECT  67.2 2.137 67.32 2.151 ;
     RECT  69.9 2.137 70.02 2.151 ;
     RECT  72.6 2.137 72.72 2.151 ;
     RECT  75.3 2.137 75.42 2.151 ;
     RECT  78 2.137 78.12 2.151 ;
     RECT  80.7 2.137 80.82 2.151 ;
     RECT  83.4 2.137 83.52 2.151 ;
     RECT  86.1 2.137 86.22 2.151 ;
     RECT  88.8 2.137 88.92 2.151 ;
     RECT  91.5 2.137 91.62 2.151 ;
     RECT  94.2 2.137 94.32 2.151 ;
     RECT  94.2 2.151 94.512 19.813 ;
     RECT  94.032 19.813 94.512 20.101 ;
     RECT  93.936 20.101 94.512 20.581 ;
     RECT  93.888 20.581 94.512 20.677 ;
     RECT  95.712 20.341 95.736 20.677 ;
     RECT  88.8 2.151 89.112 21.109 ;
     RECT  88.704 21.109 89.112 21.205 ;
     RECT  88.704 21.205 89.496 21.493 ;
     RECT  91.5 2.151 91.812 21.493 ;
     RECT  90.624 21.493 91.812 21.635 ;
     RECT  93.888 20.677 95.736 21.827 ;
     RECT  94.08 21.827 95.736 22.259 ;
     RECT  91.5 21.635 91.812 22.741 ;
     RECT  88.272 21.493 89.496 22.835 ;
     RECT  94.2 22.259 95.16 22.835 ;
     RECT  88.32 22.835 89.496 23.029 ;
     RECT  91.2 22.741 91.812 23.077 ;
     RECT  91.056 23.077 91.812 23.365 ;
     RECT  88.32 23.029 90.072 23.411 ;
     RECT  88.8 23.411 90.072 23.653 ;
     RECT  91.056 23.365 92.328 23.653 ;
     RECT  83.4 2.151 83.712 24.085 ;
     RECT  94.2 22.835 94.512 24.085 ;
     RECT  94.2 24.085 94.632 24.467 ;
     RECT  83.28 24.085 83.712 24.661 ;
     RECT  94.2 24.467 94.512 24.709 ;
     RECT  84.912 24.421 84.936 25.139 ;
     RECT  88.8 23.653 92.328 25.139 ;
     RECT  94.032 24.709 94.512 25.715 ;
     RECT  86.1 2.151 86.412 25.813 ;
     RECT  86.1 25.813 86.664 26.051 ;
     RECT  90.624 25.139 92.328 26.099 ;
     RECT  96.9 2.137 97.02 26.149 ;
     RECT  96.384 26.149 97.02 26.197 ;
     RECT  82.608 24.661 83.712 26.243 ;
     RECT  91.008 26.099 92.328 26.291 ;
     RECT  88.8 25.139 89.64 26.819 ;
     RECT  91.008 26.291 91.944 26.819 ;
     RECT  95.664 26.197 97.02 26.819 ;
     RECT  91.008 26.819 91.812 26.867 ;
     RECT  82.704 26.243 83.712 27.061 ;
     RECT  80.7 2.151 81.012 27.589 ;
     RECT  86.1 26.051 86.412 27.877 ;
     RECT  82.704 27.061 84.36 28.213 ;
     RECT  53.7 2.151 54.012 28.261 ;
     RECT  56.4 2.151 56.712 28.453 ;
     RECT  82.656 28.213 84.36 28.499 ;
     RECT  85.776 27.877 86.412 29.123 ;
     RECT  56.4 28.453 56.808 29.363 ;
     RECT  83.232 28.499 84.36 29.605 ;
     RECT  82.512 29.605 84.36 29.699 ;
     RECT  96.384 26.819 97.02 29.699 ;
     RECT  55.008 28.789 55.032 29.891 ;
     RECT  94.2 25.715 94.512 29.989 ;
     RECT  78 2.151 78.312 30.085 ;
     RECT  64.5 2.151 64.812 30.181 ;
     RECT  53.568 28.261 54.012 30.227 ;
     RECT  80.7 27.589 81.144 30.227 ;
     RECT  96.768 29.699 97.02 30.275 ;
     RECT  96.9 30.275 97.02 30.469 ;
     RECT  56.4 29.363 56.712 30.613 ;
     RECT  88.8 26.819 89.112 30.613 ;
     RECT  96.9 30.469 97.32 30.659 ;
     RECT  55.632 30.613 56.712 30.709 ;
     RECT  82.512 29.699 84.072 30.803 ;
     RECT  52.416 29.365 52.44 30.851 ;
     RECT  94.2 29.989 95.16 30.851 ;
     RECT  80.7 30.227 81.012 30.949 ;
     RECT  53.7 30.227 54.012 31.237 ;
     RECT  88.8 30.613 90.072 31.379 ;
     RECT  69.9 2.151 70.212 31.381 ;
     RECT  63.792 30.181 64.812 31.427 ;
     RECT  94.2 30.851 94.512 31.429 ;
     RECT  96.9 30.659 97.02 31.525 ;
     RECT  98.592 30.757 98.616 31.619 ;
     RECT  77.76 30.085 78.312 31.717 ;
     RECT  53.7 31.237 54.456 31.765 ;
     RECT  61.8 2.151 62.112 31.765 ;
     RECT  77.76 31.717 78.6 31.765 ;
     RECT  86.1 29.123 86.412 31.765 ;
     RECT  53.568 31.765 54.456 31.861 ;
     RECT  55.632 30.709 57.192 31.861 ;
     RECT  59.1 2.151 59.412 31.861 ;
     RECT  88.8 31.379 89.496 31.955 ;
     RECT  75.3 2.151 75.612 32.245 ;
     RECT  75.3 32.245 75.864 32.293 ;
     RECT  77.52 31.765 78.6 32.293 ;
     RECT  61.8 31.765 63.048 32.437 ;
     RECT  88.8 31.955 89.112 32.437 ;
     RECT  79.728 30.949 81.012 32.483 ;
     RECT  96.288 31.525 97.02 32.531 ;
     RECT  91.5 26.867 91.812 32.725 ;
     RECT  93.408 31.429 94.512 32.725 ;
     RECT  53.568 31.861 57.192 32.771 ;
     RECT  58.224 31.861 59.412 33.013 ;
     RECT  82.512 30.803 83.712 33.013 ;
     RECT  91.5 32.725 94.512 33.013 ;
     RECT  96.768 32.531 97.02 33.155 ;
     RECT  84.912 32.485 84.936 33.493 ;
     RECT  88.272 32.437 89.112 33.541 ;
     RECT  61.8 32.437 63.144 33.587 ;
     RECT  90.576 33.013 94.512 33.587 ;
     RECT  61.8 33.587 63.048 33.589 ;
     RECT  64.5 31.427 64.812 33.589 ;
     RECT  75.3 32.293 78.6 33.589 ;
     RECT  79.776 32.483 81.012 33.589 ;
     RECT  87.552 33.541 89.112 33.637 ;
     RECT  84.816 33.493 84.936 33.781 ;
     RECT  84.816 33.781 85.08 33.923 ;
     RECT  82.032 33.013 83.712 34.067 ;
     RECT  69.792 31.381 70.212 34.069 ;
     RECT  86.1 31.765 86.52 34.069 ;
     RECT  87.552 33.637 90.072 34.069 ;
     RECT  58.224 33.013 59.832 34.115 ;
     RECT  86.1 34.069 90.072 34.115 ;
     RECT  91.344 33.587 94.512 34.163 ;
     RECT  86.1 34.115 90.024 34.165 ;
     RECT  84.816 33.923 84.936 34.355 ;
     RECT  91.392 34.163 94.512 34.403 ;
     RECT  96.9 33.155 97.02 34.597 ;
     RECT  75.3 33.589 81.012 34.693 ;
     RECT  96.9 34.597 97.128 34.739 ;
     RECT  82.224 34.067 83.712 34.933 ;
     RECT  85.968 34.165 90.024 34.933 ;
     RECT  85.872 34.933 90.024 35.267 ;
     RECT  91.5 34.403 94.512 35.413 ;
     RECT  64.5 33.589 64.92 35.459 ;
     RECT  53.7 32.771 57.192 35.461 ;
     RECT  58.224 34.115 59.412 35.461 ;
     RECT  96.9 34.739 97.02 35.461 ;
     RECT  96.768 35.461 97.02 35.701 ;
     RECT  82.224 34.933 84.216 35.845 ;
     RECT  60.912 33.589 63.048 35.939 ;
     RECT  91.5 35.413 95.064 35.939 ;
     RECT  92.784 35.939 95.064 35.941 ;
     RECT  51 2.151 51.312 36.229 ;
     RECT  52.464 35.317 52.488 36.229 ;
     RECT  51 36.229 52.488 36.275 ;
     RECT  67.2 2.151 67.512 36.373 ;
     RECT  92.784 35.941 95.16 36.515 ;
     RECT  92.784 36.515 92.808 36.611 ;
     RECT  32.1 2.151 32.412 36.901 ;
     RECT  64.5 35.459 64.812 36.901 ;
     RECT  85.968 35.267 90.024 36.949 ;
     RECT  93.984 36.515 95.16 37.091 ;
     RECT  74.592 34.693 81.012 37.139 ;
     RECT  29.4 2.151 29.712 37.189 ;
     RECT  31.2 36.901 32.412 37.619 ;
     RECT  64.5 36.901 64.92 37.619 ;
     RECT  82.224 35.845 84.456 37.621 ;
     RECT  85.968 36.949 90.072 37.621 ;
     RECT  82.224 37.621 90.072 37.907 ;
     RECT  53.7 35.461 59.412 38.005 ;
     RECT  60.912 35.939 63 38.005 ;
     RECT  51 36.275 52.296 38.099 ;
     RECT  91.5 35.939 91.812 38.101 ;
     RECT  94.2 37.091 95.112 38.101 ;
     RECT  96.192 35.701 97.02 38.101 ;
     RECT  48.3 2.151 48.612 38.149 ;
     RECT  90.672 38.101 91.812 38.149 ;
     RECT  92.832 38.053 92.856 38.149 ;
     RECT  90.672 38.149 92.856 38.243 ;
     RECT  40.2 2.151 40.512 38.581 ;
     RECT  82.224 37.907 89.112 38.627 ;
     RECT  53.7 38.005 63 38.677 ;
     RECT  64.5 37.619 64.812 38.677 ;
     RECT  37.5 2.151 37.812 38.725 ;
     RECT  45.6 2.151 45.912 38.725 ;
     RECT  51 38.099 51.72 38.773 ;
     RECT  31.056 38.005 31.08 38.819 ;
     RECT  82.224 38.627 87.192 38.819 ;
     RECT  94.2 38.101 97.02 38.819 ;
     RECT  40.08 38.581 40.512 39.059 ;
     RECT  29.28 37.189 29.712 39.109 ;
     RECT  69.696 34.069 70.212 39.203 ;
     RECT  79.824 37.139 81.012 39.205 ;
     RECT  82.224 38.819 86.52 39.251 ;
     RECT  67.104 36.373 67.512 39.253 ;
     RECT  50.688 38.773 51.72 39.299 ;
     RECT  37.5 38.725 37.944 39.347 ;
     RECT  33.6 38.677 33.624 39.395 ;
     RECT  52.992 38.677 63 39.395 ;
     RECT  96.192 38.819 97.02 39.395 ;
     RECT  45.6 38.725 46.248 39.491 ;
     RECT  79.824 39.205 81.144 39.493 ;
     RECT  96.288 39.395 97.02 39.493 ;
     RECT  53.7 39.395 63 39.539 ;
     RECT  69.744 39.203 70.212 39.539 ;
     RECT  34.8 2.151 35.112 39.541 ;
     RECT  94.2 38.819 94.512 39.589 ;
     RECT  96.288 39.493 97.224 39.635 ;
     RECT  42.9 2.151 43.212 39.733 ;
     RECT  48.192 38.149 48.612 39.781 ;
     RECT  79.824 39.493 81.192 39.877 ;
     RECT  82.8 39.251 86.52 39.877 ;
     RECT  88.224 38.627 89.112 39.877 ;
     RECT  53.7 39.539 62.112 39.923 ;
     RECT  87.648 39.877 89.112 40.115 ;
     RECT  90.672 38.243 92.76 40.115 ;
     RECT  42.9 39.733 43.704 40.165 ;
     RECT  90.672 40.115 92.376 40.259 ;
     RECT  98.592 40.069 98.616 40.259 ;
     RECT  79.68 39.877 81.192 40.357 ;
     RECT  82.8 39.877 86.664 40.357 ;
     RECT  45.6 39.491 46.008 40.499 ;
     RECT  79.68 40.357 86.664 40.691 ;
     RECT  53.7 39.923 59.412 40.933 ;
     RECT  60.912 39.923 62.112 40.933 ;
     RECT  96.288 39.635 97.02 40.933 ;
     RECT  29.088 39.109 29.712 40.981 ;
     RECT  40.2 39.059 40.512 40.981 ;
     RECT  74.592 37.139 78.6 40.981 ;
     RECT  79.68 40.691 86.412 40.981 ;
     RECT  29.088 40.981 30.36 41.075 ;
     RECT  74.592 40.981 86.412 41.075 ;
     RECT  94.08 39.589 94.512 41.075 ;
     RECT  90.672 40.259 91.812 41.173 ;
     RECT  88.224 40.115 89.112 41.269 ;
     RECT  88.224 41.269 89.208 41.317 ;
     RECT  90.624 41.173 91.812 41.317 ;
     RECT  64.5 38.677 65.688 41.365 ;
     RECT  94.2 41.075 94.512 41.413 ;
     RECT  82.752 41.075 86.412 41.459 ;
     RECT  51 39.299 51.72 41.461 ;
     RECT  51 41.461 52.2 41.509 ;
     RECT  53.7 40.933 62.112 41.509 ;
     RECT  63.888 41.365 65.688 41.555 ;
     RECT  48.048 39.781 48.612 41.603 ;
     RECT  74.592 41.075 79.176 41.651 ;
     RECT  29.4 41.075 30.36 41.699 ;
     RECT  42.9 40.165 44.472 41.699 ;
     RECT  53.184 41.509 62.112 41.795 ;
     RECT  69.792 39.539 70.212 41.797 ;
     RECT  64.5 41.555 65.688 41.941 ;
     RECT  66.72 39.253 67.512 41.941 ;
     RECT  94.2 41.413 94.68 41.989 ;
     RECT  88.224 41.317 91.812 42.083 ;
     RECT  88.224 42.083 90.072 42.133 ;
     RECT  53.184 41.795 59.412 42.179 ;
     RECT  42.9 41.699 43.704 42.181 ;
     RECT  72.6 2.151 72.912 42.181 ;
     RECT  80.7 41.075 81.192 42.227 ;
     RECT  95.712 40.933 97.02 42.227 ;
     RECT  94.2 41.989 94.728 42.323 ;
     RECT  68.976 41.797 70.212 42.565 ;
     RECT  45.6 40.499 45.912 42.613 ;
     RECT  82.8 41.459 86.412 42.755 ;
     RECT  34.224 39.541 35.112 42.757 ;
     RECT  42.672 42.181 43.704 42.803 ;
     RECT  95.712 42.227 95.736 42.803 ;
     RECT  40.08 40.981 40.512 42.995 ;
     RECT  91.5 42.083 91.812 43.045 ;
     RECT  72.24 42.181 72.912 43.237 ;
     RECT  68.832 42.565 70.212 43.283 ;
     RECT  34.224 42.757 35.832 43.331 ;
     RECT  37.5 39.347 37.812 43.333 ;
     RECT  88.176 42.133 90.072 43.379 ;
     RECT  50.88 41.509 52.2 43.525 ;
     RECT  72.24 43.237 73.56 43.571 ;
     RECT  88.176 43.379 89.112 43.571 ;
     RECT  37.152 43.333 37.812 43.621 ;
     RECT  50.832 43.525 52.2 43.621 ;
     RECT  29.4 41.699 29.712 43.813 ;
     RECT  91.152 43.045 91.812 43.813 ;
     RECT  32.1 37.619 32.412 43.861 ;
     RECT  48.3 41.603 48.612 43.861 ;
     RECT  50.784 43.621 52.2 43.861 ;
     RECT  53.7 42.179 59.412 43.861 ;
     RECT  80.7 42.227 81.144 43.861 ;
     RECT  82.8 42.755 84.168 43.861 ;
     RECT  80.7 43.861 84.168 44.003 ;
     RECT  90.624 43.813 91.812 44.147 ;
     RECT  31.824 43.861 32.412 44.149 ;
     RECT  96.9 42.227 97.02 44.149 ;
     RECT  96.9 44.149 97.128 44.339 ;
     RECT  60.912 41.795 62.112 44.389 ;
     RECT  90.768 44.147 91.812 44.389 ;
     RECT  92.88 43.285 92.904 44.389 ;
     RECT  88.224 43.571 89.112 44.437 ;
     RECT  34.656 43.331 35.832 44.579 ;
     RECT  37.152 43.621 38.472 44.579 ;
     RECT  45.6 42.613 46.104 44.723 ;
     RECT  50.16 43.861 52.2 44.773 ;
     RECT  53.28 43.861 59.412 44.773 ;
     RECT  31.824 44.149 33.384 44.915 ;
     RECT  50.16 44.773 59.412 44.917 ;
     RECT  60.912 44.389 62.76 44.917 ;
     RECT  50.16 44.917 62.76 44.963 ;
     RECT  82.8 44.003 84.168 44.965 ;
     RECT  85.296 42.755 86.412 44.965 ;
     RECT  72.6 43.571 73.56 45.059 ;
     RECT  34.656 44.579 35.208 45.299 ;
     RECT  42.672 42.803 43.212 45.299 ;
     RECT  51 44.963 62.76 45.539 ;
     RECT  40.2 42.995 40.512 45.541 ;
     RECT  42.9 45.299 43.212 45.589 ;
     RECT  69.792 43.283 70.212 45.731 ;
     RECT  90.768 44.389 92.904 45.731 ;
     RECT  42.9 45.589 43.704 45.827 ;
     RECT  47.52 43.861 48.612 45.877 ;
     RECT  51 45.539 59.412 45.973 ;
     RECT  64.5 41.941 67.512 45.973 ;
     RECT  60.384 45.539 62.76 46.115 ;
     RECT  74.592 41.651 78.6 46.501 ;
     RECT  40.08 45.541 40.512 46.595 ;
     RECT  64.08 45.973 67.512 46.643 ;
     RECT  72.6 45.059 73.032 46.835 ;
     RECT  29.4 43.813 29.976 47.075 ;
     RECT  60.384 46.115 62.112 47.125 ;
     RECT  47.328 45.877 48.612 47.269 ;
     RECT  88.224 44.437 89.208 47.317 ;
     RECT  66.72 46.643 67.512 47.363 ;
     RECT  64.08 46.643 65.688 47.651 ;
     RECT  50.304 45.973 59.412 47.701 ;
     RECT  60.384 47.125 62.808 47.701 ;
     RECT  74.592 46.501 78.936 47.701 ;
     RECT  37.5 44.579 38.472 47.845 ;
     RECT  34.656 45.299 35.112 47.891 ;
     RECT  82.8 44.965 86.412 47.891 ;
     RECT  45.6 44.723 45.912 47.893 ;
     RECT  46.992 47.269 48.612 47.893 ;
     RECT  44.784 47.893 48.612 47.939 ;
     RECT  91.5 45.731 92.904 47.987 ;
     RECT  29.4 47.075 29.712 48.229 ;
     RECT  83.04 47.891 86.412 48.277 ;
     RECT  37.5 47.845 38.664 48.373 ;
     RECT  37.5 48.373 38.808 48.421 ;
     RECT  40.2 46.595 40.512 48.421 ;
     RECT  50.304 47.701 62.808 48.421 ;
     RECT  96.9 44.339 97.02 48.421 ;
     RECT  88.224 47.317 89.544 48.515 ;
     RECT  32.1 44.915 33.384 48.709 ;
     RECT  96.288 48.421 97.02 48.709 ;
     RECT  64.08 47.651 64.812 48.757 ;
     RECT  65.808 48.469 65.832 48.757 ;
     RECT  49.92 48.421 62.808 48.803 ;
     RECT  30.768 48.229 30.792 48.901 ;
     RECT  32.1 48.709 33.432 48.901 ;
     RECT  64.08 48.757 65.832 48.901 ;
     RECT  66.816 47.363 67.512 48.901 ;
     RECT  68.736 47.605 68.76 48.901 ;
     RECT  69.9 45.731 70.212 48.901 ;
     RECT  74.592 47.701 79.032 48.901 ;
     RECT  30.768 48.901 33.432 48.947 ;
     RECT  80.7 44.003 81.012 48.949 ;
     RECT  72.6 46.835 72.912 48.997 ;
     RECT  64.08 48.901 67.512 49.043 ;
     RECT  68.736 48.901 70.212 49.043 ;
     RECT  92.88 47.987 92.904 49.043 ;
     RECT  44.784 47.939 46.2 49.091 ;
     RECT  65.808 49.043 67.512 49.091 ;
     RECT  72.144 48.997 72.912 49.141 ;
     RECT  34.8 47.891 35.112 49.189 ;
     RECT  42.9 45.827 43.32 49.285 ;
     RECT  42.768 49.285 43.32 49.331 ;
     RECT  71.856 49.141 72.912 49.381 ;
     RECT  49.92 48.803 59.412 49.475 ;
     RECT  68.736 49.043 68.76 49.475 ;
     RECT  60.672 48.803 62.808 49.477 ;
     RECT  64.08 49.043 64.812 49.477 ;
     RECT  83.04 48.277 86.568 49.477 ;
     RECT  88.224 48.515 89.4 49.523 ;
     RECT  47.424 47.939 48.612 49.525 ;
     RECT  94.2 42.323 94.512 49.525 ;
     RECT  29.28 48.229 29.712 49.619 ;
     RECT  66.672 49.091 67.512 49.619 ;
     RECT  80.7 48.949 81.528 49.619 ;
     RECT  96.24 48.709 97.02 49.619 ;
     RECT  37.5 48.421 40.512 49.813 ;
     RECT  74.304 48.901 79.032 49.861 ;
     RECT  34.8 49.189 35.304 50.051 ;
     RECT  60.672 49.477 64.812 50.101 ;
     RECT  71.808 49.381 72.912 50.101 ;
     RECT  31.536 48.947 33.432 50.147 ;
     RECT  93.456 49.525 94.512 50.195 ;
     RECT  47.376 49.525 48.612 50.339 ;
     RECT  71.424 50.101 72.912 50.387 ;
     RECT  91.5 47.987 91.812 50.437 ;
     RECT  69.9 49.043 70.212 50.629 ;
     RECT  36.72 49.813 40.512 50.771 ;
     RECT  60.384 50.101 64.812 50.819 ;
     RECT  71.424 50.387 71.448 50.819 ;
     RECT  96.768 49.619 97.02 50.821 ;
     RECT  60.384 50.819 62.112 51.107 ;
     RECT  90.864 50.437 91.812 51.109 ;
     RECT  74.304 49.861 79.224 51.155 ;
     RECT  95.712 51.013 95.736 51.205 ;
     RECT  96.72 50.821 97.02 51.205 ;
     RECT  44.784 49.091 45.912 51.397 ;
     RECT  98.592 50.821 98.616 51.587 ;
     RECT  69.504 50.629 70.212 51.589 ;
     RECT  90.72 51.109 91.812 51.635 ;
     RECT  68.976 51.589 70.212 51.731 ;
     RECT  34.8 50.051 35.112 51.733 ;
     RECT  42.768 49.331 43.212 51.829 ;
     RECT  44.784 51.397 46.44 51.829 ;
     RECT  66.816 49.619 67.512 51.923 ;
     RECT  50.016 49.475 59.412 52.019 ;
     RECT  94.2 50.195 94.512 52.021 ;
     RECT  95.712 51.205 97.02 52.021 ;
     RECT  34.8 51.733 35.256 52.165 ;
     RECT  94.032 52.021 94.512 52.165 ;
     RECT  95.712 52.021 97.32 52.211 ;
     RECT  60.672 51.107 62.112 52.261 ;
     RECT  50.304 52.019 59.412 52.405 ;
     RECT  60.384 52.261 62.112 52.405 ;
     RECT  93.456 52.165 94.512 52.405 ;
     RECT  95.712 52.211 97.128 52.499 ;
     RECT  93.408 52.405 94.512 52.501 ;
     RECT  83.04 49.477 86.616 52.691 ;
     RECT  83.4 52.691 86.616 52.787 ;
     RECT  96.672 52.499 97.128 52.979 ;
     RECT  50.304 52.405 62.112 52.981 ;
     RECT  93.36 52.501 94.512 52.981 ;
     RECT  30.816 52.165 30.84 53.027 ;
     RECT  49.68 52.981 62.112 53.029 ;
     RECT  63.12 50.819 64.812 53.029 ;
     RECT  80.7 49.619 81.012 53.029 ;
     RECT  96.672 52.979 97.02 53.075 ;
     RECT  24 2.151 24.312 53.269 ;
     RECT  0.192 53.317 0.216 53.413 ;
     RECT  83.4 52.787 86.52 53.459 ;
     RECT  29.4 49.619 29.712 53.557 ;
     RECT  34.8 52.165 35.352 53.603 ;
     RECT  88.224 49.523 89.112 53.797 ;
     RECT  42.768 51.829 46.44 53.843 ;
     RECT  39.648 50.771 40.512 53.893 ;
     RECT  93.312 52.981 94.512 53.893 ;
     RECT  34.8 53.603 35.256 53.939 ;
     RECT  49.68 53.029 64.812 53.941 ;
     RECT  32.1 50.147 33.432 53.989 ;
     RECT  34.8 53.939 35.112 53.989 ;
     RECT  87.696 53.797 89.112 54.037 ;
     RECT  36.72 50.771 38.664 54.085 ;
     RECT  39.648 53.893 41.064 54.085 ;
     RECT  67.2 51.923 67.512 54.085 ;
     RECT  72.6 50.387 72.912 54.085 ;
     RECT  74.304 51.155 79.032 54.085 ;
     RECT  93.312 53.893 94.872 54.085 ;
     RECT  36.72 54.085 41.64 54.131 ;
     RECT  49.68 53.941 64.92 54.179 ;
     RECT  93.312 54.085 95.16 54.179 ;
     RECT  80.592 53.029 81.012 54.325 ;
     RECT  87.696 54.037 89.352 54.325 ;
     RECT  80.592 54.325 81.432 54.371 ;
     RECT  40.08 54.131 41.64 54.373 ;
     RECT  72.6 54.085 79.032 54.707 ;
     RECT  24 53.269 24.552 54.755 ;
     RECT  49.68 54.179 62.112 54.755 ;
     RECT  93.408 54.179 95.16 54.803 ;
     RECT  42.768 53.843 43.212 54.853 ;
     RECT  83.4 53.459 86.412 54.901 ;
     RECT  87.696 54.325 89.496 54.901 ;
     RECT  48.3 50.339 48.612 54.997 ;
     RECT  72.6 54.707 73.032 54.997 ;
     RECT  80.7 54.371 81.432 55.139 ;
     RECT  69.168 51.731 70.212 55.141 ;
     RECT  67.2 54.085 67.704 55.187 ;
     RECT  72.336 54.997 73.032 55.187 ;
     RECT  91.5 51.635 91.812 55.189 ;
     RECT  74.064 54.707 79.032 55.331 ;
     RECT  94.032 54.803 94.512 55.331 ;
     RECT  29.28 53.557 29.712 55.427 ;
     RECT  83.4 54.901 89.496 55.477 ;
     RECT  63.12 54.179 64.92 55.715 ;
     RECT  36.72 54.131 39.048 55.765 ;
     RECT  40.08 54.373 41.736 55.765 ;
     RECT  44.784 53.843 46.44 55.765 ;
     RECT  47.76 54.997 48.612 55.765 ;
     RECT  83.232 55.477 89.496 55.907 ;
     RECT  94.08 55.331 94.512 55.907 ;
     RECT  95.712 55.813 95.736 55.909 ;
     RECT  69.12 55.141 70.212 55.955 ;
     RECT  90.576 55.189 91.812 55.955 ;
     RECT  36.72 55.765 41.736 56.195 ;
     RECT  69.168 55.955 70.212 56.195 ;
     RECT  74.064 55.331 78.6 56.195 ;
     RECT  95.616 55.909 95.736 56.245 ;
     RECT  96.9 53.075 97.02 56.245 ;
     RECT  72.6 55.187 73.032 56.293 ;
     RECT  95.616 56.245 97.02 56.389 ;
     RECT  88.8 55.907 89.496 56.483 ;
     RECT  71.952 56.293 73.032 56.485 ;
     RECT  90.672 55.955 91.812 56.581 ;
     RECT  94.2 55.907 94.512 56.725 ;
     RECT  95.568 56.389 97.02 56.725 ;
     RECT  94.2 56.725 97.02 56.867 ;
     RECT  83.232 55.907 86.412 56.917 ;
     RECT  90.672 56.581 92.136 56.965 ;
     RECT  80.7 55.139 81.012 57.013 ;
     RECT  83.232 56.917 87.336 57.013 ;
     RECT  83.232 57.013 87.768 57.059 ;
     RECT  44.784 55.765 48.612 57.061 ;
     RECT  44.784 57.061 48.744 57.107 ;
     RECT  38.88 56.195 41.736 57.347 ;
     RECT  38.88 57.347 38.904 57.395 ;
     RECT  42.768 54.853 43.32 57.445 ;
     RECT  87.744 57.059 87.768 57.491 ;
     RECT  63.12 55.715 64.812 57.541 ;
     RECT  71.952 56.485 73.512 57.587 ;
     RECT  90.672 56.965 92.712 57.587 ;
     RECT  39.888 57.347 41.736 57.635 ;
     RECT  63.12 57.541 65.592 57.635 ;
     RECT  71.952 57.587 72.912 57.635 ;
     RECT  95.568 56.867 97.02 57.635 ;
     RECT  88.8 56.483 89.112 57.637 ;
     RECT  32.1 53.989 35.112 57.683 ;
     RECT  47.616 57.107 48.744 57.827 ;
     RECT  91.392 57.587 92.328 57.875 ;
     RECT  69.9 56.195 70.212 57.877 ;
     RECT  40.2 57.635 41.736 57.923 ;
     RECT  88.368 57.637 89.112 57.923 ;
     RECT  94.2 56.867 94.512 57.925 ;
     RECT  88.464 57.923 89.112 58.019 ;
     RECT  94.032 57.925 94.512 58.021 ;
     RECT  29.4 55.427 29.712 58.117 ;
     RECT  32.1 57.683 33.432 58.117 ;
     RECT  64.08 57.635 65.592 58.117 ;
     RECT  74.544 56.195 78.6 58.117 ;
     RECT  91.5 57.875 92.328 58.163 ;
     RECT  69.792 57.877 70.212 58.213 ;
     RECT  34.416 57.683 35.112 58.259 ;
     RECT  29.04 58.117 29.712 58.453 ;
     RECT  0.192 53.413 0.36 58.499 ;
     RECT  44.784 57.107 46.584 58.595 ;
     RECT  68.832 58.213 70.212 58.595 ;
     RECT  80.016 57.013 81.012 58.643 ;
     RECT  44.784 58.595 46.44 58.645 ;
     RECT  94.032 58.021 95.16 58.645 ;
     RECT  96.144 57.635 97.02 58.645 ;
     RECT  42.768 57.445 43.704 58.691 ;
     RECT  28.176 58.453 29.712 58.787 ;
     RECT  40.2 57.923 41.112 58.787 ;
     RECT  94.032 58.645 97.02 58.789 ;
     RECT  94.032 58.789 97.464 58.835 ;
     RECT  31.968 58.117 33.432 58.931 ;
     RECT  50.304 54.755 62.112 58.933 ;
     RECT  50.304 58.933 62.712 59.075 ;
     RECT  83.232 57.059 86.412 59.075 ;
     RECT  42.768 58.691 43.608 59.221 ;
     RECT  94.032 58.835 94.512 59.363 ;
     RECT  71.472 58.021 71.496 59.605 ;
     RECT  91.5 58.163 91.812 59.605 ;
     RECT  71.424 59.605 71.496 59.749 ;
     RECT  32.1 58.931 33.432 59.797 ;
     RECT  34.8 58.259 35.112 59.797 ;
     RECT  40.2 58.787 40.512 59.797 ;
     RECT  50.304 59.075 62.112 59.989 ;
     RECT  28.176 58.787 28.2 60.037 ;
     RECT  26.7 2.151 27.012 60.085 ;
     RECT  74.352 58.117 78.6 60.085 ;
     RECT  69.36 58.595 70.212 60.419 ;
     RECT  74.208 60.085 78.6 60.467 ;
     RECT  71.28 59.749 71.496 60.563 ;
     RECT  40.2 59.797 40.968 60.613 ;
     RECT  42.24 59.221 43.608 60.613 ;
     RECT  26.208 60.085 27.012 60.803 ;
     RECT  98.592 59.557 98.616 60.803 ;
     RECT  40.2 60.613 43.608 60.805 ;
     RECT  44.688 58.645 46.44 60.805 ;
     RECT  40.2 60.805 46.44 60.851 ;
     RECT  30.912 60.805 30.936 60.947 ;
     RECT  94.08 59.363 94.512 60.949 ;
     RECT  95.52 58.835 97.464 60.949 ;
     RECT  32.1 59.797 35.112 61.091 ;
     RECT  94.08 60.949 97.464 61.139 ;
     RECT  91.5 59.605 91.944 61.187 ;
     RECT  32.1 61.091 33.432 61.189 ;
     RECT  85.296 59.075 86.412 61.477 ;
     RECT  87.744 60.565 87.768 61.477 ;
     RECT  34.8 61.091 35.112 61.525 ;
     RECT  85.296 61.477 87.768 61.571 ;
     RECT  41.52 60.851 46.44 61.619 ;
     RECT  72.6 57.635 72.912 61.621 ;
     RECT  94.08 61.139 97.128 61.667 ;
     RECT  83.232 59.075 84.168 61.669 ;
     RECT  47.616 57.827 48.612 61.765 ;
     RECT  95.52 61.667 97.128 61.859 ;
     RECT  90.192 58.645 90.216 61.909 ;
     RECT  91.5 61.187 91.812 61.909 ;
     RECT  69.9 60.419 70.212 61.957 ;
     RECT  71.472 60.563 71.496 61.957 ;
     RECT  69.9 61.957 71.496 62.003 ;
     RECT  67.2 55.187 67.512 62.005 ;
     RECT  26.7 60.803 27.012 62.053 ;
     RECT  24 54.755 24.312 62.149 ;
     RECT  72.48 61.621 72.912 62.149 ;
     RECT  31.584 61.189 33.432 62.195 ;
     RECT  83.184 61.669 84.168 62.195 ;
     RECT  95.52 61.859 97.02 62.195 ;
     RECT  82.08 61.525 82.104 62.435 ;
     RECT  64.08 58.117 66.072 62.437 ;
     RECT  67.2 62.005 67.608 62.437 ;
     RECT  50.16 59.989 62.112 62.579 ;
     RECT  63.744 62.437 66.072 62.629 ;
     RECT  69.9 62.003 70.728 62.629 ;
     RECT  88.8 58.019 89.112 62.629 ;
     RECT  29.4 58.787 29.712 62.677 ;
     RECT  36.72 56.195 37.812 62.677 ;
     RECT  80.7 58.643 81.012 62.677 ;
     RECT  72.48 62.149 73.032 62.723 ;
     RECT  94.08 61.667 94.512 62.723 ;
     RECT  50.304 62.579 62.112 62.725 ;
     RECT  88.416 62.629 89.112 62.725 ;
     RECT  63.648 62.629 66.072 62.771 ;
     RECT  41.52 61.619 43.32 62.773 ;
     RECT  44.688 61.619 46.44 62.773 ;
     RECT  26.208 62.053 27.012 62.819 ;
     RECT  36.72 62.677 39 62.819 ;
     RECT  83.232 62.195 84.168 62.965 ;
     RECT  85.296 61.571 87.336 62.965 ;
     RECT  36.72 62.819 38.664 63.011 ;
     RECT  41.52 62.773 46.44 63.011 ;
     RECT  50.304 62.725 62.232 63.107 ;
     RECT  29.4 62.677 30.696 63.205 ;
     RECT  90.192 61.909 91.812 63.251 ;
     RECT  29.28 63.205 30.696 63.299 ;
     RECT  63.744 62.771 66.072 63.299 ;
     RECT  69.504 62.629 70.728 63.299 ;
     RECT  34.8 61.525 35.304 63.539 ;
     RECT  69.504 63.299 70.212 63.539 ;
     RECT  83.232 62.965 87.336 63.539 ;
     RECT  26.7 62.819 27.012 63.589 ;
     RECT  28.176 60.037 28.248 63.589 ;
     RECT  88.368 62.725 89.112 63.589 ;
     RECT  90.192 63.251 90.36 63.589 ;
     RECT  34.8 63.539 35.208 63.685 ;
     RECT  67.104 62.437 67.608 63.779 ;
     RECT  88.368 63.589 90.36 63.779 ;
     RECT  24 62.149 24.84 63.781 ;
     RECT  94.2 62.723 94.512 63.781 ;
     RECT  64.08 63.299 66.072 63.829 ;
     RECT  72.48 62.723 72.912 63.875 ;
     RECT  95.904 62.195 97.02 63.875 ;
     RECT  83.28 63.539 87.336 64.163 ;
     RECT  80.352 62.677 81.012 64.213 ;
     RECT  47.616 61.765 48.984 64.309 ;
     RECT  50.304 63.107 62.112 64.309 ;
     RECT  47.616 64.309 62.112 64.357 ;
     RECT  83.28 64.163 87.096 64.403 ;
     RECT  88.704 63.779 90.36 64.403 ;
     RECT  88.704 64.403 90.216 64.451 ;
     RECT  47.616 64.357 62.76 64.501 ;
     RECT  24 63.781 25.656 64.595 ;
     RECT  47.616 64.501 62.808 64.643 ;
     RECT  82.032 62.677 82.056 64.691 ;
     RECT  41.52 63.011 43.32 64.693 ;
     RECT  44.688 63.011 46.44 64.693 ;
     RECT  36.72 63.011 37.812 64.933 ;
     RECT  94.08 63.781 94.512 64.933 ;
     RECT  83.28 64.403 84.168 64.979 ;
     RECT  91.344 63.251 91.812 64.979 ;
     RECT  96 63.875 97.02 65.027 ;
     RECT  85.296 64.403 87.096 65.125 ;
     RECT  69.9 63.539 70.212 65.173 ;
     RECT  91.5 64.979 91.812 65.269 ;
     RECT  64.08 63.829 66.216 65.363 ;
     RECT  80.112 64.213 81.012 65.363 ;
     RECT  88.8 64.451 90.216 65.365 ;
     RECT  26.7 63.589 28.248 65.413 ;
     RECT  29.28 63.299 29.712 65.461 ;
     RECT  29.28 65.461 29.832 65.507 ;
     RECT  88.8 65.365 90.408 65.507 ;
     RECT  64.08 65.363 66.072 65.509 ;
     RECT  41.52 64.693 46.44 65.603 ;
     RECT  96.768 65.027 97.02 65.603 ;
     RECT  69.792 65.173 70.212 65.653 ;
     RECT  71.28 64.357 71.304 65.653 ;
     RECT  69.792 65.653 71.304 65.699 ;
     RECT  36.72 64.933 38.328 65.939 ;
     RECT  47.616 64.643 62.76 65.939 ;
     RECT  69.792 65.699 71.112 65.941 ;
     RECT  24 64.595 24.84 65.987 ;
     RECT  91.5 65.269 92.184 65.989 ;
     RECT  83.4 64.979 84.168 66.085 ;
     RECT  29.4 65.507 29.832 66.131 ;
     RECT  34.656 63.685 35.208 66.179 ;
     RECT  93.648 64.933 94.512 66.227 ;
     RECT  91.5 65.989 92.568 66.277 ;
     RECT  80.7 65.363 81.012 66.325 ;
     RECT  83.28 66.085 84.168 66.325 ;
     RECT  88.8 65.507 90.216 66.325 ;
     RECT  83.28 66.325 84.312 66.371 ;
     RECT  88.272 66.325 90.216 66.371 ;
     RECT  69.504 65.941 71.112 66.467 ;
     RECT  72.6 63.875 72.912 66.565 ;
     RECT  32.1 62.195 33.432 66.613 ;
     RECT  85.296 65.125 87.192 66.707 ;
     RECT  63.888 65.509 66.072 66.755 ;
     RECT  91.2 66.277 92.568 66.853 ;
     RECT  91.2 66.853 92.904 66.899 ;
     RECT  47.616 65.939 48.84 67.141 ;
     RECT  83.4 66.371 84.312 67.189 ;
     RECT  85.296 66.707 87.048 67.189 ;
     RECT  83.4 67.189 87.048 67.235 ;
     RECT  36.72 65.939 38.04 67.237 ;
     RECT  24 65.987 24.552 67.283 ;
     RECT  90.192 66.371 90.216 67.285 ;
     RECT  91.2 66.899 91.812 67.285 ;
     RECT  31.968 66.613 33.432 67.331 ;
     RECT  41.52 65.603 43.368 67.333 ;
     RECT  67.2 63.779 67.608 67.381 ;
     RECT  69.504 66.467 70.212 67.523 ;
     RECT  50.304 65.939 62.112 67.525 ;
     RECT  36.72 67.237 38.184 67.669 ;
     RECT  50.304 67.525 63.096 67.715 ;
     RECT  94.08 66.227 94.512 67.717 ;
     RECT  96.9 65.603 97.02 67.765 ;
     RECT  64.08 66.755 66.072 67.813 ;
     RECT  67.2 67.381 68.28 67.813 ;
     RECT  92.88 66.899 92.904 67.907 ;
     RECT  88.272 66.371 89.112 68.101 ;
     RECT  94.08 67.717 95.16 68.101 ;
     RECT  96.192 67.765 97.02 68.101 ;
     RECT  83.4 67.235 86.664 68.147 ;
     RECT  88.272 68.101 89.208 68.147 ;
     RECT  64.08 67.813 68.28 68.149 ;
     RECT  25.92 65.413 28.248 68.197 ;
     RECT  90.192 67.285 91.812 68.197 ;
     RECT  98.592 68.101 98.616 68.291 ;
     RECT  32.1 67.331 33.432 68.341 ;
     RECT  80.7 66.325 81.24 68.389 ;
     RECT  94.08 68.101 97.02 68.435 ;
     RECT  41.52 67.333 43.56 68.485 ;
     RECT  88.32 68.147 89.208 68.533 ;
     RECT  90.192 68.197 92.472 68.533 ;
     RECT  36.432 67.669 38.184 68.675 ;
     RECT  41.52 68.485 43.704 68.675 ;
     RECT  88.32 68.533 92.472 68.675 ;
     RECT  29.4 66.131 29.712 68.917 ;
     RECT  47.616 67.141 48.936 68.917 ;
     RECT  72.192 66.565 72.912 68.917 ;
     RECT  94.08 68.435 94.512 68.917 ;
     RECT  21.3 2.151 21.612 68.965 ;
     RECT  31.248 68.341 33.432 69.203 ;
     RECT  88.32 68.675 89.208 69.251 ;
     RECT  50.304 67.715 62.424 69.301 ;
     RECT  93.456 68.917 94.512 69.395 ;
     RECT  94.2 69.395 94.512 69.397 ;
     RECT  95.712 68.435 97.02 69.397 ;
     RECT  88.32 69.251 89.112 69.493 ;
     RECT  21.3 68.965 22.296 69.539 ;
     RECT  36.72 68.675 38.184 69.539 ;
     RECT  72.192 68.917 73.032 69.683 ;
     RECT  44.688 65.603 46.44 69.781 ;
     RECT  47.616 68.917 49.032 69.781 ;
     RECT  25.584 68.197 28.248 69.973 ;
     RECT  40.2 60.851 40.512 70.069 ;
     RECT  41.52 68.675 43.56 70.069 ;
     RECT  40.2 70.069 43.56 70.259 ;
     RECT  72.192 69.683 72.912 70.261 ;
     RECT  69.792 67.523 70.212 70.307 ;
     RECT  44.688 69.781 49.032 70.309 ;
     RECT  50.112 69.301 62.424 70.309 ;
     RECT  74.592 60.467 78.6 70.309 ;
     RECT  32.1 69.203 33.432 70.357 ;
     RECT  34.656 66.179 35.112 70.357 ;
     RECT  63.504 68.149 68.28 70.357 ;
     RECT  83.4 68.147 86.568 70.357 ;
     RECT  69.9 70.307 70.212 70.405 ;
     RECT  29.4 68.917 29.832 70.595 ;
     RECT  94.2 69.397 97.02 70.645 ;
     RECT  25.536 69.973 28.248 70.739 ;
     RECT  40.2 70.259 43.32 70.789 ;
     RECT  88.176 69.493 89.112 70.835 ;
     RECT  93.696 70.645 97.02 70.931 ;
     RECT  90.192 68.675 92.472 70.933 ;
     RECT  83.4 70.357 86.664 71.221 ;
     RECT  69.9 70.405 70.68 71.315 ;
     RECT  63.504 70.357 68.376 71.459 ;
     RECT  98.592 71.365 98.616 71.555 ;
     RECT  40.08 70.789 43.32 71.939 ;
     RECT  82.992 71.221 86.664 71.989 ;
     RECT  36.72 69.539 37.944 72.179 ;
     RECT  40.2 71.939 43.32 72.181 ;
     RECT  44.688 70.309 62.424 72.181 ;
     RECT  32.1 70.357 35.112 72.277 ;
     RECT  94.2 70.931 97.02 72.277 ;
     RECT  90.192 70.933 92.664 72.325 ;
     RECT  94.2 72.277 97.464 72.325 ;
     RECT  71.664 70.261 72.912 72.469 ;
     RECT  74.016 70.309 78.6 72.469 ;
     RECT  80.7 68.389 81.672 72.565 ;
     RECT  82.992 71.989 86.904 72.565 ;
     RECT  40.2 72.181 62.424 72.709 ;
     RECT  63.504 71.459 68.328 72.709 ;
     RECT  88.32 70.835 89.112 72.805 ;
     RECT  90.192 72.325 97.464 72.805 ;
     RECT  80.7 72.565 86.904 72.853 ;
     RECT  88.32 72.805 97.464 72.947 ;
     RECT  91.5 72.947 97.464 73.043 ;
     RECT  38.976 71.221 39 73.091 ;
     RECT  71.664 72.469 78.6 73.091 ;
     RECT  80.592 72.853 86.904 73.333 ;
     RECT  31.2 72.277 35.112 73.571 ;
     RECT  96 73.043 97.464 73.571 ;
     RECT  91.5 73.043 94.512 73.619 ;
     RECT  96 73.571 97.128 73.619 ;
     RECT  80.592 73.333 87.192 73.909 ;
     RECT  32.1 73.571 35.112 74.053 ;
     RECT  36.72 72.179 37.812 74.053 ;
     RECT  80.544 73.909 87.192 74.147 ;
     RECT  40.2 72.709 68.328 74.149 ;
     RECT  40.2 74.149 68.568 74.387 ;
     RECT  92.88 73.619 94.512 74.437 ;
     RECT  80.544 74.147 86.664 74.483 ;
     RECT  96.048 73.619 97.128 74.579 ;
     RECT  96.048 74.579 97.02 74.581 ;
     RECT  91.5 73.619 91.812 74.629 ;
     RECT  92.88 74.437 94.632 74.629 ;
     RECT  88.32 72.947 90.216 74.677 ;
     RECT  88.32 74.677 90.312 74.867 ;
     RECT  74.592 73.091 78.6 74.869 ;
     RECT  88.8 74.867 90.312 74.917 ;
     RECT  91.5 74.629 94.632 74.917 ;
     RECT  32.1 74.053 37.812 75.155 ;
     RECT  80.7 74.483 86.664 75.251 ;
     RECT  69.9 71.315 70.212 75.253 ;
     RECT  74.592 74.869 79.08 75.253 ;
     RECT  80.7 75.251 81.672 75.299 ;
     RECT  74.592 75.253 79.56 75.445 ;
     RECT  80.7 75.299 81.144 75.445 ;
     RECT  0.192 58.499 0.216 75.491 ;
     RECT  30.816 75.109 30.84 75.731 ;
     RECT  69.9 75.253 70.344 75.779 ;
     RECT  74.592 75.445 81.144 75.827 ;
     RECT  98.592 75.445 98.616 75.827 ;
     RECT  88.8 74.917 94.632 75.875 ;
     RECT  95.712 74.581 97.02 75.875 ;
     RECT  88.8 75.875 92.904 75.923 ;
     RECT  32.1 75.155 35.64 75.971 ;
     RECT  40.2 74.387 68.328 76.067 ;
     RECT  83.4 75.251 86.664 76.309 ;
     RECT  96.048 75.875 97.02 76.403 ;
     RECT  71.664 73.091 73.368 76.499 ;
     RECT  80.592 75.827 81.144 76.739 ;
     RECT  94.2 75.875 94.632 76.837 ;
     RECT  40.2 76.067 62.112 76.885 ;
     RECT  83.28 76.309 86.664 76.885 ;
     RECT  92.88 75.923 92.904 76.979 ;
     RECT  94.2 76.837 94.68 76.981 ;
     RECT  88.8 75.923 91.812 77.555 ;
     RECT  71.664 76.499 73.032 77.891 ;
     RECT  63.504 76.067 68.328 77.893 ;
     RECT  69.9 75.779 70.212 77.941 ;
     RECT  74.592 75.827 79.08 78.085 ;
     RECT  94.08 76.981 94.68 78.131 ;
     RECT  63.504 77.893 68.904 78.133 ;
     RECT  69.9 77.941 70.344 78.133 ;
     RECT  40.08 76.885 62.112 78.179 ;
     RECT  83.28 76.885 87.24 78.179 ;
     RECT  83.4 78.179 87.24 78.181 ;
     RECT  96.144 76.403 97.02 78.565 ;
     RECT  63.504 78.133 70.344 78.707 ;
     RECT  94.08 78.131 94.632 78.707 ;
     RECT  96.144 78.565 97.128 78.755 ;
     RECT  80.592 76.739 81.012 78.901 ;
     RECT  41.52 78.179 62.112 79.139 ;
     RECT  63.504 78.707 67.8 79.187 ;
     RECT  68.928 78.707 70.344 79.235 ;
     RECT  96.288 78.755 97.128 79.283 ;
     RECT  68.928 79.235 70.212 79.475 ;
     RECT  98.592 79.429 98.616 79.619 ;
     RECT  74.112 78.085 79.08 79.717 ;
     RECT  80.4 78.901 81.012 79.717 ;
     RECT  92.88 78.181 92.904 79.955 ;
     RECT  96.528 79.283 97.128 80.197 ;
     RECT  40.08 78.179 40.512 80.245 ;
     RECT  41.52 79.139 43.56 80.245 ;
     RECT  94.08 78.707 94.512 80.245 ;
     RECT  40.08 80.245 43.56 80.291 ;
     RECT  74.112 79.717 81.012 80.435 ;
     RECT  93.936 80.245 94.512 80.629 ;
     RECT  63.504 79.187 67.512 80.917 ;
     RECT  83.4 78.181 87.336 80.917 ;
     RECT  82.752 80.917 87.336 81.205 ;
     RECT  88.8 77.555 89.112 81.205 ;
     RECT  40.2 80.291 43.56 81.347 ;
     RECT  82.752 81.205 89.112 81.395 ;
     RECT  93.456 80.629 94.512 81.445 ;
     RECT  63.312 80.917 67.512 81.539 ;
     RECT  93.456 81.445 94.632 81.539 ;
     RECT  68.784 79.765 68.808 81.589 ;
     RECT  69.9 79.475 70.212 81.589 ;
     RECT  41.52 81.347 43.56 81.635 ;
     RECT  68.784 81.589 70.212 81.635 ;
     RECT  85.296 81.395 89.112 81.683 ;
     RECT  69.264 81.635 70.212 81.685 ;
     RECT  71.664 77.891 72.912 81.685 ;
     RECT  74.592 80.435 78.6 81.685 ;
     RECT  69.264 81.685 72.912 81.731 ;
     RECT  96.528 80.197 97.464 82.021 ;
     RECT  93.984 81.539 94.632 82.115 ;
     RECT  82.752 81.395 84.168 82.211 ;
     RECT  94.032 82.115 94.632 82.211 ;
     RECT  96.288 82.021 97.464 82.211 ;
     RECT  79.776 80.435 81.012 82.403 ;
     RECT  87.744 81.683 89.112 82.451 ;
     RECT  69.9 81.731 72.912 82.453 ;
     RECT  83.136 82.211 84.168 82.501 ;
     RECT  85.296 81.683 86.412 82.501 ;
     RECT  44.832 79.139 62.112 82.597 ;
     RECT  96.288 82.211 97.02 82.597 ;
     RECT  74.496 81.685 78.6 82.885 ;
     RECT  41.52 81.635 43.32 82.981 ;
     RECT  44.352 82.597 62.112 82.981 ;
     RECT  63.504 81.539 67.512 82.981 ;
     RECT  74.496 82.885 78.696 83.027 ;
     RECT  40.2 81.347 40.512 83.077 ;
     RECT  41.52 82.981 62.112 83.077 ;
     RECT  80.7 82.403 81.012 83.173 ;
     RECT  83.136 82.501 86.412 83.267 ;
     RECT  94.032 82.211 94.512 83.267 ;
     RECT  87.744 82.451 87.768 83.363 ;
     RECT  40.2 83.077 62.112 83.749 ;
     RECT  69.9 82.453 73.368 83.797 ;
     RECT  80.7 83.173 81.144 83.797 ;
     RECT  40.2 83.749 62.52 83.843 ;
     RECT  69.9 83.797 73.416 83.843 ;
     RECT  74.496 83.027 78.648 84.035 ;
     RECT  83.136 83.267 84.168 84.037 ;
     RECT  71.664 83.843 73.416 84.085 ;
     RECT  74.496 84.035 78.6 84.085 ;
     RECT  88.8 82.451 89.112 84.325 ;
     RECT  63.504 82.981 67.608 84.419 ;
     RECT  96.24 82.597 97.02 84.419 ;
     RECT  41.52 83.843 62.52 84.707 ;
     RECT  82.992 84.037 84.168 84.901 ;
     RECT  85.2 83.267 86.412 84.901 ;
     RECT  61.392 84.707 62.52 84.947 ;
     RECT  82.992 84.901 86.412 85.381 ;
     RECT  88.704 84.325 89.112 85.427 ;
     RECT  82.8 85.381 86.412 85.429 ;
     RECT  88.8 85.427 89.112 85.813 ;
     RECT  80.7 83.797 81.72 85.907 ;
     RECT  69.9 83.843 70.212 85.957 ;
     RECT  68.928 85.957 70.212 86.197 ;
     RECT  71.664 84.085 78.6 86.197 ;
     RECT  82.8 85.429 86.568 86.483 ;
     RECT  82.8 86.483 84.168 86.533 ;
     RECT  68.928 86.197 78.6 86.675 ;
     RECT  41.52 84.707 60.12 86.869 ;
     RECT  61.392 84.947 62.232 86.869 ;
     RECT  69.9 86.675 78.6 87.011 ;
     RECT  85.296 86.483 86.568 87.013 ;
     RECT  41.52 86.869 62.232 87.781 ;
     RECT  63.504 84.419 67.512 87.781 ;
     RECT  85.296 87.013 86.616 88.067 ;
     RECT  82.512 86.533 84.168 88.213 ;
     RECT  85.296 88.067 86.568 88.213 ;
     RECT  69.9 87.011 70.212 88.885 ;
     RECT  41.52 87.781 67.512 88.979 ;
     RECT  82.512 88.213 86.568 89.123 ;
     RECT  63.504 88.979 67.512 89.173 ;
     RECT  83.4 89.123 86.568 89.219 ;
     RECT  88.8 85.813 89.208 89.315 ;
     RECT  41.52 88.979 62.112 89.363 ;
     RECT  90.192 77.555 91.812 89.411 ;
     RECT  85.296 89.219 86.568 89.459 ;
     RECT  69.9 88.885 70.68 90.035 ;
     RECT  63.504 89.173 67.608 90.275 ;
     RECT  63.504 90.275 67.512 91.429 ;
     RECT  90.192 89.411 90.216 91.475 ;
     RECT  63.504 91.429 67.896 91.717 ;
     RECT  69.9 90.035 70.212 91.765 ;
     RECT  71.664 87.011 78.6 91.765 ;
     RECT  85.296 89.459 86.412 91.907 ;
     RECT  69.9 91.765 78.6 92.245 ;
     RECT  29.4 70.595 29.712 92.293 ;
     RECT  32.1 75.971 35.112 92.293 ;
     RECT  24 67.283 24.312 92.773 ;
     RECT  29.4 92.293 30.504 92.917 ;
     RECT  31.488 92.293 35.112 92.917 ;
     RECT  40.2 83.843 40.512 92.917 ;
     RECT  41.52 89.363 60.12 92.917 ;
     RECT  63.504 91.717 68.376 92.917 ;
     RECT  69.792 92.245 78.6 92.917 ;
     RECT  24 92.773 24.504 92.963 ;
     RECT  25.92 70.739 28.248 92.965 ;
     RECT  29.4 92.917 35.112 92.965 ;
     RECT  25.92 92.965 35.112 93.061 ;
     RECT  40.2 92.917 60.12 93.299 ;
     RECT  25.632 93.061 35.112 93.445 ;
     RECT  61.392 89.363 62.112 93.445 ;
     RECT  63.504 92.917 78.6 93.445 ;
     RECT  25.584 93.445 35.112 93.539 ;
     RECT  83.4 89.219 84.168 93.779 ;
     RECT  61.392 93.445 78.6 93.971 ;
     RECT  24 92.963 24.312 93.973 ;
     RECT  24 93.973 24.456 94.021 ;
     RECT  25.584 93.539 25.656 94.021 ;
     RECT  36.72 75.155 37.812 94.021 ;
     RECT  23.328 94.021 25.656 94.307 ;
     RECT  26.7 93.539 35.112 94.307 ;
     RECT  61.392 93.971 76.776 94.355 ;
     RECT  23.328 94.307 24.312 94.597 ;
     RECT  28.944 94.307 35.112 94.597 ;
     RECT  36.432 94.021 37.812 94.597 ;
     RECT  26.7 94.307 27.528 94.643 ;
     RECT  41.52 93.299 60.12 94.643 ;
     RECT  63.504 94.355 76.776 94.643 ;
     RECT  22.8 94.597 24.312 94.739 ;
     RECT  77.856 93.971 78.6 94.787 ;
     RECT  28.944 94.597 37.812 95.219 ;
     RECT  41.52 94.643 46.104 95.219 ;
     RECT  47.808 94.643 60.12 95.219 ;
     RECT  47.904 95.219 60.12 95.267 ;
     RECT  63.504 94.643 76.584 95.267 ;
     RECT  61.392 94.355 62.112 95.411 ;
     RECT  63.504 95.267 65.496 95.507 ;
     RECT  28.944 95.219 33.672 95.795 ;
     RECT  66.672 95.267 76.584 95.795 ;
     RECT  77.856 94.787 78.312 95.795 ;
     RECT  23.328 94.739 24.312 95.797 ;
     RECT  25.392 94.307 25.656 95.797 ;
     RECT  58.512 95.267 60.12 96.035 ;
     RECT  23.328 95.797 25.656 96.179 ;
     RECT  34.8 95.219 36.456 96.179 ;
     RECT  23.328 96.179 25.608 96.325 ;
     RECT  33.408 95.795 33.672 96.371 ;
     RECT  42.9 95.219 46.104 96.371 ;
     RECT  34.8 96.179 36.024 96.419 ;
     RECT  33.408 96.371 33.432 96.515 ;
     RECT  41.52 95.219 41.544 96.515 ;
     RECT  44.256 96.371 44.28 96.515 ;
     RECT  58.512 96.035 59.412 96.563 ;
     RECT  40.2 93.299 40.512 96.661 ;
     RECT  47.904 95.267 57.24 96.661 ;
     RECT  45.6 96.371 46.104 96.755 ;
     RECT  64.128 95.507 65.496 96.755 ;
     RECT  64.272 96.755 65.496 96.805 ;
     RECT  66.672 95.795 76.296 96.805 ;
     RECT  39.36 96.661 40.512 96.851 ;
     RECT  47.904 96.661 57.336 96.851 ;
     RECT  47.952 96.851 57.336 96.853 ;
     RECT  64.272 96.805 76.296 96.853 ;
     RECT  2.4 2.151 2.712 96.939 ;
     RECT  5.1 2.151 5.412 96.939 ;
     RECT  7.8 2.151 8.112 96.939 ;
     RECT  10.5 2.151 10.812 96.939 ;
     RECT  13.2 2.151 13.512 96.939 ;
     RECT  15.9 2.151 16.212 96.939 ;
     RECT  18.6 2.151 18.912 96.939 ;
     RECT  21.3 69.539 21.612 96.939 ;
     RECT  26.7 94.643 27.012 96.939 ;
     RECT  34.8 96.419 35.112 96.939 ;
     RECT  37.5 95.219 37.812 96.939 ;
     RECT  40.2 96.851 40.512 96.939 ;
     RECT  42.9 96.371 43.212 96.939 ;
     RECT  45.6 96.755 45.912 96.939 ;
     RECT  59.1 96.563 59.412 96.939 ;
     RECT  61.8 95.411 62.112 96.939 ;
     RECT  78 95.795 78.312 96.939 ;
     RECT  80.7 85.907 81.012 96.939 ;
     RECT  83.4 93.779 83.712 96.939 ;
     RECT  86.1 91.907 86.412 96.939 ;
     RECT  88.8 89.315 89.112 96.939 ;
     RECT  91.5 89.411 91.812 96.939 ;
     RECT  94.2 83.267 94.512 96.939 ;
     RECT  96.9 84.419 97.02 96.939 ;
     RECT  2.592 96.939 2.712 96.953 ;
     RECT  5.292 96.939 5.412 96.953 ;
     RECT  7.992 96.939 8.112 96.953 ;
     RECT  10.692 96.939 10.812 96.953 ;
     RECT  13.392 96.939 13.512 96.953 ;
     RECT  16.092 96.939 16.212 96.953 ;
     RECT  18.792 96.939 18.912 96.953 ;
     RECT  21.492 96.939 21.612 96.953 ;
     RECT  26.892 96.939 27.012 96.953 ;
     RECT  28.944 95.795 32.412 96.953 ;
     RECT  34.992 96.939 35.112 96.953 ;
     RECT  37.692 96.939 37.812 96.953 ;
     RECT  40.392 96.939 40.512 96.953 ;
     RECT  43.092 96.939 43.212 96.953 ;
     RECT  45.792 96.939 45.912 96.953 ;
     RECT  59.292 96.939 59.412 96.953 ;
     RECT  61.992 96.939 62.112 96.953 ;
     RECT  78.192 96.939 78.312 96.953 ;
     RECT  80.892 96.939 81.012 96.953 ;
     RECT  83.592 96.939 83.712 96.953 ;
     RECT  86.292 96.939 86.412 96.953 ;
     RECT  88.992 96.939 89.112 96.953 ;
     RECT  91.692 96.939 91.812 96.953 ;
     RECT  94.392 96.939 94.512 96.953 ;
     RECT  47.952 96.853 57.432 97.091 ;
     RECT  22.704 96.325 25.608 97.429 ;
     RECT  64.272 96.853 76.392 98.005 ;
     RECT  28.944 96.953 31.752 98.053 ;
     RECT  64.176 98.005 76.392 98.579 ;
     RECT  64.176 98.579 76.296 98.581 ;
     RECT  28.848 98.053 31.752 99.205 ;
     RECT  22.608 97.429 25.608 99.28 ;
     RECT  28.752 99.205 31.752 99.28 ;
     RECT  47.952 97.091 57.096 99.28 ;
     RECT  64.08 98.581 76.296 99.28 ;
  END
END qfd_landh_548_EN_99x99
END LIBRARY
